VERSION 5.8 ;
BUSBITCHARS "[]" ;
DIVIDERCHAR "/" ;
UNITS
    DATABASE MICRONS 1000 ;
END UNITS

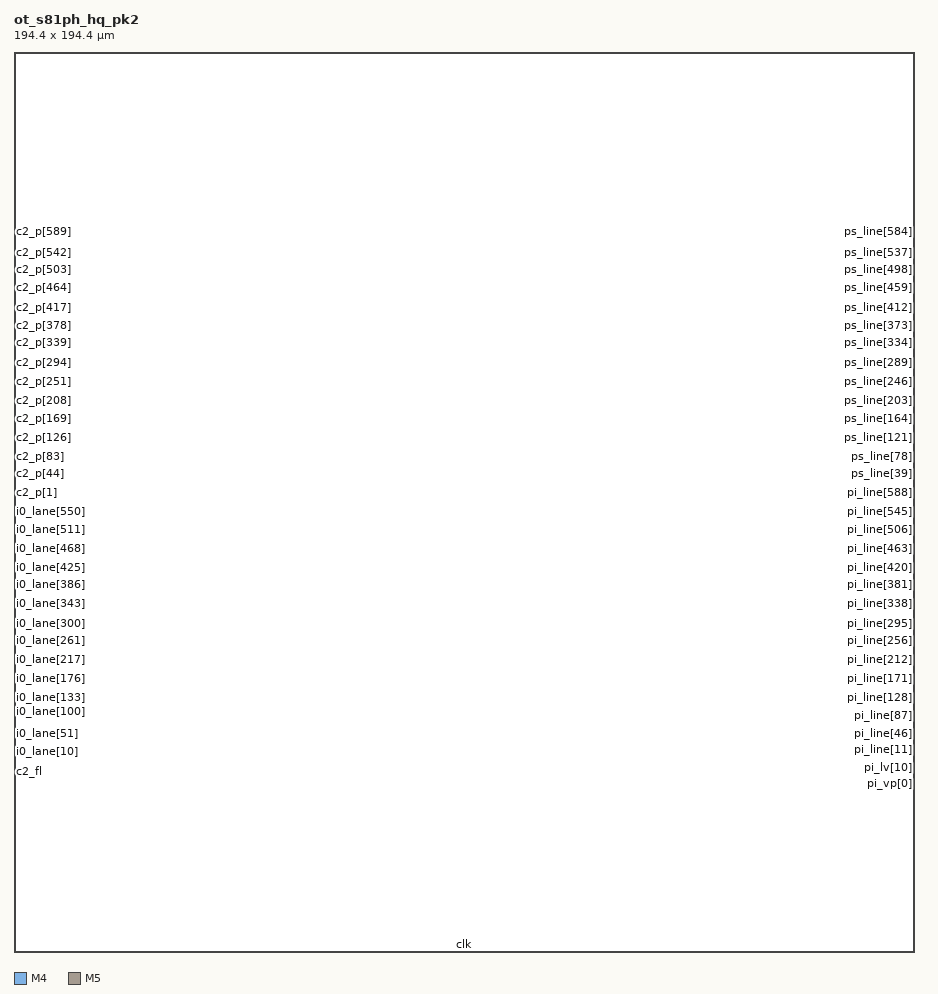
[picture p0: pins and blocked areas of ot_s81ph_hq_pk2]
MACRO ot_s81ph_hq_pk2
  FOREIGN ot_s81ph_hq_pk2 0 0 ;
  CLASS BLOCK ;
  SIZE 194.4 BY 194.4 ;
  PIN c2_fl
    DIRECTION INPUT ;
    USE SIGNAL ;
    PORT
      LAYER M4 ;
        RECT  0 39.072 0.084 39.096 ;
    END
  END c2_fl
  PIN c2_p[0]
    DIRECTION INPUT ;
    USE SIGNAL ;
    PORT
      LAYER M4 ;
        RECT  0 99.072 0.084 99.096 ;
    END
  END c2_p[0]
  PIN c2_p[100]
    DIRECTION INPUT ;
    USE SIGNAL ;
    PORT
      LAYER M4 ;
        RECT  0 108.672 0.084 108.696 ;
    END
  END c2_p[100]
  PIN c2_p[101]
    DIRECTION INPUT ;
    USE SIGNAL ;
    PORT
      LAYER M4 ;
        RECT  0 108.768 0.084 108.792 ;
    END
  END c2_p[101]
  PIN c2_p[102]
    DIRECTION INPUT ;
    USE SIGNAL ;
    PORT
      LAYER M4 ;
        RECT  0 108.864 0.084 108.888 ;
    END
  END c2_p[102]
  PIN c2_p[103]
    DIRECTION INPUT ;
    USE SIGNAL ;
    PORT
      LAYER M4 ;
        RECT  0 108.96 0.084 108.984 ;
    END
  END c2_p[103]
  PIN c2_p[104]
    DIRECTION INPUT ;
    USE SIGNAL ;
    PORT
      LAYER M4 ;
        RECT  0 109.056 0.084 109.08 ;
    END
  END c2_p[104]
  PIN c2_p[105]
    DIRECTION INPUT ;
    USE SIGNAL ;
    PORT
      LAYER M4 ;
        RECT  0 109.152 0.084 109.176 ;
    END
  END c2_p[105]
  PIN c2_p[106]
    DIRECTION INPUT ;
    USE SIGNAL ;
    PORT
      LAYER M4 ;
        RECT  0 109.248 0.084 109.272 ;
    END
  END c2_p[106]
  PIN c2_p[107]
    DIRECTION INPUT ;
    USE SIGNAL ;
    PORT
      LAYER M4 ;
        RECT  0 109.344 0.084 109.368 ;
    END
  END c2_p[107]
  PIN c2_p[108]
    DIRECTION INPUT ;
    USE SIGNAL ;
    PORT
      LAYER M4 ;
        RECT  0 109.44 0.084 109.464 ;
    END
  END c2_p[108]
  PIN c2_p[109]
    DIRECTION INPUT ;
    USE SIGNAL ;
    PORT
      LAYER M4 ;
        RECT  0 109.536 0.084 109.56 ;
    END
  END c2_p[109]
  PIN c2_p[10]
    DIRECTION INPUT ;
    USE SIGNAL ;
    PORT
      LAYER M4 ;
        RECT  0 100.032 0.084 100.056 ;
    END
  END c2_p[10]
  PIN c2_p[110]
    DIRECTION INPUT ;
    USE SIGNAL ;
    PORT
      LAYER M4 ;
        RECT  0 109.632 0.084 109.656 ;
    END
  END c2_p[110]
  PIN c2_p[111]
    DIRECTION INPUT ;
    USE SIGNAL ;
    PORT
      LAYER M4 ;
        RECT  0 109.728 0.084 109.752 ;
    END
  END c2_p[111]
  PIN c2_p[112]
    DIRECTION INPUT ;
    USE SIGNAL ;
    PORT
      LAYER M4 ;
        RECT  0 109.824 0.084 109.848 ;
    END
  END c2_p[112]
  PIN c2_p[113]
    DIRECTION INPUT ;
    USE SIGNAL ;
    PORT
      LAYER M4 ;
        RECT  0 109.92 0.084 109.944 ;
    END
  END c2_p[113]
  PIN c2_p[114]
    DIRECTION INPUT ;
    USE SIGNAL ;
    PORT
      LAYER M4 ;
        RECT  0 110.016 0.084 110.04 ;
    END
  END c2_p[114]
  PIN c2_p[115]
    DIRECTION INPUT ;
    USE SIGNAL ;
    PORT
      LAYER M4 ;
        RECT  0 110.112 0.084 110.136 ;
    END
  END c2_p[115]
  PIN c2_p[116]
    DIRECTION INPUT ;
    USE SIGNAL ;
    PORT
      LAYER M4 ;
        RECT  0 110.208 0.084 110.232 ;
    END
  END c2_p[116]
  PIN c2_p[117]
    DIRECTION INPUT ;
    USE SIGNAL ;
    PORT
      LAYER M4 ;
        RECT  0 110.304 0.084 110.328 ;
    END
  END c2_p[117]
  PIN c2_p[118]
    DIRECTION INPUT ;
    USE SIGNAL ;
    PORT
      LAYER M4 ;
        RECT  0 110.4 0.084 110.424 ;
    END
  END c2_p[118]
  PIN c2_p[119]
    DIRECTION INPUT ;
    USE SIGNAL ;
    PORT
      LAYER M4 ;
        RECT  0 110.496 0.084 110.52 ;
    END
  END c2_p[119]
  PIN c2_p[11]
    DIRECTION INPUT ;
    USE SIGNAL ;
    PORT
      LAYER M4 ;
        RECT  0 100.128 0.084 100.152 ;
    END
  END c2_p[11]
  PIN c2_p[120]
    DIRECTION INPUT ;
    USE SIGNAL ;
    PORT
      LAYER M4 ;
        RECT  0 110.592 0.084 110.616 ;
    END
  END c2_p[120]
  PIN c2_p[121]
    DIRECTION INPUT ;
    USE SIGNAL ;
    PORT
      LAYER M4 ;
        RECT  0 110.688 0.084 110.712 ;
    END
  END c2_p[121]
  PIN c2_p[122]
    DIRECTION INPUT ;
    USE SIGNAL ;
    PORT
      LAYER M4 ;
        RECT  0 110.784 0.084 110.808 ;
    END
  END c2_p[122]
  PIN c2_p[123]
    DIRECTION INPUT ;
    USE SIGNAL ;
    PORT
      LAYER M4 ;
        RECT  0 110.88 0.084 110.904 ;
    END
  END c2_p[123]
  PIN c2_p[124]
    DIRECTION INPUT ;
    USE SIGNAL ;
    PORT
      LAYER M4 ;
        RECT  0 110.976 0.084 111 ;
    END
  END c2_p[124]
  PIN c2_p[125]
    DIRECTION INPUT ;
    USE SIGNAL ;
    PORT
      LAYER M4 ;
        RECT  0 111.072 0.084 111.096 ;
    END
  END c2_p[125]
  PIN c2_p[126]
    DIRECTION INPUT ;
    USE SIGNAL ;
    PORT
      LAYER M4 ;
        RECT  0 111.168 0.084 111.192 ;
    END
  END c2_p[126]
  PIN c2_p[127]
    DIRECTION INPUT ;
    USE SIGNAL ;
    PORT
      LAYER M4 ;
        RECT  0 111.264 0.084 111.288 ;
    END
  END c2_p[127]
  PIN c2_p[128]
    DIRECTION INPUT ;
    USE SIGNAL ;
    PORT
      LAYER M4 ;
        RECT  0 111.36 0.084 111.384 ;
    END
  END c2_p[128]
  PIN c2_p[129]
    DIRECTION INPUT ;
    USE SIGNAL ;
    PORT
      LAYER M4 ;
        RECT  0 111.456 0.084 111.48 ;
    END
  END c2_p[129]
  PIN c2_p[12]
    DIRECTION INPUT ;
    USE SIGNAL ;
    PORT
      LAYER M4 ;
        RECT  0 100.224 0.084 100.248 ;
    END
  END c2_p[12]
  PIN c2_p[130]
    DIRECTION INPUT ;
    USE SIGNAL ;
    PORT
      LAYER M4 ;
        RECT  0 111.552 0.084 111.576 ;
    END
  END c2_p[130]
  PIN c2_p[131]
    DIRECTION INPUT ;
    USE SIGNAL ;
    PORT
      LAYER M4 ;
        RECT  0 111.648 0.084 111.672 ;
    END
  END c2_p[131]
  PIN c2_p[132]
    DIRECTION INPUT ;
    USE SIGNAL ;
    PORT
      LAYER M4 ;
        RECT  0 111.744 0.084 111.768 ;
    END
  END c2_p[132]
  PIN c2_p[133]
    DIRECTION INPUT ;
    USE SIGNAL ;
    PORT
      LAYER M4 ;
        RECT  0 111.84 0.084 111.864 ;
    END
  END c2_p[133]
  PIN c2_p[134]
    DIRECTION INPUT ;
    USE SIGNAL ;
    PORT
      LAYER M4 ;
        RECT  0 111.936 0.084 111.96 ;
    END
  END c2_p[134]
  PIN c2_p[135]
    DIRECTION INPUT ;
    USE SIGNAL ;
    PORT
      LAYER M4 ;
        RECT  0 112.032 0.084 112.056 ;
    END
  END c2_p[135]
  PIN c2_p[136]
    DIRECTION INPUT ;
    USE SIGNAL ;
    PORT
      LAYER M4 ;
        RECT  0 112.128 0.084 112.152 ;
    END
  END c2_p[136]
  PIN c2_p[137]
    DIRECTION INPUT ;
    USE SIGNAL ;
    PORT
      LAYER M4 ;
        RECT  0 112.224 0.084 112.248 ;
    END
  END c2_p[137]
  PIN c2_p[138]
    DIRECTION INPUT ;
    USE SIGNAL ;
    PORT
      LAYER M4 ;
        RECT  0 112.32 0.084 112.344 ;
    END
  END c2_p[138]
  PIN c2_p[139]
    DIRECTION INPUT ;
    USE SIGNAL ;
    PORT
      LAYER M4 ;
        RECT  0 112.416 0.084 112.44 ;
    END
  END c2_p[139]
  PIN c2_p[13]
    DIRECTION INPUT ;
    USE SIGNAL ;
    PORT
      LAYER M4 ;
        RECT  0 100.32 0.084 100.344 ;
    END
  END c2_p[13]
  PIN c2_p[140]
    DIRECTION INPUT ;
    USE SIGNAL ;
    PORT
      LAYER M4 ;
        RECT  0 112.512 0.084 112.536 ;
    END
  END c2_p[140]
  PIN c2_p[141]
    DIRECTION INPUT ;
    USE SIGNAL ;
    PORT
      LAYER M4 ;
        RECT  0 112.608 0.084 112.632 ;
    END
  END c2_p[141]
  PIN c2_p[142]
    DIRECTION INPUT ;
    USE SIGNAL ;
    PORT
      LAYER M4 ;
        RECT  0 112.704 0.084 112.728 ;
    END
  END c2_p[142]
  PIN c2_p[143]
    DIRECTION INPUT ;
    USE SIGNAL ;
    PORT
      LAYER M4 ;
        RECT  0 112.8 0.084 112.824 ;
    END
  END c2_p[143]
  PIN c2_p[144]
    DIRECTION INPUT ;
    USE SIGNAL ;
    PORT
      LAYER M4 ;
        RECT  0 112.896 0.084 112.92 ;
    END
  END c2_p[144]
  PIN c2_p[145]
    DIRECTION INPUT ;
    USE SIGNAL ;
    PORT
      LAYER M4 ;
        RECT  0 112.992 0.084 113.016 ;
    END
  END c2_p[145]
  PIN c2_p[146]
    DIRECTION INPUT ;
    USE SIGNAL ;
    PORT
      LAYER M4 ;
        RECT  0 113.088 0.084 113.112 ;
    END
  END c2_p[146]
  PIN c2_p[147]
    DIRECTION INPUT ;
    USE SIGNAL ;
    PORT
      LAYER M4 ;
        RECT  0 113.184 0.084 113.208 ;
    END
  END c2_p[147]
  PIN c2_p[148]
    DIRECTION INPUT ;
    USE SIGNAL ;
    PORT
      LAYER M4 ;
        RECT  0 113.28 0.084 113.304 ;
    END
  END c2_p[148]
  PIN c2_p[149]
    DIRECTION INPUT ;
    USE SIGNAL ;
    PORT
      LAYER M4 ;
        RECT  0 113.376 0.084 113.4 ;
    END
  END c2_p[149]
  PIN c2_p[14]
    DIRECTION INPUT ;
    USE SIGNAL ;
    PORT
      LAYER M4 ;
        RECT  0 100.416 0.084 100.44 ;
    END
  END c2_p[14]
  PIN c2_p[150]
    DIRECTION INPUT ;
    USE SIGNAL ;
    PORT
      LAYER M4 ;
        RECT  0 113.472 0.084 113.496 ;
    END
  END c2_p[150]
  PIN c2_p[151]
    DIRECTION INPUT ;
    USE SIGNAL ;
    PORT
      LAYER M4 ;
        RECT  0 113.568 0.084 113.592 ;
    END
  END c2_p[151]
  PIN c2_p[152]
    DIRECTION INPUT ;
    USE SIGNAL ;
    PORT
      LAYER M4 ;
        RECT  0 113.664 0.084 113.688 ;
    END
  END c2_p[152]
  PIN c2_p[153]
    DIRECTION INPUT ;
    USE SIGNAL ;
    PORT
      LAYER M4 ;
        RECT  0 113.76 0.084 113.784 ;
    END
  END c2_p[153]
  PIN c2_p[154]
    DIRECTION INPUT ;
    USE SIGNAL ;
    PORT
      LAYER M4 ;
        RECT  0 113.856 0.084 113.88 ;
    END
  END c2_p[154]
  PIN c2_p[155]
    DIRECTION INPUT ;
    USE SIGNAL ;
    PORT
      LAYER M4 ;
        RECT  0 113.952 0.084 113.976 ;
    END
  END c2_p[155]
  PIN c2_p[156]
    DIRECTION INPUT ;
    USE SIGNAL ;
    PORT
      LAYER M4 ;
        RECT  0 114.048 0.084 114.072 ;
    END
  END c2_p[156]
  PIN c2_p[157]
    DIRECTION INPUT ;
    USE SIGNAL ;
    PORT
      LAYER M4 ;
        RECT  0 114.144 0.084 114.168 ;
    END
  END c2_p[157]
  PIN c2_p[158]
    DIRECTION INPUT ;
    USE SIGNAL ;
    PORT
      LAYER M4 ;
        RECT  0 114.24 0.084 114.264 ;
    END
  END c2_p[158]
  PIN c2_p[159]
    DIRECTION INPUT ;
    USE SIGNAL ;
    PORT
      LAYER M4 ;
        RECT  0 114.336 0.084 114.36 ;
    END
  END c2_p[159]
  PIN c2_p[15]
    DIRECTION INPUT ;
    USE SIGNAL ;
    PORT
      LAYER M4 ;
        RECT  0 100.512 0.084 100.536 ;
    END
  END c2_p[15]
  PIN c2_p[160]
    DIRECTION INPUT ;
    USE SIGNAL ;
    PORT
      LAYER M4 ;
        RECT  0 114.432 0.084 114.456 ;
    END
  END c2_p[160]
  PIN c2_p[161]
    DIRECTION INPUT ;
    USE SIGNAL ;
    PORT
      LAYER M4 ;
        RECT  0 114.528 0.084 114.552 ;
    END
  END c2_p[161]
  PIN c2_p[162]
    DIRECTION INPUT ;
    USE SIGNAL ;
    PORT
      LAYER M4 ;
        RECT  0 114.624 0.084 114.648 ;
    END
  END c2_p[162]
  PIN c2_p[163]
    DIRECTION INPUT ;
    USE SIGNAL ;
    PORT
      LAYER M4 ;
        RECT  0 114.72 0.084 114.744 ;
    END
  END c2_p[163]
  PIN c2_p[164]
    DIRECTION INPUT ;
    USE SIGNAL ;
    PORT
      LAYER M4 ;
        RECT  0 114.816 0.084 114.84 ;
    END
  END c2_p[164]
  PIN c2_p[165]
    DIRECTION INPUT ;
    USE SIGNAL ;
    PORT
      LAYER M4 ;
        RECT  0 114.912 0.084 114.936 ;
    END
  END c2_p[165]
  PIN c2_p[166]
    DIRECTION INPUT ;
    USE SIGNAL ;
    PORT
      LAYER M4 ;
        RECT  0 115.008 0.084 115.032 ;
    END
  END c2_p[166]
  PIN c2_p[167]
    DIRECTION INPUT ;
    USE SIGNAL ;
    PORT
      LAYER M4 ;
        RECT  0 115.104 0.084 115.128 ;
    END
  END c2_p[167]
  PIN c2_p[168]
    DIRECTION INPUT ;
    USE SIGNAL ;
    PORT
      LAYER M4 ;
        RECT  0 115.2 0.084 115.224 ;
    END
  END c2_p[168]
  PIN c2_p[169]
    DIRECTION INPUT ;
    USE SIGNAL ;
    PORT
      LAYER M4 ;
        RECT  0 115.296 0.084 115.32 ;
    END
  END c2_p[169]
  PIN c2_p[16]
    DIRECTION INPUT ;
    USE SIGNAL ;
    PORT
      LAYER M4 ;
        RECT  0 100.608 0.084 100.632 ;
    END
  END c2_p[16]
  PIN c2_p[170]
    DIRECTION INPUT ;
    USE SIGNAL ;
    PORT
      LAYER M4 ;
        RECT  0 115.392 0.084 115.416 ;
    END
  END c2_p[170]
  PIN c2_p[171]
    DIRECTION INPUT ;
    USE SIGNAL ;
    PORT
      LAYER M4 ;
        RECT  0 115.488 0.084 115.512 ;
    END
  END c2_p[171]
  PIN c2_p[172]
    DIRECTION INPUT ;
    USE SIGNAL ;
    PORT
      LAYER M4 ;
        RECT  0 115.584 0.084 115.608 ;
    END
  END c2_p[172]
  PIN c2_p[173]
    DIRECTION INPUT ;
    USE SIGNAL ;
    PORT
      LAYER M4 ;
        RECT  0 115.68 0.084 115.704 ;
    END
  END c2_p[173]
  PIN c2_p[174]
    DIRECTION INPUT ;
    USE SIGNAL ;
    PORT
      LAYER M4 ;
        RECT  0 115.776 0.084 115.8 ;
    END
  END c2_p[174]
  PIN c2_p[175]
    DIRECTION INPUT ;
    USE SIGNAL ;
    PORT
      LAYER M4 ;
        RECT  0 115.872 0.084 115.896 ;
    END
  END c2_p[175]
  PIN c2_p[176]
    DIRECTION INPUT ;
    USE SIGNAL ;
    PORT
      LAYER M4 ;
        RECT  0 115.968 0.084 115.992 ;
    END
  END c2_p[176]
  PIN c2_p[177]
    DIRECTION INPUT ;
    USE SIGNAL ;
    PORT
      LAYER M4 ;
        RECT  0 116.064 0.084 116.088 ;
    END
  END c2_p[177]
  PIN c2_p[178]
    DIRECTION INPUT ;
    USE SIGNAL ;
    PORT
      LAYER M4 ;
        RECT  0 116.16 0.084 116.184 ;
    END
  END c2_p[178]
  PIN c2_p[179]
    DIRECTION INPUT ;
    USE SIGNAL ;
    PORT
      LAYER M4 ;
        RECT  0 116.256 0.084 116.28 ;
    END
  END c2_p[179]
  PIN c2_p[17]
    DIRECTION INPUT ;
    USE SIGNAL ;
    PORT
      LAYER M4 ;
        RECT  0 100.704 0.084 100.728 ;
    END
  END c2_p[17]
  PIN c2_p[180]
    DIRECTION INPUT ;
    USE SIGNAL ;
    PORT
      LAYER M4 ;
        RECT  0 116.352 0.084 116.376 ;
    END
  END c2_p[180]
  PIN c2_p[181]
    DIRECTION INPUT ;
    USE SIGNAL ;
    PORT
      LAYER M4 ;
        RECT  0 116.448 0.084 116.472 ;
    END
  END c2_p[181]
  PIN c2_p[182]
    DIRECTION INPUT ;
    USE SIGNAL ;
    PORT
      LAYER M4 ;
        RECT  0 116.544 0.084 116.568 ;
    END
  END c2_p[182]
  PIN c2_p[183]
    DIRECTION INPUT ;
    USE SIGNAL ;
    PORT
      LAYER M4 ;
        RECT  0 116.64 0.084 116.664 ;
    END
  END c2_p[183]
  PIN c2_p[184]
    DIRECTION INPUT ;
    USE SIGNAL ;
    PORT
      LAYER M4 ;
        RECT  0 116.736 0.084 116.76 ;
    END
  END c2_p[184]
  PIN c2_p[185]
    DIRECTION INPUT ;
    USE SIGNAL ;
    PORT
      LAYER M4 ;
        RECT  0 116.832 0.084 116.856 ;
    END
  END c2_p[185]
  PIN c2_p[186]
    DIRECTION INPUT ;
    USE SIGNAL ;
    PORT
      LAYER M4 ;
        RECT  0 116.928 0.084 116.952 ;
    END
  END c2_p[186]
  PIN c2_p[187]
    DIRECTION INPUT ;
    USE SIGNAL ;
    PORT
      LAYER M4 ;
        RECT  0 117.024 0.084 117.048 ;
    END
  END c2_p[187]
  PIN c2_p[188]
    DIRECTION INPUT ;
    USE SIGNAL ;
    PORT
      LAYER M4 ;
        RECT  0 117.12 0.084 117.144 ;
    END
  END c2_p[188]
  PIN c2_p[189]
    DIRECTION INPUT ;
    USE SIGNAL ;
    PORT
      LAYER M4 ;
        RECT  0 117.216 0.084 117.24 ;
    END
  END c2_p[189]
  PIN c2_p[18]
    DIRECTION INPUT ;
    USE SIGNAL ;
    PORT
      LAYER M4 ;
        RECT  0 100.8 0.084 100.824 ;
    END
  END c2_p[18]
  PIN c2_p[190]
    DIRECTION INPUT ;
    USE SIGNAL ;
    PORT
      LAYER M4 ;
        RECT  0 117.312 0.084 117.336 ;
    END
  END c2_p[190]
  PIN c2_p[191]
    DIRECTION INPUT ;
    USE SIGNAL ;
    PORT
      LAYER M4 ;
        RECT  0 117.408 0.084 117.432 ;
    END
  END c2_p[191]
  PIN c2_p[192]
    DIRECTION INPUT ;
    USE SIGNAL ;
    PORT
      LAYER M4 ;
        RECT  0 117.504 0.084 117.528 ;
    END
  END c2_p[192]
  PIN c2_p[193]
    DIRECTION INPUT ;
    USE SIGNAL ;
    PORT
      LAYER M4 ;
        RECT  0 117.6 0.084 117.624 ;
    END
  END c2_p[193]
  PIN c2_p[194]
    DIRECTION INPUT ;
    USE SIGNAL ;
    PORT
      LAYER M4 ;
        RECT  0 117.696 0.084 117.72 ;
    END
  END c2_p[194]
  PIN c2_p[195]
    DIRECTION INPUT ;
    USE SIGNAL ;
    PORT
      LAYER M4 ;
        RECT  0 117.792 0.084 117.816 ;
    END
  END c2_p[195]
  PIN c2_p[196]
    DIRECTION INPUT ;
    USE SIGNAL ;
    PORT
      LAYER M4 ;
        RECT  0 117.888 0.084 117.912 ;
    END
  END c2_p[196]
  PIN c2_p[197]
    DIRECTION INPUT ;
    USE SIGNAL ;
    PORT
      LAYER M4 ;
        RECT  0 117.984 0.084 118.008 ;
    END
  END c2_p[197]
  PIN c2_p[198]
    DIRECTION INPUT ;
    USE SIGNAL ;
    PORT
      LAYER M4 ;
        RECT  0 118.08 0.084 118.104 ;
    END
  END c2_p[198]
  PIN c2_p[199]
    DIRECTION INPUT ;
    USE SIGNAL ;
    PORT
      LAYER M4 ;
        RECT  0 118.176 0.084 118.2 ;
    END
  END c2_p[199]
  PIN c2_p[19]
    DIRECTION INPUT ;
    USE SIGNAL ;
    PORT
      LAYER M4 ;
        RECT  0 100.896 0.084 100.92 ;
    END
  END c2_p[19]
  PIN c2_p[1]
    DIRECTION INPUT ;
    USE SIGNAL ;
    PORT
      LAYER M4 ;
        RECT  0 99.168 0.084 99.192 ;
    END
  END c2_p[1]
  PIN c2_p[200]
    DIRECTION INPUT ;
    USE SIGNAL ;
    PORT
      LAYER M4 ;
        RECT  0 118.272 0.084 118.296 ;
    END
  END c2_p[200]
  PIN c2_p[201]
    DIRECTION INPUT ;
    USE SIGNAL ;
    PORT
      LAYER M4 ;
        RECT  0 118.368 0.084 118.392 ;
    END
  END c2_p[201]
  PIN c2_p[202]
    DIRECTION INPUT ;
    USE SIGNAL ;
    PORT
      LAYER M4 ;
        RECT  0 118.464 0.084 118.488 ;
    END
  END c2_p[202]
  PIN c2_p[203]
    DIRECTION INPUT ;
    USE SIGNAL ;
    PORT
      LAYER M4 ;
        RECT  0 118.56 0.084 118.584 ;
    END
  END c2_p[203]
  PIN c2_p[204]
    DIRECTION INPUT ;
    USE SIGNAL ;
    PORT
      LAYER M4 ;
        RECT  0 118.656 0.084 118.68 ;
    END
  END c2_p[204]
  PIN c2_p[205]
    DIRECTION INPUT ;
    USE SIGNAL ;
    PORT
      LAYER M4 ;
        RECT  0 118.752 0.084 118.776 ;
    END
  END c2_p[205]
  PIN c2_p[206]
    DIRECTION INPUT ;
    USE SIGNAL ;
    PORT
      LAYER M4 ;
        RECT  0 118.848 0.084 118.872 ;
    END
  END c2_p[206]
  PIN c2_p[207]
    DIRECTION INPUT ;
    USE SIGNAL ;
    PORT
      LAYER M4 ;
        RECT  0 118.944 0.084 118.968 ;
    END
  END c2_p[207]
  PIN c2_p[208]
    DIRECTION INPUT ;
    USE SIGNAL ;
    PORT
      LAYER M4 ;
        RECT  0 119.04 0.084 119.064 ;
    END
  END c2_p[208]
  PIN c2_p[209]
    DIRECTION INPUT ;
    USE SIGNAL ;
    PORT
      LAYER M4 ;
        RECT  0 119.136 0.084 119.16 ;
    END
  END c2_p[209]
  PIN c2_p[20]
    DIRECTION INPUT ;
    USE SIGNAL ;
    PORT
      LAYER M4 ;
        RECT  0 100.992 0.084 101.016 ;
    END
  END c2_p[20]
  PIN c2_p[210]
    DIRECTION INPUT ;
    USE SIGNAL ;
    PORT
      LAYER M4 ;
        RECT  0 119.232 0.084 119.256 ;
    END
  END c2_p[210]
  PIN c2_p[211]
    DIRECTION INPUT ;
    USE SIGNAL ;
    PORT
      LAYER M4 ;
        RECT  0 119.328 0.084 119.352 ;
    END
  END c2_p[211]
  PIN c2_p[212]
    DIRECTION INPUT ;
    USE SIGNAL ;
    PORT
      LAYER M4 ;
        RECT  0 119.424 0.084 119.448 ;
    END
  END c2_p[212]
  PIN c2_p[213]
    DIRECTION INPUT ;
    USE SIGNAL ;
    PORT
      LAYER M4 ;
        RECT  0 119.52 0.084 119.544 ;
    END
  END c2_p[213]
  PIN c2_p[214]
    DIRECTION INPUT ;
    USE SIGNAL ;
    PORT
      LAYER M4 ;
        RECT  0 119.616 0.084 119.64 ;
    END
  END c2_p[214]
  PIN c2_p[215]
    DIRECTION INPUT ;
    USE SIGNAL ;
    PORT
      LAYER M4 ;
        RECT  0 119.712 0.084 119.736 ;
    END
  END c2_p[215]
  PIN c2_p[216]
    DIRECTION INPUT ;
    USE SIGNAL ;
    PORT
      LAYER M4 ;
        RECT  0 119.808 0.084 119.832 ;
    END
  END c2_p[216]
  PIN c2_p[217]
    DIRECTION INPUT ;
    USE SIGNAL ;
    PORT
      LAYER M4 ;
        RECT  0 119.904 0.084 119.928 ;
    END
  END c2_p[217]
  PIN c2_p[218]
    DIRECTION INPUT ;
    USE SIGNAL ;
    PORT
      LAYER M4 ;
        RECT  0 120 0.084 120.024 ;
    END
  END c2_p[218]
  PIN c2_p[219]
    DIRECTION INPUT ;
    USE SIGNAL ;
    PORT
      LAYER M4 ;
        RECT  0 120.096 0.084 120.12 ;
    END
  END c2_p[219]
  PIN c2_p[21]
    DIRECTION INPUT ;
    USE SIGNAL ;
    PORT
      LAYER M4 ;
        RECT  0 101.088 0.084 101.112 ;
    END
  END c2_p[21]
  PIN c2_p[220]
    DIRECTION INPUT ;
    USE SIGNAL ;
    PORT
      LAYER M4 ;
        RECT  0 120.192 0.084 120.216 ;
    END
  END c2_p[220]
  PIN c2_p[221]
    DIRECTION INPUT ;
    USE SIGNAL ;
    PORT
      LAYER M4 ;
        RECT  0 120.288 0.084 120.312 ;
    END
  END c2_p[221]
  PIN c2_p[222]
    DIRECTION INPUT ;
    USE SIGNAL ;
    PORT
      LAYER M4 ;
        RECT  0 120.384 0.084 120.408 ;
    END
  END c2_p[222]
  PIN c2_p[223]
    DIRECTION INPUT ;
    USE SIGNAL ;
    PORT
      LAYER M4 ;
        RECT  0 120.48 0.084 120.504 ;
    END
  END c2_p[223]
  PIN c2_p[224]
    DIRECTION INPUT ;
    USE SIGNAL ;
    PORT
      LAYER M4 ;
        RECT  0 120.576 0.084 120.6 ;
    END
  END c2_p[224]
  PIN c2_p[225]
    DIRECTION INPUT ;
    USE SIGNAL ;
    PORT
      LAYER M4 ;
        RECT  0 120.672 0.084 120.696 ;
    END
  END c2_p[225]
  PIN c2_p[226]
    DIRECTION INPUT ;
    USE SIGNAL ;
    PORT
      LAYER M4 ;
        RECT  0 120.768 0.084 120.792 ;
    END
  END c2_p[226]
  PIN c2_p[227]
    DIRECTION INPUT ;
    USE SIGNAL ;
    PORT
      LAYER M4 ;
        RECT  0 120.864 0.084 120.888 ;
    END
  END c2_p[227]
  PIN c2_p[228]
    DIRECTION INPUT ;
    USE SIGNAL ;
    PORT
      LAYER M4 ;
        RECT  0 120.96 0.084 120.984 ;
    END
  END c2_p[228]
  PIN c2_p[229]
    DIRECTION INPUT ;
    USE SIGNAL ;
    PORT
      LAYER M4 ;
        RECT  0 121.056 0.084 121.08 ;
    END
  END c2_p[229]
  PIN c2_p[22]
    DIRECTION INPUT ;
    USE SIGNAL ;
    PORT
      LAYER M4 ;
        RECT  0 101.184 0.084 101.208 ;
    END
  END c2_p[22]
  PIN c2_p[230]
    DIRECTION INPUT ;
    USE SIGNAL ;
    PORT
      LAYER M4 ;
        RECT  0 121.152 0.084 121.176 ;
    END
  END c2_p[230]
  PIN c2_p[231]
    DIRECTION INPUT ;
    USE SIGNAL ;
    PORT
      LAYER M4 ;
        RECT  0 121.248 0.084 121.272 ;
    END
  END c2_p[231]
  PIN c2_p[232]
    DIRECTION INPUT ;
    USE SIGNAL ;
    PORT
      LAYER M4 ;
        RECT  0 121.344 0.084 121.368 ;
    END
  END c2_p[232]
  PIN c2_p[233]
    DIRECTION INPUT ;
    USE SIGNAL ;
    PORT
      LAYER M4 ;
        RECT  0 121.44 0.084 121.464 ;
    END
  END c2_p[233]
  PIN c2_p[234]
    DIRECTION INPUT ;
    USE SIGNAL ;
    PORT
      LAYER M4 ;
        RECT  0 121.536 0.084 121.56 ;
    END
  END c2_p[234]
  PIN c2_p[235]
    DIRECTION INPUT ;
    USE SIGNAL ;
    PORT
      LAYER M4 ;
        RECT  0 121.632 0.084 121.656 ;
    END
  END c2_p[235]
  PIN c2_p[236]
    DIRECTION INPUT ;
    USE SIGNAL ;
    PORT
      LAYER M4 ;
        RECT  0 121.728 0.084 121.752 ;
    END
  END c2_p[236]
  PIN c2_p[237]
    DIRECTION INPUT ;
    USE SIGNAL ;
    PORT
      LAYER M4 ;
        RECT  0 121.824 0.084 121.848 ;
    END
  END c2_p[237]
  PIN c2_p[238]
    DIRECTION INPUT ;
    USE SIGNAL ;
    PORT
      LAYER M4 ;
        RECT  0 121.92 0.084 121.944 ;
    END
  END c2_p[238]
  PIN c2_p[239]
    DIRECTION INPUT ;
    USE SIGNAL ;
    PORT
      LAYER M4 ;
        RECT  0 122.016 0.084 122.04 ;
    END
  END c2_p[239]
  PIN c2_p[23]
    DIRECTION INPUT ;
    USE SIGNAL ;
    PORT
      LAYER M4 ;
        RECT  0 101.28 0.084 101.304 ;
    END
  END c2_p[23]
  PIN c2_p[240]
    DIRECTION INPUT ;
    USE SIGNAL ;
    PORT
      LAYER M4 ;
        RECT  0 122.112 0.084 122.136 ;
    END
  END c2_p[240]
  PIN c2_p[241]
    DIRECTION INPUT ;
    USE SIGNAL ;
    PORT
      LAYER M4 ;
        RECT  0 122.208 0.084 122.232 ;
    END
  END c2_p[241]
  PIN c2_p[242]
    DIRECTION INPUT ;
    USE SIGNAL ;
    PORT
      LAYER M4 ;
        RECT  0 122.304 0.084 122.328 ;
    END
  END c2_p[242]
  PIN c2_p[243]
    DIRECTION INPUT ;
    USE SIGNAL ;
    PORT
      LAYER M4 ;
        RECT  0 122.4 0.084 122.424 ;
    END
  END c2_p[243]
  PIN c2_p[244]
    DIRECTION INPUT ;
    USE SIGNAL ;
    PORT
      LAYER M4 ;
        RECT  0 122.496 0.084 122.52 ;
    END
  END c2_p[244]
  PIN c2_p[245]
    DIRECTION INPUT ;
    USE SIGNAL ;
    PORT
      LAYER M4 ;
        RECT  0 122.592 0.084 122.616 ;
    END
  END c2_p[245]
  PIN c2_p[246]
    DIRECTION INPUT ;
    USE SIGNAL ;
    PORT
      LAYER M4 ;
        RECT  0 122.688 0.084 122.712 ;
    END
  END c2_p[246]
  PIN c2_p[247]
    DIRECTION INPUT ;
    USE SIGNAL ;
    PORT
      LAYER M4 ;
        RECT  0 122.784 0.084 122.808 ;
    END
  END c2_p[247]
  PIN c2_p[248]
    DIRECTION INPUT ;
    USE SIGNAL ;
    PORT
      LAYER M4 ;
        RECT  0 122.88 0.084 122.904 ;
    END
  END c2_p[248]
  PIN c2_p[249]
    DIRECTION INPUT ;
    USE SIGNAL ;
    PORT
      LAYER M4 ;
        RECT  0 122.976 0.084 123 ;
    END
  END c2_p[249]
  PIN c2_p[24]
    DIRECTION INPUT ;
    USE SIGNAL ;
    PORT
      LAYER M4 ;
        RECT  0 101.376 0.084 101.4 ;
    END
  END c2_p[24]
  PIN c2_p[250]
    DIRECTION INPUT ;
    USE SIGNAL ;
    PORT
      LAYER M4 ;
        RECT  0 123.072 0.084 123.096 ;
    END
  END c2_p[250]
  PIN c2_p[251]
    DIRECTION INPUT ;
    USE SIGNAL ;
    PORT
      LAYER M4 ;
        RECT  0 123.168 0.084 123.192 ;
    END
  END c2_p[251]
  PIN c2_p[252]
    DIRECTION INPUT ;
    USE SIGNAL ;
    PORT
      LAYER M4 ;
        RECT  0 123.264 0.084 123.288 ;
    END
  END c2_p[252]
  PIN c2_p[253]
    DIRECTION INPUT ;
    USE SIGNAL ;
    PORT
      LAYER M4 ;
        RECT  0 123.36 0.084 123.384 ;
    END
  END c2_p[253]
  PIN c2_p[254]
    DIRECTION INPUT ;
    USE SIGNAL ;
    PORT
      LAYER M4 ;
        RECT  0 123.456 0.084 123.48 ;
    END
  END c2_p[254]
  PIN c2_p[255]
    DIRECTION INPUT ;
    USE SIGNAL ;
    PORT
      LAYER M4 ;
        RECT  0 123.552 0.084 123.576 ;
    END
  END c2_p[255]
  PIN c2_p[256]
    DIRECTION INPUT ;
    USE SIGNAL ;
    PORT
      LAYER M4 ;
        RECT  0 123.648 0.084 123.672 ;
    END
  END c2_p[256]
  PIN c2_p[257]
    DIRECTION INPUT ;
    USE SIGNAL ;
    PORT
      LAYER M4 ;
        RECT  0 123.744 0.084 123.768 ;
    END
  END c2_p[257]
  PIN c2_p[258]
    DIRECTION INPUT ;
    USE SIGNAL ;
    PORT
      LAYER M4 ;
        RECT  0 123.84 0.084 123.864 ;
    END
  END c2_p[258]
  PIN c2_p[259]
    DIRECTION INPUT ;
    USE SIGNAL ;
    PORT
      LAYER M4 ;
        RECT  0 123.936 0.084 123.96 ;
    END
  END c2_p[259]
  PIN c2_p[25]
    DIRECTION INPUT ;
    USE SIGNAL ;
    PORT
      LAYER M4 ;
        RECT  0 101.472 0.084 101.496 ;
    END
  END c2_p[25]
  PIN c2_p[260]
    DIRECTION INPUT ;
    USE SIGNAL ;
    PORT
      LAYER M4 ;
        RECT  0 124.032 0.084 124.056 ;
    END
  END c2_p[260]
  PIN c2_p[261]
    DIRECTION INPUT ;
    USE SIGNAL ;
    PORT
      LAYER M4 ;
        RECT  0 124.128 0.084 124.152 ;
    END
  END c2_p[261]
  PIN c2_p[262]
    DIRECTION INPUT ;
    USE SIGNAL ;
    PORT
      LAYER M4 ;
        RECT  0 124.224 0.084 124.248 ;
    END
  END c2_p[262]
  PIN c2_p[263]
    DIRECTION INPUT ;
    USE SIGNAL ;
    PORT
      LAYER M4 ;
        RECT  0 124.32 0.084 124.344 ;
    END
  END c2_p[263]
  PIN c2_p[264]
    DIRECTION INPUT ;
    USE SIGNAL ;
    PORT
      LAYER M4 ;
        RECT  0 124.416 0.084 124.44 ;
    END
  END c2_p[264]
  PIN c2_p[265]
    DIRECTION INPUT ;
    USE SIGNAL ;
    PORT
      LAYER M4 ;
        RECT  0 124.512 0.084 124.536 ;
    END
  END c2_p[265]
  PIN c2_p[266]
    DIRECTION INPUT ;
    USE SIGNAL ;
    PORT
      LAYER M4 ;
        RECT  0 124.608 0.084 124.632 ;
    END
  END c2_p[266]
  PIN c2_p[267]
    DIRECTION INPUT ;
    USE SIGNAL ;
    PORT
      LAYER M4 ;
        RECT  0 124.704 0.084 124.728 ;
    END
  END c2_p[267]
  PIN c2_p[268]
    DIRECTION INPUT ;
    USE SIGNAL ;
    PORT
      LAYER M4 ;
        RECT  0 124.8 0.084 124.824 ;
    END
  END c2_p[268]
  PIN c2_p[269]
    DIRECTION INPUT ;
    USE SIGNAL ;
    PORT
      LAYER M4 ;
        RECT  0 124.896 0.084 124.92 ;
    END
  END c2_p[269]
  PIN c2_p[26]
    DIRECTION INPUT ;
    USE SIGNAL ;
    PORT
      LAYER M4 ;
        RECT  0 101.568 0.084 101.592 ;
    END
  END c2_p[26]
  PIN c2_p[270]
    DIRECTION INPUT ;
    USE SIGNAL ;
    PORT
      LAYER M4 ;
        RECT  0 124.992 0.084 125.016 ;
    END
  END c2_p[270]
  PIN c2_p[271]
    DIRECTION INPUT ;
    USE SIGNAL ;
    PORT
      LAYER M4 ;
        RECT  0 125.088 0.084 125.112 ;
    END
  END c2_p[271]
  PIN c2_p[272]
    DIRECTION INPUT ;
    USE SIGNAL ;
    PORT
      LAYER M4 ;
        RECT  0 125.184 0.084 125.208 ;
    END
  END c2_p[272]
  PIN c2_p[273]
    DIRECTION INPUT ;
    USE SIGNAL ;
    PORT
      LAYER M4 ;
        RECT  0 125.28 0.084 125.304 ;
    END
  END c2_p[273]
  PIN c2_p[274]
    DIRECTION INPUT ;
    USE SIGNAL ;
    PORT
      LAYER M4 ;
        RECT  0 125.376 0.084 125.4 ;
    END
  END c2_p[274]
  PIN c2_p[275]
    DIRECTION INPUT ;
    USE SIGNAL ;
    PORT
      LAYER M4 ;
        RECT  0 125.472 0.084 125.496 ;
    END
  END c2_p[275]
  PIN c2_p[276]
    DIRECTION INPUT ;
    USE SIGNAL ;
    PORT
      LAYER M4 ;
        RECT  0 125.568 0.084 125.592 ;
    END
  END c2_p[276]
  PIN c2_p[277]
    DIRECTION INPUT ;
    USE SIGNAL ;
    PORT
      LAYER M4 ;
        RECT  0 125.664 0.084 125.688 ;
    END
  END c2_p[277]
  PIN c2_p[278]
    DIRECTION INPUT ;
    USE SIGNAL ;
    PORT
      LAYER M4 ;
        RECT  0 125.76 0.084 125.784 ;
    END
  END c2_p[278]
  PIN c2_p[279]
    DIRECTION INPUT ;
    USE SIGNAL ;
    PORT
      LAYER M4 ;
        RECT  0 125.856 0.084 125.88 ;
    END
  END c2_p[279]
  PIN c2_p[27]
    DIRECTION INPUT ;
    USE SIGNAL ;
    PORT
      LAYER M4 ;
        RECT  0 101.664 0.084 101.688 ;
    END
  END c2_p[27]
  PIN c2_p[280]
    DIRECTION INPUT ;
    USE SIGNAL ;
    PORT
      LAYER M4 ;
        RECT  0 125.952 0.084 125.976 ;
    END
  END c2_p[280]
  PIN c2_p[281]
    DIRECTION INPUT ;
    USE SIGNAL ;
    PORT
      LAYER M4 ;
        RECT  0 126.048 0.084 126.072 ;
    END
  END c2_p[281]
  PIN c2_p[282]
    DIRECTION INPUT ;
    USE SIGNAL ;
    PORT
      LAYER M4 ;
        RECT  0 126.144 0.084 126.168 ;
    END
  END c2_p[282]
  PIN c2_p[283]
    DIRECTION INPUT ;
    USE SIGNAL ;
    PORT
      LAYER M4 ;
        RECT  0 126.24 0.084 126.264 ;
    END
  END c2_p[283]
  PIN c2_p[284]
    DIRECTION INPUT ;
    USE SIGNAL ;
    PORT
      LAYER M4 ;
        RECT  0 126.336 0.084 126.36 ;
    END
  END c2_p[284]
  PIN c2_p[285]
    DIRECTION INPUT ;
    USE SIGNAL ;
    PORT
      LAYER M4 ;
        RECT  0 126.432 0.084 126.456 ;
    END
  END c2_p[285]
  PIN c2_p[286]
    DIRECTION INPUT ;
    USE SIGNAL ;
    PORT
      LAYER M4 ;
        RECT  0 126.528 0.084 126.552 ;
    END
  END c2_p[286]
  PIN c2_p[287]
    DIRECTION INPUT ;
    USE SIGNAL ;
    PORT
      LAYER M4 ;
        RECT  0 126.624 0.084 126.648 ;
    END
  END c2_p[287]
  PIN c2_p[288]
    DIRECTION INPUT ;
    USE SIGNAL ;
    PORT
      LAYER M4 ;
        RECT  0 126.72 0.084 126.744 ;
    END
  END c2_p[288]
  PIN c2_p[289]
    DIRECTION INPUT ;
    USE SIGNAL ;
    PORT
      LAYER M4 ;
        RECT  0 126.816 0.084 126.84 ;
    END
  END c2_p[289]
  PIN c2_p[28]
    DIRECTION INPUT ;
    USE SIGNAL ;
    PORT
      LAYER M4 ;
        RECT  0 101.76 0.084 101.784 ;
    END
  END c2_p[28]
  PIN c2_p[290]
    DIRECTION INPUT ;
    USE SIGNAL ;
    PORT
      LAYER M4 ;
        RECT  0 126.912 0.084 126.936 ;
    END
  END c2_p[290]
  PIN c2_p[291]
    DIRECTION INPUT ;
    USE SIGNAL ;
    PORT
      LAYER M4 ;
        RECT  0 127.008 0.084 127.032 ;
    END
  END c2_p[291]
  PIN c2_p[292]
    DIRECTION INPUT ;
    USE SIGNAL ;
    PORT
      LAYER M4 ;
        RECT  0 127.104 0.084 127.128 ;
    END
  END c2_p[292]
  PIN c2_p[293]
    DIRECTION INPUT ;
    USE SIGNAL ;
    PORT
      LAYER M4 ;
        RECT  0 127.2 0.084 127.224 ;
    END
  END c2_p[293]
  PIN c2_p[294]
    DIRECTION INPUT ;
    USE SIGNAL ;
    PORT
      LAYER M4 ;
        RECT  0 127.296 0.084 127.32 ;
    END
  END c2_p[294]
  PIN c2_p[295]
    DIRECTION INPUT ;
    USE SIGNAL ;
    PORT
      LAYER M4 ;
        RECT  0 127.392 0.084 127.416 ;
    END
  END c2_p[295]
  PIN c2_p[296]
    DIRECTION INPUT ;
    USE SIGNAL ;
    PORT
      LAYER M4 ;
        RECT  0 127.488 0.084 127.512 ;
    END
  END c2_p[296]
  PIN c2_p[297]
    DIRECTION INPUT ;
    USE SIGNAL ;
    PORT
      LAYER M4 ;
        RECT  0 127.584 0.084 127.608 ;
    END
  END c2_p[297]
  PIN c2_p[298]
    DIRECTION INPUT ;
    USE SIGNAL ;
    PORT
      LAYER M4 ;
        RECT  0 127.68 0.084 127.704 ;
    END
  END c2_p[298]
  PIN c2_p[299]
    DIRECTION INPUT ;
    USE SIGNAL ;
    PORT
      LAYER M4 ;
        RECT  0 127.776 0.084 127.8 ;
    END
  END c2_p[299]
  PIN c2_p[29]
    DIRECTION INPUT ;
    USE SIGNAL ;
    PORT
      LAYER M4 ;
        RECT  0 101.856 0.084 101.88 ;
    END
  END c2_p[29]
  PIN c2_p[2]
    DIRECTION INPUT ;
    USE SIGNAL ;
    PORT
      LAYER M4 ;
        RECT  0 99.264 0.084 99.288 ;
    END
  END c2_p[2]
  PIN c2_p[300]
    DIRECTION INPUT ;
    USE SIGNAL ;
    PORT
      LAYER M4 ;
        RECT  0 127.872 0.084 127.896 ;
    END
  END c2_p[300]
  PIN c2_p[301]
    DIRECTION INPUT ;
    USE SIGNAL ;
    PORT
      LAYER M4 ;
        RECT  0 127.968 0.084 127.992 ;
    END
  END c2_p[301]
  PIN c2_p[302]
    DIRECTION INPUT ;
    USE SIGNAL ;
    PORT
      LAYER M4 ;
        RECT  0 128.064 0.084 128.088 ;
    END
  END c2_p[302]
  PIN c2_p[303]
    DIRECTION INPUT ;
    USE SIGNAL ;
    PORT
      LAYER M4 ;
        RECT  0 128.16 0.084 128.184 ;
    END
  END c2_p[303]
  PIN c2_p[304]
    DIRECTION INPUT ;
    USE SIGNAL ;
    PORT
      LAYER M4 ;
        RECT  0 128.256 0.084 128.28 ;
    END
  END c2_p[304]
  PIN c2_p[305]
    DIRECTION INPUT ;
    USE SIGNAL ;
    PORT
      LAYER M4 ;
        RECT  0 128.352 0.084 128.376 ;
    END
  END c2_p[305]
  PIN c2_p[306]
    DIRECTION INPUT ;
    USE SIGNAL ;
    PORT
      LAYER M4 ;
        RECT  0 128.448 0.084 128.472 ;
    END
  END c2_p[306]
  PIN c2_p[307]
    DIRECTION INPUT ;
    USE SIGNAL ;
    PORT
      LAYER M4 ;
        RECT  0 128.544 0.084 128.568 ;
    END
  END c2_p[307]
  PIN c2_p[308]
    DIRECTION INPUT ;
    USE SIGNAL ;
    PORT
      LAYER M4 ;
        RECT  0 128.64 0.084 128.664 ;
    END
  END c2_p[308]
  PIN c2_p[309]
    DIRECTION INPUT ;
    USE SIGNAL ;
    PORT
      LAYER M4 ;
        RECT  0 128.736 0.084 128.76 ;
    END
  END c2_p[309]
  PIN c2_p[30]
    DIRECTION INPUT ;
    USE SIGNAL ;
    PORT
      LAYER M4 ;
        RECT  0 101.952 0.084 101.976 ;
    END
  END c2_p[30]
  PIN c2_p[310]
    DIRECTION INPUT ;
    USE SIGNAL ;
    PORT
      LAYER M4 ;
        RECT  0 128.832 0.084 128.856 ;
    END
  END c2_p[310]
  PIN c2_p[311]
    DIRECTION INPUT ;
    USE SIGNAL ;
    PORT
      LAYER M4 ;
        RECT  0 128.928 0.084 128.952 ;
    END
  END c2_p[311]
  PIN c2_p[312]
    DIRECTION INPUT ;
    USE SIGNAL ;
    PORT
      LAYER M4 ;
        RECT  0 129.024 0.084 129.048 ;
    END
  END c2_p[312]
  PIN c2_p[313]
    DIRECTION INPUT ;
    USE SIGNAL ;
    PORT
      LAYER M4 ;
        RECT  0 129.12 0.084 129.144 ;
    END
  END c2_p[313]
  PIN c2_p[314]
    DIRECTION INPUT ;
    USE SIGNAL ;
    PORT
      LAYER M4 ;
        RECT  0 129.216 0.084 129.24 ;
    END
  END c2_p[314]
  PIN c2_p[315]
    DIRECTION INPUT ;
    USE SIGNAL ;
    PORT
      LAYER M4 ;
        RECT  0 129.312 0.084 129.336 ;
    END
  END c2_p[315]
  PIN c2_p[316]
    DIRECTION INPUT ;
    USE SIGNAL ;
    PORT
      LAYER M4 ;
        RECT  0 129.408 0.084 129.432 ;
    END
  END c2_p[316]
  PIN c2_p[317]
    DIRECTION INPUT ;
    USE SIGNAL ;
    PORT
      LAYER M4 ;
        RECT  0 129.504 0.084 129.528 ;
    END
  END c2_p[317]
  PIN c2_p[318]
    DIRECTION INPUT ;
    USE SIGNAL ;
    PORT
      LAYER M4 ;
        RECT  0 129.6 0.084 129.624 ;
    END
  END c2_p[318]
  PIN c2_p[319]
    DIRECTION INPUT ;
    USE SIGNAL ;
    PORT
      LAYER M4 ;
        RECT  0 129.696 0.084 129.72 ;
    END
  END c2_p[319]
  PIN c2_p[31]
    DIRECTION INPUT ;
    USE SIGNAL ;
    PORT
      LAYER M4 ;
        RECT  0 102.048 0.084 102.072 ;
    END
  END c2_p[31]
  PIN c2_p[320]
    DIRECTION INPUT ;
    USE SIGNAL ;
    PORT
      LAYER M4 ;
        RECT  0 129.792 0.084 129.816 ;
    END
  END c2_p[320]
  PIN c2_p[321]
    DIRECTION INPUT ;
    USE SIGNAL ;
    PORT
      LAYER M4 ;
        RECT  0 129.888 0.084 129.912 ;
    END
  END c2_p[321]
  PIN c2_p[322]
    DIRECTION INPUT ;
    USE SIGNAL ;
    PORT
      LAYER M4 ;
        RECT  0 129.984 0.084 130.008 ;
    END
  END c2_p[322]
  PIN c2_p[323]
    DIRECTION INPUT ;
    USE SIGNAL ;
    PORT
      LAYER M4 ;
        RECT  0 130.08 0.084 130.104 ;
    END
  END c2_p[323]
  PIN c2_p[324]
    DIRECTION INPUT ;
    USE SIGNAL ;
    PORT
      LAYER M4 ;
        RECT  0 130.176 0.084 130.2 ;
    END
  END c2_p[324]
  PIN c2_p[325]
    DIRECTION INPUT ;
    USE SIGNAL ;
    PORT
      LAYER M4 ;
        RECT  0 130.272 0.084 130.296 ;
    END
  END c2_p[325]
  PIN c2_p[326]
    DIRECTION INPUT ;
    USE SIGNAL ;
    PORT
      LAYER M4 ;
        RECT  0 130.368 0.084 130.392 ;
    END
  END c2_p[326]
  PIN c2_p[327]
    DIRECTION INPUT ;
    USE SIGNAL ;
    PORT
      LAYER M4 ;
        RECT  0 130.464 0.084 130.488 ;
    END
  END c2_p[327]
  PIN c2_p[328]
    DIRECTION INPUT ;
    USE SIGNAL ;
    PORT
      LAYER M4 ;
        RECT  0 130.56 0.084 130.584 ;
    END
  END c2_p[328]
  PIN c2_p[329]
    DIRECTION INPUT ;
    USE SIGNAL ;
    PORT
      LAYER M4 ;
        RECT  0 130.656 0.084 130.68 ;
    END
  END c2_p[329]
  PIN c2_p[32]
    DIRECTION INPUT ;
    USE SIGNAL ;
    PORT
      LAYER M4 ;
        RECT  0 102.144 0.084 102.168 ;
    END
  END c2_p[32]
  PIN c2_p[330]
    DIRECTION INPUT ;
    USE SIGNAL ;
    PORT
      LAYER M4 ;
        RECT  0 130.752 0.084 130.776 ;
    END
  END c2_p[330]
  PIN c2_p[331]
    DIRECTION INPUT ;
    USE SIGNAL ;
    PORT
      LAYER M4 ;
        RECT  0 130.848 0.084 130.872 ;
    END
  END c2_p[331]
  PIN c2_p[332]
    DIRECTION INPUT ;
    USE SIGNAL ;
    PORT
      LAYER M4 ;
        RECT  0 130.944 0.084 130.968 ;
    END
  END c2_p[332]
  PIN c2_p[333]
    DIRECTION INPUT ;
    USE SIGNAL ;
    PORT
      LAYER M4 ;
        RECT  0 131.04 0.084 131.064 ;
    END
  END c2_p[333]
  PIN c2_p[334]
    DIRECTION INPUT ;
    USE SIGNAL ;
    PORT
      LAYER M4 ;
        RECT  0 131.136 0.084 131.16 ;
    END
  END c2_p[334]
  PIN c2_p[335]
    DIRECTION INPUT ;
    USE SIGNAL ;
    PORT
      LAYER M4 ;
        RECT  0 131.232 0.084 131.256 ;
    END
  END c2_p[335]
  PIN c2_p[336]
    DIRECTION INPUT ;
    USE SIGNAL ;
    PORT
      LAYER M4 ;
        RECT  0 131.328 0.084 131.352 ;
    END
  END c2_p[336]
  PIN c2_p[337]
    DIRECTION INPUT ;
    USE SIGNAL ;
    PORT
      LAYER M4 ;
        RECT  0 131.424 0.084 131.448 ;
    END
  END c2_p[337]
  PIN c2_p[338]
    DIRECTION INPUT ;
    USE SIGNAL ;
    PORT
      LAYER M4 ;
        RECT  0 131.52 0.084 131.544 ;
    END
  END c2_p[338]
  PIN c2_p[339]
    DIRECTION INPUT ;
    USE SIGNAL ;
    PORT
      LAYER M4 ;
        RECT  0 131.616 0.084 131.64 ;
    END
  END c2_p[339]
  PIN c2_p[33]
    DIRECTION INPUT ;
    USE SIGNAL ;
    PORT
      LAYER M4 ;
        RECT  0 102.24 0.084 102.264 ;
    END
  END c2_p[33]
  PIN c2_p[340]
    DIRECTION INPUT ;
    USE SIGNAL ;
    PORT
      LAYER M4 ;
        RECT  0 131.712 0.084 131.736 ;
    END
  END c2_p[340]
  PIN c2_p[341]
    DIRECTION INPUT ;
    USE SIGNAL ;
    PORT
      LAYER M4 ;
        RECT  0 131.808 0.084 131.832 ;
    END
  END c2_p[341]
  PIN c2_p[342]
    DIRECTION INPUT ;
    USE SIGNAL ;
    PORT
      LAYER M4 ;
        RECT  0 131.904 0.084 131.928 ;
    END
  END c2_p[342]
  PIN c2_p[343]
    DIRECTION INPUT ;
    USE SIGNAL ;
    PORT
      LAYER M4 ;
        RECT  0 132 0.084 132.024 ;
    END
  END c2_p[343]
  PIN c2_p[344]
    DIRECTION INPUT ;
    USE SIGNAL ;
    PORT
      LAYER M4 ;
        RECT  0 132.096 0.084 132.12 ;
    END
  END c2_p[344]
  PIN c2_p[345]
    DIRECTION INPUT ;
    USE SIGNAL ;
    PORT
      LAYER M4 ;
        RECT  0 132.192 0.084 132.216 ;
    END
  END c2_p[345]
  PIN c2_p[346]
    DIRECTION INPUT ;
    USE SIGNAL ;
    PORT
      LAYER M4 ;
        RECT  0 132.288 0.084 132.312 ;
    END
  END c2_p[346]
  PIN c2_p[347]
    DIRECTION INPUT ;
    USE SIGNAL ;
    PORT
      LAYER M4 ;
        RECT  0 132.384 0.084 132.408 ;
    END
  END c2_p[347]
  PIN c2_p[348]
    DIRECTION INPUT ;
    USE SIGNAL ;
    PORT
      LAYER M4 ;
        RECT  0 132.48 0.084 132.504 ;
    END
  END c2_p[348]
  PIN c2_p[349]
    DIRECTION INPUT ;
    USE SIGNAL ;
    PORT
      LAYER M4 ;
        RECT  0 132.576 0.084 132.6 ;
    END
  END c2_p[349]
  PIN c2_p[34]
    DIRECTION INPUT ;
    USE SIGNAL ;
    PORT
      LAYER M4 ;
        RECT  0 102.336 0.084 102.36 ;
    END
  END c2_p[34]
  PIN c2_p[350]
    DIRECTION INPUT ;
    USE SIGNAL ;
    PORT
      LAYER M4 ;
        RECT  0 132.672 0.084 132.696 ;
    END
  END c2_p[350]
  PIN c2_p[351]
    DIRECTION INPUT ;
    USE SIGNAL ;
    PORT
      LAYER M4 ;
        RECT  0 132.768 0.084 132.792 ;
    END
  END c2_p[351]
  PIN c2_p[352]
    DIRECTION INPUT ;
    USE SIGNAL ;
    PORT
      LAYER M4 ;
        RECT  0 132.864 0.084 132.888 ;
    END
  END c2_p[352]
  PIN c2_p[353]
    DIRECTION INPUT ;
    USE SIGNAL ;
    PORT
      LAYER M4 ;
        RECT  0 132.96 0.084 132.984 ;
    END
  END c2_p[353]
  PIN c2_p[354]
    DIRECTION INPUT ;
    USE SIGNAL ;
    PORT
      LAYER M4 ;
        RECT  0 133.056 0.084 133.08 ;
    END
  END c2_p[354]
  PIN c2_p[355]
    DIRECTION INPUT ;
    USE SIGNAL ;
    PORT
      LAYER M4 ;
        RECT  0 133.152 0.084 133.176 ;
    END
  END c2_p[355]
  PIN c2_p[356]
    DIRECTION INPUT ;
    USE SIGNAL ;
    PORT
      LAYER M4 ;
        RECT  0 133.248 0.084 133.272 ;
    END
  END c2_p[356]
  PIN c2_p[357]
    DIRECTION INPUT ;
    USE SIGNAL ;
    PORT
      LAYER M4 ;
        RECT  0 133.344 0.084 133.368 ;
    END
  END c2_p[357]
  PIN c2_p[358]
    DIRECTION INPUT ;
    USE SIGNAL ;
    PORT
      LAYER M4 ;
        RECT  0 133.44 0.084 133.464 ;
    END
  END c2_p[358]
  PIN c2_p[359]
    DIRECTION INPUT ;
    USE SIGNAL ;
    PORT
      LAYER M4 ;
        RECT  0 133.536 0.084 133.56 ;
    END
  END c2_p[359]
  PIN c2_p[35]
    DIRECTION INPUT ;
    USE SIGNAL ;
    PORT
      LAYER M4 ;
        RECT  0 102.432 0.084 102.456 ;
    END
  END c2_p[35]
  PIN c2_p[360]
    DIRECTION INPUT ;
    USE SIGNAL ;
    PORT
      LAYER M4 ;
        RECT  0 133.632 0.084 133.656 ;
    END
  END c2_p[360]
  PIN c2_p[361]
    DIRECTION INPUT ;
    USE SIGNAL ;
    PORT
      LAYER M4 ;
        RECT  0 133.728 0.084 133.752 ;
    END
  END c2_p[361]
  PIN c2_p[362]
    DIRECTION INPUT ;
    USE SIGNAL ;
    PORT
      LAYER M4 ;
        RECT  0 133.824 0.084 133.848 ;
    END
  END c2_p[362]
  PIN c2_p[363]
    DIRECTION INPUT ;
    USE SIGNAL ;
    PORT
      LAYER M4 ;
        RECT  0 133.92 0.084 133.944 ;
    END
  END c2_p[363]
  PIN c2_p[364]
    DIRECTION INPUT ;
    USE SIGNAL ;
    PORT
      LAYER M4 ;
        RECT  0 134.016 0.084 134.04 ;
    END
  END c2_p[364]
  PIN c2_p[365]
    DIRECTION INPUT ;
    USE SIGNAL ;
    PORT
      LAYER M4 ;
        RECT  0 134.112 0.084 134.136 ;
    END
  END c2_p[365]
  PIN c2_p[366]
    DIRECTION INPUT ;
    USE SIGNAL ;
    PORT
      LAYER M4 ;
        RECT  0 134.208 0.084 134.232 ;
    END
  END c2_p[366]
  PIN c2_p[367]
    DIRECTION INPUT ;
    USE SIGNAL ;
    PORT
      LAYER M4 ;
        RECT  0 134.304 0.084 134.328 ;
    END
  END c2_p[367]
  PIN c2_p[368]
    DIRECTION INPUT ;
    USE SIGNAL ;
    PORT
      LAYER M4 ;
        RECT  0 134.4 0.084 134.424 ;
    END
  END c2_p[368]
  PIN c2_p[369]
    DIRECTION INPUT ;
    USE SIGNAL ;
    PORT
      LAYER M4 ;
        RECT  0 134.496 0.084 134.52 ;
    END
  END c2_p[369]
  PIN c2_p[36]
    DIRECTION INPUT ;
    USE SIGNAL ;
    PORT
      LAYER M4 ;
        RECT  0 102.528 0.084 102.552 ;
    END
  END c2_p[36]
  PIN c2_p[370]
    DIRECTION INPUT ;
    USE SIGNAL ;
    PORT
      LAYER M4 ;
        RECT  0 134.592 0.084 134.616 ;
    END
  END c2_p[370]
  PIN c2_p[371]
    DIRECTION INPUT ;
    USE SIGNAL ;
    PORT
      LAYER M4 ;
        RECT  0 134.688 0.084 134.712 ;
    END
  END c2_p[371]
  PIN c2_p[372]
    DIRECTION INPUT ;
    USE SIGNAL ;
    PORT
      LAYER M4 ;
        RECT  0 134.784 0.084 134.808 ;
    END
  END c2_p[372]
  PIN c2_p[373]
    DIRECTION INPUT ;
    USE SIGNAL ;
    PORT
      LAYER M4 ;
        RECT  0 134.88 0.084 134.904 ;
    END
  END c2_p[373]
  PIN c2_p[374]
    DIRECTION INPUT ;
    USE SIGNAL ;
    PORT
      LAYER M4 ;
        RECT  0 134.976 0.084 135 ;
    END
  END c2_p[374]
  PIN c2_p[375]
    DIRECTION INPUT ;
    USE SIGNAL ;
    PORT
      LAYER M4 ;
        RECT  0 135.072 0.084 135.096 ;
    END
  END c2_p[375]
  PIN c2_p[376]
    DIRECTION INPUT ;
    USE SIGNAL ;
    PORT
      LAYER M4 ;
        RECT  0 135.168 0.084 135.192 ;
    END
  END c2_p[376]
  PIN c2_p[377]
    DIRECTION INPUT ;
    USE SIGNAL ;
    PORT
      LAYER M4 ;
        RECT  0 135.264 0.084 135.288 ;
    END
  END c2_p[377]
  PIN c2_p[378]
    DIRECTION INPUT ;
    USE SIGNAL ;
    PORT
      LAYER M4 ;
        RECT  0 135.36 0.084 135.384 ;
    END
  END c2_p[378]
  PIN c2_p[379]
    DIRECTION INPUT ;
    USE SIGNAL ;
    PORT
      LAYER M4 ;
        RECT  0 135.456 0.084 135.48 ;
    END
  END c2_p[379]
  PIN c2_p[37]
    DIRECTION INPUT ;
    USE SIGNAL ;
    PORT
      LAYER M4 ;
        RECT  0 102.624 0.084 102.648 ;
    END
  END c2_p[37]
  PIN c2_p[380]
    DIRECTION INPUT ;
    USE SIGNAL ;
    PORT
      LAYER M4 ;
        RECT  0 135.552 0.084 135.576 ;
    END
  END c2_p[380]
  PIN c2_p[381]
    DIRECTION INPUT ;
    USE SIGNAL ;
    PORT
      LAYER M4 ;
        RECT  0 135.648 0.084 135.672 ;
    END
  END c2_p[381]
  PIN c2_p[382]
    DIRECTION INPUT ;
    USE SIGNAL ;
    PORT
      LAYER M4 ;
        RECT  0 135.744 0.084 135.768 ;
    END
  END c2_p[382]
  PIN c2_p[383]
    DIRECTION INPUT ;
    USE SIGNAL ;
    PORT
      LAYER M4 ;
        RECT  0 135.84 0.084 135.864 ;
    END
  END c2_p[383]
  PIN c2_p[384]
    DIRECTION INPUT ;
    USE SIGNAL ;
    PORT
      LAYER M4 ;
        RECT  0 135.936 0.084 135.96 ;
    END
  END c2_p[384]
  PIN c2_p[385]
    DIRECTION INPUT ;
    USE SIGNAL ;
    PORT
      LAYER M4 ;
        RECT  0 136.032 0.084 136.056 ;
    END
  END c2_p[385]
  PIN c2_p[386]
    DIRECTION INPUT ;
    USE SIGNAL ;
    PORT
      LAYER M4 ;
        RECT  0 136.128 0.084 136.152 ;
    END
  END c2_p[386]
  PIN c2_p[387]
    DIRECTION INPUT ;
    USE SIGNAL ;
    PORT
      LAYER M4 ;
        RECT  0 136.224 0.084 136.248 ;
    END
  END c2_p[387]
  PIN c2_p[388]
    DIRECTION INPUT ;
    USE SIGNAL ;
    PORT
      LAYER M4 ;
        RECT  0 136.32 0.084 136.344 ;
    END
  END c2_p[388]
  PIN c2_p[389]
    DIRECTION INPUT ;
    USE SIGNAL ;
    PORT
      LAYER M4 ;
        RECT  0 136.416 0.084 136.44 ;
    END
  END c2_p[389]
  PIN c2_p[38]
    DIRECTION INPUT ;
    USE SIGNAL ;
    PORT
      LAYER M4 ;
        RECT  0 102.72 0.084 102.744 ;
    END
  END c2_p[38]
  PIN c2_p[390]
    DIRECTION INPUT ;
    USE SIGNAL ;
    PORT
      LAYER M4 ;
        RECT  0 136.512 0.084 136.536 ;
    END
  END c2_p[390]
  PIN c2_p[391]
    DIRECTION INPUT ;
    USE SIGNAL ;
    PORT
      LAYER M4 ;
        RECT  0 136.608 0.084 136.632 ;
    END
  END c2_p[391]
  PIN c2_p[392]
    DIRECTION INPUT ;
    USE SIGNAL ;
    PORT
      LAYER M4 ;
        RECT  0 136.704 0.084 136.728 ;
    END
  END c2_p[392]
  PIN c2_p[393]
    DIRECTION INPUT ;
    USE SIGNAL ;
    PORT
      LAYER M4 ;
        RECT  0 136.8 0.084 136.824 ;
    END
  END c2_p[393]
  PIN c2_p[394]
    DIRECTION INPUT ;
    USE SIGNAL ;
    PORT
      LAYER M4 ;
        RECT  0 136.896 0.084 136.92 ;
    END
  END c2_p[394]
  PIN c2_p[395]
    DIRECTION INPUT ;
    USE SIGNAL ;
    PORT
      LAYER M4 ;
        RECT  0 136.992 0.084 137.016 ;
    END
  END c2_p[395]
  PIN c2_p[396]
    DIRECTION INPUT ;
    USE SIGNAL ;
    PORT
      LAYER M4 ;
        RECT  0 137.088 0.084 137.112 ;
    END
  END c2_p[396]
  PIN c2_p[397]
    DIRECTION INPUT ;
    USE SIGNAL ;
    PORT
      LAYER M4 ;
        RECT  0 137.184 0.084 137.208 ;
    END
  END c2_p[397]
  PIN c2_p[398]
    DIRECTION INPUT ;
    USE SIGNAL ;
    PORT
      LAYER M4 ;
        RECT  0 137.28 0.084 137.304 ;
    END
  END c2_p[398]
  PIN c2_p[399]
    DIRECTION INPUT ;
    USE SIGNAL ;
    PORT
      LAYER M4 ;
        RECT  0 137.376 0.084 137.4 ;
    END
  END c2_p[399]
  PIN c2_p[39]
    DIRECTION INPUT ;
    USE SIGNAL ;
    PORT
      LAYER M4 ;
        RECT  0 102.816 0.084 102.84 ;
    END
  END c2_p[39]
  PIN c2_p[3]
    DIRECTION INPUT ;
    USE SIGNAL ;
    PORT
      LAYER M4 ;
        RECT  0 99.36 0.084 99.384 ;
    END
  END c2_p[3]
  PIN c2_p[400]
    DIRECTION INPUT ;
    USE SIGNAL ;
    PORT
      LAYER M4 ;
        RECT  0 137.472 0.084 137.496 ;
    END
  END c2_p[400]
  PIN c2_p[401]
    DIRECTION INPUT ;
    USE SIGNAL ;
    PORT
      LAYER M4 ;
        RECT  0 137.568 0.084 137.592 ;
    END
  END c2_p[401]
  PIN c2_p[402]
    DIRECTION INPUT ;
    USE SIGNAL ;
    PORT
      LAYER M4 ;
        RECT  0 137.664 0.084 137.688 ;
    END
  END c2_p[402]
  PIN c2_p[403]
    DIRECTION INPUT ;
    USE SIGNAL ;
    PORT
      LAYER M4 ;
        RECT  0 137.76 0.084 137.784 ;
    END
  END c2_p[403]
  PIN c2_p[404]
    DIRECTION INPUT ;
    USE SIGNAL ;
    PORT
      LAYER M4 ;
        RECT  0 137.856 0.084 137.88 ;
    END
  END c2_p[404]
  PIN c2_p[405]
    DIRECTION INPUT ;
    USE SIGNAL ;
    PORT
      LAYER M4 ;
        RECT  0 137.952 0.084 137.976 ;
    END
  END c2_p[405]
  PIN c2_p[406]
    DIRECTION INPUT ;
    USE SIGNAL ;
    PORT
      LAYER M4 ;
        RECT  0 138.048 0.084 138.072 ;
    END
  END c2_p[406]
  PIN c2_p[407]
    DIRECTION INPUT ;
    USE SIGNAL ;
    PORT
      LAYER M4 ;
        RECT  0 138.144 0.084 138.168 ;
    END
  END c2_p[407]
  PIN c2_p[408]
    DIRECTION INPUT ;
    USE SIGNAL ;
    PORT
      LAYER M4 ;
        RECT  0 138.24 0.084 138.264 ;
    END
  END c2_p[408]
  PIN c2_p[409]
    DIRECTION INPUT ;
    USE SIGNAL ;
    PORT
      LAYER M4 ;
        RECT  0 138.336 0.084 138.36 ;
    END
  END c2_p[409]
  PIN c2_p[40]
    DIRECTION INPUT ;
    USE SIGNAL ;
    PORT
      LAYER M4 ;
        RECT  0 102.912 0.084 102.936 ;
    END
  END c2_p[40]
  PIN c2_p[410]
    DIRECTION INPUT ;
    USE SIGNAL ;
    PORT
      LAYER M4 ;
        RECT  0 138.432 0.084 138.456 ;
    END
  END c2_p[410]
  PIN c2_p[411]
    DIRECTION INPUT ;
    USE SIGNAL ;
    PORT
      LAYER M4 ;
        RECT  0 138.528 0.084 138.552 ;
    END
  END c2_p[411]
  PIN c2_p[412]
    DIRECTION INPUT ;
    USE SIGNAL ;
    PORT
      LAYER M4 ;
        RECT  0 138.624 0.084 138.648 ;
    END
  END c2_p[412]
  PIN c2_p[413]
    DIRECTION INPUT ;
    USE SIGNAL ;
    PORT
      LAYER M4 ;
        RECT  0 138.72 0.084 138.744 ;
    END
  END c2_p[413]
  PIN c2_p[414]
    DIRECTION INPUT ;
    USE SIGNAL ;
    PORT
      LAYER M4 ;
        RECT  0 138.816 0.084 138.84 ;
    END
  END c2_p[414]
  PIN c2_p[415]
    DIRECTION INPUT ;
    USE SIGNAL ;
    PORT
      LAYER M4 ;
        RECT  0 138.912 0.084 138.936 ;
    END
  END c2_p[415]
  PIN c2_p[416]
    DIRECTION INPUT ;
    USE SIGNAL ;
    PORT
      LAYER M4 ;
        RECT  0 139.008 0.084 139.032 ;
    END
  END c2_p[416]
  PIN c2_p[417]
    DIRECTION INPUT ;
    USE SIGNAL ;
    PORT
      LAYER M4 ;
        RECT  0 139.104 0.084 139.128 ;
    END
  END c2_p[417]
  PIN c2_p[418]
    DIRECTION INPUT ;
    USE SIGNAL ;
    PORT
      LAYER M4 ;
        RECT  0 139.2 0.084 139.224 ;
    END
  END c2_p[418]
  PIN c2_p[419]
    DIRECTION INPUT ;
    USE SIGNAL ;
    PORT
      LAYER M4 ;
        RECT  0 139.296 0.084 139.32 ;
    END
  END c2_p[419]
  PIN c2_p[41]
    DIRECTION INPUT ;
    USE SIGNAL ;
    PORT
      LAYER M4 ;
        RECT  0 103.008 0.084 103.032 ;
    END
  END c2_p[41]
  PIN c2_p[420]
    DIRECTION INPUT ;
    USE SIGNAL ;
    PORT
      LAYER M4 ;
        RECT  0 139.392 0.084 139.416 ;
    END
  END c2_p[420]
  PIN c2_p[421]
    DIRECTION INPUT ;
    USE SIGNAL ;
    PORT
      LAYER M4 ;
        RECT  0 139.488 0.084 139.512 ;
    END
  END c2_p[421]
  PIN c2_p[422]
    DIRECTION INPUT ;
    USE SIGNAL ;
    PORT
      LAYER M4 ;
        RECT  0 139.584 0.084 139.608 ;
    END
  END c2_p[422]
  PIN c2_p[423]
    DIRECTION INPUT ;
    USE SIGNAL ;
    PORT
      LAYER M4 ;
        RECT  0 139.68 0.084 139.704 ;
    END
  END c2_p[423]
  PIN c2_p[424]
    DIRECTION INPUT ;
    USE SIGNAL ;
    PORT
      LAYER M4 ;
        RECT  0 139.776 0.084 139.8 ;
    END
  END c2_p[424]
  PIN c2_p[425]
    DIRECTION INPUT ;
    USE SIGNAL ;
    PORT
      LAYER M4 ;
        RECT  0 139.872 0.084 139.896 ;
    END
  END c2_p[425]
  PIN c2_p[426]
    DIRECTION INPUT ;
    USE SIGNAL ;
    PORT
      LAYER M4 ;
        RECT  0 139.968 0.084 139.992 ;
    END
  END c2_p[426]
  PIN c2_p[427]
    DIRECTION INPUT ;
    USE SIGNAL ;
    PORT
      LAYER M4 ;
        RECT  0 140.064 0.084 140.088 ;
    END
  END c2_p[427]
  PIN c2_p[428]
    DIRECTION INPUT ;
    USE SIGNAL ;
    PORT
      LAYER M4 ;
        RECT  0 140.16 0.084 140.184 ;
    END
  END c2_p[428]
  PIN c2_p[429]
    DIRECTION INPUT ;
    USE SIGNAL ;
    PORT
      LAYER M4 ;
        RECT  0 140.256 0.084 140.28 ;
    END
  END c2_p[429]
  PIN c2_p[42]
    DIRECTION INPUT ;
    USE SIGNAL ;
    PORT
      LAYER M4 ;
        RECT  0 103.104 0.084 103.128 ;
    END
  END c2_p[42]
  PIN c2_p[430]
    DIRECTION INPUT ;
    USE SIGNAL ;
    PORT
      LAYER M4 ;
        RECT  0 140.352 0.084 140.376 ;
    END
  END c2_p[430]
  PIN c2_p[431]
    DIRECTION INPUT ;
    USE SIGNAL ;
    PORT
      LAYER M4 ;
        RECT  0 140.448 0.084 140.472 ;
    END
  END c2_p[431]
  PIN c2_p[432]
    DIRECTION INPUT ;
    USE SIGNAL ;
    PORT
      LAYER M4 ;
        RECT  0 140.544 0.084 140.568 ;
    END
  END c2_p[432]
  PIN c2_p[433]
    DIRECTION INPUT ;
    USE SIGNAL ;
    PORT
      LAYER M4 ;
        RECT  0 140.64 0.084 140.664 ;
    END
  END c2_p[433]
  PIN c2_p[434]
    DIRECTION INPUT ;
    USE SIGNAL ;
    PORT
      LAYER M4 ;
        RECT  0 140.736 0.084 140.76 ;
    END
  END c2_p[434]
  PIN c2_p[435]
    DIRECTION INPUT ;
    USE SIGNAL ;
    PORT
      LAYER M4 ;
        RECT  0 140.832 0.084 140.856 ;
    END
  END c2_p[435]
  PIN c2_p[436]
    DIRECTION INPUT ;
    USE SIGNAL ;
    PORT
      LAYER M4 ;
        RECT  0 140.928 0.084 140.952 ;
    END
  END c2_p[436]
  PIN c2_p[437]
    DIRECTION INPUT ;
    USE SIGNAL ;
    PORT
      LAYER M4 ;
        RECT  0 141.024 0.084 141.048 ;
    END
  END c2_p[437]
  PIN c2_p[438]
    DIRECTION INPUT ;
    USE SIGNAL ;
    PORT
      LAYER M4 ;
        RECT  0 141.12 0.084 141.144 ;
    END
  END c2_p[438]
  PIN c2_p[439]
    DIRECTION INPUT ;
    USE SIGNAL ;
    PORT
      LAYER M4 ;
        RECT  0 141.216 0.084 141.24 ;
    END
  END c2_p[439]
  PIN c2_p[43]
    DIRECTION INPUT ;
    USE SIGNAL ;
    PORT
      LAYER M4 ;
        RECT  0 103.2 0.084 103.224 ;
    END
  END c2_p[43]
  PIN c2_p[440]
    DIRECTION INPUT ;
    USE SIGNAL ;
    PORT
      LAYER M4 ;
        RECT  0 141.312 0.084 141.336 ;
    END
  END c2_p[440]
  PIN c2_p[441]
    DIRECTION INPUT ;
    USE SIGNAL ;
    PORT
      LAYER M4 ;
        RECT  0 141.408 0.084 141.432 ;
    END
  END c2_p[441]
  PIN c2_p[442]
    DIRECTION INPUT ;
    USE SIGNAL ;
    PORT
      LAYER M4 ;
        RECT  0 141.504 0.084 141.528 ;
    END
  END c2_p[442]
  PIN c2_p[443]
    DIRECTION INPUT ;
    USE SIGNAL ;
    PORT
      LAYER M4 ;
        RECT  0 141.6 0.084 141.624 ;
    END
  END c2_p[443]
  PIN c2_p[444]
    DIRECTION INPUT ;
    USE SIGNAL ;
    PORT
      LAYER M4 ;
        RECT  0 141.696 0.084 141.72 ;
    END
  END c2_p[444]
  PIN c2_p[445]
    DIRECTION INPUT ;
    USE SIGNAL ;
    PORT
      LAYER M4 ;
        RECT  0 141.792 0.084 141.816 ;
    END
  END c2_p[445]
  PIN c2_p[446]
    DIRECTION INPUT ;
    USE SIGNAL ;
    PORT
      LAYER M4 ;
        RECT  0 141.888 0.084 141.912 ;
    END
  END c2_p[446]
  PIN c2_p[447]
    DIRECTION INPUT ;
    USE SIGNAL ;
    PORT
      LAYER M4 ;
        RECT  0 141.984 0.084 142.008 ;
    END
  END c2_p[447]
  PIN c2_p[448]
    DIRECTION INPUT ;
    USE SIGNAL ;
    PORT
      LAYER M4 ;
        RECT  0 142.08 0.084 142.104 ;
    END
  END c2_p[448]
  PIN c2_p[449]
    DIRECTION INPUT ;
    USE SIGNAL ;
    PORT
      LAYER M4 ;
        RECT  0 142.176 0.084 142.2 ;
    END
  END c2_p[449]
  PIN c2_p[44]
    DIRECTION INPUT ;
    USE SIGNAL ;
    PORT
      LAYER M4 ;
        RECT  0 103.296 0.084 103.32 ;
    END
  END c2_p[44]
  PIN c2_p[450]
    DIRECTION INPUT ;
    USE SIGNAL ;
    PORT
      LAYER M4 ;
        RECT  0 142.272 0.084 142.296 ;
    END
  END c2_p[450]
  PIN c2_p[451]
    DIRECTION INPUT ;
    USE SIGNAL ;
    PORT
      LAYER M4 ;
        RECT  0 142.368 0.084 142.392 ;
    END
  END c2_p[451]
  PIN c2_p[452]
    DIRECTION INPUT ;
    USE SIGNAL ;
    PORT
      LAYER M4 ;
        RECT  0 142.464 0.084 142.488 ;
    END
  END c2_p[452]
  PIN c2_p[453]
    DIRECTION INPUT ;
    USE SIGNAL ;
    PORT
      LAYER M4 ;
        RECT  0 142.56 0.084 142.584 ;
    END
  END c2_p[453]
  PIN c2_p[454]
    DIRECTION INPUT ;
    USE SIGNAL ;
    PORT
      LAYER M4 ;
        RECT  0 142.656 0.084 142.68 ;
    END
  END c2_p[454]
  PIN c2_p[455]
    DIRECTION INPUT ;
    USE SIGNAL ;
    PORT
      LAYER M4 ;
        RECT  0 142.752 0.084 142.776 ;
    END
  END c2_p[455]
  PIN c2_p[456]
    DIRECTION INPUT ;
    USE SIGNAL ;
    PORT
      LAYER M4 ;
        RECT  0 142.848 0.084 142.872 ;
    END
  END c2_p[456]
  PIN c2_p[457]
    DIRECTION INPUT ;
    USE SIGNAL ;
    PORT
      LAYER M4 ;
        RECT  0 142.944 0.084 142.968 ;
    END
  END c2_p[457]
  PIN c2_p[458]
    DIRECTION INPUT ;
    USE SIGNAL ;
    PORT
      LAYER M4 ;
        RECT  0 143.04 0.084 143.064 ;
    END
  END c2_p[458]
  PIN c2_p[459]
    DIRECTION INPUT ;
    USE SIGNAL ;
    PORT
      LAYER M4 ;
        RECT  0 143.136 0.084 143.16 ;
    END
  END c2_p[459]
  PIN c2_p[45]
    DIRECTION INPUT ;
    USE SIGNAL ;
    PORT
      LAYER M4 ;
        RECT  0 103.392 0.084 103.416 ;
    END
  END c2_p[45]
  PIN c2_p[460]
    DIRECTION INPUT ;
    USE SIGNAL ;
    PORT
      LAYER M4 ;
        RECT  0 143.232 0.084 143.256 ;
    END
  END c2_p[460]
  PIN c2_p[461]
    DIRECTION INPUT ;
    USE SIGNAL ;
    PORT
      LAYER M4 ;
        RECT  0 143.328 0.084 143.352 ;
    END
  END c2_p[461]
  PIN c2_p[462]
    DIRECTION INPUT ;
    USE SIGNAL ;
    PORT
      LAYER M4 ;
        RECT  0 143.424 0.084 143.448 ;
    END
  END c2_p[462]
  PIN c2_p[463]
    DIRECTION INPUT ;
    USE SIGNAL ;
    PORT
      LAYER M4 ;
        RECT  0 143.52 0.084 143.544 ;
    END
  END c2_p[463]
  PIN c2_p[464]
    DIRECTION INPUT ;
    USE SIGNAL ;
    PORT
      LAYER M4 ;
        RECT  0 143.616 0.084 143.64 ;
    END
  END c2_p[464]
  PIN c2_p[465]
    DIRECTION INPUT ;
    USE SIGNAL ;
    PORT
      LAYER M4 ;
        RECT  0 143.712 0.084 143.736 ;
    END
  END c2_p[465]
  PIN c2_p[466]
    DIRECTION INPUT ;
    USE SIGNAL ;
    PORT
      LAYER M4 ;
        RECT  0 143.808 0.084 143.832 ;
    END
  END c2_p[466]
  PIN c2_p[467]
    DIRECTION INPUT ;
    USE SIGNAL ;
    PORT
      LAYER M4 ;
        RECT  0 143.904 0.084 143.928 ;
    END
  END c2_p[467]
  PIN c2_p[468]
    DIRECTION INPUT ;
    USE SIGNAL ;
    PORT
      LAYER M4 ;
        RECT  0 144 0.084 144.024 ;
    END
  END c2_p[468]
  PIN c2_p[469]
    DIRECTION INPUT ;
    USE SIGNAL ;
    PORT
      LAYER M4 ;
        RECT  0 144.096 0.084 144.12 ;
    END
  END c2_p[469]
  PIN c2_p[46]
    DIRECTION INPUT ;
    USE SIGNAL ;
    PORT
      LAYER M4 ;
        RECT  0 103.488 0.084 103.512 ;
    END
  END c2_p[46]
  PIN c2_p[470]
    DIRECTION INPUT ;
    USE SIGNAL ;
    PORT
      LAYER M4 ;
        RECT  0 144.192 0.084 144.216 ;
    END
  END c2_p[470]
  PIN c2_p[471]
    DIRECTION INPUT ;
    USE SIGNAL ;
    PORT
      LAYER M4 ;
        RECT  0 144.288 0.084 144.312 ;
    END
  END c2_p[471]
  PIN c2_p[472]
    DIRECTION INPUT ;
    USE SIGNAL ;
    PORT
      LAYER M4 ;
        RECT  0 144.384 0.084 144.408 ;
    END
  END c2_p[472]
  PIN c2_p[473]
    DIRECTION INPUT ;
    USE SIGNAL ;
    PORT
      LAYER M4 ;
        RECT  0 144.48 0.084 144.504 ;
    END
  END c2_p[473]
  PIN c2_p[474]
    DIRECTION INPUT ;
    USE SIGNAL ;
    PORT
      LAYER M4 ;
        RECT  0 144.576 0.084 144.6 ;
    END
  END c2_p[474]
  PIN c2_p[475]
    DIRECTION INPUT ;
    USE SIGNAL ;
    PORT
      LAYER M4 ;
        RECT  0 144.672 0.084 144.696 ;
    END
  END c2_p[475]
  PIN c2_p[476]
    DIRECTION INPUT ;
    USE SIGNAL ;
    PORT
      LAYER M4 ;
        RECT  0 144.768 0.084 144.792 ;
    END
  END c2_p[476]
  PIN c2_p[477]
    DIRECTION INPUT ;
    USE SIGNAL ;
    PORT
      LAYER M4 ;
        RECT  0 144.864 0.084 144.888 ;
    END
  END c2_p[477]
  PIN c2_p[478]
    DIRECTION INPUT ;
    USE SIGNAL ;
    PORT
      LAYER M4 ;
        RECT  0 144.96 0.084 144.984 ;
    END
  END c2_p[478]
  PIN c2_p[479]
    DIRECTION INPUT ;
    USE SIGNAL ;
    PORT
      LAYER M4 ;
        RECT  0 145.056 0.084 145.08 ;
    END
  END c2_p[479]
  PIN c2_p[47]
    DIRECTION INPUT ;
    USE SIGNAL ;
    PORT
      LAYER M4 ;
        RECT  0 103.584 0.084 103.608 ;
    END
  END c2_p[47]
  PIN c2_p[480]
    DIRECTION INPUT ;
    USE SIGNAL ;
    PORT
      LAYER M4 ;
        RECT  0 145.152 0.084 145.176 ;
    END
  END c2_p[480]
  PIN c2_p[481]
    DIRECTION INPUT ;
    USE SIGNAL ;
    PORT
      LAYER M4 ;
        RECT  0 145.248 0.084 145.272 ;
    END
  END c2_p[481]
  PIN c2_p[482]
    DIRECTION INPUT ;
    USE SIGNAL ;
    PORT
      LAYER M4 ;
        RECT  0 145.344 0.084 145.368 ;
    END
  END c2_p[482]
  PIN c2_p[483]
    DIRECTION INPUT ;
    USE SIGNAL ;
    PORT
      LAYER M4 ;
        RECT  0 145.44 0.084 145.464 ;
    END
  END c2_p[483]
  PIN c2_p[484]
    DIRECTION INPUT ;
    USE SIGNAL ;
    PORT
      LAYER M4 ;
        RECT  0 145.536 0.084 145.56 ;
    END
  END c2_p[484]
  PIN c2_p[485]
    DIRECTION INPUT ;
    USE SIGNAL ;
    PORT
      LAYER M4 ;
        RECT  0 145.632 0.084 145.656 ;
    END
  END c2_p[485]
  PIN c2_p[486]
    DIRECTION INPUT ;
    USE SIGNAL ;
    PORT
      LAYER M4 ;
        RECT  0 145.728 0.084 145.752 ;
    END
  END c2_p[486]
  PIN c2_p[487]
    DIRECTION INPUT ;
    USE SIGNAL ;
    PORT
      LAYER M4 ;
        RECT  0 145.824 0.084 145.848 ;
    END
  END c2_p[487]
  PIN c2_p[488]
    DIRECTION INPUT ;
    USE SIGNAL ;
    PORT
      LAYER M4 ;
        RECT  0 145.92 0.084 145.944 ;
    END
  END c2_p[488]
  PIN c2_p[489]
    DIRECTION INPUT ;
    USE SIGNAL ;
    PORT
      LAYER M4 ;
        RECT  0 146.016 0.084 146.04 ;
    END
  END c2_p[489]
  PIN c2_p[48]
    DIRECTION INPUT ;
    USE SIGNAL ;
    PORT
      LAYER M4 ;
        RECT  0 103.68 0.084 103.704 ;
    END
  END c2_p[48]
  PIN c2_p[490]
    DIRECTION INPUT ;
    USE SIGNAL ;
    PORT
      LAYER M4 ;
        RECT  0 146.112 0.084 146.136 ;
    END
  END c2_p[490]
  PIN c2_p[491]
    DIRECTION INPUT ;
    USE SIGNAL ;
    PORT
      LAYER M4 ;
        RECT  0 146.208 0.084 146.232 ;
    END
  END c2_p[491]
  PIN c2_p[492]
    DIRECTION INPUT ;
    USE SIGNAL ;
    PORT
      LAYER M4 ;
        RECT  0 146.304 0.084 146.328 ;
    END
  END c2_p[492]
  PIN c2_p[493]
    DIRECTION INPUT ;
    USE SIGNAL ;
    PORT
      LAYER M4 ;
        RECT  0 146.4 0.084 146.424 ;
    END
  END c2_p[493]
  PIN c2_p[494]
    DIRECTION INPUT ;
    USE SIGNAL ;
    PORT
      LAYER M4 ;
        RECT  0 146.496 0.084 146.52 ;
    END
  END c2_p[494]
  PIN c2_p[495]
    DIRECTION INPUT ;
    USE SIGNAL ;
    PORT
      LAYER M4 ;
        RECT  0 146.592 0.084 146.616 ;
    END
  END c2_p[495]
  PIN c2_p[496]
    DIRECTION INPUT ;
    USE SIGNAL ;
    PORT
      LAYER M4 ;
        RECT  0 146.688 0.084 146.712 ;
    END
  END c2_p[496]
  PIN c2_p[497]
    DIRECTION INPUT ;
    USE SIGNAL ;
    PORT
      LAYER M4 ;
        RECT  0 146.784 0.084 146.808 ;
    END
  END c2_p[497]
  PIN c2_p[498]
    DIRECTION INPUT ;
    USE SIGNAL ;
    PORT
      LAYER M4 ;
        RECT  0 146.88 0.084 146.904 ;
    END
  END c2_p[498]
  PIN c2_p[499]
    DIRECTION INPUT ;
    USE SIGNAL ;
    PORT
      LAYER M4 ;
        RECT  0 146.976 0.084 147 ;
    END
  END c2_p[499]
  PIN c2_p[49]
    DIRECTION INPUT ;
    USE SIGNAL ;
    PORT
      LAYER M4 ;
        RECT  0 103.776 0.084 103.8 ;
    END
  END c2_p[49]
  PIN c2_p[4]
    DIRECTION INPUT ;
    USE SIGNAL ;
    PORT
      LAYER M4 ;
        RECT  0 99.456 0.084 99.48 ;
    END
  END c2_p[4]
  PIN c2_p[500]
    DIRECTION INPUT ;
    USE SIGNAL ;
    PORT
      LAYER M4 ;
        RECT  0 147.072 0.084 147.096 ;
    END
  END c2_p[500]
  PIN c2_p[501]
    DIRECTION INPUT ;
    USE SIGNAL ;
    PORT
      LAYER M4 ;
        RECT  0 147.168 0.084 147.192 ;
    END
  END c2_p[501]
  PIN c2_p[502]
    DIRECTION INPUT ;
    USE SIGNAL ;
    PORT
      LAYER M4 ;
        RECT  0 147.264 0.084 147.288 ;
    END
  END c2_p[502]
  PIN c2_p[503]
    DIRECTION INPUT ;
    USE SIGNAL ;
    PORT
      LAYER M4 ;
        RECT  0 147.36 0.084 147.384 ;
    END
  END c2_p[503]
  PIN c2_p[504]
    DIRECTION INPUT ;
    USE SIGNAL ;
    PORT
      LAYER M4 ;
        RECT  0 147.456 0.084 147.48 ;
    END
  END c2_p[504]
  PIN c2_p[505]
    DIRECTION INPUT ;
    USE SIGNAL ;
    PORT
      LAYER M4 ;
        RECT  0 147.552 0.084 147.576 ;
    END
  END c2_p[505]
  PIN c2_p[506]
    DIRECTION INPUT ;
    USE SIGNAL ;
    PORT
      LAYER M4 ;
        RECT  0 147.648 0.084 147.672 ;
    END
  END c2_p[506]
  PIN c2_p[507]
    DIRECTION INPUT ;
    USE SIGNAL ;
    PORT
      LAYER M4 ;
        RECT  0 147.744 0.084 147.768 ;
    END
  END c2_p[507]
  PIN c2_p[508]
    DIRECTION INPUT ;
    USE SIGNAL ;
    PORT
      LAYER M4 ;
        RECT  0 147.84 0.084 147.864 ;
    END
  END c2_p[508]
  PIN c2_p[509]
    DIRECTION INPUT ;
    USE SIGNAL ;
    PORT
      LAYER M4 ;
        RECT  0 147.936 0.084 147.96 ;
    END
  END c2_p[509]
  PIN c2_p[50]
    DIRECTION INPUT ;
    USE SIGNAL ;
    PORT
      LAYER M4 ;
        RECT  0 103.872 0.084 103.896 ;
    END
  END c2_p[50]
  PIN c2_p[510]
    DIRECTION INPUT ;
    USE SIGNAL ;
    PORT
      LAYER M4 ;
        RECT  0 148.032 0.084 148.056 ;
    END
  END c2_p[510]
  PIN c2_p[511]
    DIRECTION INPUT ;
    USE SIGNAL ;
    PORT
      LAYER M4 ;
        RECT  0 148.128 0.084 148.152 ;
    END
  END c2_p[511]
  PIN c2_p[512]
    DIRECTION INPUT ;
    USE SIGNAL ;
    PORT
      LAYER M4 ;
        RECT  0 148.224 0.084 148.248 ;
    END
  END c2_p[512]
  PIN c2_p[513]
    DIRECTION INPUT ;
    USE SIGNAL ;
    PORT
      LAYER M4 ;
        RECT  0 148.32 0.084 148.344 ;
    END
  END c2_p[513]
  PIN c2_p[514]
    DIRECTION INPUT ;
    USE SIGNAL ;
    PORT
      LAYER M4 ;
        RECT  0 148.416 0.084 148.44 ;
    END
  END c2_p[514]
  PIN c2_p[515]
    DIRECTION INPUT ;
    USE SIGNAL ;
    PORT
      LAYER M4 ;
        RECT  0 148.512 0.084 148.536 ;
    END
  END c2_p[515]
  PIN c2_p[516]
    DIRECTION INPUT ;
    USE SIGNAL ;
    PORT
      LAYER M4 ;
        RECT  0 148.608 0.084 148.632 ;
    END
  END c2_p[516]
  PIN c2_p[517]
    DIRECTION INPUT ;
    USE SIGNAL ;
    PORT
      LAYER M4 ;
        RECT  0 148.704 0.084 148.728 ;
    END
  END c2_p[517]
  PIN c2_p[518]
    DIRECTION INPUT ;
    USE SIGNAL ;
    PORT
      LAYER M4 ;
        RECT  0 148.8 0.084 148.824 ;
    END
  END c2_p[518]
  PIN c2_p[519]
    DIRECTION INPUT ;
    USE SIGNAL ;
    PORT
      LAYER M4 ;
        RECT  0 148.896 0.084 148.92 ;
    END
  END c2_p[519]
  PIN c2_p[51]
    DIRECTION INPUT ;
    USE SIGNAL ;
    PORT
      LAYER M4 ;
        RECT  0 103.968 0.084 103.992 ;
    END
  END c2_p[51]
  PIN c2_p[520]
    DIRECTION INPUT ;
    USE SIGNAL ;
    PORT
      LAYER M4 ;
        RECT  0 148.992 0.084 149.016 ;
    END
  END c2_p[520]
  PIN c2_p[521]
    DIRECTION INPUT ;
    USE SIGNAL ;
    PORT
      LAYER M4 ;
        RECT  0 149.088 0.084 149.112 ;
    END
  END c2_p[521]
  PIN c2_p[522]
    DIRECTION INPUT ;
    USE SIGNAL ;
    PORT
      LAYER M4 ;
        RECT  0 149.184 0.084 149.208 ;
    END
  END c2_p[522]
  PIN c2_p[523]
    DIRECTION INPUT ;
    USE SIGNAL ;
    PORT
      LAYER M4 ;
        RECT  0 149.28 0.084 149.304 ;
    END
  END c2_p[523]
  PIN c2_p[524]
    DIRECTION INPUT ;
    USE SIGNAL ;
    PORT
      LAYER M4 ;
        RECT  0 149.376 0.084 149.4 ;
    END
  END c2_p[524]
  PIN c2_p[525]
    DIRECTION INPUT ;
    USE SIGNAL ;
    PORT
      LAYER M4 ;
        RECT  0 149.472 0.084 149.496 ;
    END
  END c2_p[525]
  PIN c2_p[526]
    DIRECTION INPUT ;
    USE SIGNAL ;
    PORT
      LAYER M4 ;
        RECT  0 149.568 0.084 149.592 ;
    END
  END c2_p[526]
  PIN c2_p[527]
    DIRECTION INPUT ;
    USE SIGNAL ;
    PORT
      LAYER M4 ;
        RECT  0 149.664 0.084 149.688 ;
    END
  END c2_p[527]
  PIN c2_p[528]
    DIRECTION INPUT ;
    USE SIGNAL ;
    PORT
      LAYER M4 ;
        RECT  0 149.76 0.084 149.784 ;
    END
  END c2_p[528]
  PIN c2_p[529]
    DIRECTION INPUT ;
    USE SIGNAL ;
    PORT
      LAYER M4 ;
        RECT  0 149.856 0.084 149.88 ;
    END
  END c2_p[529]
  PIN c2_p[52]
    DIRECTION INPUT ;
    USE SIGNAL ;
    PORT
      LAYER M4 ;
        RECT  0 104.064 0.084 104.088 ;
    END
  END c2_p[52]
  PIN c2_p[530]
    DIRECTION INPUT ;
    USE SIGNAL ;
    PORT
      LAYER M4 ;
        RECT  0 149.952 0.084 149.976 ;
    END
  END c2_p[530]
  PIN c2_p[531]
    DIRECTION INPUT ;
    USE SIGNAL ;
    PORT
      LAYER M4 ;
        RECT  0 150.048 0.084 150.072 ;
    END
  END c2_p[531]
  PIN c2_p[532]
    DIRECTION INPUT ;
    USE SIGNAL ;
    PORT
      LAYER M4 ;
        RECT  0 150.144 0.084 150.168 ;
    END
  END c2_p[532]
  PIN c2_p[533]
    DIRECTION INPUT ;
    USE SIGNAL ;
    PORT
      LAYER M4 ;
        RECT  0 150.24 0.084 150.264 ;
    END
  END c2_p[533]
  PIN c2_p[534]
    DIRECTION INPUT ;
    USE SIGNAL ;
    PORT
      LAYER M4 ;
        RECT  0 150.336 0.084 150.36 ;
    END
  END c2_p[534]
  PIN c2_p[535]
    DIRECTION INPUT ;
    USE SIGNAL ;
    PORT
      LAYER M4 ;
        RECT  0 150.432 0.084 150.456 ;
    END
  END c2_p[535]
  PIN c2_p[536]
    DIRECTION INPUT ;
    USE SIGNAL ;
    PORT
      LAYER M4 ;
        RECT  0 150.528 0.084 150.552 ;
    END
  END c2_p[536]
  PIN c2_p[537]
    DIRECTION INPUT ;
    USE SIGNAL ;
    PORT
      LAYER M4 ;
        RECT  0 150.624 0.084 150.648 ;
    END
  END c2_p[537]
  PIN c2_p[538]
    DIRECTION INPUT ;
    USE SIGNAL ;
    PORT
      LAYER M4 ;
        RECT  0 150.72 0.084 150.744 ;
    END
  END c2_p[538]
  PIN c2_p[539]
    DIRECTION INPUT ;
    USE SIGNAL ;
    PORT
      LAYER M4 ;
        RECT  0 150.816 0.084 150.84 ;
    END
  END c2_p[539]
  PIN c2_p[53]
    DIRECTION INPUT ;
    USE SIGNAL ;
    PORT
      LAYER M4 ;
        RECT  0 104.16 0.084 104.184 ;
    END
  END c2_p[53]
  PIN c2_p[540]
    DIRECTION INPUT ;
    USE SIGNAL ;
    PORT
      LAYER M4 ;
        RECT  0 150.912 0.084 150.936 ;
    END
  END c2_p[540]
  PIN c2_p[541]
    DIRECTION INPUT ;
    USE SIGNAL ;
    PORT
      LAYER M4 ;
        RECT  0 151.008 0.084 151.032 ;
    END
  END c2_p[541]
  PIN c2_p[542]
    DIRECTION INPUT ;
    USE SIGNAL ;
    PORT
      LAYER M4 ;
        RECT  0 151.104 0.084 151.128 ;
    END
  END c2_p[542]
  PIN c2_p[543]
    DIRECTION INPUT ;
    USE SIGNAL ;
    PORT
      LAYER M4 ;
        RECT  0 151.2 0.084 151.224 ;
    END
  END c2_p[543]
  PIN c2_p[544]
    DIRECTION INPUT ;
    USE SIGNAL ;
    PORT
      LAYER M4 ;
        RECT  0 151.296 0.084 151.32 ;
    END
  END c2_p[544]
  PIN c2_p[545]
    DIRECTION INPUT ;
    USE SIGNAL ;
    PORT
      LAYER M4 ;
        RECT  0 151.392 0.084 151.416 ;
    END
  END c2_p[545]
  PIN c2_p[546]
    DIRECTION INPUT ;
    USE SIGNAL ;
    PORT
      LAYER M4 ;
        RECT  0 151.488 0.084 151.512 ;
    END
  END c2_p[546]
  PIN c2_p[547]
    DIRECTION INPUT ;
    USE SIGNAL ;
    PORT
      LAYER M4 ;
        RECT  0 151.584 0.084 151.608 ;
    END
  END c2_p[547]
  PIN c2_p[548]
    DIRECTION INPUT ;
    USE SIGNAL ;
    PORT
      LAYER M4 ;
        RECT  0 151.68 0.084 151.704 ;
    END
  END c2_p[548]
  PIN c2_p[549]
    DIRECTION INPUT ;
    USE SIGNAL ;
    PORT
      LAYER M4 ;
        RECT  0 151.776 0.084 151.8 ;
    END
  END c2_p[549]
  PIN c2_p[54]
    DIRECTION INPUT ;
    USE SIGNAL ;
    PORT
      LAYER M4 ;
        RECT  0 104.256 0.084 104.28 ;
    END
  END c2_p[54]
  PIN c2_p[550]
    DIRECTION INPUT ;
    USE SIGNAL ;
    PORT
      LAYER M4 ;
        RECT  0 151.872 0.084 151.896 ;
    END
  END c2_p[550]
  PIN c2_p[551]
    DIRECTION INPUT ;
    USE SIGNAL ;
    PORT
      LAYER M4 ;
        RECT  0 151.968 0.084 151.992 ;
    END
  END c2_p[551]
  PIN c2_p[552]
    DIRECTION INPUT ;
    USE SIGNAL ;
    PORT
      LAYER M4 ;
        RECT  0 152.064 0.084 152.088 ;
    END
  END c2_p[552]
  PIN c2_p[553]
    DIRECTION INPUT ;
    USE SIGNAL ;
    PORT
      LAYER M4 ;
        RECT  0 152.16 0.084 152.184 ;
    END
  END c2_p[553]
  PIN c2_p[554]
    DIRECTION INPUT ;
    USE SIGNAL ;
    PORT
      LAYER M4 ;
        RECT  0 152.256 0.084 152.28 ;
    END
  END c2_p[554]
  PIN c2_p[555]
    DIRECTION INPUT ;
    USE SIGNAL ;
    PORT
      LAYER M4 ;
        RECT  0 152.352 0.084 152.376 ;
    END
  END c2_p[555]
  PIN c2_p[556]
    DIRECTION INPUT ;
    USE SIGNAL ;
    PORT
      LAYER M4 ;
        RECT  0 152.448 0.084 152.472 ;
    END
  END c2_p[556]
  PIN c2_p[557]
    DIRECTION INPUT ;
    USE SIGNAL ;
    PORT
      LAYER M4 ;
        RECT  0 152.544 0.084 152.568 ;
    END
  END c2_p[557]
  PIN c2_p[558]
    DIRECTION INPUT ;
    USE SIGNAL ;
    PORT
      LAYER M4 ;
        RECT  0 152.64 0.084 152.664 ;
    END
  END c2_p[558]
  PIN c2_p[559]
    DIRECTION INPUT ;
    USE SIGNAL ;
    PORT
      LAYER M4 ;
        RECT  0 152.736 0.084 152.76 ;
    END
  END c2_p[559]
  PIN c2_p[55]
    DIRECTION INPUT ;
    USE SIGNAL ;
    PORT
      LAYER M4 ;
        RECT  0 104.352 0.084 104.376 ;
    END
  END c2_p[55]
  PIN c2_p[560]
    DIRECTION INPUT ;
    USE SIGNAL ;
    PORT
      LAYER M4 ;
        RECT  0 152.832 0.084 152.856 ;
    END
  END c2_p[560]
  PIN c2_p[561]
    DIRECTION INPUT ;
    USE SIGNAL ;
    PORT
      LAYER M4 ;
        RECT  0 152.928 0.084 152.952 ;
    END
  END c2_p[561]
  PIN c2_p[562]
    DIRECTION INPUT ;
    USE SIGNAL ;
    PORT
      LAYER M4 ;
        RECT  0 153.024 0.084 153.048 ;
    END
  END c2_p[562]
  PIN c2_p[563]
    DIRECTION INPUT ;
    USE SIGNAL ;
    PORT
      LAYER M4 ;
        RECT  0 153.12 0.084 153.144 ;
    END
  END c2_p[563]
  PIN c2_p[564]
    DIRECTION INPUT ;
    USE SIGNAL ;
    PORT
      LAYER M4 ;
        RECT  0 153.216 0.084 153.24 ;
    END
  END c2_p[564]
  PIN c2_p[565]
    DIRECTION INPUT ;
    USE SIGNAL ;
    PORT
      LAYER M4 ;
        RECT  0 153.312 0.084 153.336 ;
    END
  END c2_p[565]
  PIN c2_p[566]
    DIRECTION INPUT ;
    USE SIGNAL ;
    PORT
      LAYER M4 ;
        RECT  0 153.408 0.084 153.432 ;
    END
  END c2_p[566]
  PIN c2_p[567]
    DIRECTION INPUT ;
    USE SIGNAL ;
    PORT
      LAYER M4 ;
        RECT  0 153.504 0.084 153.528 ;
    END
  END c2_p[567]
  PIN c2_p[568]
    DIRECTION INPUT ;
    USE SIGNAL ;
    PORT
      LAYER M4 ;
        RECT  0 153.6 0.084 153.624 ;
    END
  END c2_p[568]
  PIN c2_p[569]
    DIRECTION INPUT ;
    USE SIGNAL ;
    PORT
      LAYER M4 ;
        RECT  0 153.696 0.084 153.72 ;
    END
  END c2_p[569]
  PIN c2_p[56]
    DIRECTION INPUT ;
    USE SIGNAL ;
    PORT
      LAYER M4 ;
        RECT  0 104.448 0.084 104.472 ;
    END
  END c2_p[56]
  PIN c2_p[570]
    DIRECTION INPUT ;
    USE SIGNAL ;
    PORT
      LAYER M4 ;
        RECT  0 153.792 0.084 153.816 ;
    END
  END c2_p[570]
  PIN c2_p[571]
    DIRECTION INPUT ;
    USE SIGNAL ;
    PORT
      LAYER M4 ;
        RECT  0 153.888 0.084 153.912 ;
    END
  END c2_p[571]
  PIN c2_p[572]
    DIRECTION INPUT ;
    USE SIGNAL ;
    PORT
      LAYER M4 ;
        RECT  0 153.984 0.084 154.008 ;
    END
  END c2_p[572]
  PIN c2_p[573]
    DIRECTION INPUT ;
    USE SIGNAL ;
    PORT
      LAYER M4 ;
        RECT  0 154.08 0.084 154.104 ;
    END
  END c2_p[573]
  PIN c2_p[574]
    DIRECTION INPUT ;
    USE SIGNAL ;
    PORT
      LAYER M4 ;
        RECT  0 154.176 0.084 154.2 ;
    END
  END c2_p[574]
  PIN c2_p[575]
    DIRECTION INPUT ;
    USE SIGNAL ;
    PORT
      LAYER M4 ;
        RECT  0 154.272 0.084 154.296 ;
    END
  END c2_p[575]
  PIN c2_p[576]
    DIRECTION INPUT ;
    USE SIGNAL ;
    PORT
      LAYER M4 ;
        RECT  0 154.368 0.084 154.392 ;
    END
  END c2_p[576]
  PIN c2_p[577]
    DIRECTION INPUT ;
    USE SIGNAL ;
    PORT
      LAYER M4 ;
        RECT  0 154.464 0.084 154.488 ;
    END
  END c2_p[577]
  PIN c2_p[578]
    DIRECTION INPUT ;
    USE SIGNAL ;
    PORT
      LAYER M4 ;
        RECT  0 154.56 0.084 154.584 ;
    END
  END c2_p[578]
  PIN c2_p[579]
    DIRECTION INPUT ;
    USE SIGNAL ;
    PORT
      LAYER M4 ;
        RECT  0 154.656 0.084 154.68 ;
    END
  END c2_p[579]
  PIN c2_p[57]
    DIRECTION INPUT ;
    USE SIGNAL ;
    PORT
      LAYER M4 ;
        RECT  0 104.544 0.084 104.568 ;
    END
  END c2_p[57]
  PIN c2_p[580]
    DIRECTION INPUT ;
    USE SIGNAL ;
    PORT
      LAYER M4 ;
        RECT  0 154.752 0.084 154.776 ;
    END
  END c2_p[580]
  PIN c2_p[581]
    DIRECTION INPUT ;
    USE SIGNAL ;
    PORT
      LAYER M4 ;
        RECT  0 154.848 0.084 154.872 ;
    END
  END c2_p[581]
  PIN c2_p[582]
    DIRECTION INPUT ;
    USE SIGNAL ;
    PORT
      LAYER M4 ;
        RECT  0 154.944 0.084 154.968 ;
    END
  END c2_p[582]
  PIN c2_p[583]
    DIRECTION INPUT ;
    USE SIGNAL ;
    PORT
      LAYER M4 ;
        RECT  0 155.04 0.084 155.064 ;
    END
  END c2_p[583]
  PIN c2_p[584]
    DIRECTION INPUT ;
    USE SIGNAL ;
    PORT
      LAYER M4 ;
        RECT  0 155.136 0.084 155.16 ;
    END
  END c2_p[584]
  PIN c2_p[585]
    DIRECTION INPUT ;
    USE SIGNAL ;
    PORT
      LAYER M4 ;
        RECT  0 155.232 0.084 155.256 ;
    END
  END c2_p[585]
  PIN c2_p[586]
    DIRECTION INPUT ;
    USE SIGNAL ;
    PORT
      LAYER M4 ;
        RECT  0 155.328 0.084 155.352 ;
    END
  END c2_p[586]
  PIN c2_p[587]
    DIRECTION INPUT ;
    USE SIGNAL ;
    PORT
      LAYER M4 ;
        RECT  0 155.424 0.084 155.448 ;
    END
  END c2_p[587]
  PIN c2_p[588]
    DIRECTION INPUT ;
    USE SIGNAL ;
    PORT
      LAYER M4 ;
        RECT  0 155.52 0.084 155.544 ;
    END
  END c2_p[588]
  PIN c2_p[589]
    DIRECTION INPUT ;
    USE SIGNAL ;
    PORT
      LAYER M4 ;
        RECT  0 155.616 0.084 155.64 ;
    END
  END c2_p[589]
  PIN c2_p[58]
    DIRECTION INPUT ;
    USE SIGNAL ;
    PORT
      LAYER M4 ;
        RECT  0 104.64 0.084 104.664 ;
    END
  END c2_p[58]
  PIN c2_p[590]
    DIRECTION INPUT ;
    USE SIGNAL ;
    PORT
      LAYER M4 ;
        RECT  0 155.712 0.084 155.736 ;
    END
  END c2_p[590]
  PIN c2_p[591]
    DIRECTION INPUT ;
    USE SIGNAL ;
    PORT
      LAYER M4 ;
        RECT  0 155.808 0.084 155.832 ;
    END
  END c2_p[591]
  PIN c2_p[59]
    DIRECTION INPUT ;
    USE SIGNAL ;
    PORT
      LAYER M4 ;
        RECT  0 104.736 0.084 104.76 ;
    END
  END c2_p[59]
  PIN c2_p[5]
    DIRECTION INPUT ;
    USE SIGNAL ;
    PORT
      LAYER M4 ;
        RECT  0 99.552 0.084 99.576 ;
    END
  END c2_p[5]
  PIN c2_p[60]
    DIRECTION INPUT ;
    USE SIGNAL ;
    PORT
      LAYER M4 ;
        RECT  0 104.832 0.084 104.856 ;
    END
  END c2_p[60]
  PIN c2_p[61]
    DIRECTION INPUT ;
    USE SIGNAL ;
    PORT
      LAYER M4 ;
        RECT  0 104.928 0.084 104.952 ;
    END
  END c2_p[61]
  PIN c2_p[62]
    DIRECTION INPUT ;
    USE SIGNAL ;
    PORT
      LAYER M4 ;
        RECT  0 105.024 0.084 105.048 ;
    END
  END c2_p[62]
  PIN c2_p[63]
    DIRECTION INPUT ;
    USE SIGNAL ;
    PORT
      LAYER M4 ;
        RECT  0 105.12 0.084 105.144 ;
    END
  END c2_p[63]
  PIN c2_p[64]
    DIRECTION INPUT ;
    USE SIGNAL ;
    PORT
      LAYER M4 ;
        RECT  0 105.216 0.084 105.24 ;
    END
  END c2_p[64]
  PIN c2_p[65]
    DIRECTION INPUT ;
    USE SIGNAL ;
    PORT
      LAYER M4 ;
        RECT  0 105.312 0.084 105.336 ;
    END
  END c2_p[65]
  PIN c2_p[66]
    DIRECTION INPUT ;
    USE SIGNAL ;
    PORT
      LAYER M4 ;
        RECT  0 105.408 0.084 105.432 ;
    END
  END c2_p[66]
  PIN c2_p[67]
    DIRECTION INPUT ;
    USE SIGNAL ;
    PORT
      LAYER M4 ;
        RECT  0 105.504 0.084 105.528 ;
    END
  END c2_p[67]
  PIN c2_p[68]
    DIRECTION INPUT ;
    USE SIGNAL ;
    PORT
      LAYER M4 ;
        RECT  0 105.6 0.084 105.624 ;
    END
  END c2_p[68]
  PIN c2_p[69]
    DIRECTION INPUT ;
    USE SIGNAL ;
    PORT
      LAYER M4 ;
        RECT  0 105.696 0.084 105.72 ;
    END
  END c2_p[69]
  PIN c2_p[6]
    DIRECTION INPUT ;
    USE SIGNAL ;
    PORT
      LAYER M4 ;
        RECT  0 99.648 0.084 99.672 ;
    END
  END c2_p[6]
  PIN c2_p[70]
    DIRECTION INPUT ;
    USE SIGNAL ;
    PORT
      LAYER M4 ;
        RECT  0 105.792 0.084 105.816 ;
    END
  END c2_p[70]
  PIN c2_p[71]
    DIRECTION INPUT ;
    USE SIGNAL ;
    PORT
      LAYER M4 ;
        RECT  0 105.888 0.084 105.912 ;
    END
  END c2_p[71]
  PIN c2_p[72]
    DIRECTION INPUT ;
    USE SIGNAL ;
    PORT
      LAYER M4 ;
        RECT  0 105.984 0.084 106.008 ;
    END
  END c2_p[72]
  PIN c2_p[73]
    DIRECTION INPUT ;
    USE SIGNAL ;
    PORT
      LAYER M4 ;
        RECT  0 106.08 0.084 106.104 ;
    END
  END c2_p[73]
  PIN c2_p[74]
    DIRECTION INPUT ;
    USE SIGNAL ;
    PORT
      LAYER M4 ;
        RECT  0 106.176 0.084 106.2 ;
    END
  END c2_p[74]
  PIN c2_p[75]
    DIRECTION INPUT ;
    USE SIGNAL ;
    PORT
      LAYER M4 ;
        RECT  0 106.272 0.084 106.296 ;
    END
  END c2_p[75]
  PIN c2_p[76]
    DIRECTION INPUT ;
    USE SIGNAL ;
    PORT
      LAYER M4 ;
        RECT  0 106.368 0.084 106.392 ;
    END
  END c2_p[76]
  PIN c2_p[77]
    DIRECTION INPUT ;
    USE SIGNAL ;
    PORT
      LAYER M4 ;
        RECT  0 106.464 0.084 106.488 ;
    END
  END c2_p[77]
  PIN c2_p[78]
    DIRECTION INPUT ;
    USE SIGNAL ;
    PORT
      LAYER M4 ;
        RECT  0 106.56 0.084 106.584 ;
    END
  END c2_p[78]
  PIN c2_p[79]
    DIRECTION INPUT ;
    USE SIGNAL ;
    PORT
      LAYER M4 ;
        RECT  0 106.656 0.084 106.68 ;
    END
  END c2_p[79]
  PIN c2_p[7]
    DIRECTION INPUT ;
    USE SIGNAL ;
    PORT
      LAYER M4 ;
        RECT  0 99.744 0.084 99.768 ;
    END
  END c2_p[7]
  PIN c2_p[80]
    DIRECTION INPUT ;
    USE SIGNAL ;
    PORT
      LAYER M4 ;
        RECT  0 106.752 0.084 106.776 ;
    END
  END c2_p[80]
  PIN c2_p[81]
    DIRECTION INPUT ;
    USE SIGNAL ;
    PORT
      LAYER M4 ;
        RECT  0 106.848 0.084 106.872 ;
    END
  END c2_p[81]
  PIN c2_p[82]
    DIRECTION INPUT ;
    USE SIGNAL ;
    PORT
      LAYER M4 ;
        RECT  0 106.944 0.084 106.968 ;
    END
  END c2_p[82]
  PIN c2_p[83]
    DIRECTION INPUT ;
    USE SIGNAL ;
    PORT
      LAYER M4 ;
        RECT  0 107.04 0.084 107.064 ;
    END
  END c2_p[83]
  PIN c2_p[84]
    DIRECTION INPUT ;
    USE SIGNAL ;
    PORT
      LAYER M4 ;
        RECT  0 107.136 0.084 107.16 ;
    END
  END c2_p[84]
  PIN c2_p[85]
    DIRECTION INPUT ;
    USE SIGNAL ;
    PORT
      LAYER M4 ;
        RECT  0 107.232 0.084 107.256 ;
    END
  END c2_p[85]
  PIN c2_p[86]
    DIRECTION INPUT ;
    USE SIGNAL ;
    PORT
      LAYER M4 ;
        RECT  0 107.328 0.084 107.352 ;
    END
  END c2_p[86]
  PIN c2_p[87]
    DIRECTION INPUT ;
    USE SIGNAL ;
    PORT
      LAYER M4 ;
        RECT  0 107.424 0.084 107.448 ;
    END
  END c2_p[87]
  PIN c2_p[88]
    DIRECTION INPUT ;
    USE SIGNAL ;
    PORT
      LAYER M4 ;
        RECT  0 107.52 0.084 107.544 ;
    END
  END c2_p[88]
  PIN c2_p[89]
    DIRECTION INPUT ;
    USE SIGNAL ;
    PORT
      LAYER M4 ;
        RECT  0 107.616 0.084 107.64 ;
    END
  END c2_p[89]
  PIN c2_p[8]
    DIRECTION INPUT ;
    USE SIGNAL ;
    PORT
      LAYER M4 ;
        RECT  0 99.84 0.084 99.864 ;
    END
  END c2_p[8]
  PIN c2_p[90]
    DIRECTION INPUT ;
    USE SIGNAL ;
    PORT
      LAYER M4 ;
        RECT  0 107.712 0.084 107.736 ;
    END
  END c2_p[90]
  PIN c2_p[91]
    DIRECTION INPUT ;
    USE SIGNAL ;
    PORT
      LAYER M4 ;
        RECT  0 107.808 0.084 107.832 ;
    END
  END c2_p[91]
  PIN c2_p[92]
    DIRECTION INPUT ;
    USE SIGNAL ;
    PORT
      LAYER M4 ;
        RECT  0 107.904 0.084 107.928 ;
    END
  END c2_p[92]
  PIN c2_p[93]
    DIRECTION INPUT ;
    USE SIGNAL ;
    PORT
      LAYER M4 ;
        RECT  0 108 0.084 108.024 ;
    END
  END c2_p[93]
  PIN c2_p[94]
    DIRECTION INPUT ;
    USE SIGNAL ;
    PORT
      LAYER M4 ;
        RECT  0 108.096 0.084 108.12 ;
    END
  END c2_p[94]
  PIN c2_p[95]
    DIRECTION INPUT ;
    USE SIGNAL ;
    PORT
      LAYER M4 ;
        RECT  0 108.192 0.084 108.216 ;
    END
  END c2_p[95]
  PIN c2_p[96]
    DIRECTION INPUT ;
    USE SIGNAL ;
    PORT
      LAYER M4 ;
        RECT  0 108.288 0.084 108.312 ;
    END
  END c2_p[96]
  PIN c2_p[97]
    DIRECTION INPUT ;
    USE SIGNAL ;
    PORT
      LAYER M4 ;
        RECT  0 108.384 0.084 108.408 ;
    END
  END c2_p[97]
  PIN c2_p[98]
    DIRECTION INPUT ;
    USE SIGNAL ;
    PORT
      LAYER M4 ;
        RECT  0 108.48 0.084 108.504 ;
    END
  END c2_p[98]
  PIN c2_p[99]
    DIRECTION INPUT ;
    USE SIGNAL ;
    PORT
      LAYER M4 ;
        RECT  0 108.576 0.084 108.6 ;
    END
  END c2_p[99]
  PIN c2_p[9]
    DIRECTION INPUT ;
    USE SIGNAL ;
    PORT
      LAYER M4 ;
        RECT  0 99.936 0.084 99.96 ;
    END
  END c2_p[9]
  PIN c2_v
    DIRECTION INPUT ;
    USE SIGNAL ;
    PORT
      LAYER M4 ;
        RECT  0 38.976 0.084 39 ;
    END
  END c2_v
  PIN c3_sel_d[0]
    DIRECTION INPUT ;
    USE SIGNAL ;
    PORT
      LAYER M4 ;
        RECT  0 40.704 0.084 40.728 ;
    END
  END c3_sel_d[0]
  PIN c3_sel_d[10]
    DIRECTION INPUT ;
    USE SIGNAL ;
    PORT
      LAYER M4 ;
        RECT  0 41.664 0.084 41.688 ;
    END
  END c3_sel_d[10]
  PIN c3_sel_d[11]
    DIRECTION INPUT ;
    USE SIGNAL ;
    PORT
      LAYER M4 ;
        RECT  0 41.76 0.084 41.784 ;
    END
  END c3_sel_d[11]
  PIN c3_sel_d[12]
    DIRECTION INPUT ;
    USE SIGNAL ;
    PORT
      LAYER M4 ;
        RECT  0 41.856 0.084 41.88 ;
    END
  END c3_sel_d[12]
  PIN c3_sel_d[13]
    DIRECTION INPUT ;
    USE SIGNAL ;
    PORT
      LAYER M4 ;
        RECT  0 41.952 0.084 41.976 ;
    END
  END c3_sel_d[13]
  PIN c3_sel_d[14]
    DIRECTION INPUT ;
    USE SIGNAL ;
    PORT
      LAYER M4 ;
        RECT  0 42.048 0.084 42.072 ;
    END
  END c3_sel_d[14]
  PIN c3_sel_d[15]
    DIRECTION INPUT ;
    USE SIGNAL ;
    PORT
      LAYER M4 ;
        RECT  0 42.144 0.084 42.168 ;
    END
  END c3_sel_d[15]
  PIN c3_sel_d[1]
    DIRECTION INPUT ;
    USE SIGNAL ;
    PORT
      LAYER M4 ;
        RECT  0 40.8 0.084 40.824 ;
    END
  END c3_sel_d[1]
  PIN c3_sel_d[2]
    DIRECTION INPUT ;
    USE SIGNAL ;
    PORT
      LAYER M4 ;
        RECT  0 40.896 0.084 40.92 ;
    END
  END c3_sel_d[2]
  PIN c3_sel_d[3]
    DIRECTION INPUT ;
    USE SIGNAL ;
    PORT
      LAYER M4 ;
        RECT  0 40.992 0.084 41.016 ;
    END
  END c3_sel_d[3]
  PIN c3_sel_d[4]
    DIRECTION INPUT ;
    USE SIGNAL ;
    PORT
      LAYER M4 ;
        RECT  0 41.088 0.084 41.112 ;
    END
  END c3_sel_d[4]
  PIN c3_sel_d[5]
    DIRECTION INPUT ;
    USE SIGNAL ;
    PORT
      LAYER M4 ;
        RECT  0 41.184 0.084 41.208 ;
    END
  END c3_sel_d[5]
  PIN c3_sel_d[6]
    DIRECTION INPUT ;
    USE SIGNAL ;
    PORT
      LAYER M4 ;
        RECT  0 41.28 0.084 41.304 ;
    END
  END c3_sel_d[6]
  PIN c3_sel_d[7]
    DIRECTION INPUT ;
    USE SIGNAL ;
    PORT
      LAYER M4 ;
        RECT  0 41.376 0.084 41.4 ;
    END
  END c3_sel_d[7]
  PIN c3_sel_d[8]
    DIRECTION INPUT ;
    USE SIGNAL ;
    PORT
      LAYER M4 ;
        RECT  0 41.472 0.084 41.496 ;
    END
  END c3_sel_d[8]
  PIN c3_sel_d[9]
    DIRECTION INPUT ;
    USE SIGNAL ;
    PORT
      LAYER M4 ;
        RECT  0 41.568 0.084 41.592 ;
    END
  END c3_sel_d[9]
  PIN clk
    DIRECTION INPUT ;
    USE SIGNAL ;
    PORT
      LAYER M5 ;
        RECT  97.2 0 97.224 0.084 ;
    END
  END clk
  PIN i0_lane[0]
    DIRECTION INPUT ;
    USE SIGNAL ;
    PORT
      LAYER M4 ;
        RECT  0 42.24 0.084 42.264 ;
    END
  END i0_lane[0]
  PIN i0_lane[100]
    DIRECTION INPUT ;
    USE SIGNAL ;
    PORT
      LAYER M4 ;
        RECT  0 51.84 0.084 51.864 ;
    END
  END i0_lane[100]
  PIN i0_lane[101]
    DIRECTION INPUT ;
    USE SIGNAL ;
    PORT
      LAYER M4 ;
        RECT  0 51.936 0.084 51.96 ;
    END
  END i0_lane[101]
  PIN i0_lane[102]
    DIRECTION INPUT ;
    USE SIGNAL ;
    PORT
      LAYER M4 ;
        RECT  0 52.032 0.084 52.056 ;
    END
  END i0_lane[102]
  PIN i0_lane[103]
    DIRECTION INPUT ;
    USE SIGNAL ;
    PORT
      LAYER M4 ;
        RECT  0 52.128 0.084 52.152 ;
    END
  END i0_lane[103]
  PIN i0_lane[104]
    DIRECTION INPUT ;
    USE SIGNAL ;
    PORT
      LAYER M4 ;
        RECT  0 52.224 0.084 52.248 ;
    END
  END i0_lane[104]
  PIN i0_lane[105]
    DIRECTION INPUT ;
    USE SIGNAL ;
    PORT
      LAYER M4 ;
        RECT  0 52.32 0.084 52.344 ;
    END
  END i0_lane[105]
  PIN i0_lane[106]
    DIRECTION INPUT ;
    USE SIGNAL ;
    PORT
      LAYER M4 ;
        RECT  0 52.416 0.084 52.44 ;
    END
  END i0_lane[106]
  PIN i0_lane[107]
    DIRECTION INPUT ;
    USE SIGNAL ;
    PORT
      LAYER M4 ;
        RECT  0 52.512 0.084 52.536 ;
    END
  END i0_lane[107]
  PIN i0_lane[108]
    DIRECTION INPUT ;
    USE SIGNAL ;
    PORT
      LAYER M4 ;
        RECT  0 52.608 0.084 52.632 ;
    END
  END i0_lane[108]
  PIN i0_lane[109]
    DIRECTION INPUT ;
    USE SIGNAL ;
    PORT
      LAYER M4 ;
        RECT  0 52.704 0.084 52.728 ;
    END
  END i0_lane[109]
  PIN i0_lane[10]
    DIRECTION INPUT ;
    USE SIGNAL ;
    PORT
      LAYER M4 ;
        RECT  0 43.2 0.084 43.224 ;
    END
  END i0_lane[10]
  PIN i0_lane[110]
    DIRECTION INPUT ;
    USE SIGNAL ;
    PORT
      LAYER M4 ;
        RECT  0 52.8 0.084 52.824 ;
    END
  END i0_lane[110]
  PIN i0_lane[111]
    DIRECTION INPUT ;
    USE SIGNAL ;
    PORT
      LAYER M4 ;
        RECT  0 52.896 0.084 52.92 ;
    END
  END i0_lane[111]
  PIN i0_lane[112]
    DIRECTION INPUT ;
    USE SIGNAL ;
    PORT
      LAYER M4 ;
        RECT  0 52.992 0.084 53.016 ;
    END
  END i0_lane[112]
  PIN i0_lane[113]
    DIRECTION INPUT ;
    USE SIGNAL ;
    PORT
      LAYER M4 ;
        RECT  0 53.088 0.084 53.112 ;
    END
  END i0_lane[113]
  PIN i0_lane[114]
    DIRECTION INPUT ;
    USE SIGNAL ;
    PORT
      LAYER M4 ;
        RECT  0 53.184 0.084 53.208 ;
    END
  END i0_lane[114]
  PIN i0_lane[115]
    DIRECTION INPUT ;
    USE SIGNAL ;
    PORT
      LAYER M4 ;
        RECT  0 53.28 0.084 53.304 ;
    END
  END i0_lane[115]
  PIN i0_lane[116]
    DIRECTION INPUT ;
    USE SIGNAL ;
    PORT
      LAYER M4 ;
        RECT  0 53.376 0.084 53.4 ;
    END
  END i0_lane[116]
  PIN i0_lane[117]
    DIRECTION INPUT ;
    USE SIGNAL ;
    PORT
      LAYER M4 ;
        RECT  0 53.472 0.084 53.496 ;
    END
  END i0_lane[117]
  PIN i0_lane[118]
    DIRECTION INPUT ;
    USE SIGNAL ;
    PORT
      LAYER M4 ;
        RECT  0 53.568 0.084 53.592 ;
    END
  END i0_lane[118]
  PIN i0_lane[119]
    DIRECTION INPUT ;
    USE SIGNAL ;
    PORT
      LAYER M4 ;
        RECT  0 53.664 0.084 53.688 ;
    END
  END i0_lane[119]
  PIN i0_lane[11]
    DIRECTION INPUT ;
    USE SIGNAL ;
    PORT
      LAYER M4 ;
        RECT  0 43.296 0.084 43.32 ;
    END
  END i0_lane[11]
  PIN i0_lane[120]
    DIRECTION INPUT ;
    USE SIGNAL ;
    PORT
      LAYER M4 ;
        RECT  0 53.76 0.084 53.784 ;
    END
  END i0_lane[120]
  PIN i0_lane[121]
    DIRECTION INPUT ;
    USE SIGNAL ;
    PORT
      LAYER M4 ;
        RECT  0 53.856 0.084 53.88 ;
    END
  END i0_lane[121]
  PIN i0_lane[122]
    DIRECTION INPUT ;
    USE SIGNAL ;
    PORT
      LAYER M4 ;
        RECT  0 53.952 0.084 53.976 ;
    END
  END i0_lane[122]
  PIN i0_lane[123]
    DIRECTION INPUT ;
    USE SIGNAL ;
    PORT
      LAYER M4 ;
        RECT  0 54.048 0.084 54.072 ;
    END
  END i0_lane[123]
  PIN i0_lane[124]
    DIRECTION INPUT ;
    USE SIGNAL ;
    PORT
      LAYER M4 ;
        RECT  0 54.144 0.084 54.168 ;
    END
  END i0_lane[124]
  PIN i0_lane[125]
    DIRECTION INPUT ;
    USE SIGNAL ;
    PORT
      LAYER M4 ;
        RECT  0 54.24 0.084 54.264 ;
    END
  END i0_lane[125]
  PIN i0_lane[126]
    DIRECTION INPUT ;
    USE SIGNAL ;
    PORT
      LAYER M4 ;
        RECT  0 54.336 0.084 54.36 ;
    END
  END i0_lane[126]
  PIN i0_lane[127]
    DIRECTION INPUT ;
    USE SIGNAL ;
    PORT
      LAYER M4 ;
        RECT  0 54.432 0.084 54.456 ;
    END
  END i0_lane[127]
  PIN i0_lane[128]
    DIRECTION INPUT ;
    USE SIGNAL ;
    PORT
      LAYER M4 ;
        RECT  0 54.528 0.084 54.552 ;
    END
  END i0_lane[128]
  PIN i0_lane[129]
    DIRECTION INPUT ;
    USE SIGNAL ;
    PORT
      LAYER M4 ;
        RECT  0 54.624 0.084 54.648 ;
    END
  END i0_lane[129]
  PIN i0_lane[12]
    DIRECTION INPUT ;
    USE SIGNAL ;
    PORT
      LAYER M4 ;
        RECT  0 43.392 0.084 43.416 ;
    END
  END i0_lane[12]
  PIN i0_lane[130]
    DIRECTION INPUT ;
    USE SIGNAL ;
    PORT
      LAYER M4 ;
        RECT  0 54.72 0.084 54.744 ;
    END
  END i0_lane[130]
  PIN i0_lane[131]
    DIRECTION INPUT ;
    USE SIGNAL ;
    PORT
      LAYER M4 ;
        RECT  0 54.816 0.084 54.84 ;
    END
  END i0_lane[131]
  PIN i0_lane[132]
    DIRECTION INPUT ;
    USE SIGNAL ;
    PORT
      LAYER M4 ;
        RECT  0 54.912 0.084 54.936 ;
    END
  END i0_lane[132]
  PIN i0_lane[133]
    DIRECTION INPUT ;
    USE SIGNAL ;
    PORT
      LAYER M4 ;
        RECT  0 55.008 0.084 55.032 ;
    END
  END i0_lane[133]
  PIN i0_lane[134]
    DIRECTION INPUT ;
    USE SIGNAL ;
    PORT
      LAYER M4 ;
        RECT  0 55.104 0.084 55.128 ;
    END
  END i0_lane[134]
  PIN i0_lane[135]
    DIRECTION INPUT ;
    USE SIGNAL ;
    PORT
      LAYER M4 ;
        RECT  0 55.2 0.084 55.224 ;
    END
  END i0_lane[135]
  PIN i0_lane[136]
    DIRECTION INPUT ;
    USE SIGNAL ;
    PORT
      LAYER M4 ;
        RECT  0 55.296 0.084 55.32 ;
    END
  END i0_lane[136]
  PIN i0_lane[137]
    DIRECTION INPUT ;
    USE SIGNAL ;
    PORT
      LAYER M4 ;
        RECT  0 55.392 0.084 55.416 ;
    END
  END i0_lane[137]
  PIN i0_lane[138]
    DIRECTION INPUT ;
    USE SIGNAL ;
    PORT
      LAYER M4 ;
        RECT  0 55.488 0.084 55.512 ;
    END
  END i0_lane[138]
  PIN i0_lane[139]
    DIRECTION INPUT ;
    USE SIGNAL ;
    PORT
      LAYER M4 ;
        RECT  0 55.584 0.084 55.608 ;
    END
  END i0_lane[139]
  PIN i0_lane[13]
    DIRECTION INPUT ;
    USE SIGNAL ;
    PORT
      LAYER M4 ;
        RECT  0 43.488 0.084 43.512 ;
    END
  END i0_lane[13]
  PIN i0_lane[140]
    DIRECTION INPUT ;
    USE SIGNAL ;
    PORT
      LAYER M4 ;
        RECT  0 55.68 0.084 55.704 ;
    END
  END i0_lane[140]
  PIN i0_lane[141]
    DIRECTION INPUT ;
    USE SIGNAL ;
    PORT
      LAYER M4 ;
        RECT  0 55.776 0.084 55.8 ;
    END
  END i0_lane[141]
  PIN i0_lane[142]
    DIRECTION INPUT ;
    USE SIGNAL ;
    PORT
      LAYER M4 ;
        RECT  0 55.872 0.084 55.896 ;
    END
  END i0_lane[142]
  PIN i0_lane[143]
    DIRECTION INPUT ;
    USE SIGNAL ;
    PORT
      LAYER M4 ;
        RECT  0 55.968 0.084 55.992 ;
    END
  END i0_lane[143]
  PIN i0_lane[144]
    DIRECTION INPUT ;
    USE SIGNAL ;
    PORT
      LAYER M4 ;
        RECT  0 56.064 0.084 56.088 ;
    END
  END i0_lane[144]
  PIN i0_lane[145]
    DIRECTION INPUT ;
    USE SIGNAL ;
    PORT
      LAYER M4 ;
        RECT  0 56.16 0.084 56.184 ;
    END
  END i0_lane[145]
  PIN i0_lane[146]
    DIRECTION INPUT ;
    USE SIGNAL ;
    PORT
      LAYER M4 ;
        RECT  0 56.256 0.084 56.28 ;
    END
  END i0_lane[146]
  PIN i0_lane[147]
    DIRECTION INPUT ;
    USE SIGNAL ;
    PORT
      LAYER M4 ;
        RECT  0 56.352 0.084 56.376 ;
    END
  END i0_lane[147]
  PIN i0_lane[148]
    DIRECTION INPUT ;
    USE SIGNAL ;
    PORT
      LAYER M4 ;
        RECT  0 56.448 0.084 56.472 ;
    END
  END i0_lane[148]
  PIN i0_lane[149]
    DIRECTION INPUT ;
    USE SIGNAL ;
    PORT
      LAYER M4 ;
        RECT  0 56.544 0.084 56.568 ;
    END
  END i0_lane[149]
  PIN i0_lane[14]
    DIRECTION INPUT ;
    USE SIGNAL ;
    PORT
      LAYER M4 ;
        RECT  0 43.584 0.084 43.608 ;
    END
  END i0_lane[14]
  PIN i0_lane[150]
    DIRECTION INPUT ;
    USE SIGNAL ;
    PORT
      LAYER M4 ;
        RECT  0 56.64 0.084 56.664 ;
    END
  END i0_lane[150]
  PIN i0_lane[151]
    DIRECTION INPUT ;
    USE SIGNAL ;
    PORT
      LAYER M4 ;
        RECT  0 56.736 0.084 56.76 ;
    END
  END i0_lane[151]
  PIN i0_lane[152]
    DIRECTION INPUT ;
    USE SIGNAL ;
    PORT
      LAYER M4 ;
        RECT  0 56.832 0.084 56.856 ;
    END
  END i0_lane[152]
  PIN i0_lane[153]
    DIRECTION INPUT ;
    USE SIGNAL ;
    PORT
      LAYER M4 ;
        RECT  0 56.928 0.084 56.952 ;
    END
  END i0_lane[153]
  PIN i0_lane[154]
    DIRECTION INPUT ;
    USE SIGNAL ;
    PORT
      LAYER M4 ;
        RECT  0 57.024 0.084 57.048 ;
    END
  END i0_lane[154]
  PIN i0_lane[155]
    DIRECTION INPUT ;
    USE SIGNAL ;
    PORT
      LAYER M4 ;
        RECT  0 57.12 0.084 57.144 ;
    END
  END i0_lane[155]
  PIN i0_lane[156]
    DIRECTION INPUT ;
    USE SIGNAL ;
    PORT
      LAYER M4 ;
        RECT  0 57.216 0.084 57.24 ;
    END
  END i0_lane[156]
  PIN i0_lane[157]
    DIRECTION INPUT ;
    USE SIGNAL ;
    PORT
      LAYER M4 ;
        RECT  0 57.312 0.084 57.336 ;
    END
  END i0_lane[157]
  PIN i0_lane[158]
    DIRECTION INPUT ;
    USE SIGNAL ;
    PORT
      LAYER M4 ;
        RECT  0 57.408 0.084 57.432 ;
    END
  END i0_lane[158]
  PIN i0_lane[159]
    DIRECTION INPUT ;
    USE SIGNAL ;
    PORT
      LAYER M4 ;
        RECT  0 57.504 0.084 57.528 ;
    END
  END i0_lane[159]
  PIN i0_lane[15]
    DIRECTION INPUT ;
    USE SIGNAL ;
    PORT
      LAYER M4 ;
        RECT  0 43.68 0.084 43.704 ;
    END
  END i0_lane[15]
  PIN i0_lane[160]
    DIRECTION INPUT ;
    USE SIGNAL ;
    PORT
      LAYER M4 ;
        RECT  0 57.6 0.084 57.624 ;
    END
  END i0_lane[160]
  PIN i0_lane[161]
    DIRECTION INPUT ;
    USE SIGNAL ;
    PORT
      LAYER M4 ;
        RECT  0 57.696 0.084 57.72 ;
    END
  END i0_lane[161]
  PIN i0_lane[162]
    DIRECTION INPUT ;
    USE SIGNAL ;
    PORT
      LAYER M4 ;
        RECT  0 57.792 0.084 57.816 ;
    END
  END i0_lane[162]
  PIN i0_lane[163]
    DIRECTION INPUT ;
    USE SIGNAL ;
    PORT
      LAYER M4 ;
        RECT  0 57.888 0.084 57.912 ;
    END
  END i0_lane[163]
  PIN i0_lane[164]
    DIRECTION INPUT ;
    USE SIGNAL ;
    PORT
      LAYER M4 ;
        RECT  0 57.984 0.084 58.008 ;
    END
  END i0_lane[164]
  PIN i0_lane[165]
    DIRECTION INPUT ;
    USE SIGNAL ;
    PORT
      LAYER M4 ;
        RECT  0 58.08 0.084 58.104 ;
    END
  END i0_lane[165]
  PIN i0_lane[166]
    DIRECTION INPUT ;
    USE SIGNAL ;
    PORT
      LAYER M4 ;
        RECT  0 58.176 0.084 58.2 ;
    END
  END i0_lane[166]
  PIN i0_lane[167]
    DIRECTION INPUT ;
    USE SIGNAL ;
    PORT
      LAYER M4 ;
        RECT  0 58.272 0.084 58.296 ;
    END
  END i0_lane[167]
  PIN i0_lane[168]
    DIRECTION INPUT ;
    USE SIGNAL ;
    PORT
      LAYER M4 ;
        RECT  0 58.368 0.084 58.392 ;
    END
  END i0_lane[168]
  PIN i0_lane[169]
    DIRECTION INPUT ;
    USE SIGNAL ;
    PORT
      LAYER M4 ;
        RECT  0 58.464 0.084 58.488 ;
    END
  END i0_lane[169]
  PIN i0_lane[16]
    DIRECTION INPUT ;
    USE SIGNAL ;
    PORT
      LAYER M4 ;
        RECT  0 43.776 0.084 43.8 ;
    END
  END i0_lane[16]
  PIN i0_lane[170]
    DIRECTION INPUT ;
    USE SIGNAL ;
    PORT
      LAYER M4 ;
        RECT  0 58.56 0.084 58.584 ;
    END
  END i0_lane[170]
  PIN i0_lane[171]
    DIRECTION INPUT ;
    USE SIGNAL ;
    PORT
      LAYER M4 ;
        RECT  0 58.656 0.084 58.68 ;
    END
  END i0_lane[171]
  PIN i0_lane[172]
    DIRECTION INPUT ;
    USE SIGNAL ;
    PORT
      LAYER M4 ;
        RECT  0 58.752 0.084 58.776 ;
    END
  END i0_lane[172]
  PIN i0_lane[173]
    DIRECTION INPUT ;
    USE SIGNAL ;
    PORT
      LAYER M4 ;
        RECT  0 58.848 0.084 58.872 ;
    END
  END i0_lane[173]
  PIN i0_lane[174]
    DIRECTION INPUT ;
    USE SIGNAL ;
    PORT
      LAYER M4 ;
        RECT  0 58.944 0.084 58.968 ;
    END
  END i0_lane[174]
  PIN i0_lane[175]
    DIRECTION INPUT ;
    USE SIGNAL ;
    PORT
      LAYER M4 ;
        RECT  0 59.04 0.084 59.064 ;
    END
  END i0_lane[175]
  PIN i0_lane[176]
    DIRECTION INPUT ;
    USE SIGNAL ;
    PORT
      LAYER M4 ;
        RECT  0 59.136 0.084 59.16 ;
    END
  END i0_lane[176]
  PIN i0_lane[177]
    DIRECTION INPUT ;
    USE SIGNAL ;
    PORT
      LAYER M4 ;
        RECT  0 59.232 0.084 59.256 ;
    END
  END i0_lane[177]
  PIN i0_lane[178]
    DIRECTION INPUT ;
    USE SIGNAL ;
    PORT
      LAYER M4 ;
        RECT  0 59.328 0.084 59.352 ;
    END
  END i0_lane[178]
  PIN i0_lane[179]
    DIRECTION INPUT ;
    USE SIGNAL ;
    PORT
      LAYER M4 ;
        RECT  0 59.424 0.084 59.448 ;
    END
  END i0_lane[179]
  PIN i0_lane[17]
    DIRECTION INPUT ;
    USE SIGNAL ;
    PORT
      LAYER M4 ;
        RECT  0 43.872 0.084 43.896 ;
    END
  END i0_lane[17]
  PIN i0_lane[180]
    DIRECTION INPUT ;
    USE SIGNAL ;
    PORT
      LAYER M4 ;
        RECT  0 59.52 0.084 59.544 ;
    END
  END i0_lane[180]
  PIN i0_lane[181]
    DIRECTION INPUT ;
    USE SIGNAL ;
    PORT
      LAYER M4 ;
        RECT  0 59.616 0.084 59.64 ;
    END
  END i0_lane[181]
  PIN i0_lane[182]
    DIRECTION INPUT ;
    USE SIGNAL ;
    PORT
      LAYER M4 ;
        RECT  0 59.712 0.084 59.736 ;
    END
  END i0_lane[182]
  PIN i0_lane[183]
    DIRECTION INPUT ;
    USE SIGNAL ;
    PORT
      LAYER M4 ;
        RECT  0 59.808 0.084 59.832 ;
    END
  END i0_lane[183]
  PIN i0_lane[184]
    DIRECTION INPUT ;
    USE SIGNAL ;
    PORT
      LAYER M4 ;
        RECT  0 59.904 0.084 59.928 ;
    END
  END i0_lane[184]
  PIN i0_lane[185]
    DIRECTION INPUT ;
    USE SIGNAL ;
    PORT
      LAYER M4 ;
        RECT  0 60 0.084 60.024 ;
    END
  END i0_lane[185]
  PIN i0_lane[186]
    DIRECTION INPUT ;
    USE SIGNAL ;
    PORT
      LAYER M4 ;
        RECT  0 60.096 0.084 60.12 ;
    END
  END i0_lane[186]
  PIN i0_lane[187]
    DIRECTION INPUT ;
    USE SIGNAL ;
    PORT
      LAYER M4 ;
        RECT  0 60.192 0.084 60.216 ;
    END
  END i0_lane[187]
  PIN i0_lane[188]
    DIRECTION INPUT ;
    USE SIGNAL ;
    PORT
      LAYER M4 ;
        RECT  0 60.288 0.084 60.312 ;
    END
  END i0_lane[188]
  PIN i0_lane[189]
    DIRECTION INPUT ;
    USE SIGNAL ;
    PORT
      LAYER M4 ;
        RECT  0 60.384 0.084 60.408 ;
    END
  END i0_lane[189]
  PIN i0_lane[18]
    DIRECTION INPUT ;
    USE SIGNAL ;
    PORT
      LAYER M4 ;
        RECT  0 43.968 0.084 43.992 ;
    END
  END i0_lane[18]
  PIN i0_lane[190]
    DIRECTION INPUT ;
    USE SIGNAL ;
    PORT
      LAYER M4 ;
        RECT  0 60.48 0.084 60.504 ;
    END
  END i0_lane[190]
  PIN i0_lane[191]
    DIRECTION INPUT ;
    USE SIGNAL ;
    PORT
      LAYER M4 ;
        RECT  0 60.576 0.084 60.6 ;
    END
  END i0_lane[191]
  PIN i0_lane[192]
    DIRECTION INPUT ;
    USE SIGNAL ;
    PORT
      LAYER M4 ;
        RECT  0 60.672 0.084 60.696 ;
    END
  END i0_lane[192]
  PIN i0_lane[193]
    DIRECTION INPUT ;
    USE SIGNAL ;
    PORT
      LAYER M4 ;
        RECT  0 60.768 0.084 60.792 ;
    END
  END i0_lane[193]
  PIN i0_lane[194]
    DIRECTION INPUT ;
    USE SIGNAL ;
    PORT
      LAYER M4 ;
        RECT  0 60.864 0.084 60.888 ;
    END
  END i0_lane[194]
  PIN i0_lane[195]
    DIRECTION INPUT ;
    USE SIGNAL ;
    PORT
      LAYER M4 ;
        RECT  0 60.96 0.084 60.984 ;
    END
  END i0_lane[195]
  PIN i0_lane[196]
    DIRECTION INPUT ;
    USE SIGNAL ;
    PORT
      LAYER M4 ;
        RECT  0 61.056 0.084 61.08 ;
    END
  END i0_lane[196]
  PIN i0_lane[197]
    DIRECTION INPUT ;
    USE SIGNAL ;
    PORT
      LAYER M4 ;
        RECT  0 61.152 0.084 61.176 ;
    END
  END i0_lane[197]
  PIN i0_lane[198]
    DIRECTION INPUT ;
    USE SIGNAL ;
    PORT
      LAYER M4 ;
        RECT  0 61.248 0.084 61.272 ;
    END
  END i0_lane[198]
  PIN i0_lane[199]
    DIRECTION INPUT ;
    USE SIGNAL ;
    PORT
      LAYER M4 ;
        RECT  0 61.344 0.084 61.368 ;
    END
  END i0_lane[199]
  PIN i0_lane[19]
    DIRECTION INPUT ;
    USE SIGNAL ;
    PORT
      LAYER M4 ;
        RECT  0 44.064 0.084 44.088 ;
    END
  END i0_lane[19]
  PIN i0_lane[1]
    DIRECTION INPUT ;
    USE SIGNAL ;
    PORT
      LAYER M4 ;
        RECT  0 42.336 0.084 42.36 ;
    END
  END i0_lane[1]
  PIN i0_lane[200]
    DIRECTION INPUT ;
    USE SIGNAL ;
    PORT
      LAYER M4 ;
        RECT  0 61.44 0.084 61.464 ;
    END
  END i0_lane[200]
  PIN i0_lane[201]
    DIRECTION INPUT ;
    USE SIGNAL ;
    PORT
      LAYER M4 ;
        RECT  0 61.536 0.084 61.56 ;
    END
  END i0_lane[201]
  PIN i0_lane[202]
    DIRECTION INPUT ;
    USE SIGNAL ;
    PORT
      LAYER M4 ;
        RECT  0 61.632 0.084 61.656 ;
    END
  END i0_lane[202]
  PIN i0_lane[203]
    DIRECTION INPUT ;
    USE SIGNAL ;
    PORT
      LAYER M4 ;
        RECT  0 61.728 0.084 61.752 ;
    END
  END i0_lane[203]
  PIN i0_lane[204]
    DIRECTION INPUT ;
    USE SIGNAL ;
    PORT
      LAYER M4 ;
        RECT  0 61.824 0.084 61.848 ;
    END
  END i0_lane[204]
  PIN i0_lane[205]
    DIRECTION INPUT ;
    USE SIGNAL ;
    PORT
      LAYER M4 ;
        RECT  0 61.92 0.084 61.944 ;
    END
  END i0_lane[205]
  PIN i0_lane[206]
    DIRECTION INPUT ;
    USE SIGNAL ;
    PORT
      LAYER M4 ;
        RECT  0 62.016 0.084 62.04 ;
    END
  END i0_lane[206]
  PIN i0_lane[207]
    DIRECTION INPUT ;
    USE SIGNAL ;
    PORT
      LAYER M4 ;
        RECT  0 62.112 0.084 62.136 ;
    END
  END i0_lane[207]
  PIN i0_lane[208]
    DIRECTION INPUT ;
    USE SIGNAL ;
    PORT
      LAYER M4 ;
        RECT  0 62.208 0.084 62.232 ;
    END
  END i0_lane[208]
  PIN i0_lane[209]
    DIRECTION INPUT ;
    USE SIGNAL ;
    PORT
      LAYER M4 ;
        RECT  0 62.304 0.084 62.328 ;
    END
  END i0_lane[209]
  PIN i0_lane[20]
    DIRECTION INPUT ;
    USE SIGNAL ;
    PORT
      LAYER M4 ;
        RECT  0 44.16 0.084 44.184 ;
    END
  END i0_lane[20]
  PIN i0_lane[210]
    DIRECTION INPUT ;
    USE SIGNAL ;
    PORT
      LAYER M4 ;
        RECT  0 62.4 0.084 62.424 ;
    END
  END i0_lane[210]
  PIN i0_lane[211]
    DIRECTION INPUT ;
    USE SIGNAL ;
    PORT
      LAYER M4 ;
        RECT  0 62.496 0.084 62.52 ;
    END
  END i0_lane[211]
  PIN i0_lane[212]
    DIRECTION INPUT ;
    USE SIGNAL ;
    PORT
      LAYER M4 ;
        RECT  0 62.592 0.084 62.616 ;
    END
  END i0_lane[212]
  PIN i0_lane[213]
    DIRECTION INPUT ;
    USE SIGNAL ;
    PORT
      LAYER M4 ;
        RECT  0 62.688 0.084 62.712 ;
    END
  END i0_lane[213]
  PIN i0_lane[214]
    DIRECTION INPUT ;
    USE SIGNAL ;
    PORT
      LAYER M4 ;
        RECT  0 62.784 0.084 62.808 ;
    END
  END i0_lane[214]
  PIN i0_lane[215]
    DIRECTION INPUT ;
    USE SIGNAL ;
    PORT
      LAYER M4 ;
        RECT  0 62.88 0.084 62.904 ;
    END
  END i0_lane[215]
  PIN i0_lane[216]
    DIRECTION INPUT ;
    USE SIGNAL ;
    PORT
      LAYER M4 ;
        RECT  0 62.976 0.084 63 ;
    END
  END i0_lane[216]
  PIN i0_lane[217]
    DIRECTION INPUT ;
    USE SIGNAL ;
    PORT
      LAYER M4 ;
        RECT  0 63.072 0.084 63.096 ;
    END
  END i0_lane[217]
  PIN i0_lane[218]
    DIRECTION INPUT ;
    USE SIGNAL ;
    PORT
      LAYER M4 ;
        RECT  0 63.168 0.084 63.192 ;
    END
  END i0_lane[218]
  PIN i0_lane[219]
    DIRECTION INPUT ;
    USE SIGNAL ;
    PORT
      LAYER M4 ;
        RECT  0 63.264 0.084 63.288 ;
    END
  END i0_lane[219]
  PIN i0_lane[21]
    DIRECTION INPUT ;
    USE SIGNAL ;
    PORT
      LAYER M4 ;
        RECT  0 44.256 0.084 44.28 ;
    END
  END i0_lane[21]
  PIN i0_lane[220]
    DIRECTION INPUT ;
    USE SIGNAL ;
    PORT
      LAYER M4 ;
        RECT  0 63.36 0.084 63.384 ;
    END
  END i0_lane[220]
  PIN i0_lane[221]
    DIRECTION INPUT ;
    USE SIGNAL ;
    PORT
      LAYER M4 ;
        RECT  0 63.456 0.084 63.48 ;
    END
  END i0_lane[221]
  PIN i0_lane[222]
    DIRECTION INPUT ;
    USE SIGNAL ;
    PORT
      LAYER M4 ;
        RECT  0 63.552 0.084 63.576 ;
    END
  END i0_lane[222]
  PIN i0_lane[223]
    DIRECTION INPUT ;
    USE SIGNAL ;
    PORT
      LAYER M4 ;
        RECT  0 63.648 0.084 63.672 ;
    END
  END i0_lane[223]
  PIN i0_lane[224]
    DIRECTION INPUT ;
    USE SIGNAL ;
    PORT
      LAYER M4 ;
        RECT  0 63.744 0.084 63.768 ;
    END
  END i0_lane[224]
  PIN i0_lane[225]
    DIRECTION INPUT ;
    USE SIGNAL ;
    PORT
      LAYER M4 ;
        RECT  0 63.84 0.084 63.864 ;
    END
  END i0_lane[225]
  PIN i0_lane[226]
    DIRECTION INPUT ;
    USE SIGNAL ;
    PORT
      LAYER M4 ;
        RECT  0 63.936 0.084 63.96 ;
    END
  END i0_lane[226]
  PIN i0_lane[227]
    DIRECTION INPUT ;
    USE SIGNAL ;
    PORT
      LAYER M4 ;
        RECT  0 64.032 0.084 64.056 ;
    END
  END i0_lane[227]
  PIN i0_lane[228]
    DIRECTION INPUT ;
    USE SIGNAL ;
    PORT
      LAYER M4 ;
        RECT  0 64.128 0.084 64.152 ;
    END
  END i0_lane[228]
  PIN i0_lane[229]
    DIRECTION INPUT ;
    USE SIGNAL ;
    PORT
      LAYER M4 ;
        RECT  0 64.224 0.084 64.248 ;
    END
  END i0_lane[229]
  PIN i0_lane[22]
    DIRECTION INPUT ;
    USE SIGNAL ;
    PORT
      LAYER M4 ;
        RECT  0 44.352 0.084 44.376 ;
    END
  END i0_lane[22]
  PIN i0_lane[230]
    DIRECTION INPUT ;
    USE SIGNAL ;
    PORT
      LAYER M4 ;
        RECT  0 64.32 0.084 64.344 ;
    END
  END i0_lane[230]
  PIN i0_lane[231]
    DIRECTION INPUT ;
    USE SIGNAL ;
    PORT
      LAYER M4 ;
        RECT  0 64.416 0.084 64.44 ;
    END
  END i0_lane[231]
  PIN i0_lane[232]
    DIRECTION INPUT ;
    USE SIGNAL ;
    PORT
      LAYER M4 ;
        RECT  0 64.512 0.084 64.536 ;
    END
  END i0_lane[232]
  PIN i0_lane[233]
    DIRECTION INPUT ;
    USE SIGNAL ;
    PORT
      LAYER M4 ;
        RECT  0 64.608 0.084 64.632 ;
    END
  END i0_lane[233]
  PIN i0_lane[234]
    DIRECTION INPUT ;
    USE SIGNAL ;
    PORT
      LAYER M4 ;
        RECT  0 64.704 0.084 64.728 ;
    END
  END i0_lane[234]
  PIN i0_lane[235]
    DIRECTION INPUT ;
    USE SIGNAL ;
    PORT
      LAYER M4 ;
        RECT  0 64.8 0.084 64.824 ;
    END
  END i0_lane[235]
  PIN i0_lane[236]
    DIRECTION INPUT ;
    USE SIGNAL ;
    PORT
      LAYER M4 ;
        RECT  0 64.896 0.084 64.92 ;
    END
  END i0_lane[236]
  PIN i0_lane[237]
    DIRECTION INPUT ;
    USE SIGNAL ;
    PORT
      LAYER M4 ;
        RECT  0 64.992 0.084 65.016 ;
    END
  END i0_lane[237]
  PIN i0_lane[238]
    DIRECTION INPUT ;
    USE SIGNAL ;
    PORT
      LAYER M4 ;
        RECT  0 65.088 0.084 65.112 ;
    END
  END i0_lane[238]
  PIN i0_lane[239]
    DIRECTION INPUT ;
    USE SIGNAL ;
    PORT
      LAYER M4 ;
        RECT  0 65.184 0.084 65.208 ;
    END
  END i0_lane[239]
  PIN i0_lane[23]
    DIRECTION INPUT ;
    USE SIGNAL ;
    PORT
      LAYER M4 ;
        RECT  0 44.448 0.084 44.472 ;
    END
  END i0_lane[23]
  PIN i0_lane[240]
    DIRECTION INPUT ;
    USE SIGNAL ;
    PORT
      LAYER M4 ;
        RECT  0 65.28 0.084 65.304 ;
    END
  END i0_lane[240]
  PIN i0_lane[241]
    DIRECTION INPUT ;
    USE SIGNAL ;
    PORT
      LAYER M4 ;
        RECT  0 65.376 0.084 65.4 ;
    END
  END i0_lane[241]
  PIN i0_lane[242]
    DIRECTION INPUT ;
    USE SIGNAL ;
    PORT
      LAYER M4 ;
        RECT  0 65.472 0.084 65.496 ;
    END
  END i0_lane[242]
  PIN i0_lane[243]
    DIRECTION INPUT ;
    USE SIGNAL ;
    PORT
      LAYER M4 ;
        RECT  0 65.568 0.084 65.592 ;
    END
  END i0_lane[243]
  PIN i0_lane[244]
    DIRECTION INPUT ;
    USE SIGNAL ;
    PORT
      LAYER M4 ;
        RECT  0 65.664 0.084 65.688 ;
    END
  END i0_lane[244]
  PIN i0_lane[245]
    DIRECTION INPUT ;
    USE SIGNAL ;
    PORT
      LAYER M4 ;
        RECT  0 65.76 0.084 65.784 ;
    END
  END i0_lane[245]
  PIN i0_lane[246]
    DIRECTION INPUT ;
    USE SIGNAL ;
    PORT
      LAYER M4 ;
        RECT  0 65.856 0.084 65.88 ;
    END
  END i0_lane[246]
  PIN i0_lane[247]
    DIRECTION INPUT ;
    USE SIGNAL ;
    PORT
      LAYER M4 ;
        RECT  0 65.952 0.084 65.976 ;
    END
  END i0_lane[247]
  PIN i0_lane[248]
    DIRECTION INPUT ;
    USE SIGNAL ;
    PORT
      LAYER M4 ;
        RECT  0 66.048 0.084 66.072 ;
    END
  END i0_lane[248]
  PIN i0_lane[249]
    DIRECTION INPUT ;
    USE SIGNAL ;
    PORT
      LAYER M4 ;
        RECT  0 66.144 0.084 66.168 ;
    END
  END i0_lane[249]
  PIN i0_lane[24]
    DIRECTION INPUT ;
    USE SIGNAL ;
    PORT
      LAYER M4 ;
        RECT  0 44.544 0.084 44.568 ;
    END
  END i0_lane[24]
  PIN i0_lane[250]
    DIRECTION INPUT ;
    USE SIGNAL ;
    PORT
      LAYER M4 ;
        RECT  0 66.24 0.084 66.264 ;
    END
  END i0_lane[250]
  PIN i0_lane[251]
    DIRECTION INPUT ;
    USE SIGNAL ;
    PORT
      LAYER M4 ;
        RECT  0 66.336 0.084 66.36 ;
    END
  END i0_lane[251]
  PIN i0_lane[252]
    DIRECTION INPUT ;
    USE SIGNAL ;
    PORT
      LAYER M4 ;
        RECT  0 66.432 0.084 66.456 ;
    END
  END i0_lane[252]
  PIN i0_lane[253]
    DIRECTION INPUT ;
    USE SIGNAL ;
    PORT
      LAYER M4 ;
        RECT  0 66.528 0.084 66.552 ;
    END
  END i0_lane[253]
  PIN i0_lane[254]
    DIRECTION INPUT ;
    USE SIGNAL ;
    PORT
      LAYER M4 ;
        RECT  0 66.624 0.084 66.648 ;
    END
  END i0_lane[254]
  PIN i0_lane[255]
    DIRECTION INPUT ;
    USE SIGNAL ;
    PORT
      LAYER M4 ;
        RECT  0 66.72 0.084 66.744 ;
    END
  END i0_lane[255]
  PIN i0_lane[256]
    DIRECTION INPUT ;
    USE SIGNAL ;
    PORT
      LAYER M4 ;
        RECT  0 66.816 0.084 66.84 ;
    END
  END i0_lane[256]
  PIN i0_lane[257]
    DIRECTION INPUT ;
    USE SIGNAL ;
    PORT
      LAYER M4 ;
        RECT  0 66.912 0.084 66.936 ;
    END
  END i0_lane[257]
  PIN i0_lane[258]
    DIRECTION INPUT ;
    USE SIGNAL ;
    PORT
      LAYER M4 ;
        RECT  0 67.008 0.084 67.032 ;
    END
  END i0_lane[258]
  PIN i0_lane[259]
    DIRECTION INPUT ;
    USE SIGNAL ;
    PORT
      LAYER M4 ;
        RECT  0 67.104 0.084 67.128 ;
    END
  END i0_lane[259]
  PIN i0_lane[25]
    DIRECTION INPUT ;
    USE SIGNAL ;
    PORT
      LAYER M4 ;
        RECT  0 44.64 0.084 44.664 ;
    END
  END i0_lane[25]
  PIN i0_lane[260]
    DIRECTION INPUT ;
    USE SIGNAL ;
    PORT
      LAYER M4 ;
        RECT  0 67.2 0.084 67.224 ;
    END
  END i0_lane[260]
  PIN i0_lane[261]
    DIRECTION INPUT ;
    USE SIGNAL ;
    PORT
      LAYER M4 ;
        RECT  0 67.296 0.084 67.32 ;
    END
  END i0_lane[261]
  PIN i0_lane[262]
    DIRECTION INPUT ;
    USE SIGNAL ;
    PORT
      LAYER M4 ;
        RECT  0 67.392 0.084 67.416 ;
    END
  END i0_lane[262]
  PIN i0_lane[263]
    DIRECTION INPUT ;
    USE SIGNAL ;
    PORT
      LAYER M4 ;
        RECT  0 67.488 0.084 67.512 ;
    END
  END i0_lane[263]
  PIN i0_lane[264]
    DIRECTION INPUT ;
    USE SIGNAL ;
    PORT
      LAYER M4 ;
        RECT  0 67.584 0.084 67.608 ;
    END
  END i0_lane[264]
  PIN i0_lane[265]
    DIRECTION INPUT ;
    USE SIGNAL ;
    PORT
      LAYER M4 ;
        RECT  0 67.68 0.084 67.704 ;
    END
  END i0_lane[265]
  PIN i0_lane[266]
    DIRECTION INPUT ;
    USE SIGNAL ;
    PORT
      LAYER M4 ;
        RECT  0 67.776 0.084 67.8 ;
    END
  END i0_lane[266]
  PIN i0_lane[267]
    DIRECTION INPUT ;
    USE SIGNAL ;
    PORT
      LAYER M4 ;
        RECT  0 67.872 0.084 67.896 ;
    END
  END i0_lane[267]
  PIN i0_lane[268]
    DIRECTION INPUT ;
    USE SIGNAL ;
    PORT
      LAYER M4 ;
        RECT  0 67.968 0.084 67.992 ;
    END
  END i0_lane[268]
  PIN i0_lane[269]
    DIRECTION INPUT ;
    USE SIGNAL ;
    PORT
      LAYER M4 ;
        RECT  0 68.064 0.084 68.088 ;
    END
  END i0_lane[269]
  PIN i0_lane[26]
    DIRECTION INPUT ;
    USE SIGNAL ;
    PORT
      LAYER M4 ;
        RECT  0 44.736 0.084 44.76 ;
    END
  END i0_lane[26]
  PIN i0_lane[270]
    DIRECTION INPUT ;
    USE SIGNAL ;
    PORT
      LAYER M4 ;
        RECT  0 68.16 0.084 68.184 ;
    END
  END i0_lane[270]
  PIN i0_lane[271]
    DIRECTION INPUT ;
    USE SIGNAL ;
    PORT
      LAYER M4 ;
        RECT  0 68.256 0.084 68.28 ;
    END
  END i0_lane[271]
  PIN i0_lane[272]
    DIRECTION INPUT ;
    USE SIGNAL ;
    PORT
      LAYER M4 ;
        RECT  0 68.352 0.084 68.376 ;
    END
  END i0_lane[272]
  PIN i0_lane[273]
    DIRECTION INPUT ;
    USE SIGNAL ;
    PORT
      LAYER M4 ;
        RECT  0 68.448 0.084 68.472 ;
    END
  END i0_lane[273]
  PIN i0_lane[274]
    DIRECTION INPUT ;
    USE SIGNAL ;
    PORT
      LAYER M4 ;
        RECT  0 68.544 0.084 68.568 ;
    END
  END i0_lane[274]
  PIN i0_lane[275]
    DIRECTION INPUT ;
    USE SIGNAL ;
    PORT
      LAYER M4 ;
        RECT  0 68.64 0.084 68.664 ;
    END
  END i0_lane[275]
  PIN i0_lane[276]
    DIRECTION INPUT ;
    USE SIGNAL ;
    PORT
      LAYER M4 ;
        RECT  0 68.736 0.084 68.76 ;
    END
  END i0_lane[276]
  PIN i0_lane[277]
    DIRECTION INPUT ;
    USE SIGNAL ;
    PORT
      LAYER M4 ;
        RECT  0 68.832 0.084 68.856 ;
    END
  END i0_lane[277]
  PIN i0_lane[278]
    DIRECTION INPUT ;
    USE SIGNAL ;
    PORT
      LAYER M4 ;
        RECT  0 68.928 0.084 68.952 ;
    END
  END i0_lane[278]
  PIN i0_lane[279]
    DIRECTION INPUT ;
    USE SIGNAL ;
    PORT
      LAYER M4 ;
        RECT  0 69.024 0.084 69.048 ;
    END
  END i0_lane[279]
  PIN i0_lane[27]
    DIRECTION INPUT ;
    USE SIGNAL ;
    PORT
      LAYER M4 ;
        RECT  0 44.832 0.084 44.856 ;
    END
  END i0_lane[27]
  PIN i0_lane[280]
    DIRECTION INPUT ;
    USE SIGNAL ;
    PORT
      LAYER M4 ;
        RECT  0 69.12 0.084 69.144 ;
    END
  END i0_lane[280]
  PIN i0_lane[281]
    DIRECTION INPUT ;
    USE SIGNAL ;
    PORT
      LAYER M4 ;
        RECT  0 69.216 0.084 69.24 ;
    END
  END i0_lane[281]
  PIN i0_lane[282]
    DIRECTION INPUT ;
    USE SIGNAL ;
    PORT
      LAYER M4 ;
        RECT  0 69.312 0.084 69.336 ;
    END
  END i0_lane[282]
  PIN i0_lane[283]
    DIRECTION INPUT ;
    USE SIGNAL ;
    PORT
      LAYER M4 ;
        RECT  0 69.408 0.084 69.432 ;
    END
  END i0_lane[283]
  PIN i0_lane[284]
    DIRECTION INPUT ;
    USE SIGNAL ;
    PORT
      LAYER M4 ;
        RECT  0 69.504 0.084 69.528 ;
    END
  END i0_lane[284]
  PIN i0_lane[285]
    DIRECTION INPUT ;
    USE SIGNAL ;
    PORT
      LAYER M4 ;
        RECT  0 69.6 0.084 69.624 ;
    END
  END i0_lane[285]
  PIN i0_lane[286]
    DIRECTION INPUT ;
    USE SIGNAL ;
    PORT
      LAYER M4 ;
        RECT  0 69.696 0.084 69.72 ;
    END
  END i0_lane[286]
  PIN i0_lane[287]
    DIRECTION INPUT ;
    USE SIGNAL ;
    PORT
      LAYER M4 ;
        RECT  0 69.792 0.084 69.816 ;
    END
  END i0_lane[287]
  PIN i0_lane[288]
    DIRECTION INPUT ;
    USE SIGNAL ;
    PORT
      LAYER M4 ;
        RECT  0 69.888 0.084 69.912 ;
    END
  END i0_lane[288]
  PIN i0_lane[289]
    DIRECTION INPUT ;
    USE SIGNAL ;
    PORT
      LAYER M4 ;
        RECT  0 69.984 0.084 70.008 ;
    END
  END i0_lane[289]
  PIN i0_lane[28]
    DIRECTION INPUT ;
    USE SIGNAL ;
    PORT
      LAYER M4 ;
        RECT  0 44.928 0.084 44.952 ;
    END
  END i0_lane[28]
  PIN i0_lane[290]
    DIRECTION INPUT ;
    USE SIGNAL ;
    PORT
      LAYER M4 ;
        RECT  0 70.08 0.084 70.104 ;
    END
  END i0_lane[290]
  PIN i0_lane[291]
    DIRECTION INPUT ;
    USE SIGNAL ;
    PORT
      LAYER M4 ;
        RECT  0 70.176 0.084 70.2 ;
    END
  END i0_lane[291]
  PIN i0_lane[292]
    DIRECTION INPUT ;
    USE SIGNAL ;
    PORT
      LAYER M4 ;
        RECT  0 70.272 0.084 70.296 ;
    END
  END i0_lane[292]
  PIN i0_lane[293]
    DIRECTION INPUT ;
    USE SIGNAL ;
    PORT
      LAYER M4 ;
        RECT  0 70.368 0.084 70.392 ;
    END
  END i0_lane[293]
  PIN i0_lane[294]
    DIRECTION INPUT ;
    USE SIGNAL ;
    PORT
      LAYER M4 ;
        RECT  0 70.464 0.084 70.488 ;
    END
  END i0_lane[294]
  PIN i0_lane[295]
    DIRECTION INPUT ;
    USE SIGNAL ;
    PORT
      LAYER M4 ;
        RECT  0 70.56 0.084 70.584 ;
    END
  END i0_lane[295]
  PIN i0_lane[296]
    DIRECTION INPUT ;
    USE SIGNAL ;
    PORT
      LAYER M4 ;
        RECT  0 70.656 0.084 70.68 ;
    END
  END i0_lane[296]
  PIN i0_lane[297]
    DIRECTION INPUT ;
    USE SIGNAL ;
    PORT
      LAYER M4 ;
        RECT  0 70.752 0.084 70.776 ;
    END
  END i0_lane[297]
  PIN i0_lane[298]
    DIRECTION INPUT ;
    USE SIGNAL ;
    PORT
      LAYER M4 ;
        RECT  0 70.848 0.084 70.872 ;
    END
  END i0_lane[298]
  PIN i0_lane[299]
    DIRECTION INPUT ;
    USE SIGNAL ;
    PORT
      LAYER M4 ;
        RECT  0 70.944 0.084 70.968 ;
    END
  END i0_lane[299]
  PIN i0_lane[29]
    DIRECTION INPUT ;
    USE SIGNAL ;
    PORT
      LAYER M4 ;
        RECT  0 45.024 0.084 45.048 ;
    END
  END i0_lane[29]
  PIN i0_lane[2]
    DIRECTION INPUT ;
    USE SIGNAL ;
    PORT
      LAYER M4 ;
        RECT  0 42.432 0.084 42.456 ;
    END
  END i0_lane[2]
  PIN i0_lane[300]
    DIRECTION INPUT ;
    USE SIGNAL ;
    PORT
      LAYER M4 ;
        RECT  0 71.04 0.084 71.064 ;
    END
  END i0_lane[300]
  PIN i0_lane[301]
    DIRECTION INPUT ;
    USE SIGNAL ;
    PORT
      LAYER M4 ;
        RECT  0 71.136 0.084 71.16 ;
    END
  END i0_lane[301]
  PIN i0_lane[302]
    DIRECTION INPUT ;
    USE SIGNAL ;
    PORT
      LAYER M4 ;
        RECT  0 71.232 0.084 71.256 ;
    END
  END i0_lane[302]
  PIN i0_lane[303]
    DIRECTION INPUT ;
    USE SIGNAL ;
    PORT
      LAYER M4 ;
        RECT  0 71.328 0.084 71.352 ;
    END
  END i0_lane[303]
  PIN i0_lane[304]
    DIRECTION INPUT ;
    USE SIGNAL ;
    PORT
      LAYER M4 ;
        RECT  0 71.424 0.084 71.448 ;
    END
  END i0_lane[304]
  PIN i0_lane[305]
    DIRECTION INPUT ;
    USE SIGNAL ;
    PORT
      LAYER M4 ;
        RECT  0 71.52 0.084 71.544 ;
    END
  END i0_lane[305]
  PIN i0_lane[306]
    DIRECTION INPUT ;
    USE SIGNAL ;
    PORT
      LAYER M4 ;
        RECT  0 71.616 0.084 71.64 ;
    END
  END i0_lane[306]
  PIN i0_lane[307]
    DIRECTION INPUT ;
    USE SIGNAL ;
    PORT
      LAYER M4 ;
        RECT  0 71.712 0.084 71.736 ;
    END
  END i0_lane[307]
  PIN i0_lane[308]
    DIRECTION INPUT ;
    USE SIGNAL ;
    PORT
      LAYER M4 ;
        RECT  0 71.808 0.084 71.832 ;
    END
  END i0_lane[308]
  PIN i0_lane[309]
    DIRECTION INPUT ;
    USE SIGNAL ;
    PORT
      LAYER M4 ;
        RECT  0 71.904 0.084 71.928 ;
    END
  END i0_lane[309]
  PIN i0_lane[30]
    DIRECTION INPUT ;
    USE SIGNAL ;
    PORT
      LAYER M4 ;
        RECT  0 45.12 0.084 45.144 ;
    END
  END i0_lane[30]
  PIN i0_lane[310]
    DIRECTION INPUT ;
    USE SIGNAL ;
    PORT
      LAYER M4 ;
        RECT  0 72 0.084 72.024 ;
    END
  END i0_lane[310]
  PIN i0_lane[311]
    DIRECTION INPUT ;
    USE SIGNAL ;
    PORT
      LAYER M4 ;
        RECT  0 72.096 0.084 72.12 ;
    END
  END i0_lane[311]
  PIN i0_lane[312]
    DIRECTION INPUT ;
    USE SIGNAL ;
    PORT
      LAYER M4 ;
        RECT  0 72.192 0.084 72.216 ;
    END
  END i0_lane[312]
  PIN i0_lane[313]
    DIRECTION INPUT ;
    USE SIGNAL ;
    PORT
      LAYER M4 ;
        RECT  0 72.288 0.084 72.312 ;
    END
  END i0_lane[313]
  PIN i0_lane[314]
    DIRECTION INPUT ;
    USE SIGNAL ;
    PORT
      LAYER M4 ;
        RECT  0 72.384 0.084 72.408 ;
    END
  END i0_lane[314]
  PIN i0_lane[315]
    DIRECTION INPUT ;
    USE SIGNAL ;
    PORT
      LAYER M4 ;
        RECT  0 72.48 0.084 72.504 ;
    END
  END i0_lane[315]
  PIN i0_lane[316]
    DIRECTION INPUT ;
    USE SIGNAL ;
    PORT
      LAYER M4 ;
        RECT  0 72.576 0.084 72.6 ;
    END
  END i0_lane[316]
  PIN i0_lane[317]
    DIRECTION INPUT ;
    USE SIGNAL ;
    PORT
      LAYER M4 ;
        RECT  0 72.672 0.084 72.696 ;
    END
  END i0_lane[317]
  PIN i0_lane[318]
    DIRECTION INPUT ;
    USE SIGNAL ;
    PORT
      LAYER M4 ;
        RECT  0 72.768 0.084 72.792 ;
    END
  END i0_lane[318]
  PIN i0_lane[319]
    DIRECTION INPUT ;
    USE SIGNAL ;
    PORT
      LAYER M4 ;
        RECT  0 72.864 0.084 72.888 ;
    END
  END i0_lane[319]
  PIN i0_lane[31]
    DIRECTION INPUT ;
    USE SIGNAL ;
    PORT
      LAYER M4 ;
        RECT  0 45.216 0.084 45.24 ;
    END
  END i0_lane[31]
  PIN i0_lane[320]
    DIRECTION INPUT ;
    USE SIGNAL ;
    PORT
      LAYER M4 ;
        RECT  0 72.96 0.084 72.984 ;
    END
  END i0_lane[320]
  PIN i0_lane[321]
    DIRECTION INPUT ;
    USE SIGNAL ;
    PORT
      LAYER M4 ;
        RECT  0 73.056 0.084 73.08 ;
    END
  END i0_lane[321]
  PIN i0_lane[322]
    DIRECTION INPUT ;
    USE SIGNAL ;
    PORT
      LAYER M4 ;
        RECT  0 73.152 0.084 73.176 ;
    END
  END i0_lane[322]
  PIN i0_lane[323]
    DIRECTION INPUT ;
    USE SIGNAL ;
    PORT
      LAYER M4 ;
        RECT  0 73.248 0.084 73.272 ;
    END
  END i0_lane[323]
  PIN i0_lane[324]
    DIRECTION INPUT ;
    USE SIGNAL ;
    PORT
      LAYER M4 ;
        RECT  0 73.344 0.084 73.368 ;
    END
  END i0_lane[324]
  PIN i0_lane[325]
    DIRECTION INPUT ;
    USE SIGNAL ;
    PORT
      LAYER M4 ;
        RECT  0 73.44 0.084 73.464 ;
    END
  END i0_lane[325]
  PIN i0_lane[326]
    DIRECTION INPUT ;
    USE SIGNAL ;
    PORT
      LAYER M4 ;
        RECT  0 73.536 0.084 73.56 ;
    END
  END i0_lane[326]
  PIN i0_lane[327]
    DIRECTION INPUT ;
    USE SIGNAL ;
    PORT
      LAYER M4 ;
        RECT  0 73.632 0.084 73.656 ;
    END
  END i0_lane[327]
  PIN i0_lane[328]
    DIRECTION INPUT ;
    USE SIGNAL ;
    PORT
      LAYER M4 ;
        RECT  0 73.728 0.084 73.752 ;
    END
  END i0_lane[328]
  PIN i0_lane[329]
    DIRECTION INPUT ;
    USE SIGNAL ;
    PORT
      LAYER M4 ;
        RECT  0 73.824 0.084 73.848 ;
    END
  END i0_lane[329]
  PIN i0_lane[32]
    DIRECTION INPUT ;
    USE SIGNAL ;
    PORT
      LAYER M4 ;
        RECT  0 45.312 0.084 45.336 ;
    END
  END i0_lane[32]
  PIN i0_lane[330]
    DIRECTION INPUT ;
    USE SIGNAL ;
    PORT
      LAYER M4 ;
        RECT  0 73.92 0.084 73.944 ;
    END
  END i0_lane[330]
  PIN i0_lane[331]
    DIRECTION INPUT ;
    USE SIGNAL ;
    PORT
      LAYER M4 ;
        RECT  0 74.016 0.084 74.04 ;
    END
  END i0_lane[331]
  PIN i0_lane[332]
    DIRECTION INPUT ;
    USE SIGNAL ;
    PORT
      LAYER M4 ;
        RECT  0 74.112 0.084 74.136 ;
    END
  END i0_lane[332]
  PIN i0_lane[333]
    DIRECTION INPUT ;
    USE SIGNAL ;
    PORT
      LAYER M4 ;
        RECT  0 74.208 0.084 74.232 ;
    END
  END i0_lane[333]
  PIN i0_lane[334]
    DIRECTION INPUT ;
    USE SIGNAL ;
    PORT
      LAYER M4 ;
        RECT  0 74.304 0.084 74.328 ;
    END
  END i0_lane[334]
  PIN i0_lane[335]
    DIRECTION INPUT ;
    USE SIGNAL ;
    PORT
      LAYER M4 ;
        RECT  0 74.4 0.084 74.424 ;
    END
  END i0_lane[335]
  PIN i0_lane[336]
    DIRECTION INPUT ;
    USE SIGNAL ;
    PORT
      LAYER M4 ;
        RECT  0 74.496 0.084 74.52 ;
    END
  END i0_lane[336]
  PIN i0_lane[337]
    DIRECTION INPUT ;
    USE SIGNAL ;
    PORT
      LAYER M4 ;
        RECT  0 74.592 0.084 74.616 ;
    END
  END i0_lane[337]
  PIN i0_lane[338]
    DIRECTION INPUT ;
    USE SIGNAL ;
    PORT
      LAYER M4 ;
        RECT  0 74.688 0.084 74.712 ;
    END
  END i0_lane[338]
  PIN i0_lane[339]
    DIRECTION INPUT ;
    USE SIGNAL ;
    PORT
      LAYER M4 ;
        RECT  0 74.784 0.084 74.808 ;
    END
  END i0_lane[339]
  PIN i0_lane[33]
    DIRECTION INPUT ;
    USE SIGNAL ;
    PORT
      LAYER M4 ;
        RECT  0 45.408 0.084 45.432 ;
    END
  END i0_lane[33]
  PIN i0_lane[340]
    DIRECTION INPUT ;
    USE SIGNAL ;
    PORT
      LAYER M4 ;
        RECT  0 74.88 0.084 74.904 ;
    END
  END i0_lane[340]
  PIN i0_lane[341]
    DIRECTION INPUT ;
    USE SIGNAL ;
    PORT
      LAYER M4 ;
        RECT  0 74.976 0.084 75 ;
    END
  END i0_lane[341]
  PIN i0_lane[342]
    DIRECTION INPUT ;
    USE SIGNAL ;
    PORT
      LAYER M4 ;
        RECT  0 75.072 0.084 75.096 ;
    END
  END i0_lane[342]
  PIN i0_lane[343]
    DIRECTION INPUT ;
    USE SIGNAL ;
    PORT
      LAYER M4 ;
        RECT  0 75.168 0.084 75.192 ;
    END
  END i0_lane[343]
  PIN i0_lane[344]
    DIRECTION INPUT ;
    USE SIGNAL ;
    PORT
      LAYER M4 ;
        RECT  0 75.264 0.084 75.288 ;
    END
  END i0_lane[344]
  PIN i0_lane[345]
    DIRECTION INPUT ;
    USE SIGNAL ;
    PORT
      LAYER M4 ;
        RECT  0 75.36 0.084 75.384 ;
    END
  END i0_lane[345]
  PIN i0_lane[346]
    DIRECTION INPUT ;
    USE SIGNAL ;
    PORT
      LAYER M4 ;
        RECT  0 75.456 0.084 75.48 ;
    END
  END i0_lane[346]
  PIN i0_lane[347]
    DIRECTION INPUT ;
    USE SIGNAL ;
    PORT
      LAYER M4 ;
        RECT  0 75.552 0.084 75.576 ;
    END
  END i0_lane[347]
  PIN i0_lane[348]
    DIRECTION INPUT ;
    USE SIGNAL ;
    PORT
      LAYER M4 ;
        RECT  0 75.648 0.084 75.672 ;
    END
  END i0_lane[348]
  PIN i0_lane[349]
    DIRECTION INPUT ;
    USE SIGNAL ;
    PORT
      LAYER M4 ;
        RECT  0 75.744 0.084 75.768 ;
    END
  END i0_lane[349]
  PIN i0_lane[34]
    DIRECTION INPUT ;
    USE SIGNAL ;
    PORT
      LAYER M4 ;
        RECT  0 45.504 0.084 45.528 ;
    END
  END i0_lane[34]
  PIN i0_lane[350]
    DIRECTION INPUT ;
    USE SIGNAL ;
    PORT
      LAYER M4 ;
        RECT  0 75.84 0.084 75.864 ;
    END
  END i0_lane[350]
  PIN i0_lane[351]
    DIRECTION INPUT ;
    USE SIGNAL ;
    PORT
      LAYER M4 ;
        RECT  0 75.936 0.084 75.96 ;
    END
  END i0_lane[351]
  PIN i0_lane[352]
    DIRECTION INPUT ;
    USE SIGNAL ;
    PORT
      LAYER M4 ;
        RECT  0 76.032 0.084 76.056 ;
    END
  END i0_lane[352]
  PIN i0_lane[353]
    DIRECTION INPUT ;
    USE SIGNAL ;
    PORT
      LAYER M4 ;
        RECT  0 76.128 0.084 76.152 ;
    END
  END i0_lane[353]
  PIN i0_lane[354]
    DIRECTION INPUT ;
    USE SIGNAL ;
    PORT
      LAYER M4 ;
        RECT  0 76.224 0.084 76.248 ;
    END
  END i0_lane[354]
  PIN i0_lane[355]
    DIRECTION INPUT ;
    USE SIGNAL ;
    PORT
      LAYER M4 ;
        RECT  0 76.32 0.084 76.344 ;
    END
  END i0_lane[355]
  PIN i0_lane[356]
    DIRECTION INPUT ;
    USE SIGNAL ;
    PORT
      LAYER M4 ;
        RECT  0 76.416 0.084 76.44 ;
    END
  END i0_lane[356]
  PIN i0_lane[357]
    DIRECTION INPUT ;
    USE SIGNAL ;
    PORT
      LAYER M4 ;
        RECT  0 76.512 0.084 76.536 ;
    END
  END i0_lane[357]
  PIN i0_lane[358]
    DIRECTION INPUT ;
    USE SIGNAL ;
    PORT
      LAYER M4 ;
        RECT  0 76.608 0.084 76.632 ;
    END
  END i0_lane[358]
  PIN i0_lane[359]
    DIRECTION INPUT ;
    USE SIGNAL ;
    PORT
      LAYER M4 ;
        RECT  0 76.704 0.084 76.728 ;
    END
  END i0_lane[359]
  PIN i0_lane[35]
    DIRECTION INPUT ;
    USE SIGNAL ;
    PORT
      LAYER M4 ;
        RECT  0 45.6 0.084 45.624 ;
    END
  END i0_lane[35]
  PIN i0_lane[360]
    DIRECTION INPUT ;
    USE SIGNAL ;
    PORT
      LAYER M4 ;
        RECT  0 76.8 0.084 76.824 ;
    END
  END i0_lane[360]
  PIN i0_lane[361]
    DIRECTION INPUT ;
    USE SIGNAL ;
    PORT
      LAYER M4 ;
        RECT  0 76.896 0.084 76.92 ;
    END
  END i0_lane[361]
  PIN i0_lane[362]
    DIRECTION INPUT ;
    USE SIGNAL ;
    PORT
      LAYER M4 ;
        RECT  0 76.992 0.084 77.016 ;
    END
  END i0_lane[362]
  PIN i0_lane[363]
    DIRECTION INPUT ;
    USE SIGNAL ;
    PORT
      LAYER M4 ;
        RECT  0 77.088 0.084 77.112 ;
    END
  END i0_lane[363]
  PIN i0_lane[364]
    DIRECTION INPUT ;
    USE SIGNAL ;
    PORT
      LAYER M4 ;
        RECT  0 77.184 0.084 77.208 ;
    END
  END i0_lane[364]
  PIN i0_lane[365]
    DIRECTION INPUT ;
    USE SIGNAL ;
    PORT
      LAYER M4 ;
        RECT  0 77.28 0.084 77.304 ;
    END
  END i0_lane[365]
  PIN i0_lane[366]
    DIRECTION INPUT ;
    USE SIGNAL ;
    PORT
      LAYER M4 ;
        RECT  0 77.376 0.084 77.4 ;
    END
  END i0_lane[366]
  PIN i0_lane[367]
    DIRECTION INPUT ;
    USE SIGNAL ;
    PORT
      LAYER M4 ;
        RECT  0 77.472 0.084 77.496 ;
    END
  END i0_lane[367]
  PIN i0_lane[368]
    DIRECTION INPUT ;
    USE SIGNAL ;
    PORT
      LAYER M4 ;
        RECT  0 77.568 0.084 77.592 ;
    END
  END i0_lane[368]
  PIN i0_lane[369]
    DIRECTION INPUT ;
    USE SIGNAL ;
    PORT
      LAYER M4 ;
        RECT  0 77.664 0.084 77.688 ;
    END
  END i0_lane[369]
  PIN i0_lane[36]
    DIRECTION INPUT ;
    USE SIGNAL ;
    PORT
      LAYER M4 ;
        RECT  0 45.696 0.084 45.72 ;
    END
  END i0_lane[36]
  PIN i0_lane[370]
    DIRECTION INPUT ;
    USE SIGNAL ;
    PORT
      LAYER M4 ;
        RECT  0 77.76 0.084 77.784 ;
    END
  END i0_lane[370]
  PIN i0_lane[371]
    DIRECTION INPUT ;
    USE SIGNAL ;
    PORT
      LAYER M4 ;
        RECT  0 77.856 0.084 77.88 ;
    END
  END i0_lane[371]
  PIN i0_lane[372]
    DIRECTION INPUT ;
    USE SIGNAL ;
    PORT
      LAYER M4 ;
        RECT  0 77.952 0.084 77.976 ;
    END
  END i0_lane[372]
  PIN i0_lane[373]
    DIRECTION INPUT ;
    USE SIGNAL ;
    PORT
      LAYER M4 ;
        RECT  0 78.048 0.084 78.072 ;
    END
  END i0_lane[373]
  PIN i0_lane[374]
    DIRECTION INPUT ;
    USE SIGNAL ;
    PORT
      LAYER M4 ;
        RECT  0 78.144 0.084 78.168 ;
    END
  END i0_lane[374]
  PIN i0_lane[375]
    DIRECTION INPUT ;
    USE SIGNAL ;
    PORT
      LAYER M4 ;
        RECT  0 78.24 0.084 78.264 ;
    END
  END i0_lane[375]
  PIN i0_lane[376]
    DIRECTION INPUT ;
    USE SIGNAL ;
    PORT
      LAYER M4 ;
        RECT  0 78.336 0.084 78.36 ;
    END
  END i0_lane[376]
  PIN i0_lane[377]
    DIRECTION INPUT ;
    USE SIGNAL ;
    PORT
      LAYER M4 ;
        RECT  0 78.432 0.084 78.456 ;
    END
  END i0_lane[377]
  PIN i0_lane[378]
    DIRECTION INPUT ;
    USE SIGNAL ;
    PORT
      LAYER M4 ;
        RECT  0 78.528 0.084 78.552 ;
    END
  END i0_lane[378]
  PIN i0_lane[379]
    DIRECTION INPUT ;
    USE SIGNAL ;
    PORT
      LAYER M4 ;
        RECT  0 78.624 0.084 78.648 ;
    END
  END i0_lane[379]
  PIN i0_lane[37]
    DIRECTION INPUT ;
    USE SIGNAL ;
    PORT
      LAYER M4 ;
        RECT  0 45.792 0.084 45.816 ;
    END
  END i0_lane[37]
  PIN i0_lane[380]
    DIRECTION INPUT ;
    USE SIGNAL ;
    PORT
      LAYER M4 ;
        RECT  0 78.72 0.084 78.744 ;
    END
  END i0_lane[380]
  PIN i0_lane[381]
    DIRECTION INPUT ;
    USE SIGNAL ;
    PORT
      LAYER M4 ;
        RECT  0 78.816 0.084 78.84 ;
    END
  END i0_lane[381]
  PIN i0_lane[382]
    DIRECTION INPUT ;
    USE SIGNAL ;
    PORT
      LAYER M4 ;
        RECT  0 78.912 0.084 78.936 ;
    END
  END i0_lane[382]
  PIN i0_lane[383]
    DIRECTION INPUT ;
    USE SIGNAL ;
    PORT
      LAYER M4 ;
        RECT  0 79.008 0.084 79.032 ;
    END
  END i0_lane[383]
  PIN i0_lane[384]
    DIRECTION INPUT ;
    USE SIGNAL ;
    PORT
      LAYER M4 ;
        RECT  0 79.104 0.084 79.128 ;
    END
  END i0_lane[384]
  PIN i0_lane[385]
    DIRECTION INPUT ;
    USE SIGNAL ;
    PORT
      LAYER M4 ;
        RECT  0 79.2 0.084 79.224 ;
    END
  END i0_lane[385]
  PIN i0_lane[386]
    DIRECTION INPUT ;
    USE SIGNAL ;
    PORT
      LAYER M4 ;
        RECT  0 79.296 0.084 79.32 ;
    END
  END i0_lane[386]
  PIN i0_lane[387]
    DIRECTION INPUT ;
    USE SIGNAL ;
    PORT
      LAYER M4 ;
        RECT  0 79.392 0.084 79.416 ;
    END
  END i0_lane[387]
  PIN i0_lane[388]
    DIRECTION INPUT ;
    USE SIGNAL ;
    PORT
      LAYER M4 ;
        RECT  0 79.488 0.084 79.512 ;
    END
  END i0_lane[388]
  PIN i0_lane[389]
    DIRECTION INPUT ;
    USE SIGNAL ;
    PORT
      LAYER M4 ;
        RECT  0 79.584 0.084 79.608 ;
    END
  END i0_lane[389]
  PIN i0_lane[38]
    DIRECTION INPUT ;
    USE SIGNAL ;
    PORT
      LAYER M4 ;
        RECT  0 45.888 0.084 45.912 ;
    END
  END i0_lane[38]
  PIN i0_lane[390]
    DIRECTION INPUT ;
    USE SIGNAL ;
    PORT
      LAYER M4 ;
        RECT  0 79.68 0.084 79.704 ;
    END
  END i0_lane[390]
  PIN i0_lane[391]
    DIRECTION INPUT ;
    USE SIGNAL ;
    PORT
      LAYER M4 ;
        RECT  0 79.776 0.084 79.8 ;
    END
  END i0_lane[391]
  PIN i0_lane[392]
    DIRECTION INPUT ;
    USE SIGNAL ;
    PORT
      LAYER M4 ;
        RECT  0 79.872 0.084 79.896 ;
    END
  END i0_lane[392]
  PIN i0_lane[393]
    DIRECTION INPUT ;
    USE SIGNAL ;
    PORT
      LAYER M4 ;
        RECT  0 79.968 0.084 79.992 ;
    END
  END i0_lane[393]
  PIN i0_lane[394]
    DIRECTION INPUT ;
    USE SIGNAL ;
    PORT
      LAYER M4 ;
        RECT  0 80.064 0.084 80.088 ;
    END
  END i0_lane[394]
  PIN i0_lane[395]
    DIRECTION INPUT ;
    USE SIGNAL ;
    PORT
      LAYER M4 ;
        RECT  0 80.16 0.084 80.184 ;
    END
  END i0_lane[395]
  PIN i0_lane[396]
    DIRECTION INPUT ;
    USE SIGNAL ;
    PORT
      LAYER M4 ;
        RECT  0 80.256 0.084 80.28 ;
    END
  END i0_lane[396]
  PIN i0_lane[397]
    DIRECTION INPUT ;
    USE SIGNAL ;
    PORT
      LAYER M4 ;
        RECT  0 80.352 0.084 80.376 ;
    END
  END i0_lane[397]
  PIN i0_lane[398]
    DIRECTION INPUT ;
    USE SIGNAL ;
    PORT
      LAYER M4 ;
        RECT  0 80.448 0.084 80.472 ;
    END
  END i0_lane[398]
  PIN i0_lane[399]
    DIRECTION INPUT ;
    USE SIGNAL ;
    PORT
      LAYER M4 ;
        RECT  0 80.544 0.084 80.568 ;
    END
  END i0_lane[399]
  PIN i0_lane[39]
    DIRECTION INPUT ;
    USE SIGNAL ;
    PORT
      LAYER M4 ;
        RECT  0 45.984 0.084 46.008 ;
    END
  END i0_lane[39]
  PIN i0_lane[3]
    DIRECTION INPUT ;
    USE SIGNAL ;
    PORT
      LAYER M4 ;
        RECT  0 42.528 0.084 42.552 ;
    END
  END i0_lane[3]
  PIN i0_lane[400]
    DIRECTION INPUT ;
    USE SIGNAL ;
    PORT
      LAYER M4 ;
        RECT  0 80.64 0.084 80.664 ;
    END
  END i0_lane[400]
  PIN i0_lane[401]
    DIRECTION INPUT ;
    USE SIGNAL ;
    PORT
      LAYER M4 ;
        RECT  0 80.736 0.084 80.76 ;
    END
  END i0_lane[401]
  PIN i0_lane[402]
    DIRECTION INPUT ;
    USE SIGNAL ;
    PORT
      LAYER M4 ;
        RECT  0 80.832 0.084 80.856 ;
    END
  END i0_lane[402]
  PIN i0_lane[403]
    DIRECTION INPUT ;
    USE SIGNAL ;
    PORT
      LAYER M4 ;
        RECT  0 80.928 0.084 80.952 ;
    END
  END i0_lane[403]
  PIN i0_lane[404]
    DIRECTION INPUT ;
    USE SIGNAL ;
    PORT
      LAYER M4 ;
        RECT  0 81.024 0.084 81.048 ;
    END
  END i0_lane[404]
  PIN i0_lane[405]
    DIRECTION INPUT ;
    USE SIGNAL ;
    PORT
      LAYER M4 ;
        RECT  0 81.12 0.084 81.144 ;
    END
  END i0_lane[405]
  PIN i0_lane[406]
    DIRECTION INPUT ;
    USE SIGNAL ;
    PORT
      LAYER M4 ;
        RECT  0 81.216 0.084 81.24 ;
    END
  END i0_lane[406]
  PIN i0_lane[407]
    DIRECTION INPUT ;
    USE SIGNAL ;
    PORT
      LAYER M4 ;
        RECT  0 81.312 0.084 81.336 ;
    END
  END i0_lane[407]
  PIN i0_lane[408]
    DIRECTION INPUT ;
    USE SIGNAL ;
    PORT
      LAYER M4 ;
        RECT  0 81.408 0.084 81.432 ;
    END
  END i0_lane[408]
  PIN i0_lane[409]
    DIRECTION INPUT ;
    USE SIGNAL ;
    PORT
      LAYER M4 ;
        RECT  0 81.504 0.084 81.528 ;
    END
  END i0_lane[409]
  PIN i0_lane[40]
    DIRECTION INPUT ;
    USE SIGNAL ;
    PORT
      LAYER M4 ;
        RECT  0 46.08 0.084 46.104 ;
    END
  END i0_lane[40]
  PIN i0_lane[410]
    DIRECTION INPUT ;
    USE SIGNAL ;
    PORT
      LAYER M4 ;
        RECT  0 81.6 0.084 81.624 ;
    END
  END i0_lane[410]
  PIN i0_lane[411]
    DIRECTION INPUT ;
    USE SIGNAL ;
    PORT
      LAYER M4 ;
        RECT  0 81.696 0.084 81.72 ;
    END
  END i0_lane[411]
  PIN i0_lane[412]
    DIRECTION INPUT ;
    USE SIGNAL ;
    PORT
      LAYER M4 ;
        RECT  0 81.792 0.084 81.816 ;
    END
  END i0_lane[412]
  PIN i0_lane[413]
    DIRECTION INPUT ;
    USE SIGNAL ;
    PORT
      LAYER M4 ;
        RECT  0 81.888 0.084 81.912 ;
    END
  END i0_lane[413]
  PIN i0_lane[414]
    DIRECTION INPUT ;
    USE SIGNAL ;
    PORT
      LAYER M4 ;
        RECT  0 81.984 0.084 82.008 ;
    END
  END i0_lane[414]
  PIN i0_lane[415]
    DIRECTION INPUT ;
    USE SIGNAL ;
    PORT
      LAYER M4 ;
        RECT  0 82.08 0.084 82.104 ;
    END
  END i0_lane[415]
  PIN i0_lane[416]
    DIRECTION INPUT ;
    USE SIGNAL ;
    PORT
      LAYER M4 ;
        RECT  0 82.176 0.084 82.2 ;
    END
  END i0_lane[416]
  PIN i0_lane[417]
    DIRECTION INPUT ;
    USE SIGNAL ;
    PORT
      LAYER M4 ;
        RECT  0 82.272 0.084 82.296 ;
    END
  END i0_lane[417]
  PIN i0_lane[418]
    DIRECTION INPUT ;
    USE SIGNAL ;
    PORT
      LAYER M4 ;
        RECT  0 82.368 0.084 82.392 ;
    END
  END i0_lane[418]
  PIN i0_lane[419]
    DIRECTION INPUT ;
    USE SIGNAL ;
    PORT
      LAYER M4 ;
        RECT  0 82.464 0.084 82.488 ;
    END
  END i0_lane[419]
  PIN i0_lane[41]
    DIRECTION INPUT ;
    USE SIGNAL ;
    PORT
      LAYER M4 ;
        RECT  0 46.176 0.084 46.2 ;
    END
  END i0_lane[41]
  PIN i0_lane[420]
    DIRECTION INPUT ;
    USE SIGNAL ;
    PORT
      LAYER M4 ;
        RECT  0 82.56 0.084 82.584 ;
    END
  END i0_lane[420]
  PIN i0_lane[421]
    DIRECTION INPUT ;
    USE SIGNAL ;
    PORT
      LAYER M4 ;
        RECT  0 82.656 0.084 82.68 ;
    END
  END i0_lane[421]
  PIN i0_lane[422]
    DIRECTION INPUT ;
    USE SIGNAL ;
    PORT
      LAYER M4 ;
        RECT  0 82.752 0.084 82.776 ;
    END
  END i0_lane[422]
  PIN i0_lane[423]
    DIRECTION INPUT ;
    USE SIGNAL ;
    PORT
      LAYER M4 ;
        RECT  0 82.848 0.084 82.872 ;
    END
  END i0_lane[423]
  PIN i0_lane[424]
    DIRECTION INPUT ;
    USE SIGNAL ;
    PORT
      LAYER M4 ;
        RECT  0 82.944 0.084 82.968 ;
    END
  END i0_lane[424]
  PIN i0_lane[425]
    DIRECTION INPUT ;
    USE SIGNAL ;
    PORT
      LAYER M4 ;
        RECT  0 83.04 0.084 83.064 ;
    END
  END i0_lane[425]
  PIN i0_lane[426]
    DIRECTION INPUT ;
    USE SIGNAL ;
    PORT
      LAYER M4 ;
        RECT  0 83.136 0.084 83.16 ;
    END
  END i0_lane[426]
  PIN i0_lane[427]
    DIRECTION INPUT ;
    USE SIGNAL ;
    PORT
      LAYER M4 ;
        RECT  0 83.232 0.084 83.256 ;
    END
  END i0_lane[427]
  PIN i0_lane[428]
    DIRECTION INPUT ;
    USE SIGNAL ;
    PORT
      LAYER M4 ;
        RECT  0 83.328 0.084 83.352 ;
    END
  END i0_lane[428]
  PIN i0_lane[429]
    DIRECTION INPUT ;
    USE SIGNAL ;
    PORT
      LAYER M4 ;
        RECT  0 83.424 0.084 83.448 ;
    END
  END i0_lane[429]
  PIN i0_lane[42]
    DIRECTION INPUT ;
    USE SIGNAL ;
    PORT
      LAYER M4 ;
        RECT  0 46.272 0.084 46.296 ;
    END
  END i0_lane[42]
  PIN i0_lane[430]
    DIRECTION INPUT ;
    USE SIGNAL ;
    PORT
      LAYER M4 ;
        RECT  0 83.52 0.084 83.544 ;
    END
  END i0_lane[430]
  PIN i0_lane[431]
    DIRECTION INPUT ;
    USE SIGNAL ;
    PORT
      LAYER M4 ;
        RECT  0 83.616 0.084 83.64 ;
    END
  END i0_lane[431]
  PIN i0_lane[432]
    DIRECTION INPUT ;
    USE SIGNAL ;
    PORT
      LAYER M4 ;
        RECT  0 83.712 0.084 83.736 ;
    END
  END i0_lane[432]
  PIN i0_lane[433]
    DIRECTION INPUT ;
    USE SIGNAL ;
    PORT
      LAYER M4 ;
        RECT  0 83.808 0.084 83.832 ;
    END
  END i0_lane[433]
  PIN i0_lane[434]
    DIRECTION INPUT ;
    USE SIGNAL ;
    PORT
      LAYER M4 ;
        RECT  0 83.904 0.084 83.928 ;
    END
  END i0_lane[434]
  PIN i0_lane[435]
    DIRECTION INPUT ;
    USE SIGNAL ;
    PORT
      LAYER M4 ;
        RECT  0 84 0.084 84.024 ;
    END
  END i0_lane[435]
  PIN i0_lane[436]
    DIRECTION INPUT ;
    USE SIGNAL ;
    PORT
      LAYER M4 ;
        RECT  0 84.096 0.084 84.12 ;
    END
  END i0_lane[436]
  PIN i0_lane[437]
    DIRECTION INPUT ;
    USE SIGNAL ;
    PORT
      LAYER M4 ;
        RECT  0 84.192 0.084 84.216 ;
    END
  END i0_lane[437]
  PIN i0_lane[438]
    DIRECTION INPUT ;
    USE SIGNAL ;
    PORT
      LAYER M4 ;
        RECT  0 84.288 0.084 84.312 ;
    END
  END i0_lane[438]
  PIN i0_lane[439]
    DIRECTION INPUT ;
    USE SIGNAL ;
    PORT
      LAYER M4 ;
        RECT  0 84.384 0.084 84.408 ;
    END
  END i0_lane[439]
  PIN i0_lane[43]
    DIRECTION INPUT ;
    USE SIGNAL ;
    PORT
      LAYER M4 ;
        RECT  0 46.368 0.084 46.392 ;
    END
  END i0_lane[43]
  PIN i0_lane[440]
    DIRECTION INPUT ;
    USE SIGNAL ;
    PORT
      LAYER M4 ;
        RECT  0 84.48 0.084 84.504 ;
    END
  END i0_lane[440]
  PIN i0_lane[441]
    DIRECTION INPUT ;
    USE SIGNAL ;
    PORT
      LAYER M4 ;
        RECT  0 84.576 0.084 84.6 ;
    END
  END i0_lane[441]
  PIN i0_lane[442]
    DIRECTION INPUT ;
    USE SIGNAL ;
    PORT
      LAYER M4 ;
        RECT  0 84.672 0.084 84.696 ;
    END
  END i0_lane[442]
  PIN i0_lane[443]
    DIRECTION INPUT ;
    USE SIGNAL ;
    PORT
      LAYER M4 ;
        RECT  0 84.768 0.084 84.792 ;
    END
  END i0_lane[443]
  PIN i0_lane[444]
    DIRECTION INPUT ;
    USE SIGNAL ;
    PORT
      LAYER M4 ;
        RECT  0 84.864 0.084 84.888 ;
    END
  END i0_lane[444]
  PIN i0_lane[445]
    DIRECTION INPUT ;
    USE SIGNAL ;
    PORT
      LAYER M4 ;
        RECT  0 84.96 0.084 84.984 ;
    END
  END i0_lane[445]
  PIN i0_lane[446]
    DIRECTION INPUT ;
    USE SIGNAL ;
    PORT
      LAYER M4 ;
        RECT  0 85.056 0.084 85.08 ;
    END
  END i0_lane[446]
  PIN i0_lane[447]
    DIRECTION INPUT ;
    USE SIGNAL ;
    PORT
      LAYER M4 ;
        RECT  0 85.152 0.084 85.176 ;
    END
  END i0_lane[447]
  PIN i0_lane[448]
    DIRECTION INPUT ;
    USE SIGNAL ;
    PORT
      LAYER M4 ;
        RECT  0 85.248 0.084 85.272 ;
    END
  END i0_lane[448]
  PIN i0_lane[449]
    DIRECTION INPUT ;
    USE SIGNAL ;
    PORT
      LAYER M4 ;
        RECT  0 85.344 0.084 85.368 ;
    END
  END i0_lane[449]
  PIN i0_lane[44]
    DIRECTION INPUT ;
    USE SIGNAL ;
    PORT
      LAYER M4 ;
        RECT  0 46.464 0.084 46.488 ;
    END
  END i0_lane[44]
  PIN i0_lane[450]
    DIRECTION INPUT ;
    USE SIGNAL ;
    PORT
      LAYER M4 ;
        RECT  0 85.44 0.084 85.464 ;
    END
  END i0_lane[450]
  PIN i0_lane[451]
    DIRECTION INPUT ;
    USE SIGNAL ;
    PORT
      LAYER M4 ;
        RECT  0 85.536 0.084 85.56 ;
    END
  END i0_lane[451]
  PIN i0_lane[452]
    DIRECTION INPUT ;
    USE SIGNAL ;
    PORT
      LAYER M4 ;
        RECT  0 85.632 0.084 85.656 ;
    END
  END i0_lane[452]
  PIN i0_lane[453]
    DIRECTION INPUT ;
    USE SIGNAL ;
    PORT
      LAYER M4 ;
        RECT  0 85.728 0.084 85.752 ;
    END
  END i0_lane[453]
  PIN i0_lane[454]
    DIRECTION INPUT ;
    USE SIGNAL ;
    PORT
      LAYER M4 ;
        RECT  0 85.824 0.084 85.848 ;
    END
  END i0_lane[454]
  PIN i0_lane[455]
    DIRECTION INPUT ;
    USE SIGNAL ;
    PORT
      LAYER M4 ;
        RECT  0 85.92 0.084 85.944 ;
    END
  END i0_lane[455]
  PIN i0_lane[456]
    DIRECTION INPUT ;
    USE SIGNAL ;
    PORT
      LAYER M4 ;
        RECT  0 86.016 0.084 86.04 ;
    END
  END i0_lane[456]
  PIN i0_lane[457]
    DIRECTION INPUT ;
    USE SIGNAL ;
    PORT
      LAYER M4 ;
        RECT  0 86.112 0.084 86.136 ;
    END
  END i0_lane[457]
  PIN i0_lane[458]
    DIRECTION INPUT ;
    USE SIGNAL ;
    PORT
      LAYER M4 ;
        RECT  0 86.208 0.084 86.232 ;
    END
  END i0_lane[458]
  PIN i0_lane[459]
    DIRECTION INPUT ;
    USE SIGNAL ;
    PORT
      LAYER M4 ;
        RECT  0 86.304 0.084 86.328 ;
    END
  END i0_lane[459]
  PIN i0_lane[45]
    DIRECTION INPUT ;
    USE SIGNAL ;
    PORT
      LAYER M4 ;
        RECT  0 46.56 0.084 46.584 ;
    END
  END i0_lane[45]
  PIN i0_lane[460]
    DIRECTION INPUT ;
    USE SIGNAL ;
    PORT
      LAYER M4 ;
        RECT  0 86.4 0.084 86.424 ;
    END
  END i0_lane[460]
  PIN i0_lane[461]
    DIRECTION INPUT ;
    USE SIGNAL ;
    PORT
      LAYER M4 ;
        RECT  0 86.496 0.084 86.52 ;
    END
  END i0_lane[461]
  PIN i0_lane[462]
    DIRECTION INPUT ;
    USE SIGNAL ;
    PORT
      LAYER M4 ;
        RECT  0 86.592 0.084 86.616 ;
    END
  END i0_lane[462]
  PIN i0_lane[463]
    DIRECTION INPUT ;
    USE SIGNAL ;
    PORT
      LAYER M4 ;
        RECT  0 86.688 0.084 86.712 ;
    END
  END i0_lane[463]
  PIN i0_lane[464]
    DIRECTION INPUT ;
    USE SIGNAL ;
    PORT
      LAYER M4 ;
        RECT  0 86.784 0.084 86.808 ;
    END
  END i0_lane[464]
  PIN i0_lane[465]
    DIRECTION INPUT ;
    USE SIGNAL ;
    PORT
      LAYER M4 ;
        RECT  0 86.88 0.084 86.904 ;
    END
  END i0_lane[465]
  PIN i0_lane[466]
    DIRECTION INPUT ;
    USE SIGNAL ;
    PORT
      LAYER M4 ;
        RECT  0 86.976 0.084 87 ;
    END
  END i0_lane[466]
  PIN i0_lane[467]
    DIRECTION INPUT ;
    USE SIGNAL ;
    PORT
      LAYER M4 ;
        RECT  0 87.072 0.084 87.096 ;
    END
  END i0_lane[467]
  PIN i0_lane[468]
    DIRECTION INPUT ;
    USE SIGNAL ;
    PORT
      LAYER M4 ;
        RECT  0 87.168 0.084 87.192 ;
    END
  END i0_lane[468]
  PIN i0_lane[469]
    DIRECTION INPUT ;
    USE SIGNAL ;
    PORT
      LAYER M4 ;
        RECT  0 87.264 0.084 87.288 ;
    END
  END i0_lane[469]
  PIN i0_lane[46]
    DIRECTION INPUT ;
    USE SIGNAL ;
    PORT
      LAYER M4 ;
        RECT  0 46.656 0.084 46.68 ;
    END
  END i0_lane[46]
  PIN i0_lane[470]
    DIRECTION INPUT ;
    USE SIGNAL ;
    PORT
      LAYER M4 ;
        RECT  0 87.36 0.084 87.384 ;
    END
  END i0_lane[470]
  PIN i0_lane[471]
    DIRECTION INPUT ;
    USE SIGNAL ;
    PORT
      LAYER M4 ;
        RECT  0 87.456 0.084 87.48 ;
    END
  END i0_lane[471]
  PIN i0_lane[472]
    DIRECTION INPUT ;
    USE SIGNAL ;
    PORT
      LAYER M4 ;
        RECT  0 87.552 0.084 87.576 ;
    END
  END i0_lane[472]
  PIN i0_lane[473]
    DIRECTION INPUT ;
    USE SIGNAL ;
    PORT
      LAYER M4 ;
        RECT  0 87.648 0.084 87.672 ;
    END
  END i0_lane[473]
  PIN i0_lane[474]
    DIRECTION INPUT ;
    USE SIGNAL ;
    PORT
      LAYER M4 ;
        RECT  0 87.744 0.084 87.768 ;
    END
  END i0_lane[474]
  PIN i0_lane[475]
    DIRECTION INPUT ;
    USE SIGNAL ;
    PORT
      LAYER M4 ;
        RECT  0 87.84 0.084 87.864 ;
    END
  END i0_lane[475]
  PIN i0_lane[476]
    DIRECTION INPUT ;
    USE SIGNAL ;
    PORT
      LAYER M4 ;
        RECT  0 87.936 0.084 87.96 ;
    END
  END i0_lane[476]
  PIN i0_lane[477]
    DIRECTION INPUT ;
    USE SIGNAL ;
    PORT
      LAYER M4 ;
        RECT  0 88.032 0.084 88.056 ;
    END
  END i0_lane[477]
  PIN i0_lane[478]
    DIRECTION INPUT ;
    USE SIGNAL ;
    PORT
      LAYER M4 ;
        RECT  0 88.128 0.084 88.152 ;
    END
  END i0_lane[478]
  PIN i0_lane[479]
    DIRECTION INPUT ;
    USE SIGNAL ;
    PORT
      LAYER M4 ;
        RECT  0 88.224 0.084 88.248 ;
    END
  END i0_lane[479]
  PIN i0_lane[47]
    DIRECTION INPUT ;
    USE SIGNAL ;
    PORT
      LAYER M4 ;
        RECT  0 46.752 0.084 46.776 ;
    END
  END i0_lane[47]
  PIN i0_lane[480]
    DIRECTION INPUT ;
    USE SIGNAL ;
    PORT
      LAYER M4 ;
        RECT  0 88.32 0.084 88.344 ;
    END
  END i0_lane[480]
  PIN i0_lane[481]
    DIRECTION INPUT ;
    USE SIGNAL ;
    PORT
      LAYER M4 ;
        RECT  0 88.416 0.084 88.44 ;
    END
  END i0_lane[481]
  PIN i0_lane[482]
    DIRECTION INPUT ;
    USE SIGNAL ;
    PORT
      LAYER M4 ;
        RECT  0 88.512 0.084 88.536 ;
    END
  END i0_lane[482]
  PIN i0_lane[483]
    DIRECTION INPUT ;
    USE SIGNAL ;
    PORT
      LAYER M4 ;
        RECT  0 88.608 0.084 88.632 ;
    END
  END i0_lane[483]
  PIN i0_lane[484]
    DIRECTION INPUT ;
    USE SIGNAL ;
    PORT
      LAYER M4 ;
        RECT  0 88.704 0.084 88.728 ;
    END
  END i0_lane[484]
  PIN i0_lane[485]
    DIRECTION INPUT ;
    USE SIGNAL ;
    PORT
      LAYER M4 ;
        RECT  0 88.8 0.084 88.824 ;
    END
  END i0_lane[485]
  PIN i0_lane[486]
    DIRECTION INPUT ;
    USE SIGNAL ;
    PORT
      LAYER M4 ;
        RECT  0 88.896 0.084 88.92 ;
    END
  END i0_lane[486]
  PIN i0_lane[487]
    DIRECTION INPUT ;
    USE SIGNAL ;
    PORT
      LAYER M4 ;
        RECT  0 88.992 0.084 89.016 ;
    END
  END i0_lane[487]
  PIN i0_lane[488]
    DIRECTION INPUT ;
    USE SIGNAL ;
    PORT
      LAYER M4 ;
        RECT  0 89.088 0.084 89.112 ;
    END
  END i0_lane[488]
  PIN i0_lane[489]
    DIRECTION INPUT ;
    USE SIGNAL ;
    PORT
      LAYER M4 ;
        RECT  0 89.184 0.084 89.208 ;
    END
  END i0_lane[489]
  PIN i0_lane[48]
    DIRECTION INPUT ;
    USE SIGNAL ;
    PORT
      LAYER M4 ;
        RECT  0 46.848 0.084 46.872 ;
    END
  END i0_lane[48]
  PIN i0_lane[490]
    DIRECTION INPUT ;
    USE SIGNAL ;
    PORT
      LAYER M4 ;
        RECT  0 89.28 0.084 89.304 ;
    END
  END i0_lane[490]
  PIN i0_lane[491]
    DIRECTION INPUT ;
    USE SIGNAL ;
    PORT
      LAYER M4 ;
        RECT  0 89.376 0.084 89.4 ;
    END
  END i0_lane[491]
  PIN i0_lane[492]
    DIRECTION INPUT ;
    USE SIGNAL ;
    PORT
      LAYER M4 ;
        RECT  0 89.472 0.084 89.496 ;
    END
  END i0_lane[492]
  PIN i0_lane[493]
    DIRECTION INPUT ;
    USE SIGNAL ;
    PORT
      LAYER M4 ;
        RECT  0 89.568 0.084 89.592 ;
    END
  END i0_lane[493]
  PIN i0_lane[494]
    DIRECTION INPUT ;
    USE SIGNAL ;
    PORT
      LAYER M4 ;
        RECT  0 89.664 0.084 89.688 ;
    END
  END i0_lane[494]
  PIN i0_lane[495]
    DIRECTION INPUT ;
    USE SIGNAL ;
    PORT
      LAYER M4 ;
        RECT  0 89.76 0.084 89.784 ;
    END
  END i0_lane[495]
  PIN i0_lane[496]
    DIRECTION INPUT ;
    USE SIGNAL ;
    PORT
      LAYER M4 ;
        RECT  0 89.856 0.084 89.88 ;
    END
  END i0_lane[496]
  PIN i0_lane[497]
    DIRECTION INPUT ;
    USE SIGNAL ;
    PORT
      LAYER M4 ;
        RECT  0 89.952 0.084 89.976 ;
    END
  END i0_lane[497]
  PIN i0_lane[498]
    DIRECTION INPUT ;
    USE SIGNAL ;
    PORT
      LAYER M4 ;
        RECT  0 90.048 0.084 90.072 ;
    END
  END i0_lane[498]
  PIN i0_lane[499]
    DIRECTION INPUT ;
    USE SIGNAL ;
    PORT
      LAYER M4 ;
        RECT  0 90.144 0.084 90.168 ;
    END
  END i0_lane[499]
  PIN i0_lane[49]
    DIRECTION INPUT ;
    USE SIGNAL ;
    PORT
      LAYER M4 ;
        RECT  0 46.944 0.084 46.968 ;
    END
  END i0_lane[49]
  PIN i0_lane[4]
    DIRECTION INPUT ;
    USE SIGNAL ;
    PORT
      LAYER M4 ;
        RECT  0 42.624 0.084 42.648 ;
    END
  END i0_lane[4]
  PIN i0_lane[500]
    DIRECTION INPUT ;
    USE SIGNAL ;
    PORT
      LAYER M4 ;
        RECT  0 90.24 0.084 90.264 ;
    END
  END i0_lane[500]
  PIN i0_lane[501]
    DIRECTION INPUT ;
    USE SIGNAL ;
    PORT
      LAYER M4 ;
        RECT  0 90.336 0.084 90.36 ;
    END
  END i0_lane[501]
  PIN i0_lane[502]
    DIRECTION INPUT ;
    USE SIGNAL ;
    PORT
      LAYER M4 ;
        RECT  0 90.432 0.084 90.456 ;
    END
  END i0_lane[502]
  PIN i0_lane[503]
    DIRECTION INPUT ;
    USE SIGNAL ;
    PORT
      LAYER M4 ;
        RECT  0 90.528 0.084 90.552 ;
    END
  END i0_lane[503]
  PIN i0_lane[504]
    DIRECTION INPUT ;
    USE SIGNAL ;
    PORT
      LAYER M4 ;
        RECT  0 90.624 0.084 90.648 ;
    END
  END i0_lane[504]
  PIN i0_lane[505]
    DIRECTION INPUT ;
    USE SIGNAL ;
    PORT
      LAYER M4 ;
        RECT  0 90.72 0.084 90.744 ;
    END
  END i0_lane[505]
  PIN i0_lane[506]
    DIRECTION INPUT ;
    USE SIGNAL ;
    PORT
      LAYER M4 ;
        RECT  0 90.816 0.084 90.84 ;
    END
  END i0_lane[506]
  PIN i0_lane[507]
    DIRECTION INPUT ;
    USE SIGNAL ;
    PORT
      LAYER M4 ;
        RECT  0 90.912 0.084 90.936 ;
    END
  END i0_lane[507]
  PIN i0_lane[508]
    DIRECTION INPUT ;
    USE SIGNAL ;
    PORT
      LAYER M4 ;
        RECT  0 91.008 0.084 91.032 ;
    END
  END i0_lane[508]
  PIN i0_lane[509]
    DIRECTION INPUT ;
    USE SIGNAL ;
    PORT
      LAYER M4 ;
        RECT  0 91.104 0.084 91.128 ;
    END
  END i0_lane[509]
  PIN i0_lane[50]
    DIRECTION INPUT ;
    USE SIGNAL ;
    PORT
      LAYER M4 ;
        RECT  0 47.04 0.084 47.064 ;
    END
  END i0_lane[50]
  PIN i0_lane[510]
    DIRECTION INPUT ;
    USE SIGNAL ;
    PORT
      LAYER M4 ;
        RECT  0 91.2 0.084 91.224 ;
    END
  END i0_lane[510]
  PIN i0_lane[511]
    DIRECTION INPUT ;
    USE SIGNAL ;
    PORT
      LAYER M4 ;
        RECT  0 91.296 0.084 91.32 ;
    END
  END i0_lane[511]
  PIN i0_lane[512]
    DIRECTION INPUT ;
    USE SIGNAL ;
    PORT
      LAYER M4 ;
        RECT  0 91.392 0.084 91.416 ;
    END
  END i0_lane[512]
  PIN i0_lane[513]
    DIRECTION INPUT ;
    USE SIGNAL ;
    PORT
      LAYER M4 ;
        RECT  0 91.488 0.084 91.512 ;
    END
  END i0_lane[513]
  PIN i0_lane[514]
    DIRECTION INPUT ;
    USE SIGNAL ;
    PORT
      LAYER M4 ;
        RECT  0 91.584 0.084 91.608 ;
    END
  END i0_lane[514]
  PIN i0_lane[515]
    DIRECTION INPUT ;
    USE SIGNAL ;
    PORT
      LAYER M4 ;
        RECT  0 91.68 0.084 91.704 ;
    END
  END i0_lane[515]
  PIN i0_lane[516]
    DIRECTION INPUT ;
    USE SIGNAL ;
    PORT
      LAYER M4 ;
        RECT  0 91.776 0.084 91.8 ;
    END
  END i0_lane[516]
  PIN i0_lane[517]
    DIRECTION INPUT ;
    USE SIGNAL ;
    PORT
      LAYER M4 ;
        RECT  0 91.872 0.084 91.896 ;
    END
  END i0_lane[517]
  PIN i0_lane[518]
    DIRECTION INPUT ;
    USE SIGNAL ;
    PORT
      LAYER M4 ;
        RECT  0 91.968 0.084 91.992 ;
    END
  END i0_lane[518]
  PIN i0_lane[519]
    DIRECTION INPUT ;
    USE SIGNAL ;
    PORT
      LAYER M4 ;
        RECT  0 92.064 0.084 92.088 ;
    END
  END i0_lane[519]
  PIN i0_lane[51]
    DIRECTION INPUT ;
    USE SIGNAL ;
    PORT
      LAYER M4 ;
        RECT  0 47.136 0.084 47.16 ;
    END
  END i0_lane[51]
  PIN i0_lane[520]
    DIRECTION INPUT ;
    USE SIGNAL ;
    PORT
      LAYER M4 ;
        RECT  0 92.16 0.084 92.184 ;
    END
  END i0_lane[520]
  PIN i0_lane[521]
    DIRECTION INPUT ;
    USE SIGNAL ;
    PORT
      LAYER M4 ;
        RECT  0 92.256 0.084 92.28 ;
    END
  END i0_lane[521]
  PIN i0_lane[522]
    DIRECTION INPUT ;
    USE SIGNAL ;
    PORT
      LAYER M4 ;
        RECT  0 92.352 0.084 92.376 ;
    END
  END i0_lane[522]
  PIN i0_lane[523]
    DIRECTION INPUT ;
    USE SIGNAL ;
    PORT
      LAYER M4 ;
        RECT  0 92.448 0.084 92.472 ;
    END
  END i0_lane[523]
  PIN i0_lane[524]
    DIRECTION INPUT ;
    USE SIGNAL ;
    PORT
      LAYER M4 ;
        RECT  0 92.544 0.084 92.568 ;
    END
  END i0_lane[524]
  PIN i0_lane[525]
    DIRECTION INPUT ;
    USE SIGNAL ;
    PORT
      LAYER M4 ;
        RECT  0 92.64 0.084 92.664 ;
    END
  END i0_lane[525]
  PIN i0_lane[526]
    DIRECTION INPUT ;
    USE SIGNAL ;
    PORT
      LAYER M4 ;
        RECT  0 92.736 0.084 92.76 ;
    END
  END i0_lane[526]
  PIN i0_lane[527]
    DIRECTION INPUT ;
    USE SIGNAL ;
    PORT
      LAYER M4 ;
        RECT  0 92.832 0.084 92.856 ;
    END
  END i0_lane[527]
  PIN i0_lane[528]
    DIRECTION INPUT ;
    USE SIGNAL ;
    PORT
      LAYER M4 ;
        RECT  0 92.928 0.084 92.952 ;
    END
  END i0_lane[528]
  PIN i0_lane[529]
    DIRECTION INPUT ;
    USE SIGNAL ;
    PORT
      LAYER M4 ;
        RECT  0 93.024 0.084 93.048 ;
    END
  END i0_lane[529]
  PIN i0_lane[52]
    DIRECTION INPUT ;
    USE SIGNAL ;
    PORT
      LAYER M4 ;
        RECT  0 47.232 0.084 47.256 ;
    END
  END i0_lane[52]
  PIN i0_lane[530]
    DIRECTION INPUT ;
    USE SIGNAL ;
    PORT
      LAYER M4 ;
        RECT  0 93.12 0.084 93.144 ;
    END
  END i0_lane[530]
  PIN i0_lane[531]
    DIRECTION INPUT ;
    USE SIGNAL ;
    PORT
      LAYER M4 ;
        RECT  0 93.216 0.084 93.24 ;
    END
  END i0_lane[531]
  PIN i0_lane[532]
    DIRECTION INPUT ;
    USE SIGNAL ;
    PORT
      LAYER M4 ;
        RECT  0 93.312 0.084 93.336 ;
    END
  END i0_lane[532]
  PIN i0_lane[533]
    DIRECTION INPUT ;
    USE SIGNAL ;
    PORT
      LAYER M4 ;
        RECT  0 93.408 0.084 93.432 ;
    END
  END i0_lane[533]
  PIN i0_lane[534]
    DIRECTION INPUT ;
    USE SIGNAL ;
    PORT
      LAYER M4 ;
        RECT  0 93.504 0.084 93.528 ;
    END
  END i0_lane[534]
  PIN i0_lane[535]
    DIRECTION INPUT ;
    USE SIGNAL ;
    PORT
      LAYER M4 ;
        RECT  0 93.6 0.084 93.624 ;
    END
  END i0_lane[535]
  PIN i0_lane[536]
    DIRECTION INPUT ;
    USE SIGNAL ;
    PORT
      LAYER M4 ;
        RECT  0 93.696 0.084 93.72 ;
    END
  END i0_lane[536]
  PIN i0_lane[537]
    DIRECTION INPUT ;
    USE SIGNAL ;
    PORT
      LAYER M4 ;
        RECT  0 93.792 0.084 93.816 ;
    END
  END i0_lane[537]
  PIN i0_lane[538]
    DIRECTION INPUT ;
    USE SIGNAL ;
    PORT
      LAYER M4 ;
        RECT  0 93.888 0.084 93.912 ;
    END
  END i0_lane[538]
  PIN i0_lane[539]
    DIRECTION INPUT ;
    USE SIGNAL ;
    PORT
      LAYER M4 ;
        RECT  0 93.984 0.084 94.008 ;
    END
  END i0_lane[539]
  PIN i0_lane[53]
    DIRECTION INPUT ;
    USE SIGNAL ;
    PORT
      LAYER M4 ;
        RECT  0 47.328 0.084 47.352 ;
    END
  END i0_lane[53]
  PIN i0_lane[540]
    DIRECTION INPUT ;
    USE SIGNAL ;
    PORT
      LAYER M4 ;
        RECT  0 94.08 0.084 94.104 ;
    END
  END i0_lane[540]
  PIN i0_lane[541]
    DIRECTION INPUT ;
    USE SIGNAL ;
    PORT
      LAYER M4 ;
        RECT  0 94.176 0.084 94.2 ;
    END
  END i0_lane[541]
  PIN i0_lane[542]
    DIRECTION INPUT ;
    USE SIGNAL ;
    PORT
      LAYER M4 ;
        RECT  0 94.272 0.084 94.296 ;
    END
  END i0_lane[542]
  PIN i0_lane[543]
    DIRECTION INPUT ;
    USE SIGNAL ;
    PORT
      LAYER M4 ;
        RECT  0 94.368 0.084 94.392 ;
    END
  END i0_lane[543]
  PIN i0_lane[544]
    DIRECTION INPUT ;
    USE SIGNAL ;
    PORT
      LAYER M4 ;
        RECT  0 94.464 0.084 94.488 ;
    END
  END i0_lane[544]
  PIN i0_lane[545]
    DIRECTION INPUT ;
    USE SIGNAL ;
    PORT
      LAYER M4 ;
        RECT  0 94.56 0.084 94.584 ;
    END
  END i0_lane[545]
  PIN i0_lane[546]
    DIRECTION INPUT ;
    USE SIGNAL ;
    PORT
      LAYER M4 ;
        RECT  0 94.656 0.084 94.68 ;
    END
  END i0_lane[546]
  PIN i0_lane[547]
    DIRECTION INPUT ;
    USE SIGNAL ;
    PORT
      LAYER M4 ;
        RECT  0 94.752 0.084 94.776 ;
    END
  END i0_lane[547]
  PIN i0_lane[548]
    DIRECTION INPUT ;
    USE SIGNAL ;
    PORT
      LAYER M4 ;
        RECT  0 94.848 0.084 94.872 ;
    END
  END i0_lane[548]
  PIN i0_lane[549]
    DIRECTION INPUT ;
    USE SIGNAL ;
    PORT
      LAYER M4 ;
        RECT  0 94.944 0.084 94.968 ;
    END
  END i0_lane[549]
  PIN i0_lane[54]
    DIRECTION INPUT ;
    USE SIGNAL ;
    PORT
      LAYER M4 ;
        RECT  0 47.424 0.084 47.448 ;
    END
  END i0_lane[54]
  PIN i0_lane[550]
    DIRECTION INPUT ;
    USE SIGNAL ;
    PORT
      LAYER M4 ;
        RECT  0 95.04 0.084 95.064 ;
    END
  END i0_lane[550]
  PIN i0_lane[551]
    DIRECTION INPUT ;
    USE SIGNAL ;
    PORT
      LAYER M4 ;
        RECT  0 95.136 0.084 95.16 ;
    END
  END i0_lane[551]
  PIN i0_lane[552]
    DIRECTION INPUT ;
    USE SIGNAL ;
    PORT
      LAYER M4 ;
        RECT  0 95.232 0.084 95.256 ;
    END
  END i0_lane[552]
  PIN i0_lane[553]
    DIRECTION INPUT ;
    USE SIGNAL ;
    PORT
      LAYER M4 ;
        RECT  0 95.328 0.084 95.352 ;
    END
  END i0_lane[553]
  PIN i0_lane[554]
    DIRECTION INPUT ;
    USE SIGNAL ;
    PORT
      LAYER M4 ;
        RECT  0 95.424 0.084 95.448 ;
    END
  END i0_lane[554]
  PIN i0_lane[555]
    DIRECTION INPUT ;
    USE SIGNAL ;
    PORT
      LAYER M4 ;
        RECT  0 95.52 0.084 95.544 ;
    END
  END i0_lane[555]
  PIN i0_lane[556]
    DIRECTION INPUT ;
    USE SIGNAL ;
    PORT
      LAYER M4 ;
        RECT  0 95.616 0.084 95.64 ;
    END
  END i0_lane[556]
  PIN i0_lane[557]
    DIRECTION INPUT ;
    USE SIGNAL ;
    PORT
      LAYER M4 ;
        RECT  0 95.712 0.084 95.736 ;
    END
  END i0_lane[557]
  PIN i0_lane[558]
    DIRECTION INPUT ;
    USE SIGNAL ;
    PORT
      LAYER M4 ;
        RECT  0 95.808 0.084 95.832 ;
    END
  END i0_lane[558]
  PIN i0_lane[559]
    DIRECTION INPUT ;
    USE SIGNAL ;
    PORT
      LAYER M4 ;
        RECT  0 95.904 0.084 95.928 ;
    END
  END i0_lane[559]
  PIN i0_lane[55]
    DIRECTION INPUT ;
    USE SIGNAL ;
    PORT
      LAYER M4 ;
        RECT  0 47.52 0.084 47.544 ;
    END
  END i0_lane[55]
  PIN i0_lane[560]
    DIRECTION INPUT ;
    USE SIGNAL ;
    PORT
      LAYER M4 ;
        RECT  0 96 0.084 96.024 ;
    END
  END i0_lane[560]
  PIN i0_lane[561]
    DIRECTION INPUT ;
    USE SIGNAL ;
    PORT
      LAYER M4 ;
        RECT  0 96.096 0.084 96.12 ;
    END
  END i0_lane[561]
  PIN i0_lane[562]
    DIRECTION INPUT ;
    USE SIGNAL ;
    PORT
      LAYER M4 ;
        RECT  0 96.192 0.084 96.216 ;
    END
  END i0_lane[562]
  PIN i0_lane[563]
    DIRECTION INPUT ;
    USE SIGNAL ;
    PORT
      LAYER M4 ;
        RECT  0 96.288 0.084 96.312 ;
    END
  END i0_lane[563]
  PIN i0_lane[564]
    DIRECTION INPUT ;
    USE SIGNAL ;
    PORT
      LAYER M4 ;
        RECT  0 96.384 0.084 96.408 ;
    END
  END i0_lane[564]
  PIN i0_lane[565]
    DIRECTION INPUT ;
    USE SIGNAL ;
    PORT
      LAYER M4 ;
        RECT  0 96.48 0.084 96.504 ;
    END
  END i0_lane[565]
  PIN i0_lane[566]
    DIRECTION INPUT ;
    USE SIGNAL ;
    PORT
      LAYER M4 ;
        RECT  0 96.576 0.084 96.6 ;
    END
  END i0_lane[566]
  PIN i0_lane[567]
    DIRECTION INPUT ;
    USE SIGNAL ;
    PORT
      LAYER M4 ;
        RECT  0 96.672 0.084 96.696 ;
    END
  END i0_lane[567]
  PIN i0_lane[568]
    DIRECTION INPUT ;
    USE SIGNAL ;
    PORT
      LAYER M4 ;
        RECT  0 96.768 0.084 96.792 ;
    END
  END i0_lane[568]
  PIN i0_lane[569]
    DIRECTION INPUT ;
    USE SIGNAL ;
    PORT
      LAYER M4 ;
        RECT  0 96.864 0.084 96.888 ;
    END
  END i0_lane[569]
  PIN i0_lane[56]
    DIRECTION INPUT ;
    USE SIGNAL ;
    PORT
      LAYER M4 ;
        RECT  0 47.616 0.084 47.64 ;
    END
  END i0_lane[56]
  PIN i0_lane[570]
    DIRECTION INPUT ;
    USE SIGNAL ;
    PORT
      LAYER M4 ;
        RECT  0 96.96 0.084 96.984 ;
    END
  END i0_lane[570]
  PIN i0_lane[571]
    DIRECTION INPUT ;
    USE SIGNAL ;
    PORT
      LAYER M4 ;
        RECT  0 97.056 0.084 97.08 ;
    END
  END i0_lane[571]
  PIN i0_lane[572]
    DIRECTION INPUT ;
    USE SIGNAL ;
    PORT
      LAYER M4 ;
        RECT  0 97.152 0.084 97.176 ;
    END
  END i0_lane[572]
  PIN i0_lane[573]
    DIRECTION INPUT ;
    USE SIGNAL ;
    PORT
      LAYER M4 ;
        RECT  0 97.248 0.084 97.272 ;
    END
  END i0_lane[573]
  PIN i0_lane[574]
    DIRECTION INPUT ;
    USE SIGNAL ;
    PORT
      LAYER M4 ;
        RECT  0 97.344 0.084 97.368 ;
    END
  END i0_lane[574]
  PIN i0_lane[575]
    DIRECTION INPUT ;
    USE SIGNAL ;
    PORT
      LAYER M4 ;
        RECT  0 97.44 0.084 97.464 ;
    END
  END i0_lane[575]
  PIN i0_lane[576]
    DIRECTION INPUT ;
    USE SIGNAL ;
    PORT
      LAYER M4 ;
        RECT  0 97.536 0.084 97.56 ;
    END
  END i0_lane[576]
  PIN i0_lane[577]
    DIRECTION INPUT ;
    USE SIGNAL ;
    PORT
      LAYER M4 ;
        RECT  0 97.632 0.084 97.656 ;
    END
  END i0_lane[577]
  PIN i0_lane[578]
    DIRECTION INPUT ;
    USE SIGNAL ;
    PORT
      LAYER M4 ;
        RECT  0 97.728 0.084 97.752 ;
    END
  END i0_lane[578]
  PIN i0_lane[579]
    DIRECTION INPUT ;
    USE SIGNAL ;
    PORT
      LAYER M4 ;
        RECT  0 97.824 0.084 97.848 ;
    END
  END i0_lane[579]
  PIN i0_lane[57]
    DIRECTION INPUT ;
    USE SIGNAL ;
    PORT
      LAYER M4 ;
        RECT  0 47.712 0.084 47.736 ;
    END
  END i0_lane[57]
  PIN i0_lane[580]
    DIRECTION INPUT ;
    USE SIGNAL ;
    PORT
      LAYER M4 ;
        RECT  0 97.92 0.084 97.944 ;
    END
  END i0_lane[580]
  PIN i0_lane[581]
    DIRECTION INPUT ;
    USE SIGNAL ;
    PORT
      LAYER M4 ;
        RECT  0 98.016 0.084 98.04 ;
    END
  END i0_lane[581]
  PIN i0_lane[582]
    DIRECTION INPUT ;
    USE SIGNAL ;
    PORT
      LAYER M4 ;
        RECT  0 98.112 0.084 98.136 ;
    END
  END i0_lane[582]
  PIN i0_lane[583]
    DIRECTION INPUT ;
    USE SIGNAL ;
    PORT
      LAYER M4 ;
        RECT  0 98.208 0.084 98.232 ;
    END
  END i0_lane[583]
  PIN i0_lane[584]
    DIRECTION INPUT ;
    USE SIGNAL ;
    PORT
      LAYER M4 ;
        RECT  0 98.304 0.084 98.328 ;
    END
  END i0_lane[584]
  PIN i0_lane[585]
    DIRECTION INPUT ;
    USE SIGNAL ;
    PORT
      LAYER M4 ;
        RECT  0 98.4 0.084 98.424 ;
    END
  END i0_lane[585]
  PIN i0_lane[586]
    DIRECTION INPUT ;
    USE SIGNAL ;
    PORT
      LAYER M4 ;
        RECT  0 98.496 0.084 98.52 ;
    END
  END i0_lane[586]
  PIN i0_lane[587]
    DIRECTION INPUT ;
    USE SIGNAL ;
    PORT
      LAYER M4 ;
        RECT  0 98.592 0.084 98.616 ;
    END
  END i0_lane[587]
  PIN i0_lane[588]
    DIRECTION INPUT ;
    USE SIGNAL ;
    PORT
      LAYER M4 ;
        RECT  0 98.688 0.084 98.712 ;
    END
  END i0_lane[588]
  PIN i0_lane[589]
    DIRECTION INPUT ;
    USE SIGNAL ;
    PORT
      LAYER M4 ;
        RECT  0 98.784 0.084 98.808 ;
    END
  END i0_lane[589]
  PIN i0_lane[58]
    DIRECTION INPUT ;
    USE SIGNAL ;
    PORT
      LAYER M4 ;
        RECT  0 47.808 0.084 47.832 ;
    END
  END i0_lane[58]
  PIN i0_lane[590]
    DIRECTION INPUT ;
    USE SIGNAL ;
    PORT
      LAYER M4 ;
        RECT  0 98.88 0.084 98.904 ;
    END
  END i0_lane[590]
  PIN i0_lane[591]
    DIRECTION INPUT ;
    USE SIGNAL ;
    PORT
      LAYER M4 ;
        RECT  0 98.976 0.084 99 ;
    END
  END i0_lane[591]
  PIN i0_lane[59]
    DIRECTION INPUT ;
    USE SIGNAL ;
    PORT
      LAYER M4 ;
        RECT  0 47.904 0.084 47.928 ;
    END
  END i0_lane[59]
  PIN i0_lane[5]
    DIRECTION INPUT ;
    USE SIGNAL ;
    PORT
      LAYER M4 ;
        RECT  0 42.72 0.084 42.744 ;
    END
  END i0_lane[5]
  PIN i0_lane[60]
    DIRECTION INPUT ;
    USE SIGNAL ;
    PORT
      LAYER M4 ;
        RECT  0 48 0.084 48.024 ;
    END
  END i0_lane[60]
  PIN i0_lane[61]
    DIRECTION INPUT ;
    USE SIGNAL ;
    PORT
      LAYER M4 ;
        RECT  0 48.096 0.084 48.12 ;
    END
  END i0_lane[61]
  PIN i0_lane[62]
    DIRECTION INPUT ;
    USE SIGNAL ;
    PORT
      LAYER M4 ;
        RECT  0 48.192 0.084 48.216 ;
    END
  END i0_lane[62]
  PIN i0_lane[63]
    DIRECTION INPUT ;
    USE SIGNAL ;
    PORT
      LAYER M4 ;
        RECT  0 48.288 0.084 48.312 ;
    END
  END i0_lane[63]
  PIN i0_lane[64]
    DIRECTION INPUT ;
    USE SIGNAL ;
    PORT
      LAYER M4 ;
        RECT  0 48.384 0.084 48.408 ;
    END
  END i0_lane[64]
  PIN i0_lane[65]
    DIRECTION INPUT ;
    USE SIGNAL ;
    PORT
      LAYER M4 ;
        RECT  0 48.48 0.084 48.504 ;
    END
  END i0_lane[65]
  PIN i0_lane[66]
    DIRECTION INPUT ;
    USE SIGNAL ;
    PORT
      LAYER M4 ;
        RECT  0 48.576 0.084 48.6 ;
    END
  END i0_lane[66]
  PIN i0_lane[67]
    DIRECTION INPUT ;
    USE SIGNAL ;
    PORT
      LAYER M4 ;
        RECT  0 48.672 0.084 48.696 ;
    END
  END i0_lane[67]
  PIN i0_lane[68]
    DIRECTION INPUT ;
    USE SIGNAL ;
    PORT
      LAYER M4 ;
        RECT  0 48.768 0.084 48.792 ;
    END
  END i0_lane[68]
  PIN i0_lane[69]
    DIRECTION INPUT ;
    USE SIGNAL ;
    PORT
      LAYER M4 ;
        RECT  0 48.864 0.084 48.888 ;
    END
  END i0_lane[69]
  PIN i0_lane[6]
    DIRECTION INPUT ;
    USE SIGNAL ;
    PORT
      LAYER M4 ;
        RECT  0 42.816 0.084 42.84 ;
    END
  END i0_lane[6]
  PIN i0_lane[70]
    DIRECTION INPUT ;
    USE SIGNAL ;
    PORT
      LAYER M4 ;
        RECT  0 48.96 0.084 48.984 ;
    END
  END i0_lane[70]
  PIN i0_lane[71]
    DIRECTION INPUT ;
    USE SIGNAL ;
    PORT
      LAYER M4 ;
        RECT  0 49.056 0.084 49.08 ;
    END
  END i0_lane[71]
  PIN i0_lane[72]
    DIRECTION INPUT ;
    USE SIGNAL ;
    PORT
      LAYER M4 ;
        RECT  0 49.152 0.084 49.176 ;
    END
  END i0_lane[72]
  PIN i0_lane[73]
    DIRECTION INPUT ;
    USE SIGNAL ;
    PORT
      LAYER M4 ;
        RECT  0 49.248 0.084 49.272 ;
    END
  END i0_lane[73]
  PIN i0_lane[74]
    DIRECTION INPUT ;
    USE SIGNAL ;
    PORT
      LAYER M4 ;
        RECT  0 49.344 0.084 49.368 ;
    END
  END i0_lane[74]
  PIN i0_lane[75]
    DIRECTION INPUT ;
    USE SIGNAL ;
    PORT
      LAYER M4 ;
        RECT  0 49.44 0.084 49.464 ;
    END
  END i0_lane[75]
  PIN i0_lane[76]
    DIRECTION INPUT ;
    USE SIGNAL ;
    PORT
      LAYER M4 ;
        RECT  0 49.536 0.084 49.56 ;
    END
  END i0_lane[76]
  PIN i0_lane[77]
    DIRECTION INPUT ;
    USE SIGNAL ;
    PORT
      LAYER M4 ;
        RECT  0 49.632 0.084 49.656 ;
    END
  END i0_lane[77]
  PIN i0_lane[78]
    DIRECTION INPUT ;
    USE SIGNAL ;
    PORT
      LAYER M4 ;
        RECT  0 49.728 0.084 49.752 ;
    END
  END i0_lane[78]
  PIN i0_lane[79]
    DIRECTION INPUT ;
    USE SIGNAL ;
    PORT
      LAYER M4 ;
        RECT  0 49.824 0.084 49.848 ;
    END
  END i0_lane[79]
  PIN i0_lane[7]
    DIRECTION INPUT ;
    USE SIGNAL ;
    PORT
      LAYER M4 ;
        RECT  0 42.912 0.084 42.936 ;
    END
  END i0_lane[7]
  PIN i0_lane[80]
    DIRECTION INPUT ;
    USE SIGNAL ;
    PORT
      LAYER M4 ;
        RECT  0 49.92 0.084 49.944 ;
    END
  END i0_lane[80]
  PIN i0_lane[81]
    DIRECTION INPUT ;
    USE SIGNAL ;
    PORT
      LAYER M4 ;
        RECT  0 50.016 0.084 50.04 ;
    END
  END i0_lane[81]
  PIN i0_lane[82]
    DIRECTION INPUT ;
    USE SIGNAL ;
    PORT
      LAYER M4 ;
        RECT  0 50.112 0.084 50.136 ;
    END
  END i0_lane[82]
  PIN i0_lane[83]
    DIRECTION INPUT ;
    USE SIGNAL ;
    PORT
      LAYER M4 ;
        RECT  0 50.208 0.084 50.232 ;
    END
  END i0_lane[83]
  PIN i0_lane[84]
    DIRECTION INPUT ;
    USE SIGNAL ;
    PORT
      LAYER M4 ;
        RECT  0 50.304 0.084 50.328 ;
    END
  END i0_lane[84]
  PIN i0_lane[85]
    DIRECTION INPUT ;
    USE SIGNAL ;
    PORT
      LAYER M4 ;
        RECT  0 50.4 0.084 50.424 ;
    END
  END i0_lane[85]
  PIN i0_lane[86]
    DIRECTION INPUT ;
    USE SIGNAL ;
    PORT
      LAYER M4 ;
        RECT  0 50.496 0.084 50.52 ;
    END
  END i0_lane[86]
  PIN i0_lane[87]
    DIRECTION INPUT ;
    USE SIGNAL ;
    PORT
      LAYER M4 ;
        RECT  0 50.592 0.084 50.616 ;
    END
  END i0_lane[87]
  PIN i0_lane[88]
    DIRECTION INPUT ;
    USE SIGNAL ;
    PORT
      LAYER M4 ;
        RECT  0 50.688 0.084 50.712 ;
    END
  END i0_lane[88]
  PIN i0_lane[89]
    DIRECTION INPUT ;
    USE SIGNAL ;
    PORT
      LAYER M4 ;
        RECT  0 50.784 0.084 50.808 ;
    END
  END i0_lane[89]
  PIN i0_lane[8]
    DIRECTION INPUT ;
    USE SIGNAL ;
    PORT
      LAYER M4 ;
        RECT  0 43.008 0.084 43.032 ;
    END
  END i0_lane[8]
  PIN i0_lane[90]
    DIRECTION INPUT ;
    USE SIGNAL ;
    PORT
      LAYER M4 ;
        RECT  0 50.88 0.084 50.904 ;
    END
  END i0_lane[90]
  PIN i0_lane[91]
    DIRECTION INPUT ;
    USE SIGNAL ;
    PORT
      LAYER M4 ;
        RECT  0 50.976 0.084 51 ;
    END
  END i0_lane[91]
  PIN i0_lane[92]
    DIRECTION INPUT ;
    USE SIGNAL ;
    PORT
      LAYER M4 ;
        RECT  0 51.072 0.084 51.096 ;
    END
  END i0_lane[92]
  PIN i0_lane[93]
    DIRECTION INPUT ;
    USE SIGNAL ;
    PORT
      LAYER M4 ;
        RECT  0 51.168 0.084 51.192 ;
    END
  END i0_lane[93]
  PIN i0_lane[94]
    DIRECTION INPUT ;
    USE SIGNAL ;
    PORT
      LAYER M4 ;
        RECT  0 51.264 0.084 51.288 ;
    END
  END i0_lane[94]
  PIN i0_lane[95]
    DIRECTION INPUT ;
    USE SIGNAL ;
    PORT
      LAYER M4 ;
        RECT  0 51.36 0.084 51.384 ;
    END
  END i0_lane[95]
  PIN i0_lane[96]
    DIRECTION INPUT ;
    USE SIGNAL ;
    PORT
      LAYER M4 ;
        RECT  0 51.456 0.084 51.48 ;
    END
  END i0_lane[96]
  PIN i0_lane[97]
    DIRECTION INPUT ;
    USE SIGNAL ;
    PORT
      LAYER M4 ;
        RECT  0 51.552 0.084 51.576 ;
    END
  END i0_lane[97]
  PIN i0_lane[98]
    DIRECTION INPUT ;
    USE SIGNAL ;
    PORT
      LAYER M4 ;
        RECT  0 51.648 0.084 51.672 ;
    END
  END i0_lane[98]
  PIN i0_lane[99]
    DIRECTION INPUT ;
    USE SIGNAL ;
    PORT
      LAYER M4 ;
        RECT  0 51.744 0.084 51.768 ;
    END
  END i0_lane[99]
  PIN i0_lane[9]
    DIRECTION INPUT ;
    USE SIGNAL ;
    PORT
      LAYER M4 ;
        RECT  0 43.104 0.084 43.128 ;
    END
  END i0_lane[9]
  PIN i0_last
    DIRECTION INPUT ;
    USE SIGNAL ;
    PORT
      LAYER M4 ;
        RECT  0 38.88 0.084 38.904 ;
    END
  END i0_last
  PIN i1_s_d[0]
    DIRECTION INPUT ;
    USE SIGNAL ;
    PORT
      LAYER M4 ;
        RECT  0 39.168 0.084 39.192 ;
    END
  END i1_s_d[0]
  PIN i1_s_d[10]
    DIRECTION INPUT ;
    USE SIGNAL ;
    PORT
      LAYER M4 ;
        RECT  0 40.128 0.084 40.152 ;
    END
  END i1_s_d[10]
  PIN i1_s_d[11]
    DIRECTION INPUT ;
    USE SIGNAL ;
    PORT
      LAYER M4 ;
        RECT  0 40.224 0.084 40.248 ;
    END
  END i1_s_d[11]
  PIN i1_s_d[12]
    DIRECTION INPUT ;
    USE SIGNAL ;
    PORT
      LAYER M4 ;
        RECT  0 40.32 0.084 40.344 ;
    END
  END i1_s_d[12]
  PIN i1_s_d[13]
    DIRECTION INPUT ;
    USE SIGNAL ;
    PORT
      LAYER M4 ;
        RECT  0 40.416 0.084 40.44 ;
    END
  END i1_s_d[13]
  PIN i1_s_d[14]
    DIRECTION INPUT ;
    USE SIGNAL ;
    PORT
      LAYER M4 ;
        RECT  0 40.512 0.084 40.536 ;
    END
  END i1_s_d[14]
  PIN i1_s_d[15]
    DIRECTION INPUT ;
    USE SIGNAL ;
    PORT
      LAYER M4 ;
        RECT  0 40.608 0.084 40.632 ;
    END
  END i1_s_d[15]
  PIN i1_s_d[1]
    DIRECTION INPUT ;
    USE SIGNAL ;
    PORT
      LAYER M4 ;
        RECT  0 39.264 0.084 39.288 ;
    END
  END i1_s_d[1]
  PIN i1_s_d[2]
    DIRECTION INPUT ;
    USE SIGNAL ;
    PORT
      LAYER M4 ;
        RECT  0 39.36 0.084 39.384 ;
    END
  END i1_s_d[2]
  PIN i1_s_d[3]
    DIRECTION INPUT ;
    USE SIGNAL ;
    PORT
      LAYER M4 ;
        RECT  0 39.456 0.084 39.48 ;
    END
  END i1_s_d[3]
  PIN i1_s_d[4]
    DIRECTION INPUT ;
    USE SIGNAL ;
    PORT
      LAYER M4 ;
        RECT  0 39.552 0.084 39.576 ;
    END
  END i1_s_d[4]
  PIN i1_s_d[5]
    DIRECTION INPUT ;
    USE SIGNAL ;
    PORT
      LAYER M4 ;
        RECT  0 39.648 0.084 39.672 ;
    END
  END i1_s_d[5]
  PIN i1_s_d[6]
    DIRECTION INPUT ;
    USE SIGNAL ;
    PORT
      LAYER M4 ;
        RECT  0 39.744 0.084 39.768 ;
    END
  END i1_s_d[6]
  PIN i1_s_d[7]
    DIRECTION INPUT ;
    USE SIGNAL ;
    PORT
      LAYER M4 ;
        RECT  0 39.84 0.084 39.864 ;
    END
  END i1_s_d[7]
  PIN i1_s_d[8]
    DIRECTION INPUT ;
    USE SIGNAL ;
    PORT
      LAYER M4 ;
        RECT  0 39.936 0.084 39.96 ;
    END
  END i1_s_d[8]
  PIN i1_s_d[9]
    DIRECTION INPUT ;
    USE SIGNAL ;
    PORT
      LAYER M4 ;
        RECT  0 40.032 0.084 40.056 ;
    END
  END i1_s_d[9]
  PIN i_ing
    DIRECTION INPUT ;
    USE SIGNAL ;
    PORT
      LAYER M4 ;
        RECT  0 38.784 0.084 38.808 ;
    END
  END i_ing
  PIN pi_bv
    DIRECTION OUTPUT ;
    USE SIGNAL ;
    PORT
      LAYER M4 ;
        RECT  194.316 38.784 194.4 38.808 ;
    END
  END pi_bv
  PIN pi_fl
    DIRECTION OUTPUT ;
    USE SIGNAL ;
    PORT
      LAYER M4 ;
        RECT  194.316 38.688 194.4 38.712 ;
    END
  END pi_fl
  PIN pi_line[0]
    DIRECTION OUTPUT ;
    USE SIGNAL ;
    PORT
      LAYER M4 ;
        RECT  194.316 42.72 194.4 42.744 ;
    END
  END pi_line[0]
  PIN pi_line[100]
    DIRECTION OUTPUT ;
    USE SIGNAL ;
    PORT
      LAYER M4 ;
        RECT  194.316 52.32 194.4 52.344 ;
    END
  END pi_line[100]
  PIN pi_line[101]
    DIRECTION OUTPUT ;
    USE SIGNAL ;
    PORT
      LAYER M4 ;
        RECT  194.316 52.416 194.4 52.44 ;
    END
  END pi_line[101]
  PIN pi_line[102]
    DIRECTION OUTPUT ;
    USE SIGNAL ;
    PORT
      LAYER M4 ;
        RECT  194.316 52.512 194.4 52.536 ;
    END
  END pi_line[102]
  PIN pi_line[103]
    DIRECTION OUTPUT ;
    USE SIGNAL ;
    PORT
      LAYER M4 ;
        RECT  194.316 52.608 194.4 52.632 ;
    END
  END pi_line[103]
  PIN pi_line[104]
    DIRECTION OUTPUT ;
    USE SIGNAL ;
    PORT
      LAYER M4 ;
        RECT  194.316 52.704 194.4 52.728 ;
    END
  END pi_line[104]
  PIN pi_line[105]
    DIRECTION OUTPUT ;
    USE SIGNAL ;
    PORT
      LAYER M4 ;
        RECT  194.316 52.8 194.4 52.824 ;
    END
  END pi_line[105]
  PIN pi_line[106]
    DIRECTION OUTPUT ;
    USE SIGNAL ;
    PORT
      LAYER M4 ;
        RECT  194.316 52.896 194.4 52.92 ;
    END
  END pi_line[106]
  PIN pi_line[107]
    DIRECTION OUTPUT ;
    USE SIGNAL ;
    PORT
      LAYER M4 ;
        RECT  194.316 52.992 194.4 53.016 ;
    END
  END pi_line[107]
  PIN pi_line[108]
    DIRECTION OUTPUT ;
    USE SIGNAL ;
    PORT
      LAYER M4 ;
        RECT  194.316 53.088 194.4 53.112 ;
    END
  END pi_line[108]
  PIN pi_line[109]
    DIRECTION OUTPUT ;
    USE SIGNAL ;
    PORT
      LAYER M4 ;
        RECT  194.316 53.184 194.4 53.208 ;
    END
  END pi_line[109]
  PIN pi_line[10]
    DIRECTION OUTPUT ;
    USE SIGNAL ;
    PORT
      LAYER M4 ;
        RECT  194.316 43.68 194.4 43.704 ;
    END
  END pi_line[10]
  PIN pi_line[110]
    DIRECTION OUTPUT ;
    USE SIGNAL ;
    PORT
      LAYER M4 ;
        RECT  194.316 53.28 194.4 53.304 ;
    END
  END pi_line[110]
  PIN pi_line[111]
    DIRECTION OUTPUT ;
    USE SIGNAL ;
    PORT
      LAYER M4 ;
        RECT  194.316 53.376 194.4 53.4 ;
    END
  END pi_line[111]
  PIN pi_line[112]
    DIRECTION OUTPUT ;
    USE SIGNAL ;
    PORT
      LAYER M4 ;
        RECT  194.316 53.472 194.4 53.496 ;
    END
  END pi_line[112]
  PIN pi_line[113]
    DIRECTION OUTPUT ;
    USE SIGNAL ;
    PORT
      LAYER M4 ;
        RECT  194.316 53.568 194.4 53.592 ;
    END
  END pi_line[113]
  PIN pi_line[114]
    DIRECTION OUTPUT ;
    USE SIGNAL ;
    PORT
      LAYER M4 ;
        RECT  194.316 53.664 194.4 53.688 ;
    END
  END pi_line[114]
  PIN pi_line[115]
    DIRECTION OUTPUT ;
    USE SIGNAL ;
    PORT
      LAYER M4 ;
        RECT  194.316 53.76 194.4 53.784 ;
    END
  END pi_line[115]
  PIN pi_line[116]
    DIRECTION OUTPUT ;
    USE SIGNAL ;
    PORT
      LAYER M4 ;
        RECT  194.316 53.856 194.4 53.88 ;
    END
  END pi_line[116]
  PIN pi_line[117]
    DIRECTION OUTPUT ;
    USE SIGNAL ;
    PORT
      LAYER M4 ;
        RECT  194.316 53.952 194.4 53.976 ;
    END
  END pi_line[117]
  PIN pi_line[118]
    DIRECTION OUTPUT ;
    USE SIGNAL ;
    PORT
      LAYER M4 ;
        RECT  194.316 54.048 194.4 54.072 ;
    END
  END pi_line[118]
  PIN pi_line[119]
    DIRECTION OUTPUT ;
    USE SIGNAL ;
    PORT
      LAYER M4 ;
        RECT  194.316 54.144 194.4 54.168 ;
    END
  END pi_line[119]
  PIN pi_line[11]
    DIRECTION OUTPUT ;
    USE SIGNAL ;
    PORT
      LAYER M4 ;
        RECT  194.316 43.776 194.4 43.8 ;
    END
  END pi_line[11]
  PIN pi_line[120]
    DIRECTION OUTPUT ;
    USE SIGNAL ;
    PORT
      LAYER M4 ;
        RECT  194.316 54.24 194.4 54.264 ;
    END
  END pi_line[120]
  PIN pi_line[121]
    DIRECTION OUTPUT ;
    USE SIGNAL ;
    PORT
      LAYER M4 ;
        RECT  194.316 54.336 194.4 54.36 ;
    END
  END pi_line[121]
  PIN pi_line[122]
    DIRECTION OUTPUT ;
    USE SIGNAL ;
    PORT
      LAYER M4 ;
        RECT  194.316 54.432 194.4 54.456 ;
    END
  END pi_line[122]
  PIN pi_line[123]
    DIRECTION OUTPUT ;
    USE SIGNAL ;
    PORT
      LAYER M4 ;
        RECT  194.316 54.528 194.4 54.552 ;
    END
  END pi_line[123]
  PIN pi_line[124]
    DIRECTION OUTPUT ;
    USE SIGNAL ;
    PORT
      LAYER M4 ;
        RECT  194.316 54.624 194.4 54.648 ;
    END
  END pi_line[124]
  PIN pi_line[125]
    DIRECTION OUTPUT ;
    USE SIGNAL ;
    PORT
      LAYER M4 ;
        RECT  194.316 54.72 194.4 54.744 ;
    END
  END pi_line[125]
  PIN pi_line[126]
    DIRECTION OUTPUT ;
    USE SIGNAL ;
    PORT
      LAYER M4 ;
        RECT  194.316 54.816 194.4 54.84 ;
    END
  END pi_line[126]
  PIN pi_line[127]
    DIRECTION OUTPUT ;
    USE SIGNAL ;
    PORT
      LAYER M4 ;
        RECT  194.316 54.912 194.4 54.936 ;
    END
  END pi_line[127]
  PIN pi_line[128]
    DIRECTION OUTPUT ;
    USE SIGNAL ;
    PORT
      LAYER M4 ;
        RECT  194.316 55.008 194.4 55.032 ;
    END
  END pi_line[128]
  PIN pi_line[129]
    DIRECTION OUTPUT ;
    USE SIGNAL ;
    PORT
      LAYER M4 ;
        RECT  194.316 55.104 194.4 55.128 ;
    END
  END pi_line[129]
  PIN pi_line[12]
    DIRECTION OUTPUT ;
    USE SIGNAL ;
    PORT
      LAYER M4 ;
        RECT  194.316 43.872 194.4 43.896 ;
    END
  END pi_line[12]
  PIN pi_line[130]
    DIRECTION OUTPUT ;
    USE SIGNAL ;
    PORT
      LAYER M4 ;
        RECT  194.316 55.2 194.4 55.224 ;
    END
  END pi_line[130]
  PIN pi_line[131]
    DIRECTION OUTPUT ;
    USE SIGNAL ;
    PORT
      LAYER M4 ;
        RECT  194.316 55.296 194.4 55.32 ;
    END
  END pi_line[131]
  PIN pi_line[132]
    DIRECTION OUTPUT ;
    USE SIGNAL ;
    PORT
      LAYER M4 ;
        RECT  194.316 55.392 194.4 55.416 ;
    END
  END pi_line[132]
  PIN pi_line[133]
    DIRECTION OUTPUT ;
    USE SIGNAL ;
    PORT
      LAYER M4 ;
        RECT  194.316 55.488 194.4 55.512 ;
    END
  END pi_line[133]
  PIN pi_line[134]
    DIRECTION OUTPUT ;
    USE SIGNAL ;
    PORT
      LAYER M4 ;
        RECT  194.316 55.584 194.4 55.608 ;
    END
  END pi_line[134]
  PIN pi_line[135]
    DIRECTION OUTPUT ;
    USE SIGNAL ;
    PORT
      LAYER M4 ;
        RECT  194.316 55.68 194.4 55.704 ;
    END
  END pi_line[135]
  PIN pi_line[136]
    DIRECTION OUTPUT ;
    USE SIGNAL ;
    PORT
      LAYER M4 ;
        RECT  194.316 55.776 194.4 55.8 ;
    END
  END pi_line[136]
  PIN pi_line[137]
    DIRECTION OUTPUT ;
    USE SIGNAL ;
    PORT
      LAYER M4 ;
        RECT  194.316 55.872 194.4 55.896 ;
    END
  END pi_line[137]
  PIN pi_line[138]
    DIRECTION OUTPUT ;
    USE SIGNAL ;
    PORT
      LAYER M4 ;
        RECT  194.316 55.968 194.4 55.992 ;
    END
  END pi_line[138]
  PIN pi_line[139]
    DIRECTION OUTPUT ;
    USE SIGNAL ;
    PORT
      LAYER M4 ;
        RECT  194.316 56.064 194.4 56.088 ;
    END
  END pi_line[139]
  PIN pi_line[13]
    DIRECTION OUTPUT ;
    USE SIGNAL ;
    PORT
      LAYER M4 ;
        RECT  194.316 43.968 194.4 43.992 ;
    END
  END pi_line[13]
  PIN pi_line[140]
    DIRECTION OUTPUT ;
    USE SIGNAL ;
    PORT
      LAYER M4 ;
        RECT  194.316 56.16 194.4 56.184 ;
    END
  END pi_line[140]
  PIN pi_line[141]
    DIRECTION OUTPUT ;
    USE SIGNAL ;
    PORT
      LAYER M4 ;
        RECT  194.316 56.256 194.4 56.28 ;
    END
  END pi_line[141]
  PIN pi_line[142]
    DIRECTION OUTPUT ;
    USE SIGNAL ;
    PORT
      LAYER M4 ;
        RECT  194.316 56.352 194.4 56.376 ;
    END
  END pi_line[142]
  PIN pi_line[143]
    DIRECTION OUTPUT ;
    USE SIGNAL ;
    PORT
      LAYER M4 ;
        RECT  194.316 56.448 194.4 56.472 ;
    END
  END pi_line[143]
  PIN pi_line[144]
    DIRECTION OUTPUT ;
    USE SIGNAL ;
    PORT
      LAYER M4 ;
        RECT  194.316 56.544 194.4 56.568 ;
    END
  END pi_line[144]
  PIN pi_line[145]
    DIRECTION OUTPUT ;
    USE SIGNAL ;
    PORT
      LAYER M4 ;
        RECT  194.316 56.64 194.4 56.664 ;
    END
  END pi_line[145]
  PIN pi_line[146]
    DIRECTION OUTPUT ;
    USE SIGNAL ;
    PORT
      LAYER M4 ;
        RECT  194.316 56.736 194.4 56.76 ;
    END
  END pi_line[146]
  PIN pi_line[147]
    DIRECTION OUTPUT ;
    USE SIGNAL ;
    PORT
      LAYER M4 ;
        RECT  194.316 56.832 194.4 56.856 ;
    END
  END pi_line[147]
  PIN pi_line[148]
    DIRECTION OUTPUT ;
    USE SIGNAL ;
    PORT
      LAYER M4 ;
        RECT  194.316 56.928 194.4 56.952 ;
    END
  END pi_line[148]
  PIN pi_line[149]
    DIRECTION OUTPUT ;
    USE SIGNAL ;
    PORT
      LAYER M4 ;
        RECT  194.316 57.024 194.4 57.048 ;
    END
  END pi_line[149]
  PIN pi_line[14]
    DIRECTION OUTPUT ;
    USE SIGNAL ;
    PORT
      LAYER M4 ;
        RECT  194.316 44.064 194.4 44.088 ;
    END
  END pi_line[14]
  PIN pi_line[150]
    DIRECTION OUTPUT ;
    USE SIGNAL ;
    PORT
      LAYER M4 ;
        RECT  194.316 57.12 194.4 57.144 ;
    END
  END pi_line[150]
  PIN pi_line[151]
    DIRECTION OUTPUT ;
    USE SIGNAL ;
    PORT
      LAYER M4 ;
        RECT  194.316 57.216 194.4 57.24 ;
    END
  END pi_line[151]
  PIN pi_line[152]
    DIRECTION OUTPUT ;
    USE SIGNAL ;
    PORT
      LAYER M4 ;
        RECT  194.316 57.312 194.4 57.336 ;
    END
  END pi_line[152]
  PIN pi_line[153]
    DIRECTION OUTPUT ;
    USE SIGNAL ;
    PORT
      LAYER M4 ;
        RECT  194.316 57.408 194.4 57.432 ;
    END
  END pi_line[153]
  PIN pi_line[154]
    DIRECTION OUTPUT ;
    USE SIGNAL ;
    PORT
      LAYER M4 ;
        RECT  194.316 57.504 194.4 57.528 ;
    END
  END pi_line[154]
  PIN pi_line[155]
    DIRECTION OUTPUT ;
    USE SIGNAL ;
    PORT
      LAYER M4 ;
        RECT  194.316 57.6 194.4 57.624 ;
    END
  END pi_line[155]
  PIN pi_line[156]
    DIRECTION OUTPUT ;
    USE SIGNAL ;
    PORT
      LAYER M4 ;
        RECT  194.316 57.696 194.4 57.72 ;
    END
  END pi_line[156]
  PIN pi_line[157]
    DIRECTION OUTPUT ;
    USE SIGNAL ;
    PORT
      LAYER M4 ;
        RECT  194.316 57.792 194.4 57.816 ;
    END
  END pi_line[157]
  PIN pi_line[158]
    DIRECTION OUTPUT ;
    USE SIGNAL ;
    PORT
      LAYER M4 ;
        RECT  194.316 57.888 194.4 57.912 ;
    END
  END pi_line[158]
  PIN pi_line[159]
    DIRECTION OUTPUT ;
    USE SIGNAL ;
    PORT
      LAYER M4 ;
        RECT  194.316 57.984 194.4 58.008 ;
    END
  END pi_line[159]
  PIN pi_line[15]
    DIRECTION OUTPUT ;
    USE SIGNAL ;
    PORT
      LAYER M4 ;
        RECT  194.316 44.16 194.4 44.184 ;
    END
  END pi_line[15]
  PIN pi_line[160]
    DIRECTION OUTPUT ;
    USE SIGNAL ;
    PORT
      LAYER M4 ;
        RECT  194.316 58.08 194.4 58.104 ;
    END
  END pi_line[160]
  PIN pi_line[161]
    DIRECTION OUTPUT ;
    USE SIGNAL ;
    PORT
      LAYER M4 ;
        RECT  194.316 58.176 194.4 58.2 ;
    END
  END pi_line[161]
  PIN pi_line[162]
    DIRECTION OUTPUT ;
    USE SIGNAL ;
    PORT
      LAYER M4 ;
        RECT  194.316 58.272 194.4 58.296 ;
    END
  END pi_line[162]
  PIN pi_line[163]
    DIRECTION OUTPUT ;
    USE SIGNAL ;
    PORT
      LAYER M4 ;
        RECT  194.316 58.368 194.4 58.392 ;
    END
  END pi_line[163]
  PIN pi_line[164]
    DIRECTION OUTPUT ;
    USE SIGNAL ;
    PORT
      LAYER M4 ;
        RECT  194.316 58.464 194.4 58.488 ;
    END
  END pi_line[164]
  PIN pi_line[165]
    DIRECTION OUTPUT ;
    USE SIGNAL ;
    PORT
      LAYER M4 ;
        RECT  194.316 58.56 194.4 58.584 ;
    END
  END pi_line[165]
  PIN pi_line[166]
    DIRECTION OUTPUT ;
    USE SIGNAL ;
    PORT
      LAYER M4 ;
        RECT  194.316 58.656 194.4 58.68 ;
    END
  END pi_line[166]
  PIN pi_line[167]
    DIRECTION OUTPUT ;
    USE SIGNAL ;
    PORT
      LAYER M4 ;
        RECT  194.316 58.752 194.4 58.776 ;
    END
  END pi_line[167]
  PIN pi_line[168]
    DIRECTION OUTPUT ;
    USE SIGNAL ;
    PORT
      LAYER M4 ;
        RECT  194.316 58.848 194.4 58.872 ;
    END
  END pi_line[168]
  PIN pi_line[169]
    DIRECTION OUTPUT ;
    USE SIGNAL ;
    PORT
      LAYER M4 ;
        RECT  194.316 58.944 194.4 58.968 ;
    END
  END pi_line[169]
  PIN pi_line[16]
    DIRECTION OUTPUT ;
    USE SIGNAL ;
    PORT
      LAYER M4 ;
        RECT  194.316 44.256 194.4 44.28 ;
    END
  END pi_line[16]
  PIN pi_line[170]
    DIRECTION OUTPUT ;
    USE SIGNAL ;
    PORT
      LAYER M4 ;
        RECT  194.316 59.04 194.4 59.064 ;
    END
  END pi_line[170]
  PIN pi_line[171]
    DIRECTION OUTPUT ;
    USE SIGNAL ;
    PORT
      LAYER M4 ;
        RECT  194.316 59.136 194.4 59.16 ;
    END
  END pi_line[171]
  PIN pi_line[172]
    DIRECTION OUTPUT ;
    USE SIGNAL ;
    PORT
      LAYER M4 ;
        RECT  194.316 59.232 194.4 59.256 ;
    END
  END pi_line[172]
  PIN pi_line[173]
    DIRECTION OUTPUT ;
    USE SIGNAL ;
    PORT
      LAYER M4 ;
        RECT  194.316 59.328 194.4 59.352 ;
    END
  END pi_line[173]
  PIN pi_line[174]
    DIRECTION OUTPUT ;
    USE SIGNAL ;
    PORT
      LAYER M4 ;
        RECT  194.316 59.424 194.4 59.448 ;
    END
  END pi_line[174]
  PIN pi_line[175]
    DIRECTION OUTPUT ;
    USE SIGNAL ;
    PORT
      LAYER M4 ;
        RECT  194.316 59.52 194.4 59.544 ;
    END
  END pi_line[175]
  PIN pi_line[176]
    DIRECTION OUTPUT ;
    USE SIGNAL ;
    PORT
      LAYER M4 ;
        RECT  194.316 59.616 194.4 59.64 ;
    END
  END pi_line[176]
  PIN pi_line[177]
    DIRECTION OUTPUT ;
    USE SIGNAL ;
    PORT
      LAYER M4 ;
        RECT  194.316 59.712 194.4 59.736 ;
    END
  END pi_line[177]
  PIN pi_line[178]
    DIRECTION OUTPUT ;
    USE SIGNAL ;
    PORT
      LAYER M4 ;
        RECT  194.316 59.808 194.4 59.832 ;
    END
  END pi_line[178]
  PIN pi_line[179]
    DIRECTION OUTPUT ;
    USE SIGNAL ;
    PORT
      LAYER M4 ;
        RECT  194.316 59.904 194.4 59.928 ;
    END
  END pi_line[179]
  PIN pi_line[17]
    DIRECTION OUTPUT ;
    USE SIGNAL ;
    PORT
      LAYER M4 ;
        RECT  194.316 44.352 194.4 44.376 ;
    END
  END pi_line[17]
  PIN pi_line[180]
    DIRECTION OUTPUT ;
    USE SIGNAL ;
    PORT
      LAYER M4 ;
        RECT  194.316 60 194.4 60.024 ;
    END
  END pi_line[180]
  PIN pi_line[181]
    DIRECTION OUTPUT ;
    USE SIGNAL ;
    PORT
      LAYER M4 ;
        RECT  194.316 60.096 194.4 60.12 ;
    END
  END pi_line[181]
  PIN pi_line[182]
    DIRECTION OUTPUT ;
    USE SIGNAL ;
    PORT
      LAYER M4 ;
        RECT  194.316 60.192 194.4 60.216 ;
    END
  END pi_line[182]
  PIN pi_line[183]
    DIRECTION OUTPUT ;
    USE SIGNAL ;
    PORT
      LAYER M4 ;
        RECT  194.316 60.288 194.4 60.312 ;
    END
  END pi_line[183]
  PIN pi_line[184]
    DIRECTION OUTPUT ;
    USE SIGNAL ;
    PORT
      LAYER M4 ;
        RECT  194.316 60.384 194.4 60.408 ;
    END
  END pi_line[184]
  PIN pi_line[185]
    DIRECTION OUTPUT ;
    USE SIGNAL ;
    PORT
      LAYER M4 ;
        RECT  194.316 60.48 194.4 60.504 ;
    END
  END pi_line[185]
  PIN pi_line[186]
    DIRECTION OUTPUT ;
    USE SIGNAL ;
    PORT
      LAYER M4 ;
        RECT  194.316 60.576 194.4 60.6 ;
    END
  END pi_line[186]
  PIN pi_line[187]
    DIRECTION OUTPUT ;
    USE SIGNAL ;
    PORT
      LAYER M4 ;
        RECT  194.316 60.672 194.4 60.696 ;
    END
  END pi_line[187]
  PIN pi_line[188]
    DIRECTION OUTPUT ;
    USE SIGNAL ;
    PORT
      LAYER M4 ;
        RECT  194.316 60.768 194.4 60.792 ;
    END
  END pi_line[188]
  PIN pi_line[189]
    DIRECTION OUTPUT ;
    USE SIGNAL ;
    PORT
      LAYER M4 ;
        RECT  194.316 60.864 194.4 60.888 ;
    END
  END pi_line[189]
  PIN pi_line[18]
    DIRECTION OUTPUT ;
    USE SIGNAL ;
    PORT
      LAYER M4 ;
        RECT  194.316 44.448 194.4 44.472 ;
    END
  END pi_line[18]
  PIN pi_line[190]
    DIRECTION OUTPUT ;
    USE SIGNAL ;
    PORT
      LAYER M4 ;
        RECT  194.316 60.96 194.4 60.984 ;
    END
  END pi_line[190]
  PIN pi_line[191]
    DIRECTION OUTPUT ;
    USE SIGNAL ;
    PORT
      LAYER M4 ;
        RECT  194.316 61.056 194.4 61.08 ;
    END
  END pi_line[191]
  PIN pi_line[192]
    DIRECTION OUTPUT ;
    USE SIGNAL ;
    PORT
      LAYER M4 ;
        RECT  194.316 61.152 194.4 61.176 ;
    END
  END pi_line[192]
  PIN pi_line[193]
    DIRECTION OUTPUT ;
    USE SIGNAL ;
    PORT
      LAYER M4 ;
        RECT  194.316 61.248 194.4 61.272 ;
    END
  END pi_line[193]
  PIN pi_line[194]
    DIRECTION OUTPUT ;
    USE SIGNAL ;
    PORT
      LAYER M4 ;
        RECT  194.316 61.344 194.4 61.368 ;
    END
  END pi_line[194]
  PIN pi_line[195]
    DIRECTION OUTPUT ;
    USE SIGNAL ;
    PORT
      LAYER M4 ;
        RECT  194.316 61.44 194.4 61.464 ;
    END
  END pi_line[195]
  PIN pi_line[196]
    DIRECTION OUTPUT ;
    USE SIGNAL ;
    PORT
      LAYER M4 ;
        RECT  194.316 61.536 194.4 61.56 ;
    END
  END pi_line[196]
  PIN pi_line[197]
    DIRECTION OUTPUT ;
    USE SIGNAL ;
    PORT
      LAYER M4 ;
        RECT  194.316 61.632 194.4 61.656 ;
    END
  END pi_line[197]
  PIN pi_line[198]
    DIRECTION OUTPUT ;
    USE SIGNAL ;
    PORT
      LAYER M4 ;
        RECT  194.316 61.728 194.4 61.752 ;
    END
  END pi_line[198]
  PIN pi_line[199]
    DIRECTION OUTPUT ;
    USE SIGNAL ;
    PORT
      LAYER M4 ;
        RECT  194.316 61.824 194.4 61.848 ;
    END
  END pi_line[199]
  PIN pi_line[19]
    DIRECTION OUTPUT ;
    USE SIGNAL ;
    PORT
      LAYER M4 ;
        RECT  194.316 44.544 194.4 44.568 ;
    END
  END pi_line[19]
  PIN pi_line[1]
    DIRECTION OUTPUT ;
    USE SIGNAL ;
    PORT
      LAYER M4 ;
        RECT  194.316 42.816 194.4 42.84 ;
    END
  END pi_line[1]
  PIN pi_line[200]
    DIRECTION OUTPUT ;
    USE SIGNAL ;
    PORT
      LAYER M4 ;
        RECT  194.316 61.92 194.4 61.944 ;
    END
  END pi_line[200]
  PIN pi_line[201]
    DIRECTION OUTPUT ;
    USE SIGNAL ;
    PORT
      LAYER M4 ;
        RECT  194.316 62.016 194.4 62.04 ;
    END
  END pi_line[201]
  PIN pi_line[202]
    DIRECTION OUTPUT ;
    USE SIGNAL ;
    PORT
      LAYER M4 ;
        RECT  194.316 62.112 194.4 62.136 ;
    END
  END pi_line[202]
  PIN pi_line[203]
    DIRECTION OUTPUT ;
    USE SIGNAL ;
    PORT
      LAYER M4 ;
        RECT  194.316 62.208 194.4 62.232 ;
    END
  END pi_line[203]
  PIN pi_line[204]
    DIRECTION OUTPUT ;
    USE SIGNAL ;
    PORT
      LAYER M4 ;
        RECT  194.316 62.304 194.4 62.328 ;
    END
  END pi_line[204]
  PIN pi_line[205]
    DIRECTION OUTPUT ;
    USE SIGNAL ;
    PORT
      LAYER M4 ;
        RECT  194.316 62.4 194.4 62.424 ;
    END
  END pi_line[205]
  PIN pi_line[206]
    DIRECTION OUTPUT ;
    USE SIGNAL ;
    PORT
      LAYER M4 ;
        RECT  194.316 62.496 194.4 62.52 ;
    END
  END pi_line[206]
  PIN pi_line[207]
    DIRECTION OUTPUT ;
    USE SIGNAL ;
    PORT
      LAYER M4 ;
        RECT  194.316 62.592 194.4 62.616 ;
    END
  END pi_line[207]
  PIN pi_line[208]
    DIRECTION OUTPUT ;
    USE SIGNAL ;
    PORT
      LAYER M4 ;
        RECT  194.316 62.688 194.4 62.712 ;
    END
  END pi_line[208]
  PIN pi_line[209]
    DIRECTION OUTPUT ;
    USE SIGNAL ;
    PORT
      LAYER M4 ;
        RECT  194.316 62.784 194.4 62.808 ;
    END
  END pi_line[209]
  PIN pi_line[20]
    DIRECTION OUTPUT ;
    USE SIGNAL ;
    PORT
      LAYER M4 ;
        RECT  194.316 44.64 194.4 44.664 ;
    END
  END pi_line[20]
  PIN pi_line[210]
    DIRECTION OUTPUT ;
    USE SIGNAL ;
    PORT
      LAYER M4 ;
        RECT  194.316 62.88 194.4 62.904 ;
    END
  END pi_line[210]
  PIN pi_line[211]
    DIRECTION OUTPUT ;
    USE SIGNAL ;
    PORT
      LAYER M4 ;
        RECT  194.316 62.976 194.4 63 ;
    END
  END pi_line[211]
  PIN pi_line[212]
    DIRECTION OUTPUT ;
    USE SIGNAL ;
    PORT
      LAYER M4 ;
        RECT  194.316 63.072 194.4 63.096 ;
    END
  END pi_line[212]
  PIN pi_line[213]
    DIRECTION OUTPUT ;
    USE SIGNAL ;
    PORT
      LAYER M4 ;
        RECT  194.316 63.168 194.4 63.192 ;
    END
  END pi_line[213]
  PIN pi_line[214]
    DIRECTION OUTPUT ;
    USE SIGNAL ;
    PORT
      LAYER M4 ;
        RECT  194.316 63.264 194.4 63.288 ;
    END
  END pi_line[214]
  PIN pi_line[215]
    DIRECTION OUTPUT ;
    USE SIGNAL ;
    PORT
      LAYER M4 ;
        RECT  194.316 63.36 194.4 63.384 ;
    END
  END pi_line[215]
  PIN pi_line[216]
    DIRECTION OUTPUT ;
    USE SIGNAL ;
    PORT
      LAYER M4 ;
        RECT  194.316 63.456 194.4 63.48 ;
    END
  END pi_line[216]
  PIN pi_line[217]
    DIRECTION OUTPUT ;
    USE SIGNAL ;
    PORT
      LAYER M4 ;
        RECT  194.316 63.552 194.4 63.576 ;
    END
  END pi_line[217]
  PIN pi_line[218]
    DIRECTION OUTPUT ;
    USE SIGNAL ;
    PORT
      LAYER M4 ;
        RECT  194.316 63.648 194.4 63.672 ;
    END
  END pi_line[218]
  PIN pi_line[219]
    DIRECTION OUTPUT ;
    USE SIGNAL ;
    PORT
      LAYER M4 ;
        RECT  194.316 63.744 194.4 63.768 ;
    END
  END pi_line[219]
  PIN pi_line[21]
    DIRECTION OUTPUT ;
    USE SIGNAL ;
    PORT
      LAYER M4 ;
        RECT  194.316 44.736 194.4 44.76 ;
    END
  END pi_line[21]
  PIN pi_line[220]
    DIRECTION OUTPUT ;
    USE SIGNAL ;
    PORT
      LAYER M4 ;
        RECT  194.316 63.84 194.4 63.864 ;
    END
  END pi_line[220]
  PIN pi_line[221]
    DIRECTION OUTPUT ;
    USE SIGNAL ;
    PORT
      LAYER M4 ;
        RECT  194.316 63.936 194.4 63.96 ;
    END
  END pi_line[221]
  PIN pi_line[222]
    DIRECTION OUTPUT ;
    USE SIGNAL ;
    PORT
      LAYER M4 ;
        RECT  194.316 64.032 194.4 64.056 ;
    END
  END pi_line[222]
  PIN pi_line[223]
    DIRECTION OUTPUT ;
    USE SIGNAL ;
    PORT
      LAYER M4 ;
        RECT  194.316 64.128 194.4 64.152 ;
    END
  END pi_line[223]
  PIN pi_line[224]
    DIRECTION OUTPUT ;
    USE SIGNAL ;
    PORT
      LAYER M4 ;
        RECT  194.316 64.224 194.4 64.248 ;
    END
  END pi_line[224]
  PIN pi_line[225]
    DIRECTION OUTPUT ;
    USE SIGNAL ;
    PORT
      LAYER M4 ;
        RECT  194.316 64.32 194.4 64.344 ;
    END
  END pi_line[225]
  PIN pi_line[226]
    DIRECTION OUTPUT ;
    USE SIGNAL ;
    PORT
      LAYER M4 ;
        RECT  194.316 64.416 194.4 64.44 ;
    END
  END pi_line[226]
  PIN pi_line[227]
    DIRECTION OUTPUT ;
    USE SIGNAL ;
    PORT
      LAYER M4 ;
        RECT  194.316 64.512 194.4 64.536 ;
    END
  END pi_line[227]
  PIN pi_line[228]
    DIRECTION OUTPUT ;
    USE SIGNAL ;
    PORT
      LAYER M4 ;
        RECT  194.316 64.608 194.4 64.632 ;
    END
  END pi_line[228]
  PIN pi_line[229]
    DIRECTION OUTPUT ;
    USE SIGNAL ;
    PORT
      LAYER M4 ;
        RECT  194.316 64.704 194.4 64.728 ;
    END
  END pi_line[229]
  PIN pi_line[22]
    DIRECTION OUTPUT ;
    USE SIGNAL ;
    PORT
      LAYER M4 ;
        RECT  194.316 44.832 194.4 44.856 ;
    END
  END pi_line[22]
  PIN pi_line[230]
    DIRECTION OUTPUT ;
    USE SIGNAL ;
    PORT
      LAYER M4 ;
        RECT  194.316 64.8 194.4 64.824 ;
    END
  END pi_line[230]
  PIN pi_line[231]
    DIRECTION OUTPUT ;
    USE SIGNAL ;
    PORT
      LAYER M4 ;
        RECT  194.316 64.896 194.4 64.92 ;
    END
  END pi_line[231]
  PIN pi_line[232]
    DIRECTION OUTPUT ;
    USE SIGNAL ;
    PORT
      LAYER M4 ;
        RECT  194.316 64.992 194.4 65.016 ;
    END
  END pi_line[232]
  PIN pi_line[233]
    DIRECTION OUTPUT ;
    USE SIGNAL ;
    PORT
      LAYER M4 ;
        RECT  194.316 65.088 194.4 65.112 ;
    END
  END pi_line[233]
  PIN pi_line[234]
    DIRECTION OUTPUT ;
    USE SIGNAL ;
    PORT
      LAYER M4 ;
        RECT  194.316 65.184 194.4 65.208 ;
    END
  END pi_line[234]
  PIN pi_line[235]
    DIRECTION OUTPUT ;
    USE SIGNAL ;
    PORT
      LAYER M4 ;
        RECT  194.316 65.28 194.4 65.304 ;
    END
  END pi_line[235]
  PIN pi_line[236]
    DIRECTION OUTPUT ;
    USE SIGNAL ;
    PORT
      LAYER M4 ;
        RECT  194.316 65.376 194.4 65.4 ;
    END
  END pi_line[236]
  PIN pi_line[237]
    DIRECTION OUTPUT ;
    USE SIGNAL ;
    PORT
      LAYER M4 ;
        RECT  194.316 65.472 194.4 65.496 ;
    END
  END pi_line[237]
  PIN pi_line[238]
    DIRECTION OUTPUT ;
    USE SIGNAL ;
    PORT
      LAYER M4 ;
        RECT  194.316 65.568 194.4 65.592 ;
    END
  END pi_line[238]
  PIN pi_line[239]
    DIRECTION OUTPUT ;
    USE SIGNAL ;
    PORT
      LAYER M4 ;
        RECT  194.316 65.664 194.4 65.688 ;
    END
  END pi_line[239]
  PIN pi_line[23]
    DIRECTION OUTPUT ;
    USE SIGNAL ;
    PORT
      LAYER M4 ;
        RECT  194.316 44.928 194.4 44.952 ;
    END
  END pi_line[23]
  PIN pi_line[240]
    DIRECTION OUTPUT ;
    USE SIGNAL ;
    PORT
      LAYER M4 ;
        RECT  194.316 65.76 194.4 65.784 ;
    END
  END pi_line[240]
  PIN pi_line[241]
    DIRECTION OUTPUT ;
    USE SIGNAL ;
    PORT
      LAYER M4 ;
        RECT  194.316 65.856 194.4 65.88 ;
    END
  END pi_line[241]
  PIN pi_line[242]
    DIRECTION OUTPUT ;
    USE SIGNAL ;
    PORT
      LAYER M4 ;
        RECT  194.316 65.952 194.4 65.976 ;
    END
  END pi_line[242]
  PIN pi_line[243]
    DIRECTION OUTPUT ;
    USE SIGNAL ;
    PORT
      LAYER M4 ;
        RECT  194.316 66.048 194.4 66.072 ;
    END
  END pi_line[243]
  PIN pi_line[244]
    DIRECTION OUTPUT ;
    USE SIGNAL ;
    PORT
      LAYER M4 ;
        RECT  194.316 66.144 194.4 66.168 ;
    END
  END pi_line[244]
  PIN pi_line[245]
    DIRECTION OUTPUT ;
    USE SIGNAL ;
    PORT
      LAYER M4 ;
        RECT  194.316 66.24 194.4 66.264 ;
    END
  END pi_line[245]
  PIN pi_line[246]
    DIRECTION OUTPUT ;
    USE SIGNAL ;
    PORT
      LAYER M4 ;
        RECT  194.316 66.336 194.4 66.36 ;
    END
  END pi_line[246]
  PIN pi_line[247]
    DIRECTION OUTPUT ;
    USE SIGNAL ;
    PORT
      LAYER M4 ;
        RECT  194.316 66.432 194.4 66.456 ;
    END
  END pi_line[247]
  PIN pi_line[248]
    DIRECTION OUTPUT ;
    USE SIGNAL ;
    PORT
      LAYER M4 ;
        RECT  194.316 66.528 194.4 66.552 ;
    END
  END pi_line[248]
  PIN pi_line[249]
    DIRECTION OUTPUT ;
    USE SIGNAL ;
    PORT
      LAYER M4 ;
        RECT  194.316 66.624 194.4 66.648 ;
    END
  END pi_line[249]
  PIN pi_line[24]
    DIRECTION OUTPUT ;
    USE SIGNAL ;
    PORT
      LAYER M4 ;
        RECT  194.316 45.024 194.4 45.048 ;
    END
  END pi_line[24]
  PIN pi_line[250]
    DIRECTION OUTPUT ;
    USE SIGNAL ;
    PORT
      LAYER M4 ;
        RECT  194.316 66.72 194.4 66.744 ;
    END
  END pi_line[250]
  PIN pi_line[251]
    DIRECTION OUTPUT ;
    USE SIGNAL ;
    PORT
      LAYER M4 ;
        RECT  194.316 66.816 194.4 66.84 ;
    END
  END pi_line[251]
  PIN pi_line[252]
    DIRECTION OUTPUT ;
    USE SIGNAL ;
    PORT
      LAYER M4 ;
        RECT  194.316 66.912 194.4 66.936 ;
    END
  END pi_line[252]
  PIN pi_line[253]
    DIRECTION OUTPUT ;
    USE SIGNAL ;
    PORT
      LAYER M4 ;
        RECT  194.316 67.008 194.4 67.032 ;
    END
  END pi_line[253]
  PIN pi_line[254]
    DIRECTION OUTPUT ;
    USE SIGNAL ;
    PORT
      LAYER M4 ;
        RECT  194.316 67.104 194.4 67.128 ;
    END
  END pi_line[254]
  PIN pi_line[255]
    DIRECTION OUTPUT ;
    USE SIGNAL ;
    PORT
      LAYER M4 ;
        RECT  194.316 67.2 194.4 67.224 ;
    END
  END pi_line[255]
  PIN pi_line[256]
    DIRECTION OUTPUT ;
    USE SIGNAL ;
    PORT
      LAYER M4 ;
        RECT  194.316 67.296 194.4 67.32 ;
    END
  END pi_line[256]
  PIN pi_line[257]
    DIRECTION OUTPUT ;
    USE SIGNAL ;
    PORT
      LAYER M4 ;
        RECT  194.316 67.392 194.4 67.416 ;
    END
  END pi_line[257]
  PIN pi_line[258]
    DIRECTION OUTPUT ;
    USE SIGNAL ;
    PORT
      LAYER M4 ;
        RECT  194.316 67.488 194.4 67.512 ;
    END
  END pi_line[258]
  PIN pi_line[259]
    DIRECTION OUTPUT ;
    USE SIGNAL ;
    PORT
      LAYER M4 ;
        RECT  194.316 67.584 194.4 67.608 ;
    END
  END pi_line[259]
  PIN pi_line[25]
    DIRECTION OUTPUT ;
    USE SIGNAL ;
    PORT
      LAYER M4 ;
        RECT  194.316 45.12 194.4 45.144 ;
    END
  END pi_line[25]
  PIN pi_line[260]
    DIRECTION OUTPUT ;
    USE SIGNAL ;
    PORT
      LAYER M4 ;
        RECT  194.316 67.68 194.4 67.704 ;
    END
  END pi_line[260]
  PIN pi_line[261]
    DIRECTION OUTPUT ;
    USE SIGNAL ;
    PORT
      LAYER M4 ;
        RECT  194.316 67.776 194.4 67.8 ;
    END
  END pi_line[261]
  PIN pi_line[262]
    DIRECTION OUTPUT ;
    USE SIGNAL ;
    PORT
      LAYER M4 ;
        RECT  194.316 67.872 194.4 67.896 ;
    END
  END pi_line[262]
  PIN pi_line[263]
    DIRECTION OUTPUT ;
    USE SIGNAL ;
    PORT
      LAYER M4 ;
        RECT  194.316 67.968 194.4 67.992 ;
    END
  END pi_line[263]
  PIN pi_line[264]
    DIRECTION OUTPUT ;
    USE SIGNAL ;
    PORT
      LAYER M4 ;
        RECT  194.316 68.064 194.4 68.088 ;
    END
  END pi_line[264]
  PIN pi_line[265]
    DIRECTION OUTPUT ;
    USE SIGNAL ;
    PORT
      LAYER M4 ;
        RECT  194.316 68.16 194.4 68.184 ;
    END
  END pi_line[265]
  PIN pi_line[266]
    DIRECTION OUTPUT ;
    USE SIGNAL ;
    PORT
      LAYER M4 ;
        RECT  194.316 68.256 194.4 68.28 ;
    END
  END pi_line[266]
  PIN pi_line[267]
    DIRECTION OUTPUT ;
    USE SIGNAL ;
    PORT
      LAYER M4 ;
        RECT  194.316 68.352 194.4 68.376 ;
    END
  END pi_line[267]
  PIN pi_line[268]
    DIRECTION OUTPUT ;
    USE SIGNAL ;
    PORT
      LAYER M4 ;
        RECT  194.316 68.448 194.4 68.472 ;
    END
  END pi_line[268]
  PIN pi_line[269]
    DIRECTION OUTPUT ;
    USE SIGNAL ;
    PORT
      LAYER M4 ;
        RECT  194.316 68.544 194.4 68.568 ;
    END
  END pi_line[269]
  PIN pi_line[26]
    DIRECTION OUTPUT ;
    USE SIGNAL ;
    PORT
      LAYER M4 ;
        RECT  194.316 45.216 194.4 45.24 ;
    END
  END pi_line[26]
  PIN pi_line[270]
    DIRECTION OUTPUT ;
    USE SIGNAL ;
    PORT
      LAYER M4 ;
        RECT  194.316 68.64 194.4 68.664 ;
    END
  END pi_line[270]
  PIN pi_line[271]
    DIRECTION OUTPUT ;
    USE SIGNAL ;
    PORT
      LAYER M4 ;
        RECT  194.316 68.736 194.4 68.76 ;
    END
  END pi_line[271]
  PIN pi_line[272]
    DIRECTION OUTPUT ;
    USE SIGNAL ;
    PORT
      LAYER M4 ;
        RECT  194.316 68.832 194.4 68.856 ;
    END
  END pi_line[272]
  PIN pi_line[273]
    DIRECTION OUTPUT ;
    USE SIGNAL ;
    PORT
      LAYER M4 ;
        RECT  194.316 68.928 194.4 68.952 ;
    END
  END pi_line[273]
  PIN pi_line[274]
    DIRECTION OUTPUT ;
    USE SIGNAL ;
    PORT
      LAYER M4 ;
        RECT  194.316 69.024 194.4 69.048 ;
    END
  END pi_line[274]
  PIN pi_line[275]
    DIRECTION OUTPUT ;
    USE SIGNAL ;
    PORT
      LAYER M4 ;
        RECT  194.316 69.12 194.4 69.144 ;
    END
  END pi_line[275]
  PIN pi_line[276]
    DIRECTION OUTPUT ;
    USE SIGNAL ;
    PORT
      LAYER M4 ;
        RECT  194.316 69.216 194.4 69.24 ;
    END
  END pi_line[276]
  PIN pi_line[277]
    DIRECTION OUTPUT ;
    USE SIGNAL ;
    PORT
      LAYER M4 ;
        RECT  194.316 69.312 194.4 69.336 ;
    END
  END pi_line[277]
  PIN pi_line[278]
    DIRECTION OUTPUT ;
    USE SIGNAL ;
    PORT
      LAYER M4 ;
        RECT  194.316 69.408 194.4 69.432 ;
    END
  END pi_line[278]
  PIN pi_line[279]
    DIRECTION OUTPUT ;
    USE SIGNAL ;
    PORT
      LAYER M4 ;
        RECT  194.316 69.504 194.4 69.528 ;
    END
  END pi_line[279]
  PIN pi_line[27]
    DIRECTION OUTPUT ;
    USE SIGNAL ;
    PORT
      LAYER M4 ;
        RECT  194.316 45.312 194.4 45.336 ;
    END
  END pi_line[27]
  PIN pi_line[280]
    DIRECTION OUTPUT ;
    USE SIGNAL ;
    PORT
      LAYER M4 ;
        RECT  194.316 69.6 194.4 69.624 ;
    END
  END pi_line[280]
  PIN pi_line[281]
    DIRECTION OUTPUT ;
    USE SIGNAL ;
    PORT
      LAYER M4 ;
        RECT  194.316 69.696 194.4 69.72 ;
    END
  END pi_line[281]
  PIN pi_line[282]
    DIRECTION OUTPUT ;
    USE SIGNAL ;
    PORT
      LAYER M4 ;
        RECT  194.316 69.792 194.4 69.816 ;
    END
  END pi_line[282]
  PIN pi_line[283]
    DIRECTION OUTPUT ;
    USE SIGNAL ;
    PORT
      LAYER M4 ;
        RECT  194.316 69.888 194.4 69.912 ;
    END
  END pi_line[283]
  PIN pi_line[284]
    DIRECTION OUTPUT ;
    USE SIGNAL ;
    PORT
      LAYER M4 ;
        RECT  194.316 69.984 194.4 70.008 ;
    END
  END pi_line[284]
  PIN pi_line[285]
    DIRECTION OUTPUT ;
    USE SIGNAL ;
    PORT
      LAYER M4 ;
        RECT  194.316 70.08 194.4 70.104 ;
    END
  END pi_line[285]
  PIN pi_line[286]
    DIRECTION OUTPUT ;
    USE SIGNAL ;
    PORT
      LAYER M4 ;
        RECT  194.316 70.176 194.4 70.2 ;
    END
  END pi_line[286]
  PIN pi_line[287]
    DIRECTION OUTPUT ;
    USE SIGNAL ;
    PORT
      LAYER M4 ;
        RECT  194.316 70.272 194.4 70.296 ;
    END
  END pi_line[287]
  PIN pi_line[288]
    DIRECTION OUTPUT ;
    USE SIGNAL ;
    PORT
      LAYER M4 ;
        RECT  194.316 70.368 194.4 70.392 ;
    END
  END pi_line[288]
  PIN pi_line[289]
    DIRECTION OUTPUT ;
    USE SIGNAL ;
    PORT
      LAYER M4 ;
        RECT  194.316 70.464 194.4 70.488 ;
    END
  END pi_line[289]
  PIN pi_line[28]
    DIRECTION OUTPUT ;
    USE SIGNAL ;
    PORT
      LAYER M4 ;
        RECT  194.316 45.408 194.4 45.432 ;
    END
  END pi_line[28]
  PIN pi_line[290]
    DIRECTION OUTPUT ;
    USE SIGNAL ;
    PORT
      LAYER M4 ;
        RECT  194.316 70.56 194.4 70.584 ;
    END
  END pi_line[290]
  PIN pi_line[291]
    DIRECTION OUTPUT ;
    USE SIGNAL ;
    PORT
      LAYER M4 ;
        RECT  194.316 70.656 194.4 70.68 ;
    END
  END pi_line[291]
  PIN pi_line[292]
    DIRECTION OUTPUT ;
    USE SIGNAL ;
    PORT
      LAYER M4 ;
        RECT  194.316 70.752 194.4 70.776 ;
    END
  END pi_line[292]
  PIN pi_line[293]
    DIRECTION OUTPUT ;
    USE SIGNAL ;
    PORT
      LAYER M4 ;
        RECT  194.316 70.848 194.4 70.872 ;
    END
  END pi_line[293]
  PIN pi_line[294]
    DIRECTION OUTPUT ;
    USE SIGNAL ;
    PORT
      LAYER M4 ;
        RECT  194.316 70.944 194.4 70.968 ;
    END
  END pi_line[294]
  PIN pi_line[295]
    DIRECTION OUTPUT ;
    USE SIGNAL ;
    PORT
      LAYER M4 ;
        RECT  194.316 71.04 194.4 71.064 ;
    END
  END pi_line[295]
  PIN pi_line[296]
    DIRECTION OUTPUT ;
    USE SIGNAL ;
    PORT
      LAYER M4 ;
        RECT  194.316 71.136 194.4 71.16 ;
    END
  END pi_line[296]
  PIN pi_line[297]
    DIRECTION OUTPUT ;
    USE SIGNAL ;
    PORT
      LAYER M4 ;
        RECT  194.316 71.232 194.4 71.256 ;
    END
  END pi_line[297]
  PIN pi_line[298]
    DIRECTION OUTPUT ;
    USE SIGNAL ;
    PORT
      LAYER M4 ;
        RECT  194.316 71.328 194.4 71.352 ;
    END
  END pi_line[298]
  PIN pi_line[299]
    DIRECTION OUTPUT ;
    USE SIGNAL ;
    PORT
      LAYER M4 ;
        RECT  194.316 71.424 194.4 71.448 ;
    END
  END pi_line[299]
  PIN pi_line[29]
    DIRECTION OUTPUT ;
    USE SIGNAL ;
    PORT
      LAYER M4 ;
        RECT  194.316 45.504 194.4 45.528 ;
    END
  END pi_line[29]
  PIN pi_line[2]
    DIRECTION OUTPUT ;
    USE SIGNAL ;
    PORT
      LAYER M4 ;
        RECT  194.316 42.912 194.4 42.936 ;
    END
  END pi_line[2]
  PIN pi_line[300]
    DIRECTION OUTPUT ;
    USE SIGNAL ;
    PORT
      LAYER M4 ;
        RECT  194.316 71.52 194.4 71.544 ;
    END
  END pi_line[300]
  PIN pi_line[301]
    DIRECTION OUTPUT ;
    USE SIGNAL ;
    PORT
      LAYER M4 ;
        RECT  194.316 71.616 194.4 71.64 ;
    END
  END pi_line[301]
  PIN pi_line[302]
    DIRECTION OUTPUT ;
    USE SIGNAL ;
    PORT
      LAYER M4 ;
        RECT  194.316 71.712 194.4 71.736 ;
    END
  END pi_line[302]
  PIN pi_line[303]
    DIRECTION OUTPUT ;
    USE SIGNAL ;
    PORT
      LAYER M4 ;
        RECT  194.316 71.808 194.4 71.832 ;
    END
  END pi_line[303]
  PIN pi_line[304]
    DIRECTION OUTPUT ;
    USE SIGNAL ;
    PORT
      LAYER M4 ;
        RECT  194.316 71.904 194.4 71.928 ;
    END
  END pi_line[304]
  PIN pi_line[305]
    DIRECTION OUTPUT ;
    USE SIGNAL ;
    PORT
      LAYER M4 ;
        RECT  194.316 72 194.4 72.024 ;
    END
  END pi_line[305]
  PIN pi_line[306]
    DIRECTION OUTPUT ;
    USE SIGNAL ;
    PORT
      LAYER M4 ;
        RECT  194.316 72.096 194.4 72.12 ;
    END
  END pi_line[306]
  PIN pi_line[307]
    DIRECTION OUTPUT ;
    USE SIGNAL ;
    PORT
      LAYER M4 ;
        RECT  194.316 72.192 194.4 72.216 ;
    END
  END pi_line[307]
  PIN pi_line[308]
    DIRECTION OUTPUT ;
    USE SIGNAL ;
    PORT
      LAYER M4 ;
        RECT  194.316 72.288 194.4 72.312 ;
    END
  END pi_line[308]
  PIN pi_line[309]
    DIRECTION OUTPUT ;
    USE SIGNAL ;
    PORT
      LAYER M4 ;
        RECT  194.316 72.384 194.4 72.408 ;
    END
  END pi_line[309]
  PIN pi_line[30]
    DIRECTION OUTPUT ;
    USE SIGNAL ;
    PORT
      LAYER M4 ;
        RECT  194.316 45.6 194.4 45.624 ;
    END
  END pi_line[30]
  PIN pi_line[310]
    DIRECTION OUTPUT ;
    USE SIGNAL ;
    PORT
      LAYER M4 ;
        RECT  194.316 72.48 194.4 72.504 ;
    END
  END pi_line[310]
  PIN pi_line[311]
    DIRECTION OUTPUT ;
    USE SIGNAL ;
    PORT
      LAYER M4 ;
        RECT  194.316 72.576 194.4 72.6 ;
    END
  END pi_line[311]
  PIN pi_line[312]
    DIRECTION OUTPUT ;
    USE SIGNAL ;
    PORT
      LAYER M4 ;
        RECT  194.316 72.672 194.4 72.696 ;
    END
  END pi_line[312]
  PIN pi_line[313]
    DIRECTION OUTPUT ;
    USE SIGNAL ;
    PORT
      LAYER M4 ;
        RECT  194.316 72.768 194.4 72.792 ;
    END
  END pi_line[313]
  PIN pi_line[314]
    DIRECTION OUTPUT ;
    USE SIGNAL ;
    PORT
      LAYER M4 ;
        RECT  194.316 72.864 194.4 72.888 ;
    END
  END pi_line[314]
  PIN pi_line[315]
    DIRECTION OUTPUT ;
    USE SIGNAL ;
    PORT
      LAYER M4 ;
        RECT  194.316 72.96 194.4 72.984 ;
    END
  END pi_line[315]
  PIN pi_line[316]
    DIRECTION OUTPUT ;
    USE SIGNAL ;
    PORT
      LAYER M4 ;
        RECT  194.316 73.056 194.4 73.08 ;
    END
  END pi_line[316]
  PIN pi_line[317]
    DIRECTION OUTPUT ;
    USE SIGNAL ;
    PORT
      LAYER M4 ;
        RECT  194.316 73.152 194.4 73.176 ;
    END
  END pi_line[317]
  PIN pi_line[318]
    DIRECTION OUTPUT ;
    USE SIGNAL ;
    PORT
      LAYER M4 ;
        RECT  194.316 73.248 194.4 73.272 ;
    END
  END pi_line[318]
  PIN pi_line[319]
    DIRECTION OUTPUT ;
    USE SIGNAL ;
    PORT
      LAYER M4 ;
        RECT  194.316 73.344 194.4 73.368 ;
    END
  END pi_line[319]
  PIN pi_line[31]
    DIRECTION OUTPUT ;
    USE SIGNAL ;
    PORT
      LAYER M4 ;
        RECT  194.316 45.696 194.4 45.72 ;
    END
  END pi_line[31]
  PIN pi_line[320]
    DIRECTION OUTPUT ;
    USE SIGNAL ;
    PORT
      LAYER M4 ;
        RECT  194.316 73.44 194.4 73.464 ;
    END
  END pi_line[320]
  PIN pi_line[321]
    DIRECTION OUTPUT ;
    USE SIGNAL ;
    PORT
      LAYER M4 ;
        RECT  194.316 73.536 194.4 73.56 ;
    END
  END pi_line[321]
  PIN pi_line[322]
    DIRECTION OUTPUT ;
    USE SIGNAL ;
    PORT
      LAYER M4 ;
        RECT  194.316 73.632 194.4 73.656 ;
    END
  END pi_line[322]
  PIN pi_line[323]
    DIRECTION OUTPUT ;
    USE SIGNAL ;
    PORT
      LAYER M4 ;
        RECT  194.316 73.728 194.4 73.752 ;
    END
  END pi_line[323]
  PIN pi_line[324]
    DIRECTION OUTPUT ;
    USE SIGNAL ;
    PORT
      LAYER M4 ;
        RECT  194.316 73.824 194.4 73.848 ;
    END
  END pi_line[324]
  PIN pi_line[325]
    DIRECTION OUTPUT ;
    USE SIGNAL ;
    PORT
      LAYER M4 ;
        RECT  194.316 73.92 194.4 73.944 ;
    END
  END pi_line[325]
  PIN pi_line[326]
    DIRECTION OUTPUT ;
    USE SIGNAL ;
    PORT
      LAYER M4 ;
        RECT  194.316 74.016 194.4 74.04 ;
    END
  END pi_line[326]
  PIN pi_line[327]
    DIRECTION OUTPUT ;
    USE SIGNAL ;
    PORT
      LAYER M4 ;
        RECT  194.316 74.112 194.4 74.136 ;
    END
  END pi_line[327]
  PIN pi_line[328]
    DIRECTION OUTPUT ;
    USE SIGNAL ;
    PORT
      LAYER M4 ;
        RECT  194.316 74.208 194.4 74.232 ;
    END
  END pi_line[328]
  PIN pi_line[329]
    DIRECTION OUTPUT ;
    USE SIGNAL ;
    PORT
      LAYER M4 ;
        RECT  194.316 74.304 194.4 74.328 ;
    END
  END pi_line[329]
  PIN pi_line[32]
    DIRECTION OUTPUT ;
    USE SIGNAL ;
    PORT
      LAYER M4 ;
        RECT  194.316 45.792 194.4 45.816 ;
    END
  END pi_line[32]
  PIN pi_line[330]
    DIRECTION OUTPUT ;
    USE SIGNAL ;
    PORT
      LAYER M4 ;
        RECT  194.316 74.4 194.4 74.424 ;
    END
  END pi_line[330]
  PIN pi_line[331]
    DIRECTION OUTPUT ;
    USE SIGNAL ;
    PORT
      LAYER M4 ;
        RECT  194.316 74.496 194.4 74.52 ;
    END
  END pi_line[331]
  PIN pi_line[332]
    DIRECTION OUTPUT ;
    USE SIGNAL ;
    PORT
      LAYER M4 ;
        RECT  194.316 74.592 194.4 74.616 ;
    END
  END pi_line[332]
  PIN pi_line[333]
    DIRECTION OUTPUT ;
    USE SIGNAL ;
    PORT
      LAYER M4 ;
        RECT  194.316 74.688 194.4 74.712 ;
    END
  END pi_line[333]
  PIN pi_line[334]
    DIRECTION OUTPUT ;
    USE SIGNAL ;
    PORT
      LAYER M4 ;
        RECT  194.316 74.784 194.4 74.808 ;
    END
  END pi_line[334]
  PIN pi_line[335]
    DIRECTION OUTPUT ;
    USE SIGNAL ;
    PORT
      LAYER M4 ;
        RECT  194.316 74.88 194.4 74.904 ;
    END
  END pi_line[335]
  PIN pi_line[336]
    DIRECTION OUTPUT ;
    USE SIGNAL ;
    PORT
      LAYER M4 ;
        RECT  194.316 74.976 194.4 75 ;
    END
  END pi_line[336]
  PIN pi_line[337]
    DIRECTION OUTPUT ;
    USE SIGNAL ;
    PORT
      LAYER M4 ;
        RECT  194.316 75.072 194.4 75.096 ;
    END
  END pi_line[337]
  PIN pi_line[338]
    DIRECTION OUTPUT ;
    USE SIGNAL ;
    PORT
      LAYER M4 ;
        RECT  194.316 75.168 194.4 75.192 ;
    END
  END pi_line[338]
  PIN pi_line[339]
    DIRECTION OUTPUT ;
    USE SIGNAL ;
    PORT
      LAYER M4 ;
        RECT  194.316 75.264 194.4 75.288 ;
    END
  END pi_line[339]
  PIN pi_line[33]
    DIRECTION OUTPUT ;
    USE SIGNAL ;
    PORT
      LAYER M4 ;
        RECT  194.316 45.888 194.4 45.912 ;
    END
  END pi_line[33]
  PIN pi_line[340]
    DIRECTION OUTPUT ;
    USE SIGNAL ;
    PORT
      LAYER M4 ;
        RECT  194.316 75.36 194.4 75.384 ;
    END
  END pi_line[340]
  PIN pi_line[341]
    DIRECTION OUTPUT ;
    USE SIGNAL ;
    PORT
      LAYER M4 ;
        RECT  194.316 75.456 194.4 75.48 ;
    END
  END pi_line[341]
  PIN pi_line[342]
    DIRECTION OUTPUT ;
    USE SIGNAL ;
    PORT
      LAYER M4 ;
        RECT  194.316 75.552 194.4 75.576 ;
    END
  END pi_line[342]
  PIN pi_line[343]
    DIRECTION OUTPUT ;
    USE SIGNAL ;
    PORT
      LAYER M4 ;
        RECT  194.316 75.648 194.4 75.672 ;
    END
  END pi_line[343]
  PIN pi_line[344]
    DIRECTION OUTPUT ;
    USE SIGNAL ;
    PORT
      LAYER M4 ;
        RECT  194.316 75.744 194.4 75.768 ;
    END
  END pi_line[344]
  PIN pi_line[345]
    DIRECTION OUTPUT ;
    USE SIGNAL ;
    PORT
      LAYER M4 ;
        RECT  194.316 75.84 194.4 75.864 ;
    END
  END pi_line[345]
  PIN pi_line[346]
    DIRECTION OUTPUT ;
    USE SIGNAL ;
    PORT
      LAYER M4 ;
        RECT  194.316 75.936 194.4 75.96 ;
    END
  END pi_line[346]
  PIN pi_line[347]
    DIRECTION OUTPUT ;
    USE SIGNAL ;
    PORT
      LAYER M4 ;
        RECT  194.316 76.032 194.4 76.056 ;
    END
  END pi_line[347]
  PIN pi_line[348]
    DIRECTION OUTPUT ;
    USE SIGNAL ;
    PORT
      LAYER M4 ;
        RECT  194.316 76.128 194.4 76.152 ;
    END
  END pi_line[348]
  PIN pi_line[349]
    DIRECTION OUTPUT ;
    USE SIGNAL ;
    PORT
      LAYER M4 ;
        RECT  194.316 76.224 194.4 76.248 ;
    END
  END pi_line[349]
  PIN pi_line[34]
    DIRECTION OUTPUT ;
    USE SIGNAL ;
    PORT
      LAYER M4 ;
        RECT  194.316 45.984 194.4 46.008 ;
    END
  END pi_line[34]
  PIN pi_line[350]
    DIRECTION OUTPUT ;
    USE SIGNAL ;
    PORT
      LAYER M4 ;
        RECT  194.316 76.32 194.4 76.344 ;
    END
  END pi_line[350]
  PIN pi_line[351]
    DIRECTION OUTPUT ;
    USE SIGNAL ;
    PORT
      LAYER M4 ;
        RECT  194.316 76.416 194.4 76.44 ;
    END
  END pi_line[351]
  PIN pi_line[352]
    DIRECTION OUTPUT ;
    USE SIGNAL ;
    PORT
      LAYER M4 ;
        RECT  194.316 76.512 194.4 76.536 ;
    END
  END pi_line[352]
  PIN pi_line[353]
    DIRECTION OUTPUT ;
    USE SIGNAL ;
    PORT
      LAYER M4 ;
        RECT  194.316 76.608 194.4 76.632 ;
    END
  END pi_line[353]
  PIN pi_line[354]
    DIRECTION OUTPUT ;
    USE SIGNAL ;
    PORT
      LAYER M4 ;
        RECT  194.316 76.704 194.4 76.728 ;
    END
  END pi_line[354]
  PIN pi_line[355]
    DIRECTION OUTPUT ;
    USE SIGNAL ;
    PORT
      LAYER M4 ;
        RECT  194.316 76.8 194.4 76.824 ;
    END
  END pi_line[355]
  PIN pi_line[356]
    DIRECTION OUTPUT ;
    USE SIGNAL ;
    PORT
      LAYER M4 ;
        RECT  194.316 76.896 194.4 76.92 ;
    END
  END pi_line[356]
  PIN pi_line[357]
    DIRECTION OUTPUT ;
    USE SIGNAL ;
    PORT
      LAYER M4 ;
        RECT  194.316 76.992 194.4 77.016 ;
    END
  END pi_line[357]
  PIN pi_line[358]
    DIRECTION OUTPUT ;
    USE SIGNAL ;
    PORT
      LAYER M4 ;
        RECT  194.316 77.088 194.4 77.112 ;
    END
  END pi_line[358]
  PIN pi_line[359]
    DIRECTION OUTPUT ;
    USE SIGNAL ;
    PORT
      LAYER M4 ;
        RECT  194.316 77.184 194.4 77.208 ;
    END
  END pi_line[359]
  PIN pi_line[35]
    DIRECTION OUTPUT ;
    USE SIGNAL ;
    PORT
      LAYER M4 ;
        RECT  194.316 46.08 194.4 46.104 ;
    END
  END pi_line[35]
  PIN pi_line[360]
    DIRECTION OUTPUT ;
    USE SIGNAL ;
    PORT
      LAYER M4 ;
        RECT  194.316 77.28 194.4 77.304 ;
    END
  END pi_line[360]
  PIN pi_line[361]
    DIRECTION OUTPUT ;
    USE SIGNAL ;
    PORT
      LAYER M4 ;
        RECT  194.316 77.376 194.4 77.4 ;
    END
  END pi_line[361]
  PIN pi_line[362]
    DIRECTION OUTPUT ;
    USE SIGNAL ;
    PORT
      LAYER M4 ;
        RECT  194.316 77.472 194.4 77.496 ;
    END
  END pi_line[362]
  PIN pi_line[363]
    DIRECTION OUTPUT ;
    USE SIGNAL ;
    PORT
      LAYER M4 ;
        RECT  194.316 77.568 194.4 77.592 ;
    END
  END pi_line[363]
  PIN pi_line[364]
    DIRECTION OUTPUT ;
    USE SIGNAL ;
    PORT
      LAYER M4 ;
        RECT  194.316 77.664 194.4 77.688 ;
    END
  END pi_line[364]
  PIN pi_line[365]
    DIRECTION OUTPUT ;
    USE SIGNAL ;
    PORT
      LAYER M4 ;
        RECT  194.316 77.76 194.4 77.784 ;
    END
  END pi_line[365]
  PIN pi_line[366]
    DIRECTION OUTPUT ;
    USE SIGNAL ;
    PORT
      LAYER M4 ;
        RECT  194.316 77.856 194.4 77.88 ;
    END
  END pi_line[366]
  PIN pi_line[367]
    DIRECTION OUTPUT ;
    USE SIGNAL ;
    PORT
      LAYER M4 ;
        RECT  194.316 77.952 194.4 77.976 ;
    END
  END pi_line[367]
  PIN pi_line[368]
    DIRECTION OUTPUT ;
    USE SIGNAL ;
    PORT
      LAYER M4 ;
        RECT  194.316 78.048 194.4 78.072 ;
    END
  END pi_line[368]
  PIN pi_line[369]
    DIRECTION OUTPUT ;
    USE SIGNAL ;
    PORT
      LAYER M4 ;
        RECT  194.316 78.144 194.4 78.168 ;
    END
  END pi_line[369]
  PIN pi_line[36]
    DIRECTION OUTPUT ;
    USE SIGNAL ;
    PORT
      LAYER M4 ;
        RECT  194.316 46.176 194.4 46.2 ;
    END
  END pi_line[36]
  PIN pi_line[370]
    DIRECTION OUTPUT ;
    USE SIGNAL ;
    PORT
      LAYER M4 ;
        RECT  194.316 78.24 194.4 78.264 ;
    END
  END pi_line[370]
  PIN pi_line[371]
    DIRECTION OUTPUT ;
    USE SIGNAL ;
    PORT
      LAYER M4 ;
        RECT  194.316 78.336 194.4 78.36 ;
    END
  END pi_line[371]
  PIN pi_line[372]
    DIRECTION OUTPUT ;
    USE SIGNAL ;
    PORT
      LAYER M4 ;
        RECT  194.316 78.432 194.4 78.456 ;
    END
  END pi_line[372]
  PIN pi_line[373]
    DIRECTION OUTPUT ;
    USE SIGNAL ;
    PORT
      LAYER M4 ;
        RECT  194.316 78.528 194.4 78.552 ;
    END
  END pi_line[373]
  PIN pi_line[374]
    DIRECTION OUTPUT ;
    USE SIGNAL ;
    PORT
      LAYER M4 ;
        RECT  194.316 78.624 194.4 78.648 ;
    END
  END pi_line[374]
  PIN pi_line[375]
    DIRECTION OUTPUT ;
    USE SIGNAL ;
    PORT
      LAYER M4 ;
        RECT  194.316 78.72 194.4 78.744 ;
    END
  END pi_line[375]
  PIN pi_line[376]
    DIRECTION OUTPUT ;
    USE SIGNAL ;
    PORT
      LAYER M4 ;
        RECT  194.316 78.816 194.4 78.84 ;
    END
  END pi_line[376]
  PIN pi_line[377]
    DIRECTION OUTPUT ;
    USE SIGNAL ;
    PORT
      LAYER M4 ;
        RECT  194.316 78.912 194.4 78.936 ;
    END
  END pi_line[377]
  PIN pi_line[378]
    DIRECTION OUTPUT ;
    USE SIGNAL ;
    PORT
      LAYER M4 ;
        RECT  194.316 79.008 194.4 79.032 ;
    END
  END pi_line[378]
  PIN pi_line[379]
    DIRECTION OUTPUT ;
    USE SIGNAL ;
    PORT
      LAYER M4 ;
        RECT  194.316 79.104 194.4 79.128 ;
    END
  END pi_line[379]
  PIN pi_line[37]
    DIRECTION OUTPUT ;
    USE SIGNAL ;
    PORT
      LAYER M4 ;
        RECT  194.316 46.272 194.4 46.296 ;
    END
  END pi_line[37]
  PIN pi_line[380]
    DIRECTION OUTPUT ;
    USE SIGNAL ;
    PORT
      LAYER M4 ;
        RECT  194.316 79.2 194.4 79.224 ;
    END
  END pi_line[380]
  PIN pi_line[381]
    DIRECTION OUTPUT ;
    USE SIGNAL ;
    PORT
      LAYER M4 ;
        RECT  194.316 79.296 194.4 79.32 ;
    END
  END pi_line[381]
  PIN pi_line[382]
    DIRECTION OUTPUT ;
    USE SIGNAL ;
    PORT
      LAYER M4 ;
        RECT  194.316 79.392 194.4 79.416 ;
    END
  END pi_line[382]
  PIN pi_line[383]
    DIRECTION OUTPUT ;
    USE SIGNAL ;
    PORT
      LAYER M4 ;
        RECT  194.316 79.488 194.4 79.512 ;
    END
  END pi_line[383]
  PIN pi_line[384]
    DIRECTION OUTPUT ;
    USE SIGNAL ;
    PORT
      LAYER M4 ;
        RECT  194.316 79.584 194.4 79.608 ;
    END
  END pi_line[384]
  PIN pi_line[385]
    DIRECTION OUTPUT ;
    USE SIGNAL ;
    PORT
      LAYER M4 ;
        RECT  194.316 79.68 194.4 79.704 ;
    END
  END pi_line[385]
  PIN pi_line[386]
    DIRECTION OUTPUT ;
    USE SIGNAL ;
    PORT
      LAYER M4 ;
        RECT  194.316 79.776 194.4 79.8 ;
    END
  END pi_line[386]
  PIN pi_line[387]
    DIRECTION OUTPUT ;
    USE SIGNAL ;
    PORT
      LAYER M4 ;
        RECT  194.316 79.872 194.4 79.896 ;
    END
  END pi_line[387]
  PIN pi_line[388]
    DIRECTION OUTPUT ;
    USE SIGNAL ;
    PORT
      LAYER M4 ;
        RECT  194.316 79.968 194.4 79.992 ;
    END
  END pi_line[388]
  PIN pi_line[389]
    DIRECTION OUTPUT ;
    USE SIGNAL ;
    PORT
      LAYER M4 ;
        RECT  194.316 80.064 194.4 80.088 ;
    END
  END pi_line[389]
  PIN pi_line[38]
    DIRECTION OUTPUT ;
    USE SIGNAL ;
    PORT
      LAYER M4 ;
        RECT  194.316 46.368 194.4 46.392 ;
    END
  END pi_line[38]
  PIN pi_line[390]
    DIRECTION OUTPUT ;
    USE SIGNAL ;
    PORT
      LAYER M4 ;
        RECT  194.316 80.16 194.4 80.184 ;
    END
  END pi_line[390]
  PIN pi_line[391]
    DIRECTION OUTPUT ;
    USE SIGNAL ;
    PORT
      LAYER M4 ;
        RECT  194.316 80.256 194.4 80.28 ;
    END
  END pi_line[391]
  PIN pi_line[392]
    DIRECTION OUTPUT ;
    USE SIGNAL ;
    PORT
      LAYER M4 ;
        RECT  194.316 80.352 194.4 80.376 ;
    END
  END pi_line[392]
  PIN pi_line[393]
    DIRECTION OUTPUT ;
    USE SIGNAL ;
    PORT
      LAYER M4 ;
        RECT  194.316 80.448 194.4 80.472 ;
    END
  END pi_line[393]
  PIN pi_line[394]
    DIRECTION OUTPUT ;
    USE SIGNAL ;
    PORT
      LAYER M4 ;
        RECT  194.316 80.544 194.4 80.568 ;
    END
  END pi_line[394]
  PIN pi_line[395]
    DIRECTION OUTPUT ;
    USE SIGNAL ;
    PORT
      LAYER M4 ;
        RECT  194.316 80.64 194.4 80.664 ;
    END
  END pi_line[395]
  PIN pi_line[396]
    DIRECTION OUTPUT ;
    USE SIGNAL ;
    PORT
      LAYER M4 ;
        RECT  194.316 80.736 194.4 80.76 ;
    END
  END pi_line[396]
  PIN pi_line[397]
    DIRECTION OUTPUT ;
    USE SIGNAL ;
    PORT
      LAYER M4 ;
        RECT  194.316 80.832 194.4 80.856 ;
    END
  END pi_line[397]
  PIN pi_line[398]
    DIRECTION OUTPUT ;
    USE SIGNAL ;
    PORT
      LAYER M4 ;
        RECT  194.316 80.928 194.4 80.952 ;
    END
  END pi_line[398]
  PIN pi_line[399]
    DIRECTION OUTPUT ;
    USE SIGNAL ;
    PORT
      LAYER M4 ;
        RECT  194.316 81.024 194.4 81.048 ;
    END
  END pi_line[399]
  PIN pi_line[39]
    DIRECTION OUTPUT ;
    USE SIGNAL ;
    PORT
      LAYER M4 ;
        RECT  194.316 46.464 194.4 46.488 ;
    END
  END pi_line[39]
  PIN pi_line[3]
    DIRECTION OUTPUT ;
    USE SIGNAL ;
    PORT
      LAYER M4 ;
        RECT  194.316 43.008 194.4 43.032 ;
    END
  END pi_line[3]
  PIN pi_line[400]
    DIRECTION OUTPUT ;
    USE SIGNAL ;
    PORT
      LAYER M4 ;
        RECT  194.316 81.12 194.4 81.144 ;
    END
  END pi_line[400]
  PIN pi_line[401]
    DIRECTION OUTPUT ;
    USE SIGNAL ;
    PORT
      LAYER M4 ;
        RECT  194.316 81.216 194.4 81.24 ;
    END
  END pi_line[401]
  PIN pi_line[402]
    DIRECTION OUTPUT ;
    USE SIGNAL ;
    PORT
      LAYER M4 ;
        RECT  194.316 81.312 194.4 81.336 ;
    END
  END pi_line[402]
  PIN pi_line[403]
    DIRECTION OUTPUT ;
    USE SIGNAL ;
    PORT
      LAYER M4 ;
        RECT  194.316 81.408 194.4 81.432 ;
    END
  END pi_line[403]
  PIN pi_line[404]
    DIRECTION OUTPUT ;
    USE SIGNAL ;
    PORT
      LAYER M4 ;
        RECT  194.316 81.504 194.4 81.528 ;
    END
  END pi_line[404]
  PIN pi_line[405]
    DIRECTION OUTPUT ;
    USE SIGNAL ;
    PORT
      LAYER M4 ;
        RECT  194.316 81.6 194.4 81.624 ;
    END
  END pi_line[405]
  PIN pi_line[406]
    DIRECTION OUTPUT ;
    USE SIGNAL ;
    PORT
      LAYER M4 ;
        RECT  194.316 81.696 194.4 81.72 ;
    END
  END pi_line[406]
  PIN pi_line[407]
    DIRECTION OUTPUT ;
    USE SIGNAL ;
    PORT
      LAYER M4 ;
        RECT  194.316 81.792 194.4 81.816 ;
    END
  END pi_line[407]
  PIN pi_line[408]
    DIRECTION OUTPUT ;
    USE SIGNAL ;
    PORT
      LAYER M4 ;
        RECT  194.316 81.888 194.4 81.912 ;
    END
  END pi_line[408]
  PIN pi_line[409]
    DIRECTION OUTPUT ;
    USE SIGNAL ;
    PORT
      LAYER M4 ;
        RECT  194.316 81.984 194.4 82.008 ;
    END
  END pi_line[409]
  PIN pi_line[40]
    DIRECTION OUTPUT ;
    USE SIGNAL ;
    PORT
      LAYER M4 ;
        RECT  194.316 46.56 194.4 46.584 ;
    END
  END pi_line[40]
  PIN pi_line[410]
    DIRECTION OUTPUT ;
    USE SIGNAL ;
    PORT
      LAYER M4 ;
        RECT  194.316 82.08 194.4 82.104 ;
    END
  END pi_line[410]
  PIN pi_line[411]
    DIRECTION OUTPUT ;
    USE SIGNAL ;
    PORT
      LAYER M4 ;
        RECT  194.316 82.176 194.4 82.2 ;
    END
  END pi_line[411]
  PIN pi_line[412]
    DIRECTION OUTPUT ;
    USE SIGNAL ;
    PORT
      LAYER M4 ;
        RECT  194.316 82.272 194.4 82.296 ;
    END
  END pi_line[412]
  PIN pi_line[413]
    DIRECTION OUTPUT ;
    USE SIGNAL ;
    PORT
      LAYER M4 ;
        RECT  194.316 82.368 194.4 82.392 ;
    END
  END pi_line[413]
  PIN pi_line[414]
    DIRECTION OUTPUT ;
    USE SIGNAL ;
    PORT
      LAYER M4 ;
        RECT  194.316 82.464 194.4 82.488 ;
    END
  END pi_line[414]
  PIN pi_line[415]
    DIRECTION OUTPUT ;
    USE SIGNAL ;
    PORT
      LAYER M4 ;
        RECT  194.316 82.56 194.4 82.584 ;
    END
  END pi_line[415]
  PIN pi_line[416]
    DIRECTION OUTPUT ;
    USE SIGNAL ;
    PORT
      LAYER M4 ;
        RECT  194.316 82.656 194.4 82.68 ;
    END
  END pi_line[416]
  PIN pi_line[417]
    DIRECTION OUTPUT ;
    USE SIGNAL ;
    PORT
      LAYER M4 ;
        RECT  194.316 82.752 194.4 82.776 ;
    END
  END pi_line[417]
  PIN pi_line[418]
    DIRECTION OUTPUT ;
    USE SIGNAL ;
    PORT
      LAYER M4 ;
        RECT  194.316 82.848 194.4 82.872 ;
    END
  END pi_line[418]
  PIN pi_line[419]
    DIRECTION OUTPUT ;
    USE SIGNAL ;
    PORT
      LAYER M4 ;
        RECT  194.316 82.944 194.4 82.968 ;
    END
  END pi_line[419]
  PIN pi_line[41]
    DIRECTION OUTPUT ;
    USE SIGNAL ;
    PORT
      LAYER M4 ;
        RECT  194.316 46.656 194.4 46.68 ;
    END
  END pi_line[41]
  PIN pi_line[420]
    DIRECTION OUTPUT ;
    USE SIGNAL ;
    PORT
      LAYER M4 ;
        RECT  194.316 83.04 194.4 83.064 ;
    END
  END pi_line[420]
  PIN pi_line[421]
    DIRECTION OUTPUT ;
    USE SIGNAL ;
    PORT
      LAYER M4 ;
        RECT  194.316 83.136 194.4 83.16 ;
    END
  END pi_line[421]
  PIN pi_line[422]
    DIRECTION OUTPUT ;
    USE SIGNAL ;
    PORT
      LAYER M4 ;
        RECT  194.316 83.232 194.4 83.256 ;
    END
  END pi_line[422]
  PIN pi_line[423]
    DIRECTION OUTPUT ;
    USE SIGNAL ;
    PORT
      LAYER M4 ;
        RECT  194.316 83.328 194.4 83.352 ;
    END
  END pi_line[423]
  PIN pi_line[424]
    DIRECTION OUTPUT ;
    USE SIGNAL ;
    PORT
      LAYER M4 ;
        RECT  194.316 83.424 194.4 83.448 ;
    END
  END pi_line[424]
  PIN pi_line[425]
    DIRECTION OUTPUT ;
    USE SIGNAL ;
    PORT
      LAYER M4 ;
        RECT  194.316 83.52 194.4 83.544 ;
    END
  END pi_line[425]
  PIN pi_line[426]
    DIRECTION OUTPUT ;
    USE SIGNAL ;
    PORT
      LAYER M4 ;
        RECT  194.316 83.616 194.4 83.64 ;
    END
  END pi_line[426]
  PIN pi_line[427]
    DIRECTION OUTPUT ;
    USE SIGNAL ;
    PORT
      LAYER M4 ;
        RECT  194.316 83.712 194.4 83.736 ;
    END
  END pi_line[427]
  PIN pi_line[428]
    DIRECTION OUTPUT ;
    USE SIGNAL ;
    PORT
      LAYER M4 ;
        RECT  194.316 83.808 194.4 83.832 ;
    END
  END pi_line[428]
  PIN pi_line[429]
    DIRECTION OUTPUT ;
    USE SIGNAL ;
    PORT
      LAYER M4 ;
        RECT  194.316 83.904 194.4 83.928 ;
    END
  END pi_line[429]
  PIN pi_line[42]
    DIRECTION OUTPUT ;
    USE SIGNAL ;
    PORT
      LAYER M4 ;
        RECT  194.316 46.752 194.4 46.776 ;
    END
  END pi_line[42]
  PIN pi_line[430]
    DIRECTION OUTPUT ;
    USE SIGNAL ;
    PORT
      LAYER M4 ;
        RECT  194.316 84 194.4 84.024 ;
    END
  END pi_line[430]
  PIN pi_line[431]
    DIRECTION OUTPUT ;
    USE SIGNAL ;
    PORT
      LAYER M4 ;
        RECT  194.316 84.096 194.4 84.12 ;
    END
  END pi_line[431]
  PIN pi_line[432]
    DIRECTION OUTPUT ;
    USE SIGNAL ;
    PORT
      LAYER M4 ;
        RECT  194.316 84.192 194.4 84.216 ;
    END
  END pi_line[432]
  PIN pi_line[433]
    DIRECTION OUTPUT ;
    USE SIGNAL ;
    PORT
      LAYER M4 ;
        RECT  194.316 84.288 194.4 84.312 ;
    END
  END pi_line[433]
  PIN pi_line[434]
    DIRECTION OUTPUT ;
    USE SIGNAL ;
    PORT
      LAYER M4 ;
        RECT  194.316 84.384 194.4 84.408 ;
    END
  END pi_line[434]
  PIN pi_line[435]
    DIRECTION OUTPUT ;
    USE SIGNAL ;
    PORT
      LAYER M4 ;
        RECT  194.316 84.48 194.4 84.504 ;
    END
  END pi_line[435]
  PIN pi_line[436]
    DIRECTION OUTPUT ;
    USE SIGNAL ;
    PORT
      LAYER M4 ;
        RECT  194.316 84.576 194.4 84.6 ;
    END
  END pi_line[436]
  PIN pi_line[437]
    DIRECTION OUTPUT ;
    USE SIGNAL ;
    PORT
      LAYER M4 ;
        RECT  194.316 84.672 194.4 84.696 ;
    END
  END pi_line[437]
  PIN pi_line[438]
    DIRECTION OUTPUT ;
    USE SIGNAL ;
    PORT
      LAYER M4 ;
        RECT  194.316 84.768 194.4 84.792 ;
    END
  END pi_line[438]
  PIN pi_line[439]
    DIRECTION OUTPUT ;
    USE SIGNAL ;
    PORT
      LAYER M4 ;
        RECT  194.316 84.864 194.4 84.888 ;
    END
  END pi_line[439]
  PIN pi_line[43]
    DIRECTION OUTPUT ;
    USE SIGNAL ;
    PORT
      LAYER M4 ;
        RECT  194.316 46.848 194.4 46.872 ;
    END
  END pi_line[43]
  PIN pi_line[440]
    DIRECTION OUTPUT ;
    USE SIGNAL ;
    PORT
      LAYER M4 ;
        RECT  194.316 84.96 194.4 84.984 ;
    END
  END pi_line[440]
  PIN pi_line[441]
    DIRECTION OUTPUT ;
    USE SIGNAL ;
    PORT
      LAYER M4 ;
        RECT  194.316 85.056 194.4 85.08 ;
    END
  END pi_line[441]
  PIN pi_line[442]
    DIRECTION OUTPUT ;
    USE SIGNAL ;
    PORT
      LAYER M4 ;
        RECT  194.316 85.152 194.4 85.176 ;
    END
  END pi_line[442]
  PIN pi_line[443]
    DIRECTION OUTPUT ;
    USE SIGNAL ;
    PORT
      LAYER M4 ;
        RECT  194.316 85.248 194.4 85.272 ;
    END
  END pi_line[443]
  PIN pi_line[444]
    DIRECTION OUTPUT ;
    USE SIGNAL ;
    PORT
      LAYER M4 ;
        RECT  194.316 85.344 194.4 85.368 ;
    END
  END pi_line[444]
  PIN pi_line[445]
    DIRECTION OUTPUT ;
    USE SIGNAL ;
    PORT
      LAYER M4 ;
        RECT  194.316 85.44 194.4 85.464 ;
    END
  END pi_line[445]
  PIN pi_line[446]
    DIRECTION OUTPUT ;
    USE SIGNAL ;
    PORT
      LAYER M4 ;
        RECT  194.316 85.536 194.4 85.56 ;
    END
  END pi_line[446]
  PIN pi_line[447]
    DIRECTION OUTPUT ;
    USE SIGNAL ;
    PORT
      LAYER M4 ;
        RECT  194.316 85.632 194.4 85.656 ;
    END
  END pi_line[447]
  PIN pi_line[448]
    DIRECTION OUTPUT ;
    USE SIGNAL ;
    PORT
      LAYER M4 ;
        RECT  194.316 85.728 194.4 85.752 ;
    END
  END pi_line[448]
  PIN pi_line[449]
    DIRECTION OUTPUT ;
    USE SIGNAL ;
    PORT
      LAYER M4 ;
        RECT  194.316 85.824 194.4 85.848 ;
    END
  END pi_line[449]
  PIN pi_line[44]
    DIRECTION OUTPUT ;
    USE SIGNAL ;
    PORT
      LAYER M4 ;
        RECT  194.316 46.944 194.4 46.968 ;
    END
  END pi_line[44]
  PIN pi_line[450]
    DIRECTION OUTPUT ;
    USE SIGNAL ;
    PORT
      LAYER M4 ;
        RECT  194.316 85.92 194.4 85.944 ;
    END
  END pi_line[450]
  PIN pi_line[451]
    DIRECTION OUTPUT ;
    USE SIGNAL ;
    PORT
      LAYER M4 ;
        RECT  194.316 86.016 194.4 86.04 ;
    END
  END pi_line[451]
  PIN pi_line[452]
    DIRECTION OUTPUT ;
    USE SIGNAL ;
    PORT
      LAYER M4 ;
        RECT  194.316 86.112 194.4 86.136 ;
    END
  END pi_line[452]
  PIN pi_line[453]
    DIRECTION OUTPUT ;
    USE SIGNAL ;
    PORT
      LAYER M4 ;
        RECT  194.316 86.208 194.4 86.232 ;
    END
  END pi_line[453]
  PIN pi_line[454]
    DIRECTION OUTPUT ;
    USE SIGNAL ;
    PORT
      LAYER M4 ;
        RECT  194.316 86.304 194.4 86.328 ;
    END
  END pi_line[454]
  PIN pi_line[455]
    DIRECTION OUTPUT ;
    USE SIGNAL ;
    PORT
      LAYER M4 ;
        RECT  194.316 86.4 194.4 86.424 ;
    END
  END pi_line[455]
  PIN pi_line[456]
    DIRECTION OUTPUT ;
    USE SIGNAL ;
    PORT
      LAYER M4 ;
        RECT  194.316 86.496 194.4 86.52 ;
    END
  END pi_line[456]
  PIN pi_line[457]
    DIRECTION OUTPUT ;
    USE SIGNAL ;
    PORT
      LAYER M4 ;
        RECT  194.316 86.592 194.4 86.616 ;
    END
  END pi_line[457]
  PIN pi_line[458]
    DIRECTION OUTPUT ;
    USE SIGNAL ;
    PORT
      LAYER M4 ;
        RECT  194.316 86.688 194.4 86.712 ;
    END
  END pi_line[458]
  PIN pi_line[459]
    DIRECTION OUTPUT ;
    USE SIGNAL ;
    PORT
      LAYER M4 ;
        RECT  194.316 86.784 194.4 86.808 ;
    END
  END pi_line[459]
  PIN pi_line[45]
    DIRECTION OUTPUT ;
    USE SIGNAL ;
    PORT
      LAYER M4 ;
        RECT  194.316 47.04 194.4 47.064 ;
    END
  END pi_line[45]
  PIN pi_line[460]
    DIRECTION OUTPUT ;
    USE SIGNAL ;
    PORT
      LAYER M4 ;
        RECT  194.316 86.88 194.4 86.904 ;
    END
  END pi_line[460]
  PIN pi_line[461]
    DIRECTION OUTPUT ;
    USE SIGNAL ;
    PORT
      LAYER M4 ;
        RECT  194.316 86.976 194.4 87 ;
    END
  END pi_line[461]
  PIN pi_line[462]
    DIRECTION OUTPUT ;
    USE SIGNAL ;
    PORT
      LAYER M4 ;
        RECT  194.316 87.072 194.4 87.096 ;
    END
  END pi_line[462]
  PIN pi_line[463]
    DIRECTION OUTPUT ;
    USE SIGNAL ;
    PORT
      LAYER M4 ;
        RECT  194.316 87.168 194.4 87.192 ;
    END
  END pi_line[463]
  PIN pi_line[464]
    DIRECTION OUTPUT ;
    USE SIGNAL ;
    PORT
      LAYER M4 ;
        RECT  194.316 87.264 194.4 87.288 ;
    END
  END pi_line[464]
  PIN pi_line[465]
    DIRECTION OUTPUT ;
    USE SIGNAL ;
    PORT
      LAYER M4 ;
        RECT  194.316 87.36 194.4 87.384 ;
    END
  END pi_line[465]
  PIN pi_line[466]
    DIRECTION OUTPUT ;
    USE SIGNAL ;
    PORT
      LAYER M4 ;
        RECT  194.316 87.456 194.4 87.48 ;
    END
  END pi_line[466]
  PIN pi_line[467]
    DIRECTION OUTPUT ;
    USE SIGNAL ;
    PORT
      LAYER M4 ;
        RECT  194.316 87.552 194.4 87.576 ;
    END
  END pi_line[467]
  PIN pi_line[468]
    DIRECTION OUTPUT ;
    USE SIGNAL ;
    PORT
      LAYER M4 ;
        RECT  194.316 87.648 194.4 87.672 ;
    END
  END pi_line[468]
  PIN pi_line[469]
    DIRECTION OUTPUT ;
    USE SIGNAL ;
    PORT
      LAYER M4 ;
        RECT  194.316 87.744 194.4 87.768 ;
    END
  END pi_line[469]
  PIN pi_line[46]
    DIRECTION OUTPUT ;
    USE SIGNAL ;
    PORT
      LAYER M4 ;
        RECT  194.316 47.136 194.4 47.16 ;
    END
  END pi_line[46]
  PIN pi_line[470]
    DIRECTION OUTPUT ;
    USE SIGNAL ;
    PORT
      LAYER M4 ;
        RECT  194.316 87.84 194.4 87.864 ;
    END
  END pi_line[470]
  PIN pi_line[471]
    DIRECTION OUTPUT ;
    USE SIGNAL ;
    PORT
      LAYER M4 ;
        RECT  194.316 87.936 194.4 87.96 ;
    END
  END pi_line[471]
  PIN pi_line[472]
    DIRECTION OUTPUT ;
    USE SIGNAL ;
    PORT
      LAYER M4 ;
        RECT  194.316 88.032 194.4 88.056 ;
    END
  END pi_line[472]
  PIN pi_line[473]
    DIRECTION OUTPUT ;
    USE SIGNAL ;
    PORT
      LAYER M4 ;
        RECT  194.316 88.128 194.4 88.152 ;
    END
  END pi_line[473]
  PIN pi_line[474]
    DIRECTION OUTPUT ;
    USE SIGNAL ;
    PORT
      LAYER M4 ;
        RECT  194.316 88.224 194.4 88.248 ;
    END
  END pi_line[474]
  PIN pi_line[475]
    DIRECTION OUTPUT ;
    USE SIGNAL ;
    PORT
      LAYER M4 ;
        RECT  194.316 88.32 194.4 88.344 ;
    END
  END pi_line[475]
  PIN pi_line[476]
    DIRECTION OUTPUT ;
    USE SIGNAL ;
    PORT
      LAYER M4 ;
        RECT  194.316 88.416 194.4 88.44 ;
    END
  END pi_line[476]
  PIN pi_line[477]
    DIRECTION OUTPUT ;
    USE SIGNAL ;
    PORT
      LAYER M4 ;
        RECT  194.316 88.512 194.4 88.536 ;
    END
  END pi_line[477]
  PIN pi_line[478]
    DIRECTION OUTPUT ;
    USE SIGNAL ;
    PORT
      LAYER M4 ;
        RECT  194.316 88.608 194.4 88.632 ;
    END
  END pi_line[478]
  PIN pi_line[479]
    DIRECTION OUTPUT ;
    USE SIGNAL ;
    PORT
      LAYER M4 ;
        RECT  194.316 88.704 194.4 88.728 ;
    END
  END pi_line[479]
  PIN pi_line[47]
    DIRECTION OUTPUT ;
    USE SIGNAL ;
    PORT
      LAYER M4 ;
        RECT  194.316 47.232 194.4 47.256 ;
    END
  END pi_line[47]
  PIN pi_line[480]
    DIRECTION OUTPUT ;
    USE SIGNAL ;
    PORT
      LAYER M4 ;
        RECT  194.316 88.8 194.4 88.824 ;
    END
  END pi_line[480]
  PIN pi_line[481]
    DIRECTION OUTPUT ;
    USE SIGNAL ;
    PORT
      LAYER M4 ;
        RECT  194.316 88.896 194.4 88.92 ;
    END
  END pi_line[481]
  PIN pi_line[482]
    DIRECTION OUTPUT ;
    USE SIGNAL ;
    PORT
      LAYER M4 ;
        RECT  194.316 88.992 194.4 89.016 ;
    END
  END pi_line[482]
  PIN pi_line[483]
    DIRECTION OUTPUT ;
    USE SIGNAL ;
    PORT
      LAYER M4 ;
        RECT  194.316 89.088 194.4 89.112 ;
    END
  END pi_line[483]
  PIN pi_line[484]
    DIRECTION OUTPUT ;
    USE SIGNAL ;
    PORT
      LAYER M4 ;
        RECT  194.316 89.184 194.4 89.208 ;
    END
  END pi_line[484]
  PIN pi_line[485]
    DIRECTION OUTPUT ;
    USE SIGNAL ;
    PORT
      LAYER M4 ;
        RECT  194.316 89.28 194.4 89.304 ;
    END
  END pi_line[485]
  PIN pi_line[486]
    DIRECTION OUTPUT ;
    USE SIGNAL ;
    PORT
      LAYER M4 ;
        RECT  194.316 89.376 194.4 89.4 ;
    END
  END pi_line[486]
  PIN pi_line[487]
    DIRECTION OUTPUT ;
    USE SIGNAL ;
    PORT
      LAYER M4 ;
        RECT  194.316 89.472 194.4 89.496 ;
    END
  END pi_line[487]
  PIN pi_line[488]
    DIRECTION OUTPUT ;
    USE SIGNAL ;
    PORT
      LAYER M4 ;
        RECT  194.316 89.568 194.4 89.592 ;
    END
  END pi_line[488]
  PIN pi_line[489]
    DIRECTION OUTPUT ;
    USE SIGNAL ;
    PORT
      LAYER M4 ;
        RECT  194.316 89.664 194.4 89.688 ;
    END
  END pi_line[489]
  PIN pi_line[48]
    DIRECTION OUTPUT ;
    USE SIGNAL ;
    PORT
      LAYER M4 ;
        RECT  194.316 47.328 194.4 47.352 ;
    END
  END pi_line[48]
  PIN pi_line[490]
    DIRECTION OUTPUT ;
    USE SIGNAL ;
    PORT
      LAYER M4 ;
        RECT  194.316 89.76 194.4 89.784 ;
    END
  END pi_line[490]
  PIN pi_line[491]
    DIRECTION OUTPUT ;
    USE SIGNAL ;
    PORT
      LAYER M4 ;
        RECT  194.316 89.856 194.4 89.88 ;
    END
  END pi_line[491]
  PIN pi_line[492]
    DIRECTION OUTPUT ;
    USE SIGNAL ;
    PORT
      LAYER M4 ;
        RECT  194.316 89.952 194.4 89.976 ;
    END
  END pi_line[492]
  PIN pi_line[493]
    DIRECTION OUTPUT ;
    USE SIGNAL ;
    PORT
      LAYER M4 ;
        RECT  194.316 90.048 194.4 90.072 ;
    END
  END pi_line[493]
  PIN pi_line[494]
    DIRECTION OUTPUT ;
    USE SIGNAL ;
    PORT
      LAYER M4 ;
        RECT  194.316 90.144 194.4 90.168 ;
    END
  END pi_line[494]
  PIN pi_line[495]
    DIRECTION OUTPUT ;
    USE SIGNAL ;
    PORT
      LAYER M4 ;
        RECT  194.316 90.24 194.4 90.264 ;
    END
  END pi_line[495]
  PIN pi_line[496]
    DIRECTION OUTPUT ;
    USE SIGNAL ;
    PORT
      LAYER M4 ;
        RECT  194.316 90.336 194.4 90.36 ;
    END
  END pi_line[496]
  PIN pi_line[497]
    DIRECTION OUTPUT ;
    USE SIGNAL ;
    PORT
      LAYER M4 ;
        RECT  194.316 90.432 194.4 90.456 ;
    END
  END pi_line[497]
  PIN pi_line[498]
    DIRECTION OUTPUT ;
    USE SIGNAL ;
    PORT
      LAYER M4 ;
        RECT  194.316 90.528 194.4 90.552 ;
    END
  END pi_line[498]
  PIN pi_line[499]
    DIRECTION OUTPUT ;
    USE SIGNAL ;
    PORT
      LAYER M4 ;
        RECT  194.316 90.624 194.4 90.648 ;
    END
  END pi_line[499]
  PIN pi_line[49]
    DIRECTION OUTPUT ;
    USE SIGNAL ;
    PORT
      LAYER M4 ;
        RECT  194.316 47.424 194.4 47.448 ;
    END
  END pi_line[49]
  PIN pi_line[4]
    DIRECTION OUTPUT ;
    USE SIGNAL ;
    PORT
      LAYER M4 ;
        RECT  194.316 43.104 194.4 43.128 ;
    END
  END pi_line[4]
  PIN pi_line[500]
    DIRECTION OUTPUT ;
    USE SIGNAL ;
    PORT
      LAYER M4 ;
        RECT  194.316 90.72 194.4 90.744 ;
    END
  END pi_line[500]
  PIN pi_line[501]
    DIRECTION OUTPUT ;
    USE SIGNAL ;
    PORT
      LAYER M4 ;
        RECT  194.316 90.816 194.4 90.84 ;
    END
  END pi_line[501]
  PIN pi_line[502]
    DIRECTION OUTPUT ;
    USE SIGNAL ;
    PORT
      LAYER M4 ;
        RECT  194.316 90.912 194.4 90.936 ;
    END
  END pi_line[502]
  PIN pi_line[503]
    DIRECTION OUTPUT ;
    USE SIGNAL ;
    PORT
      LAYER M4 ;
        RECT  194.316 91.008 194.4 91.032 ;
    END
  END pi_line[503]
  PIN pi_line[504]
    DIRECTION OUTPUT ;
    USE SIGNAL ;
    PORT
      LAYER M4 ;
        RECT  194.316 91.104 194.4 91.128 ;
    END
  END pi_line[504]
  PIN pi_line[505]
    DIRECTION OUTPUT ;
    USE SIGNAL ;
    PORT
      LAYER M4 ;
        RECT  194.316 91.2 194.4 91.224 ;
    END
  END pi_line[505]
  PIN pi_line[506]
    DIRECTION OUTPUT ;
    USE SIGNAL ;
    PORT
      LAYER M4 ;
        RECT  194.316 91.296 194.4 91.32 ;
    END
  END pi_line[506]
  PIN pi_line[507]
    DIRECTION OUTPUT ;
    USE SIGNAL ;
    PORT
      LAYER M4 ;
        RECT  194.316 91.392 194.4 91.416 ;
    END
  END pi_line[507]
  PIN pi_line[508]
    DIRECTION OUTPUT ;
    USE SIGNAL ;
    PORT
      LAYER M4 ;
        RECT  194.316 91.488 194.4 91.512 ;
    END
  END pi_line[508]
  PIN pi_line[509]
    DIRECTION OUTPUT ;
    USE SIGNAL ;
    PORT
      LAYER M4 ;
        RECT  194.316 91.584 194.4 91.608 ;
    END
  END pi_line[509]
  PIN pi_line[50]
    DIRECTION OUTPUT ;
    USE SIGNAL ;
    PORT
      LAYER M4 ;
        RECT  194.316 47.52 194.4 47.544 ;
    END
  END pi_line[50]
  PIN pi_line[510]
    DIRECTION OUTPUT ;
    USE SIGNAL ;
    PORT
      LAYER M4 ;
        RECT  194.316 91.68 194.4 91.704 ;
    END
  END pi_line[510]
  PIN pi_line[511]
    DIRECTION OUTPUT ;
    USE SIGNAL ;
    PORT
      LAYER M4 ;
        RECT  194.316 91.776 194.4 91.8 ;
    END
  END pi_line[511]
  PIN pi_line[512]
    DIRECTION OUTPUT ;
    USE SIGNAL ;
    PORT
      LAYER M4 ;
        RECT  194.316 91.872 194.4 91.896 ;
    END
  END pi_line[512]
  PIN pi_line[513]
    DIRECTION OUTPUT ;
    USE SIGNAL ;
    PORT
      LAYER M4 ;
        RECT  194.316 91.968 194.4 91.992 ;
    END
  END pi_line[513]
  PIN pi_line[514]
    DIRECTION OUTPUT ;
    USE SIGNAL ;
    PORT
      LAYER M4 ;
        RECT  194.316 92.064 194.4 92.088 ;
    END
  END pi_line[514]
  PIN pi_line[515]
    DIRECTION OUTPUT ;
    USE SIGNAL ;
    PORT
      LAYER M4 ;
        RECT  194.316 92.16 194.4 92.184 ;
    END
  END pi_line[515]
  PIN pi_line[516]
    DIRECTION OUTPUT ;
    USE SIGNAL ;
    PORT
      LAYER M4 ;
        RECT  194.316 92.256 194.4 92.28 ;
    END
  END pi_line[516]
  PIN pi_line[517]
    DIRECTION OUTPUT ;
    USE SIGNAL ;
    PORT
      LAYER M4 ;
        RECT  194.316 92.352 194.4 92.376 ;
    END
  END pi_line[517]
  PIN pi_line[518]
    DIRECTION OUTPUT ;
    USE SIGNAL ;
    PORT
      LAYER M4 ;
        RECT  194.316 92.448 194.4 92.472 ;
    END
  END pi_line[518]
  PIN pi_line[519]
    DIRECTION OUTPUT ;
    USE SIGNAL ;
    PORT
      LAYER M4 ;
        RECT  194.316 92.544 194.4 92.568 ;
    END
  END pi_line[519]
  PIN pi_line[51]
    DIRECTION OUTPUT ;
    USE SIGNAL ;
    PORT
      LAYER M4 ;
        RECT  194.316 47.616 194.4 47.64 ;
    END
  END pi_line[51]
  PIN pi_line[520]
    DIRECTION OUTPUT ;
    USE SIGNAL ;
    PORT
      LAYER M4 ;
        RECT  194.316 92.64 194.4 92.664 ;
    END
  END pi_line[520]
  PIN pi_line[521]
    DIRECTION OUTPUT ;
    USE SIGNAL ;
    PORT
      LAYER M4 ;
        RECT  194.316 92.736 194.4 92.76 ;
    END
  END pi_line[521]
  PIN pi_line[522]
    DIRECTION OUTPUT ;
    USE SIGNAL ;
    PORT
      LAYER M4 ;
        RECT  194.316 92.832 194.4 92.856 ;
    END
  END pi_line[522]
  PIN pi_line[523]
    DIRECTION OUTPUT ;
    USE SIGNAL ;
    PORT
      LAYER M4 ;
        RECT  194.316 92.928 194.4 92.952 ;
    END
  END pi_line[523]
  PIN pi_line[524]
    DIRECTION OUTPUT ;
    USE SIGNAL ;
    PORT
      LAYER M4 ;
        RECT  194.316 93.024 194.4 93.048 ;
    END
  END pi_line[524]
  PIN pi_line[525]
    DIRECTION OUTPUT ;
    USE SIGNAL ;
    PORT
      LAYER M4 ;
        RECT  194.316 93.12 194.4 93.144 ;
    END
  END pi_line[525]
  PIN pi_line[526]
    DIRECTION OUTPUT ;
    USE SIGNAL ;
    PORT
      LAYER M4 ;
        RECT  194.316 93.216 194.4 93.24 ;
    END
  END pi_line[526]
  PIN pi_line[527]
    DIRECTION OUTPUT ;
    USE SIGNAL ;
    PORT
      LAYER M4 ;
        RECT  194.316 93.312 194.4 93.336 ;
    END
  END pi_line[527]
  PIN pi_line[528]
    DIRECTION OUTPUT ;
    USE SIGNAL ;
    PORT
      LAYER M4 ;
        RECT  194.316 93.408 194.4 93.432 ;
    END
  END pi_line[528]
  PIN pi_line[529]
    DIRECTION OUTPUT ;
    USE SIGNAL ;
    PORT
      LAYER M4 ;
        RECT  194.316 93.504 194.4 93.528 ;
    END
  END pi_line[529]
  PIN pi_line[52]
    DIRECTION OUTPUT ;
    USE SIGNAL ;
    PORT
      LAYER M4 ;
        RECT  194.316 47.712 194.4 47.736 ;
    END
  END pi_line[52]
  PIN pi_line[530]
    DIRECTION OUTPUT ;
    USE SIGNAL ;
    PORT
      LAYER M4 ;
        RECT  194.316 93.6 194.4 93.624 ;
    END
  END pi_line[530]
  PIN pi_line[531]
    DIRECTION OUTPUT ;
    USE SIGNAL ;
    PORT
      LAYER M4 ;
        RECT  194.316 93.696 194.4 93.72 ;
    END
  END pi_line[531]
  PIN pi_line[532]
    DIRECTION OUTPUT ;
    USE SIGNAL ;
    PORT
      LAYER M4 ;
        RECT  194.316 93.792 194.4 93.816 ;
    END
  END pi_line[532]
  PIN pi_line[533]
    DIRECTION OUTPUT ;
    USE SIGNAL ;
    PORT
      LAYER M4 ;
        RECT  194.316 93.888 194.4 93.912 ;
    END
  END pi_line[533]
  PIN pi_line[534]
    DIRECTION OUTPUT ;
    USE SIGNAL ;
    PORT
      LAYER M4 ;
        RECT  194.316 93.984 194.4 94.008 ;
    END
  END pi_line[534]
  PIN pi_line[535]
    DIRECTION OUTPUT ;
    USE SIGNAL ;
    PORT
      LAYER M4 ;
        RECT  194.316 94.08 194.4 94.104 ;
    END
  END pi_line[535]
  PIN pi_line[536]
    DIRECTION OUTPUT ;
    USE SIGNAL ;
    PORT
      LAYER M4 ;
        RECT  194.316 94.176 194.4 94.2 ;
    END
  END pi_line[536]
  PIN pi_line[537]
    DIRECTION OUTPUT ;
    USE SIGNAL ;
    PORT
      LAYER M4 ;
        RECT  194.316 94.272 194.4 94.296 ;
    END
  END pi_line[537]
  PIN pi_line[538]
    DIRECTION OUTPUT ;
    USE SIGNAL ;
    PORT
      LAYER M4 ;
        RECT  194.316 94.368 194.4 94.392 ;
    END
  END pi_line[538]
  PIN pi_line[539]
    DIRECTION OUTPUT ;
    USE SIGNAL ;
    PORT
      LAYER M4 ;
        RECT  194.316 94.464 194.4 94.488 ;
    END
  END pi_line[539]
  PIN pi_line[53]
    DIRECTION OUTPUT ;
    USE SIGNAL ;
    PORT
      LAYER M4 ;
        RECT  194.316 47.808 194.4 47.832 ;
    END
  END pi_line[53]
  PIN pi_line[540]
    DIRECTION OUTPUT ;
    USE SIGNAL ;
    PORT
      LAYER M4 ;
        RECT  194.316 94.56 194.4 94.584 ;
    END
  END pi_line[540]
  PIN pi_line[541]
    DIRECTION OUTPUT ;
    USE SIGNAL ;
    PORT
      LAYER M4 ;
        RECT  194.316 94.656 194.4 94.68 ;
    END
  END pi_line[541]
  PIN pi_line[542]
    DIRECTION OUTPUT ;
    USE SIGNAL ;
    PORT
      LAYER M4 ;
        RECT  194.316 94.752 194.4 94.776 ;
    END
  END pi_line[542]
  PIN pi_line[543]
    DIRECTION OUTPUT ;
    USE SIGNAL ;
    PORT
      LAYER M4 ;
        RECT  194.316 94.848 194.4 94.872 ;
    END
  END pi_line[543]
  PIN pi_line[544]
    DIRECTION OUTPUT ;
    USE SIGNAL ;
    PORT
      LAYER M4 ;
        RECT  194.316 94.944 194.4 94.968 ;
    END
  END pi_line[544]
  PIN pi_line[545]
    DIRECTION OUTPUT ;
    USE SIGNAL ;
    PORT
      LAYER M4 ;
        RECT  194.316 95.04 194.4 95.064 ;
    END
  END pi_line[545]
  PIN pi_line[546]
    DIRECTION OUTPUT ;
    USE SIGNAL ;
    PORT
      LAYER M4 ;
        RECT  194.316 95.136 194.4 95.16 ;
    END
  END pi_line[546]
  PIN pi_line[547]
    DIRECTION OUTPUT ;
    USE SIGNAL ;
    PORT
      LAYER M4 ;
        RECT  194.316 95.232 194.4 95.256 ;
    END
  END pi_line[547]
  PIN pi_line[548]
    DIRECTION OUTPUT ;
    USE SIGNAL ;
    PORT
      LAYER M4 ;
        RECT  194.316 95.328 194.4 95.352 ;
    END
  END pi_line[548]
  PIN pi_line[549]
    DIRECTION OUTPUT ;
    USE SIGNAL ;
    PORT
      LAYER M4 ;
        RECT  194.316 95.424 194.4 95.448 ;
    END
  END pi_line[549]
  PIN pi_line[54]
    DIRECTION OUTPUT ;
    USE SIGNAL ;
    PORT
      LAYER M4 ;
        RECT  194.316 47.904 194.4 47.928 ;
    END
  END pi_line[54]
  PIN pi_line[550]
    DIRECTION OUTPUT ;
    USE SIGNAL ;
    PORT
      LAYER M4 ;
        RECT  194.316 95.52 194.4 95.544 ;
    END
  END pi_line[550]
  PIN pi_line[551]
    DIRECTION OUTPUT ;
    USE SIGNAL ;
    PORT
      LAYER M4 ;
        RECT  194.316 95.616 194.4 95.64 ;
    END
  END pi_line[551]
  PIN pi_line[552]
    DIRECTION OUTPUT ;
    USE SIGNAL ;
    PORT
      LAYER M4 ;
        RECT  194.316 95.712 194.4 95.736 ;
    END
  END pi_line[552]
  PIN pi_line[553]
    DIRECTION OUTPUT ;
    USE SIGNAL ;
    PORT
      LAYER M4 ;
        RECT  194.316 95.808 194.4 95.832 ;
    END
  END pi_line[553]
  PIN pi_line[554]
    DIRECTION OUTPUT ;
    USE SIGNAL ;
    PORT
      LAYER M4 ;
        RECT  194.316 95.904 194.4 95.928 ;
    END
  END pi_line[554]
  PIN pi_line[555]
    DIRECTION OUTPUT ;
    USE SIGNAL ;
    PORT
      LAYER M4 ;
        RECT  194.316 96 194.4 96.024 ;
    END
  END pi_line[555]
  PIN pi_line[556]
    DIRECTION OUTPUT ;
    USE SIGNAL ;
    PORT
      LAYER M4 ;
        RECT  194.316 96.096 194.4 96.12 ;
    END
  END pi_line[556]
  PIN pi_line[557]
    DIRECTION OUTPUT ;
    USE SIGNAL ;
    PORT
      LAYER M4 ;
        RECT  194.316 96.192 194.4 96.216 ;
    END
  END pi_line[557]
  PIN pi_line[558]
    DIRECTION OUTPUT ;
    USE SIGNAL ;
    PORT
      LAYER M4 ;
        RECT  194.316 96.288 194.4 96.312 ;
    END
  END pi_line[558]
  PIN pi_line[559]
    DIRECTION OUTPUT ;
    USE SIGNAL ;
    PORT
      LAYER M4 ;
        RECT  194.316 96.384 194.4 96.408 ;
    END
  END pi_line[559]
  PIN pi_line[55]
    DIRECTION OUTPUT ;
    USE SIGNAL ;
    PORT
      LAYER M4 ;
        RECT  194.316 48 194.4 48.024 ;
    END
  END pi_line[55]
  PIN pi_line[560]
    DIRECTION OUTPUT ;
    USE SIGNAL ;
    PORT
      LAYER M4 ;
        RECT  194.316 96.48 194.4 96.504 ;
    END
  END pi_line[560]
  PIN pi_line[561]
    DIRECTION OUTPUT ;
    USE SIGNAL ;
    PORT
      LAYER M4 ;
        RECT  194.316 96.576 194.4 96.6 ;
    END
  END pi_line[561]
  PIN pi_line[562]
    DIRECTION OUTPUT ;
    USE SIGNAL ;
    PORT
      LAYER M4 ;
        RECT  194.316 96.672 194.4 96.696 ;
    END
  END pi_line[562]
  PIN pi_line[563]
    DIRECTION OUTPUT ;
    USE SIGNAL ;
    PORT
      LAYER M4 ;
        RECT  194.316 96.768 194.4 96.792 ;
    END
  END pi_line[563]
  PIN pi_line[564]
    DIRECTION OUTPUT ;
    USE SIGNAL ;
    PORT
      LAYER M4 ;
        RECT  194.316 96.864 194.4 96.888 ;
    END
  END pi_line[564]
  PIN pi_line[565]
    DIRECTION OUTPUT ;
    USE SIGNAL ;
    PORT
      LAYER M4 ;
        RECT  194.316 96.96 194.4 96.984 ;
    END
  END pi_line[565]
  PIN pi_line[566]
    DIRECTION OUTPUT ;
    USE SIGNAL ;
    PORT
      LAYER M4 ;
        RECT  194.316 97.056 194.4 97.08 ;
    END
  END pi_line[566]
  PIN pi_line[567]
    DIRECTION OUTPUT ;
    USE SIGNAL ;
    PORT
      LAYER M4 ;
        RECT  194.316 97.152 194.4 97.176 ;
    END
  END pi_line[567]
  PIN pi_line[568]
    DIRECTION OUTPUT ;
    USE SIGNAL ;
    PORT
      LAYER M4 ;
        RECT  194.316 97.248 194.4 97.272 ;
    END
  END pi_line[568]
  PIN pi_line[569]
    DIRECTION OUTPUT ;
    USE SIGNAL ;
    PORT
      LAYER M4 ;
        RECT  194.316 97.344 194.4 97.368 ;
    END
  END pi_line[569]
  PIN pi_line[56]
    DIRECTION OUTPUT ;
    USE SIGNAL ;
    PORT
      LAYER M4 ;
        RECT  194.316 48.096 194.4 48.12 ;
    END
  END pi_line[56]
  PIN pi_line[570]
    DIRECTION OUTPUT ;
    USE SIGNAL ;
    PORT
      LAYER M4 ;
        RECT  194.316 97.44 194.4 97.464 ;
    END
  END pi_line[570]
  PIN pi_line[571]
    DIRECTION OUTPUT ;
    USE SIGNAL ;
    PORT
      LAYER M4 ;
        RECT  194.316 97.536 194.4 97.56 ;
    END
  END pi_line[571]
  PIN pi_line[572]
    DIRECTION OUTPUT ;
    USE SIGNAL ;
    PORT
      LAYER M4 ;
        RECT  194.316 97.632 194.4 97.656 ;
    END
  END pi_line[572]
  PIN pi_line[573]
    DIRECTION OUTPUT ;
    USE SIGNAL ;
    PORT
      LAYER M4 ;
        RECT  194.316 97.728 194.4 97.752 ;
    END
  END pi_line[573]
  PIN pi_line[574]
    DIRECTION OUTPUT ;
    USE SIGNAL ;
    PORT
      LAYER M4 ;
        RECT  194.316 97.824 194.4 97.848 ;
    END
  END pi_line[574]
  PIN pi_line[575]
    DIRECTION OUTPUT ;
    USE SIGNAL ;
    PORT
      LAYER M4 ;
        RECT  194.316 97.92 194.4 97.944 ;
    END
  END pi_line[575]
  PIN pi_line[576]
    DIRECTION OUTPUT ;
    USE SIGNAL ;
    PORT
      LAYER M4 ;
        RECT  194.316 98.016 194.4 98.04 ;
    END
  END pi_line[576]
  PIN pi_line[577]
    DIRECTION OUTPUT ;
    USE SIGNAL ;
    PORT
      LAYER M4 ;
        RECT  194.316 98.112 194.4 98.136 ;
    END
  END pi_line[577]
  PIN pi_line[578]
    DIRECTION OUTPUT ;
    USE SIGNAL ;
    PORT
      LAYER M4 ;
        RECT  194.316 98.208 194.4 98.232 ;
    END
  END pi_line[578]
  PIN pi_line[579]
    DIRECTION OUTPUT ;
    USE SIGNAL ;
    PORT
      LAYER M4 ;
        RECT  194.316 98.304 194.4 98.328 ;
    END
  END pi_line[579]
  PIN pi_line[57]
    DIRECTION OUTPUT ;
    USE SIGNAL ;
    PORT
      LAYER M4 ;
        RECT  194.316 48.192 194.4 48.216 ;
    END
  END pi_line[57]
  PIN pi_line[580]
    DIRECTION OUTPUT ;
    USE SIGNAL ;
    PORT
      LAYER M4 ;
        RECT  194.316 98.4 194.4 98.424 ;
    END
  END pi_line[580]
  PIN pi_line[581]
    DIRECTION OUTPUT ;
    USE SIGNAL ;
    PORT
      LAYER M4 ;
        RECT  194.316 98.496 194.4 98.52 ;
    END
  END pi_line[581]
  PIN pi_line[582]
    DIRECTION OUTPUT ;
    USE SIGNAL ;
    PORT
      LAYER M4 ;
        RECT  194.316 98.592 194.4 98.616 ;
    END
  END pi_line[582]
  PIN pi_line[583]
    DIRECTION OUTPUT ;
    USE SIGNAL ;
    PORT
      LAYER M4 ;
        RECT  194.316 98.688 194.4 98.712 ;
    END
  END pi_line[583]
  PIN pi_line[584]
    DIRECTION OUTPUT ;
    USE SIGNAL ;
    PORT
      LAYER M4 ;
        RECT  194.316 98.784 194.4 98.808 ;
    END
  END pi_line[584]
  PIN pi_line[585]
    DIRECTION OUTPUT ;
    USE SIGNAL ;
    PORT
      LAYER M4 ;
        RECT  194.316 98.88 194.4 98.904 ;
    END
  END pi_line[585]
  PIN pi_line[586]
    DIRECTION OUTPUT ;
    USE SIGNAL ;
    PORT
      LAYER M4 ;
        RECT  194.316 98.976 194.4 99 ;
    END
  END pi_line[586]
  PIN pi_line[587]
    DIRECTION OUTPUT ;
    USE SIGNAL ;
    PORT
      LAYER M4 ;
        RECT  194.316 99.072 194.4 99.096 ;
    END
  END pi_line[587]
  PIN pi_line[588]
    DIRECTION OUTPUT ;
    USE SIGNAL ;
    PORT
      LAYER M4 ;
        RECT  194.316 99.168 194.4 99.192 ;
    END
  END pi_line[588]
  PIN pi_line[589]
    DIRECTION OUTPUT ;
    USE SIGNAL ;
    PORT
      LAYER M4 ;
        RECT  194.316 99.264 194.4 99.288 ;
    END
  END pi_line[589]
  PIN pi_line[58]
    DIRECTION OUTPUT ;
    USE SIGNAL ;
    PORT
      LAYER M4 ;
        RECT  194.316 48.288 194.4 48.312 ;
    END
  END pi_line[58]
  PIN pi_line[590]
    DIRECTION OUTPUT ;
    USE SIGNAL ;
    PORT
      LAYER M4 ;
        RECT  194.316 99.36 194.4 99.384 ;
    END
  END pi_line[590]
  PIN pi_line[591]
    DIRECTION OUTPUT ;
    USE SIGNAL ;
    PORT
      LAYER M4 ;
        RECT  194.316 99.456 194.4 99.48 ;
    END
  END pi_line[591]
  PIN pi_line[59]
    DIRECTION OUTPUT ;
    USE SIGNAL ;
    PORT
      LAYER M4 ;
        RECT  194.316 48.384 194.4 48.408 ;
    END
  END pi_line[59]
  PIN pi_line[5]
    DIRECTION OUTPUT ;
    USE SIGNAL ;
    PORT
      LAYER M4 ;
        RECT  194.316 43.2 194.4 43.224 ;
    END
  END pi_line[5]
  PIN pi_line[60]
    DIRECTION OUTPUT ;
    USE SIGNAL ;
    PORT
      LAYER M4 ;
        RECT  194.316 48.48 194.4 48.504 ;
    END
  END pi_line[60]
  PIN pi_line[61]
    DIRECTION OUTPUT ;
    USE SIGNAL ;
    PORT
      LAYER M4 ;
        RECT  194.316 48.576 194.4 48.6 ;
    END
  END pi_line[61]
  PIN pi_line[62]
    DIRECTION OUTPUT ;
    USE SIGNAL ;
    PORT
      LAYER M4 ;
        RECT  194.316 48.672 194.4 48.696 ;
    END
  END pi_line[62]
  PIN pi_line[63]
    DIRECTION OUTPUT ;
    USE SIGNAL ;
    PORT
      LAYER M4 ;
        RECT  194.316 48.768 194.4 48.792 ;
    END
  END pi_line[63]
  PIN pi_line[64]
    DIRECTION OUTPUT ;
    USE SIGNAL ;
    PORT
      LAYER M4 ;
        RECT  194.316 48.864 194.4 48.888 ;
    END
  END pi_line[64]
  PIN pi_line[65]
    DIRECTION OUTPUT ;
    USE SIGNAL ;
    PORT
      LAYER M4 ;
        RECT  194.316 48.96 194.4 48.984 ;
    END
  END pi_line[65]
  PIN pi_line[66]
    DIRECTION OUTPUT ;
    USE SIGNAL ;
    PORT
      LAYER M4 ;
        RECT  194.316 49.056 194.4 49.08 ;
    END
  END pi_line[66]
  PIN pi_line[67]
    DIRECTION OUTPUT ;
    USE SIGNAL ;
    PORT
      LAYER M4 ;
        RECT  194.316 49.152 194.4 49.176 ;
    END
  END pi_line[67]
  PIN pi_line[68]
    DIRECTION OUTPUT ;
    USE SIGNAL ;
    PORT
      LAYER M4 ;
        RECT  194.316 49.248 194.4 49.272 ;
    END
  END pi_line[68]
  PIN pi_line[69]
    DIRECTION OUTPUT ;
    USE SIGNAL ;
    PORT
      LAYER M4 ;
        RECT  194.316 49.344 194.4 49.368 ;
    END
  END pi_line[69]
  PIN pi_line[6]
    DIRECTION OUTPUT ;
    USE SIGNAL ;
    PORT
      LAYER M4 ;
        RECT  194.316 43.296 194.4 43.32 ;
    END
  END pi_line[6]
  PIN pi_line[70]
    DIRECTION OUTPUT ;
    USE SIGNAL ;
    PORT
      LAYER M4 ;
        RECT  194.316 49.44 194.4 49.464 ;
    END
  END pi_line[70]
  PIN pi_line[71]
    DIRECTION OUTPUT ;
    USE SIGNAL ;
    PORT
      LAYER M4 ;
        RECT  194.316 49.536 194.4 49.56 ;
    END
  END pi_line[71]
  PIN pi_line[72]
    DIRECTION OUTPUT ;
    USE SIGNAL ;
    PORT
      LAYER M4 ;
        RECT  194.316 49.632 194.4 49.656 ;
    END
  END pi_line[72]
  PIN pi_line[73]
    DIRECTION OUTPUT ;
    USE SIGNAL ;
    PORT
      LAYER M4 ;
        RECT  194.316 49.728 194.4 49.752 ;
    END
  END pi_line[73]
  PIN pi_line[74]
    DIRECTION OUTPUT ;
    USE SIGNAL ;
    PORT
      LAYER M4 ;
        RECT  194.316 49.824 194.4 49.848 ;
    END
  END pi_line[74]
  PIN pi_line[75]
    DIRECTION OUTPUT ;
    USE SIGNAL ;
    PORT
      LAYER M4 ;
        RECT  194.316 49.92 194.4 49.944 ;
    END
  END pi_line[75]
  PIN pi_line[76]
    DIRECTION OUTPUT ;
    USE SIGNAL ;
    PORT
      LAYER M4 ;
        RECT  194.316 50.016 194.4 50.04 ;
    END
  END pi_line[76]
  PIN pi_line[77]
    DIRECTION OUTPUT ;
    USE SIGNAL ;
    PORT
      LAYER M4 ;
        RECT  194.316 50.112 194.4 50.136 ;
    END
  END pi_line[77]
  PIN pi_line[78]
    DIRECTION OUTPUT ;
    USE SIGNAL ;
    PORT
      LAYER M4 ;
        RECT  194.316 50.208 194.4 50.232 ;
    END
  END pi_line[78]
  PIN pi_line[79]
    DIRECTION OUTPUT ;
    USE SIGNAL ;
    PORT
      LAYER M4 ;
        RECT  194.316 50.304 194.4 50.328 ;
    END
  END pi_line[79]
  PIN pi_line[7]
    DIRECTION OUTPUT ;
    USE SIGNAL ;
    PORT
      LAYER M4 ;
        RECT  194.316 43.392 194.4 43.416 ;
    END
  END pi_line[7]
  PIN pi_line[80]
    DIRECTION OUTPUT ;
    USE SIGNAL ;
    PORT
      LAYER M4 ;
        RECT  194.316 50.4 194.4 50.424 ;
    END
  END pi_line[80]
  PIN pi_line[81]
    DIRECTION OUTPUT ;
    USE SIGNAL ;
    PORT
      LAYER M4 ;
        RECT  194.316 50.496 194.4 50.52 ;
    END
  END pi_line[81]
  PIN pi_line[82]
    DIRECTION OUTPUT ;
    USE SIGNAL ;
    PORT
      LAYER M4 ;
        RECT  194.316 50.592 194.4 50.616 ;
    END
  END pi_line[82]
  PIN pi_line[83]
    DIRECTION OUTPUT ;
    USE SIGNAL ;
    PORT
      LAYER M4 ;
        RECT  194.316 50.688 194.4 50.712 ;
    END
  END pi_line[83]
  PIN pi_line[84]
    DIRECTION OUTPUT ;
    USE SIGNAL ;
    PORT
      LAYER M4 ;
        RECT  194.316 50.784 194.4 50.808 ;
    END
  END pi_line[84]
  PIN pi_line[85]
    DIRECTION OUTPUT ;
    USE SIGNAL ;
    PORT
      LAYER M4 ;
        RECT  194.316 50.88 194.4 50.904 ;
    END
  END pi_line[85]
  PIN pi_line[86]
    DIRECTION OUTPUT ;
    USE SIGNAL ;
    PORT
      LAYER M4 ;
        RECT  194.316 50.976 194.4 51 ;
    END
  END pi_line[86]
  PIN pi_line[87]
    DIRECTION OUTPUT ;
    USE SIGNAL ;
    PORT
      LAYER M4 ;
        RECT  194.316 51.072 194.4 51.096 ;
    END
  END pi_line[87]
  PIN pi_line[88]
    DIRECTION OUTPUT ;
    USE SIGNAL ;
    PORT
      LAYER M4 ;
        RECT  194.316 51.168 194.4 51.192 ;
    END
  END pi_line[88]
  PIN pi_line[89]
    DIRECTION OUTPUT ;
    USE SIGNAL ;
    PORT
      LAYER M4 ;
        RECT  194.316 51.264 194.4 51.288 ;
    END
  END pi_line[89]
  PIN pi_line[8]
    DIRECTION OUTPUT ;
    USE SIGNAL ;
    PORT
      LAYER M4 ;
        RECT  194.316 43.488 194.4 43.512 ;
    END
  END pi_line[8]
  PIN pi_line[90]
    DIRECTION OUTPUT ;
    USE SIGNAL ;
    PORT
      LAYER M4 ;
        RECT  194.316 51.36 194.4 51.384 ;
    END
  END pi_line[90]
  PIN pi_line[91]
    DIRECTION OUTPUT ;
    USE SIGNAL ;
    PORT
      LAYER M4 ;
        RECT  194.316 51.456 194.4 51.48 ;
    END
  END pi_line[91]
  PIN pi_line[92]
    DIRECTION OUTPUT ;
    USE SIGNAL ;
    PORT
      LAYER M4 ;
        RECT  194.316 51.552 194.4 51.576 ;
    END
  END pi_line[92]
  PIN pi_line[93]
    DIRECTION OUTPUT ;
    USE SIGNAL ;
    PORT
      LAYER M4 ;
        RECT  194.316 51.648 194.4 51.672 ;
    END
  END pi_line[93]
  PIN pi_line[94]
    DIRECTION OUTPUT ;
    USE SIGNAL ;
    PORT
      LAYER M4 ;
        RECT  194.316 51.744 194.4 51.768 ;
    END
  END pi_line[94]
  PIN pi_line[95]
    DIRECTION OUTPUT ;
    USE SIGNAL ;
    PORT
      LAYER M4 ;
        RECT  194.316 51.84 194.4 51.864 ;
    END
  END pi_line[95]
  PIN pi_line[96]
    DIRECTION OUTPUT ;
    USE SIGNAL ;
    PORT
      LAYER M4 ;
        RECT  194.316 51.936 194.4 51.96 ;
    END
  END pi_line[96]
  PIN pi_line[97]
    DIRECTION OUTPUT ;
    USE SIGNAL ;
    PORT
      LAYER M4 ;
        RECT  194.316 52.032 194.4 52.056 ;
    END
  END pi_line[97]
  PIN pi_line[98]
    DIRECTION OUTPUT ;
    USE SIGNAL ;
    PORT
      LAYER M4 ;
        RECT  194.316 52.128 194.4 52.152 ;
    END
  END pi_line[98]
  PIN pi_line[99]
    DIRECTION OUTPUT ;
    USE SIGNAL ;
    PORT
      LAYER M4 ;
        RECT  194.316 52.224 194.4 52.248 ;
    END
  END pi_line[99]
  PIN pi_line[9]
    DIRECTION OUTPUT ;
    USE SIGNAL ;
    PORT
      LAYER M4 ;
        RECT  194.316 43.584 194.4 43.608 ;
    END
  END pi_line[9]
  PIN pi_lv[0]
    DIRECTION OUTPUT ;
    USE SIGNAL ;
    PORT
      LAYER M4 ;
        RECT  194.316 38.88 194.4 38.904 ;
    END
  END pi_lv[0]
  PIN pi_lv[10]
    DIRECTION OUTPUT ;
    USE SIGNAL ;
    PORT
      LAYER M4 ;
        RECT  194.316 39.84 194.4 39.864 ;
    END
  END pi_lv[10]
  PIN pi_lv[11]
    DIRECTION OUTPUT ;
    USE SIGNAL ;
    PORT
      LAYER M4 ;
        RECT  194.316 39.936 194.4 39.96 ;
    END
  END pi_lv[11]
  PIN pi_lv[12]
    DIRECTION OUTPUT ;
    USE SIGNAL ;
    PORT
      LAYER M4 ;
        RECT  194.316 40.032 194.4 40.056 ;
    END
  END pi_lv[12]
  PIN pi_lv[13]
    DIRECTION OUTPUT ;
    USE SIGNAL ;
    PORT
      LAYER M4 ;
        RECT  194.316 40.128 194.4 40.152 ;
    END
  END pi_lv[13]
  PIN pi_lv[14]
    DIRECTION OUTPUT ;
    USE SIGNAL ;
    PORT
      LAYER M4 ;
        RECT  194.316 40.224 194.4 40.248 ;
    END
  END pi_lv[14]
  PIN pi_lv[15]
    DIRECTION OUTPUT ;
    USE SIGNAL ;
    PORT
      LAYER M4 ;
        RECT  194.316 40.32 194.4 40.344 ;
    END
  END pi_lv[15]
  PIN pi_lv[1]
    DIRECTION OUTPUT ;
    USE SIGNAL ;
    PORT
      LAYER M4 ;
        RECT  194.316 38.976 194.4 39 ;
    END
  END pi_lv[1]
  PIN pi_lv[2]
    DIRECTION OUTPUT ;
    USE SIGNAL ;
    PORT
      LAYER M4 ;
        RECT  194.316 39.072 194.4 39.096 ;
    END
  END pi_lv[2]
  PIN pi_lv[3]
    DIRECTION OUTPUT ;
    USE SIGNAL ;
    PORT
      LAYER M4 ;
        RECT  194.316 39.168 194.4 39.192 ;
    END
  END pi_lv[3]
  PIN pi_lv[4]
    DIRECTION OUTPUT ;
    USE SIGNAL ;
    PORT
      LAYER M4 ;
        RECT  194.316 39.264 194.4 39.288 ;
    END
  END pi_lv[4]
  PIN pi_lv[5]
    DIRECTION OUTPUT ;
    USE SIGNAL ;
    PORT
      LAYER M4 ;
        RECT  194.316 39.36 194.4 39.384 ;
    END
  END pi_lv[5]
  PIN pi_lv[6]
    DIRECTION OUTPUT ;
    USE SIGNAL ;
    PORT
      LAYER M4 ;
        RECT  194.316 39.456 194.4 39.48 ;
    END
  END pi_lv[6]
  PIN pi_lv[7]
    DIRECTION OUTPUT ;
    USE SIGNAL ;
    PORT
      LAYER M4 ;
        RECT  194.316 39.552 194.4 39.576 ;
    END
  END pi_lv[7]
  PIN pi_lv[8]
    DIRECTION OUTPUT ;
    USE SIGNAL ;
    PORT
      LAYER M4 ;
        RECT  194.316 39.648 194.4 39.672 ;
    END
  END pi_lv[8]
  PIN pi_lv[9]
    DIRECTION OUTPUT ;
    USE SIGNAL ;
    PORT
      LAYER M4 ;
        RECT  194.316 39.744 194.4 39.768 ;
    END
  END pi_lv[9]
  PIN pi_vp[0]
    DIRECTION OUTPUT ;
    USE SIGNAL ;
    PORT
      LAYER M4 ;
        RECT  194.316 38.112 194.4 38.136 ;
    END
  END pi_vp[0]
  PIN pi_vp[1]
    DIRECTION OUTPUT ;
    USE SIGNAL ;
    PORT
      LAYER M4 ;
        RECT  194.316 38.208 194.4 38.232 ;
    END
  END pi_vp[1]
  PIN pi_vp[2]
    DIRECTION OUTPUT ;
    USE SIGNAL ;
    PORT
      LAYER M4 ;
        RECT  194.316 38.304 194.4 38.328 ;
    END
  END pi_vp[2]
  PIN pi_vp[3]
    DIRECTION OUTPUT ;
    USE SIGNAL ;
    PORT
      LAYER M4 ;
        RECT  194.316 38.4 194.4 38.424 ;
    END
  END pi_vp[3]
  PIN pi_vp[4]
    DIRECTION OUTPUT ;
    USE SIGNAL ;
    PORT
      LAYER M4 ;
        RECT  194.316 38.496 194.4 38.52 ;
    END
  END pi_vp[4]
  PIN pi_vp[5]
    DIRECTION OUTPUT ;
    USE SIGNAL ;
    PORT
      LAYER M4 ;
        RECT  194.316 38.592 194.4 38.616 ;
    END
  END pi_vp[5]
  PIN ps_bv
    DIRECTION OUTPUT ;
    USE SIGNAL ;
    PORT
      LAYER M4 ;
        RECT  194.316 41.088 194.4 41.112 ;
    END
  END ps_bv
  PIN ps_fl
    DIRECTION OUTPUT ;
    USE SIGNAL ;
    PORT
      LAYER M4 ;
        RECT  194.316 40.992 194.4 41.016 ;
    END
  END ps_fl
  PIN ps_line[0]
    DIRECTION OUTPUT ;
    USE SIGNAL ;
    PORT
      LAYER M4 ;
        RECT  194.316 99.552 194.4 99.576 ;
    END
  END ps_line[0]
  PIN ps_line[100]
    DIRECTION OUTPUT ;
    USE SIGNAL ;
    PORT
      LAYER M4 ;
        RECT  194.316 109.152 194.4 109.176 ;
    END
  END ps_line[100]
  PIN ps_line[101]
    DIRECTION OUTPUT ;
    USE SIGNAL ;
    PORT
      LAYER M4 ;
        RECT  194.316 109.248 194.4 109.272 ;
    END
  END ps_line[101]
  PIN ps_line[102]
    DIRECTION OUTPUT ;
    USE SIGNAL ;
    PORT
      LAYER M4 ;
        RECT  194.316 109.344 194.4 109.368 ;
    END
  END ps_line[102]
  PIN ps_line[103]
    DIRECTION OUTPUT ;
    USE SIGNAL ;
    PORT
      LAYER M4 ;
        RECT  194.316 109.44 194.4 109.464 ;
    END
  END ps_line[103]
  PIN ps_line[104]
    DIRECTION OUTPUT ;
    USE SIGNAL ;
    PORT
      LAYER M4 ;
        RECT  194.316 109.536 194.4 109.56 ;
    END
  END ps_line[104]
  PIN ps_line[105]
    DIRECTION OUTPUT ;
    USE SIGNAL ;
    PORT
      LAYER M4 ;
        RECT  194.316 109.632 194.4 109.656 ;
    END
  END ps_line[105]
  PIN ps_line[106]
    DIRECTION OUTPUT ;
    USE SIGNAL ;
    PORT
      LAYER M4 ;
        RECT  194.316 109.728 194.4 109.752 ;
    END
  END ps_line[106]
  PIN ps_line[107]
    DIRECTION OUTPUT ;
    USE SIGNAL ;
    PORT
      LAYER M4 ;
        RECT  194.316 109.824 194.4 109.848 ;
    END
  END ps_line[107]
  PIN ps_line[108]
    DIRECTION OUTPUT ;
    USE SIGNAL ;
    PORT
      LAYER M4 ;
        RECT  194.316 109.92 194.4 109.944 ;
    END
  END ps_line[108]
  PIN ps_line[109]
    DIRECTION OUTPUT ;
    USE SIGNAL ;
    PORT
      LAYER M4 ;
        RECT  194.316 110.016 194.4 110.04 ;
    END
  END ps_line[109]
  PIN ps_line[10]
    DIRECTION OUTPUT ;
    USE SIGNAL ;
    PORT
      LAYER M4 ;
        RECT  194.316 100.512 194.4 100.536 ;
    END
  END ps_line[10]
  PIN ps_line[110]
    DIRECTION OUTPUT ;
    USE SIGNAL ;
    PORT
      LAYER M4 ;
        RECT  194.316 110.112 194.4 110.136 ;
    END
  END ps_line[110]
  PIN ps_line[111]
    DIRECTION OUTPUT ;
    USE SIGNAL ;
    PORT
      LAYER M4 ;
        RECT  194.316 110.208 194.4 110.232 ;
    END
  END ps_line[111]
  PIN ps_line[112]
    DIRECTION OUTPUT ;
    USE SIGNAL ;
    PORT
      LAYER M4 ;
        RECT  194.316 110.304 194.4 110.328 ;
    END
  END ps_line[112]
  PIN ps_line[113]
    DIRECTION OUTPUT ;
    USE SIGNAL ;
    PORT
      LAYER M4 ;
        RECT  194.316 110.4 194.4 110.424 ;
    END
  END ps_line[113]
  PIN ps_line[114]
    DIRECTION OUTPUT ;
    USE SIGNAL ;
    PORT
      LAYER M4 ;
        RECT  194.316 110.496 194.4 110.52 ;
    END
  END ps_line[114]
  PIN ps_line[115]
    DIRECTION OUTPUT ;
    USE SIGNAL ;
    PORT
      LAYER M4 ;
        RECT  194.316 110.592 194.4 110.616 ;
    END
  END ps_line[115]
  PIN ps_line[116]
    DIRECTION OUTPUT ;
    USE SIGNAL ;
    PORT
      LAYER M4 ;
        RECT  194.316 110.688 194.4 110.712 ;
    END
  END ps_line[116]
  PIN ps_line[117]
    DIRECTION OUTPUT ;
    USE SIGNAL ;
    PORT
      LAYER M4 ;
        RECT  194.316 110.784 194.4 110.808 ;
    END
  END ps_line[117]
  PIN ps_line[118]
    DIRECTION OUTPUT ;
    USE SIGNAL ;
    PORT
      LAYER M4 ;
        RECT  194.316 110.88 194.4 110.904 ;
    END
  END ps_line[118]
  PIN ps_line[119]
    DIRECTION OUTPUT ;
    USE SIGNAL ;
    PORT
      LAYER M4 ;
        RECT  194.316 110.976 194.4 111 ;
    END
  END ps_line[119]
  PIN ps_line[11]
    DIRECTION OUTPUT ;
    USE SIGNAL ;
    PORT
      LAYER M4 ;
        RECT  194.316 100.608 194.4 100.632 ;
    END
  END ps_line[11]
  PIN ps_line[120]
    DIRECTION OUTPUT ;
    USE SIGNAL ;
    PORT
      LAYER M4 ;
        RECT  194.316 111.072 194.4 111.096 ;
    END
  END ps_line[120]
  PIN ps_line[121]
    DIRECTION OUTPUT ;
    USE SIGNAL ;
    PORT
      LAYER M4 ;
        RECT  194.316 111.168 194.4 111.192 ;
    END
  END ps_line[121]
  PIN ps_line[122]
    DIRECTION OUTPUT ;
    USE SIGNAL ;
    PORT
      LAYER M4 ;
        RECT  194.316 111.264 194.4 111.288 ;
    END
  END ps_line[122]
  PIN ps_line[123]
    DIRECTION OUTPUT ;
    USE SIGNAL ;
    PORT
      LAYER M4 ;
        RECT  194.316 111.36 194.4 111.384 ;
    END
  END ps_line[123]
  PIN ps_line[124]
    DIRECTION OUTPUT ;
    USE SIGNAL ;
    PORT
      LAYER M4 ;
        RECT  194.316 111.456 194.4 111.48 ;
    END
  END ps_line[124]
  PIN ps_line[125]
    DIRECTION OUTPUT ;
    USE SIGNAL ;
    PORT
      LAYER M4 ;
        RECT  194.316 111.552 194.4 111.576 ;
    END
  END ps_line[125]
  PIN ps_line[126]
    DIRECTION OUTPUT ;
    USE SIGNAL ;
    PORT
      LAYER M4 ;
        RECT  194.316 111.648 194.4 111.672 ;
    END
  END ps_line[126]
  PIN ps_line[127]
    DIRECTION OUTPUT ;
    USE SIGNAL ;
    PORT
      LAYER M4 ;
        RECT  194.316 111.744 194.4 111.768 ;
    END
  END ps_line[127]
  PIN ps_line[128]
    DIRECTION OUTPUT ;
    USE SIGNAL ;
    PORT
      LAYER M4 ;
        RECT  194.316 111.84 194.4 111.864 ;
    END
  END ps_line[128]
  PIN ps_line[129]
    DIRECTION OUTPUT ;
    USE SIGNAL ;
    PORT
      LAYER M4 ;
        RECT  194.316 111.936 194.4 111.96 ;
    END
  END ps_line[129]
  PIN ps_line[12]
    DIRECTION OUTPUT ;
    USE SIGNAL ;
    PORT
      LAYER M4 ;
        RECT  194.316 100.704 194.4 100.728 ;
    END
  END ps_line[12]
  PIN ps_line[130]
    DIRECTION OUTPUT ;
    USE SIGNAL ;
    PORT
      LAYER M4 ;
        RECT  194.316 112.032 194.4 112.056 ;
    END
  END ps_line[130]
  PIN ps_line[131]
    DIRECTION OUTPUT ;
    USE SIGNAL ;
    PORT
      LAYER M4 ;
        RECT  194.316 112.128 194.4 112.152 ;
    END
  END ps_line[131]
  PIN ps_line[132]
    DIRECTION OUTPUT ;
    USE SIGNAL ;
    PORT
      LAYER M4 ;
        RECT  194.316 112.224 194.4 112.248 ;
    END
  END ps_line[132]
  PIN ps_line[133]
    DIRECTION OUTPUT ;
    USE SIGNAL ;
    PORT
      LAYER M4 ;
        RECT  194.316 112.32 194.4 112.344 ;
    END
  END ps_line[133]
  PIN ps_line[134]
    DIRECTION OUTPUT ;
    USE SIGNAL ;
    PORT
      LAYER M4 ;
        RECT  194.316 112.416 194.4 112.44 ;
    END
  END ps_line[134]
  PIN ps_line[135]
    DIRECTION OUTPUT ;
    USE SIGNAL ;
    PORT
      LAYER M4 ;
        RECT  194.316 112.512 194.4 112.536 ;
    END
  END ps_line[135]
  PIN ps_line[136]
    DIRECTION OUTPUT ;
    USE SIGNAL ;
    PORT
      LAYER M4 ;
        RECT  194.316 112.608 194.4 112.632 ;
    END
  END ps_line[136]
  PIN ps_line[137]
    DIRECTION OUTPUT ;
    USE SIGNAL ;
    PORT
      LAYER M4 ;
        RECT  194.316 112.704 194.4 112.728 ;
    END
  END ps_line[137]
  PIN ps_line[138]
    DIRECTION OUTPUT ;
    USE SIGNAL ;
    PORT
      LAYER M4 ;
        RECT  194.316 112.8 194.4 112.824 ;
    END
  END ps_line[138]
  PIN ps_line[139]
    DIRECTION OUTPUT ;
    USE SIGNAL ;
    PORT
      LAYER M4 ;
        RECT  194.316 112.896 194.4 112.92 ;
    END
  END ps_line[139]
  PIN ps_line[13]
    DIRECTION OUTPUT ;
    USE SIGNAL ;
    PORT
      LAYER M4 ;
        RECT  194.316 100.8 194.4 100.824 ;
    END
  END ps_line[13]
  PIN ps_line[140]
    DIRECTION OUTPUT ;
    USE SIGNAL ;
    PORT
      LAYER M4 ;
        RECT  194.316 112.992 194.4 113.016 ;
    END
  END ps_line[140]
  PIN ps_line[141]
    DIRECTION OUTPUT ;
    USE SIGNAL ;
    PORT
      LAYER M4 ;
        RECT  194.316 113.088 194.4 113.112 ;
    END
  END ps_line[141]
  PIN ps_line[142]
    DIRECTION OUTPUT ;
    USE SIGNAL ;
    PORT
      LAYER M4 ;
        RECT  194.316 113.184 194.4 113.208 ;
    END
  END ps_line[142]
  PIN ps_line[143]
    DIRECTION OUTPUT ;
    USE SIGNAL ;
    PORT
      LAYER M4 ;
        RECT  194.316 113.28 194.4 113.304 ;
    END
  END ps_line[143]
  PIN ps_line[144]
    DIRECTION OUTPUT ;
    USE SIGNAL ;
    PORT
      LAYER M4 ;
        RECT  194.316 113.376 194.4 113.4 ;
    END
  END ps_line[144]
  PIN ps_line[145]
    DIRECTION OUTPUT ;
    USE SIGNAL ;
    PORT
      LAYER M4 ;
        RECT  194.316 113.472 194.4 113.496 ;
    END
  END ps_line[145]
  PIN ps_line[146]
    DIRECTION OUTPUT ;
    USE SIGNAL ;
    PORT
      LAYER M4 ;
        RECT  194.316 113.568 194.4 113.592 ;
    END
  END ps_line[146]
  PIN ps_line[147]
    DIRECTION OUTPUT ;
    USE SIGNAL ;
    PORT
      LAYER M4 ;
        RECT  194.316 113.664 194.4 113.688 ;
    END
  END ps_line[147]
  PIN ps_line[148]
    DIRECTION OUTPUT ;
    USE SIGNAL ;
    PORT
      LAYER M4 ;
        RECT  194.316 113.76 194.4 113.784 ;
    END
  END ps_line[148]
  PIN ps_line[149]
    DIRECTION OUTPUT ;
    USE SIGNAL ;
    PORT
      LAYER M4 ;
        RECT  194.316 113.856 194.4 113.88 ;
    END
  END ps_line[149]
  PIN ps_line[14]
    DIRECTION OUTPUT ;
    USE SIGNAL ;
    PORT
      LAYER M4 ;
        RECT  194.316 100.896 194.4 100.92 ;
    END
  END ps_line[14]
  PIN ps_line[150]
    DIRECTION OUTPUT ;
    USE SIGNAL ;
    PORT
      LAYER M4 ;
        RECT  194.316 113.952 194.4 113.976 ;
    END
  END ps_line[150]
  PIN ps_line[151]
    DIRECTION OUTPUT ;
    USE SIGNAL ;
    PORT
      LAYER M4 ;
        RECT  194.316 114.048 194.4 114.072 ;
    END
  END ps_line[151]
  PIN ps_line[152]
    DIRECTION OUTPUT ;
    USE SIGNAL ;
    PORT
      LAYER M4 ;
        RECT  194.316 114.144 194.4 114.168 ;
    END
  END ps_line[152]
  PIN ps_line[153]
    DIRECTION OUTPUT ;
    USE SIGNAL ;
    PORT
      LAYER M4 ;
        RECT  194.316 114.24 194.4 114.264 ;
    END
  END ps_line[153]
  PIN ps_line[154]
    DIRECTION OUTPUT ;
    USE SIGNAL ;
    PORT
      LAYER M4 ;
        RECT  194.316 114.336 194.4 114.36 ;
    END
  END ps_line[154]
  PIN ps_line[155]
    DIRECTION OUTPUT ;
    USE SIGNAL ;
    PORT
      LAYER M4 ;
        RECT  194.316 114.432 194.4 114.456 ;
    END
  END ps_line[155]
  PIN ps_line[156]
    DIRECTION OUTPUT ;
    USE SIGNAL ;
    PORT
      LAYER M4 ;
        RECT  194.316 114.528 194.4 114.552 ;
    END
  END ps_line[156]
  PIN ps_line[157]
    DIRECTION OUTPUT ;
    USE SIGNAL ;
    PORT
      LAYER M4 ;
        RECT  194.316 114.624 194.4 114.648 ;
    END
  END ps_line[157]
  PIN ps_line[158]
    DIRECTION OUTPUT ;
    USE SIGNAL ;
    PORT
      LAYER M4 ;
        RECT  194.316 114.72 194.4 114.744 ;
    END
  END ps_line[158]
  PIN ps_line[159]
    DIRECTION OUTPUT ;
    USE SIGNAL ;
    PORT
      LAYER M4 ;
        RECT  194.316 114.816 194.4 114.84 ;
    END
  END ps_line[159]
  PIN ps_line[15]
    DIRECTION OUTPUT ;
    USE SIGNAL ;
    PORT
      LAYER M4 ;
        RECT  194.316 100.992 194.4 101.016 ;
    END
  END ps_line[15]
  PIN ps_line[160]
    DIRECTION OUTPUT ;
    USE SIGNAL ;
    PORT
      LAYER M4 ;
        RECT  194.316 114.912 194.4 114.936 ;
    END
  END ps_line[160]
  PIN ps_line[161]
    DIRECTION OUTPUT ;
    USE SIGNAL ;
    PORT
      LAYER M4 ;
        RECT  194.316 115.008 194.4 115.032 ;
    END
  END ps_line[161]
  PIN ps_line[162]
    DIRECTION OUTPUT ;
    USE SIGNAL ;
    PORT
      LAYER M4 ;
        RECT  194.316 115.104 194.4 115.128 ;
    END
  END ps_line[162]
  PIN ps_line[163]
    DIRECTION OUTPUT ;
    USE SIGNAL ;
    PORT
      LAYER M4 ;
        RECT  194.316 115.2 194.4 115.224 ;
    END
  END ps_line[163]
  PIN ps_line[164]
    DIRECTION OUTPUT ;
    USE SIGNAL ;
    PORT
      LAYER M4 ;
        RECT  194.316 115.296 194.4 115.32 ;
    END
  END ps_line[164]
  PIN ps_line[165]
    DIRECTION OUTPUT ;
    USE SIGNAL ;
    PORT
      LAYER M4 ;
        RECT  194.316 115.392 194.4 115.416 ;
    END
  END ps_line[165]
  PIN ps_line[166]
    DIRECTION OUTPUT ;
    USE SIGNAL ;
    PORT
      LAYER M4 ;
        RECT  194.316 115.488 194.4 115.512 ;
    END
  END ps_line[166]
  PIN ps_line[167]
    DIRECTION OUTPUT ;
    USE SIGNAL ;
    PORT
      LAYER M4 ;
        RECT  194.316 115.584 194.4 115.608 ;
    END
  END ps_line[167]
  PIN ps_line[168]
    DIRECTION OUTPUT ;
    USE SIGNAL ;
    PORT
      LAYER M4 ;
        RECT  194.316 115.68 194.4 115.704 ;
    END
  END ps_line[168]
  PIN ps_line[169]
    DIRECTION OUTPUT ;
    USE SIGNAL ;
    PORT
      LAYER M4 ;
        RECT  194.316 115.776 194.4 115.8 ;
    END
  END ps_line[169]
  PIN ps_line[16]
    DIRECTION OUTPUT ;
    USE SIGNAL ;
    PORT
      LAYER M4 ;
        RECT  194.316 101.088 194.4 101.112 ;
    END
  END ps_line[16]
  PIN ps_line[170]
    DIRECTION OUTPUT ;
    USE SIGNAL ;
    PORT
      LAYER M4 ;
        RECT  194.316 115.872 194.4 115.896 ;
    END
  END ps_line[170]
  PIN ps_line[171]
    DIRECTION OUTPUT ;
    USE SIGNAL ;
    PORT
      LAYER M4 ;
        RECT  194.316 115.968 194.4 115.992 ;
    END
  END ps_line[171]
  PIN ps_line[172]
    DIRECTION OUTPUT ;
    USE SIGNAL ;
    PORT
      LAYER M4 ;
        RECT  194.316 116.064 194.4 116.088 ;
    END
  END ps_line[172]
  PIN ps_line[173]
    DIRECTION OUTPUT ;
    USE SIGNAL ;
    PORT
      LAYER M4 ;
        RECT  194.316 116.16 194.4 116.184 ;
    END
  END ps_line[173]
  PIN ps_line[174]
    DIRECTION OUTPUT ;
    USE SIGNAL ;
    PORT
      LAYER M4 ;
        RECT  194.316 116.256 194.4 116.28 ;
    END
  END ps_line[174]
  PIN ps_line[175]
    DIRECTION OUTPUT ;
    USE SIGNAL ;
    PORT
      LAYER M4 ;
        RECT  194.316 116.352 194.4 116.376 ;
    END
  END ps_line[175]
  PIN ps_line[176]
    DIRECTION OUTPUT ;
    USE SIGNAL ;
    PORT
      LAYER M4 ;
        RECT  194.316 116.448 194.4 116.472 ;
    END
  END ps_line[176]
  PIN ps_line[177]
    DIRECTION OUTPUT ;
    USE SIGNAL ;
    PORT
      LAYER M4 ;
        RECT  194.316 116.544 194.4 116.568 ;
    END
  END ps_line[177]
  PIN ps_line[178]
    DIRECTION OUTPUT ;
    USE SIGNAL ;
    PORT
      LAYER M4 ;
        RECT  194.316 116.64 194.4 116.664 ;
    END
  END ps_line[178]
  PIN ps_line[179]
    DIRECTION OUTPUT ;
    USE SIGNAL ;
    PORT
      LAYER M4 ;
        RECT  194.316 116.736 194.4 116.76 ;
    END
  END ps_line[179]
  PIN ps_line[17]
    DIRECTION OUTPUT ;
    USE SIGNAL ;
    PORT
      LAYER M4 ;
        RECT  194.316 101.184 194.4 101.208 ;
    END
  END ps_line[17]
  PIN ps_line[180]
    DIRECTION OUTPUT ;
    USE SIGNAL ;
    PORT
      LAYER M4 ;
        RECT  194.316 116.832 194.4 116.856 ;
    END
  END ps_line[180]
  PIN ps_line[181]
    DIRECTION OUTPUT ;
    USE SIGNAL ;
    PORT
      LAYER M4 ;
        RECT  194.316 116.928 194.4 116.952 ;
    END
  END ps_line[181]
  PIN ps_line[182]
    DIRECTION OUTPUT ;
    USE SIGNAL ;
    PORT
      LAYER M4 ;
        RECT  194.316 117.024 194.4 117.048 ;
    END
  END ps_line[182]
  PIN ps_line[183]
    DIRECTION OUTPUT ;
    USE SIGNAL ;
    PORT
      LAYER M4 ;
        RECT  194.316 117.12 194.4 117.144 ;
    END
  END ps_line[183]
  PIN ps_line[184]
    DIRECTION OUTPUT ;
    USE SIGNAL ;
    PORT
      LAYER M4 ;
        RECT  194.316 117.216 194.4 117.24 ;
    END
  END ps_line[184]
  PIN ps_line[185]
    DIRECTION OUTPUT ;
    USE SIGNAL ;
    PORT
      LAYER M4 ;
        RECT  194.316 117.312 194.4 117.336 ;
    END
  END ps_line[185]
  PIN ps_line[186]
    DIRECTION OUTPUT ;
    USE SIGNAL ;
    PORT
      LAYER M4 ;
        RECT  194.316 117.408 194.4 117.432 ;
    END
  END ps_line[186]
  PIN ps_line[187]
    DIRECTION OUTPUT ;
    USE SIGNAL ;
    PORT
      LAYER M4 ;
        RECT  194.316 117.504 194.4 117.528 ;
    END
  END ps_line[187]
  PIN ps_line[188]
    DIRECTION OUTPUT ;
    USE SIGNAL ;
    PORT
      LAYER M4 ;
        RECT  194.316 117.6 194.4 117.624 ;
    END
  END ps_line[188]
  PIN ps_line[189]
    DIRECTION OUTPUT ;
    USE SIGNAL ;
    PORT
      LAYER M4 ;
        RECT  194.316 117.696 194.4 117.72 ;
    END
  END ps_line[189]
  PIN ps_line[18]
    DIRECTION OUTPUT ;
    USE SIGNAL ;
    PORT
      LAYER M4 ;
        RECT  194.316 101.28 194.4 101.304 ;
    END
  END ps_line[18]
  PIN ps_line[190]
    DIRECTION OUTPUT ;
    USE SIGNAL ;
    PORT
      LAYER M4 ;
        RECT  194.316 117.792 194.4 117.816 ;
    END
  END ps_line[190]
  PIN ps_line[191]
    DIRECTION OUTPUT ;
    USE SIGNAL ;
    PORT
      LAYER M4 ;
        RECT  194.316 117.888 194.4 117.912 ;
    END
  END ps_line[191]
  PIN ps_line[192]
    DIRECTION OUTPUT ;
    USE SIGNAL ;
    PORT
      LAYER M4 ;
        RECT  194.316 117.984 194.4 118.008 ;
    END
  END ps_line[192]
  PIN ps_line[193]
    DIRECTION OUTPUT ;
    USE SIGNAL ;
    PORT
      LAYER M4 ;
        RECT  194.316 118.08 194.4 118.104 ;
    END
  END ps_line[193]
  PIN ps_line[194]
    DIRECTION OUTPUT ;
    USE SIGNAL ;
    PORT
      LAYER M4 ;
        RECT  194.316 118.176 194.4 118.2 ;
    END
  END ps_line[194]
  PIN ps_line[195]
    DIRECTION OUTPUT ;
    USE SIGNAL ;
    PORT
      LAYER M4 ;
        RECT  194.316 118.272 194.4 118.296 ;
    END
  END ps_line[195]
  PIN ps_line[196]
    DIRECTION OUTPUT ;
    USE SIGNAL ;
    PORT
      LAYER M4 ;
        RECT  194.316 118.368 194.4 118.392 ;
    END
  END ps_line[196]
  PIN ps_line[197]
    DIRECTION OUTPUT ;
    USE SIGNAL ;
    PORT
      LAYER M4 ;
        RECT  194.316 118.464 194.4 118.488 ;
    END
  END ps_line[197]
  PIN ps_line[198]
    DIRECTION OUTPUT ;
    USE SIGNAL ;
    PORT
      LAYER M4 ;
        RECT  194.316 118.56 194.4 118.584 ;
    END
  END ps_line[198]
  PIN ps_line[199]
    DIRECTION OUTPUT ;
    USE SIGNAL ;
    PORT
      LAYER M4 ;
        RECT  194.316 118.656 194.4 118.68 ;
    END
  END ps_line[199]
  PIN ps_line[19]
    DIRECTION OUTPUT ;
    USE SIGNAL ;
    PORT
      LAYER M4 ;
        RECT  194.316 101.376 194.4 101.4 ;
    END
  END ps_line[19]
  PIN ps_line[1]
    DIRECTION OUTPUT ;
    USE SIGNAL ;
    PORT
      LAYER M4 ;
        RECT  194.316 99.648 194.4 99.672 ;
    END
  END ps_line[1]
  PIN ps_line[200]
    DIRECTION OUTPUT ;
    USE SIGNAL ;
    PORT
      LAYER M4 ;
        RECT  194.316 118.752 194.4 118.776 ;
    END
  END ps_line[200]
  PIN ps_line[201]
    DIRECTION OUTPUT ;
    USE SIGNAL ;
    PORT
      LAYER M4 ;
        RECT  194.316 118.848 194.4 118.872 ;
    END
  END ps_line[201]
  PIN ps_line[202]
    DIRECTION OUTPUT ;
    USE SIGNAL ;
    PORT
      LAYER M4 ;
        RECT  194.316 118.944 194.4 118.968 ;
    END
  END ps_line[202]
  PIN ps_line[203]
    DIRECTION OUTPUT ;
    USE SIGNAL ;
    PORT
      LAYER M4 ;
        RECT  194.316 119.04 194.4 119.064 ;
    END
  END ps_line[203]
  PIN ps_line[204]
    DIRECTION OUTPUT ;
    USE SIGNAL ;
    PORT
      LAYER M4 ;
        RECT  194.316 119.136 194.4 119.16 ;
    END
  END ps_line[204]
  PIN ps_line[205]
    DIRECTION OUTPUT ;
    USE SIGNAL ;
    PORT
      LAYER M4 ;
        RECT  194.316 119.232 194.4 119.256 ;
    END
  END ps_line[205]
  PIN ps_line[206]
    DIRECTION OUTPUT ;
    USE SIGNAL ;
    PORT
      LAYER M4 ;
        RECT  194.316 119.328 194.4 119.352 ;
    END
  END ps_line[206]
  PIN ps_line[207]
    DIRECTION OUTPUT ;
    USE SIGNAL ;
    PORT
      LAYER M4 ;
        RECT  194.316 119.424 194.4 119.448 ;
    END
  END ps_line[207]
  PIN ps_line[208]
    DIRECTION OUTPUT ;
    USE SIGNAL ;
    PORT
      LAYER M4 ;
        RECT  194.316 119.52 194.4 119.544 ;
    END
  END ps_line[208]
  PIN ps_line[209]
    DIRECTION OUTPUT ;
    USE SIGNAL ;
    PORT
      LAYER M4 ;
        RECT  194.316 119.616 194.4 119.64 ;
    END
  END ps_line[209]
  PIN ps_line[20]
    DIRECTION OUTPUT ;
    USE SIGNAL ;
    PORT
      LAYER M4 ;
        RECT  194.316 101.472 194.4 101.496 ;
    END
  END ps_line[20]
  PIN ps_line[210]
    DIRECTION OUTPUT ;
    USE SIGNAL ;
    PORT
      LAYER M4 ;
        RECT  194.316 119.712 194.4 119.736 ;
    END
  END ps_line[210]
  PIN ps_line[211]
    DIRECTION OUTPUT ;
    USE SIGNAL ;
    PORT
      LAYER M4 ;
        RECT  194.316 119.808 194.4 119.832 ;
    END
  END ps_line[211]
  PIN ps_line[212]
    DIRECTION OUTPUT ;
    USE SIGNAL ;
    PORT
      LAYER M4 ;
        RECT  194.316 119.904 194.4 119.928 ;
    END
  END ps_line[212]
  PIN ps_line[213]
    DIRECTION OUTPUT ;
    USE SIGNAL ;
    PORT
      LAYER M4 ;
        RECT  194.316 120 194.4 120.024 ;
    END
  END ps_line[213]
  PIN ps_line[214]
    DIRECTION OUTPUT ;
    USE SIGNAL ;
    PORT
      LAYER M4 ;
        RECT  194.316 120.096 194.4 120.12 ;
    END
  END ps_line[214]
  PIN ps_line[215]
    DIRECTION OUTPUT ;
    USE SIGNAL ;
    PORT
      LAYER M4 ;
        RECT  194.316 120.192 194.4 120.216 ;
    END
  END ps_line[215]
  PIN ps_line[216]
    DIRECTION OUTPUT ;
    USE SIGNAL ;
    PORT
      LAYER M4 ;
        RECT  194.316 120.288 194.4 120.312 ;
    END
  END ps_line[216]
  PIN ps_line[217]
    DIRECTION OUTPUT ;
    USE SIGNAL ;
    PORT
      LAYER M4 ;
        RECT  194.316 120.384 194.4 120.408 ;
    END
  END ps_line[217]
  PIN ps_line[218]
    DIRECTION OUTPUT ;
    USE SIGNAL ;
    PORT
      LAYER M4 ;
        RECT  194.316 120.48 194.4 120.504 ;
    END
  END ps_line[218]
  PIN ps_line[219]
    DIRECTION OUTPUT ;
    USE SIGNAL ;
    PORT
      LAYER M4 ;
        RECT  194.316 120.576 194.4 120.6 ;
    END
  END ps_line[219]
  PIN ps_line[21]
    DIRECTION OUTPUT ;
    USE SIGNAL ;
    PORT
      LAYER M4 ;
        RECT  194.316 101.568 194.4 101.592 ;
    END
  END ps_line[21]
  PIN ps_line[220]
    DIRECTION OUTPUT ;
    USE SIGNAL ;
    PORT
      LAYER M4 ;
        RECT  194.316 120.672 194.4 120.696 ;
    END
  END ps_line[220]
  PIN ps_line[221]
    DIRECTION OUTPUT ;
    USE SIGNAL ;
    PORT
      LAYER M4 ;
        RECT  194.316 120.768 194.4 120.792 ;
    END
  END ps_line[221]
  PIN ps_line[222]
    DIRECTION OUTPUT ;
    USE SIGNAL ;
    PORT
      LAYER M4 ;
        RECT  194.316 120.864 194.4 120.888 ;
    END
  END ps_line[222]
  PIN ps_line[223]
    DIRECTION OUTPUT ;
    USE SIGNAL ;
    PORT
      LAYER M4 ;
        RECT  194.316 120.96 194.4 120.984 ;
    END
  END ps_line[223]
  PIN ps_line[224]
    DIRECTION OUTPUT ;
    USE SIGNAL ;
    PORT
      LAYER M4 ;
        RECT  194.316 121.056 194.4 121.08 ;
    END
  END ps_line[224]
  PIN ps_line[225]
    DIRECTION OUTPUT ;
    USE SIGNAL ;
    PORT
      LAYER M4 ;
        RECT  194.316 121.152 194.4 121.176 ;
    END
  END ps_line[225]
  PIN ps_line[226]
    DIRECTION OUTPUT ;
    USE SIGNAL ;
    PORT
      LAYER M4 ;
        RECT  194.316 121.248 194.4 121.272 ;
    END
  END ps_line[226]
  PIN ps_line[227]
    DIRECTION OUTPUT ;
    USE SIGNAL ;
    PORT
      LAYER M4 ;
        RECT  194.316 121.344 194.4 121.368 ;
    END
  END ps_line[227]
  PIN ps_line[228]
    DIRECTION OUTPUT ;
    USE SIGNAL ;
    PORT
      LAYER M4 ;
        RECT  194.316 121.44 194.4 121.464 ;
    END
  END ps_line[228]
  PIN ps_line[229]
    DIRECTION OUTPUT ;
    USE SIGNAL ;
    PORT
      LAYER M4 ;
        RECT  194.316 121.536 194.4 121.56 ;
    END
  END ps_line[229]
  PIN ps_line[22]
    DIRECTION OUTPUT ;
    USE SIGNAL ;
    PORT
      LAYER M4 ;
        RECT  194.316 101.664 194.4 101.688 ;
    END
  END ps_line[22]
  PIN ps_line[230]
    DIRECTION OUTPUT ;
    USE SIGNAL ;
    PORT
      LAYER M4 ;
        RECT  194.316 121.632 194.4 121.656 ;
    END
  END ps_line[230]
  PIN ps_line[231]
    DIRECTION OUTPUT ;
    USE SIGNAL ;
    PORT
      LAYER M4 ;
        RECT  194.316 121.728 194.4 121.752 ;
    END
  END ps_line[231]
  PIN ps_line[232]
    DIRECTION OUTPUT ;
    USE SIGNAL ;
    PORT
      LAYER M4 ;
        RECT  194.316 121.824 194.4 121.848 ;
    END
  END ps_line[232]
  PIN ps_line[233]
    DIRECTION OUTPUT ;
    USE SIGNAL ;
    PORT
      LAYER M4 ;
        RECT  194.316 121.92 194.4 121.944 ;
    END
  END ps_line[233]
  PIN ps_line[234]
    DIRECTION OUTPUT ;
    USE SIGNAL ;
    PORT
      LAYER M4 ;
        RECT  194.316 122.016 194.4 122.04 ;
    END
  END ps_line[234]
  PIN ps_line[235]
    DIRECTION OUTPUT ;
    USE SIGNAL ;
    PORT
      LAYER M4 ;
        RECT  194.316 122.112 194.4 122.136 ;
    END
  END ps_line[235]
  PIN ps_line[236]
    DIRECTION OUTPUT ;
    USE SIGNAL ;
    PORT
      LAYER M4 ;
        RECT  194.316 122.208 194.4 122.232 ;
    END
  END ps_line[236]
  PIN ps_line[237]
    DIRECTION OUTPUT ;
    USE SIGNAL ;
    PORT
      LAYER M4 ;
        RECT  194.316 122.304 194.4 122.328 ;
    END
  END ps_line[237]
  PIN ps_line[238]
    DIRECTION OUTPUT ;
    USE SIGNAL ;
    PORT
      LAYER M4 ;
        RECT  194.316 122.4 194.4 122.424 ;
    END
  END ps_line[238]
  PIN ps_line[239]
    DIRECTION OUTPUT ;
    USE SIGNAL ;
    PORT
      LAYER M4 ;
        RECT  194.316 122.496 194.4 122.52 ;
    END
  END ps_line[239]
  PIN ps_line[23]
    DIRECTION OUTPUT ;
    USE SIGNAL ;
    PORT
      LAYER M4 ;
        RECT  194.316 101.76 194.4 101.784 ;
    END
  END ps_line[23]
  PIN ps_line[240]
    DIRECTION OUTPUT ;
    USE SIGNAL ;
    PORT
      LAYER M4 ;
        RECT  194.316 122.592 194.4 122.616 ;
    END
  END ps_line[240]
  PIN ps_line[241]
    DIRECTION OUTPUT ;
    USE SIGNAL ;
    PORT
      LAYER M4 ;
        RECT  194.316 122.688 194.4 122.712 ;
    END
  END ps_line[241]
  PIN ps_line[242]
    DIRECTION OUTPUT ;
    USE SIGNAL ;
    PORT
      LAYER M4 ;
        RECT  194.316 122.784 194.4 122.808 ;
    END
  END ps_line[242]
  PIN ps_line[243]
    DIRECTION OUTPUT ;
    USE SIGNAL ;
    PORT
      LAYER M4 ;
        RECT  194.316 122.88 194.4 122.904 ;
    END
  END ps_line[243]
  PIN ps_line[244]
    DIRECTION OUTPUT ;
    USE SIGNAL ;
    PORT
      LAYER M4 ;
        RECT  194.316 122.976 194.4 123 ;
    END
  END ps_line[244]
  PIN ps_line[245]
    DIRECTION OUTPUT ;
    USE SIGNAL ;
    PORT
      LAYER M4 ;
        RECT  194.316 123.072 194.4 123.096 ;
    END
  END ps_line[245]
  PIN ps_line[246]
    DIRECTION OUTPUT ;
    USE SIGNAL ;
    PORT
      LAYER M4 ;
        RECT  194.316 123.168 194.4 123.192 ;
    END
  END ps_line[246]
  PIN ps_line[247]
    DIRECTION OUTPUT ;
    USE SIGNAL ;
    PORT
      LAYER M4 ;
        RECT  194.316 123.264 194.4 123.288 ;
    END
  END ps_line[247]
  PIN ps_line[248]
    DIRECTION OUTPUT ;
    USE SIGNAL ;
    PORT
      LAYER M4 ;
        RECT  194.316 123.36 194.4 123.384 ;
    END
  END ps_line[248]
  PIN ps_line[249]
    DIRECTION OUTPUT ;
    USE SIGNAL ;
    PORT
      LAYER M4 ;
        RECT  194.316 123.456 194.4 123.48 ;
    END
  END ps_line[249]
  PIN ps_line[24]
    DIRECTION OUTPUT ;
    USE SIGNAL ;
    PORT
      LAYER M4 ;
        RECT  194.316 101.856 194.4 101.88 ;
    END
  END ps_line[24]
  PIN ps_line[250]
    DIRECTION OUTPUT ;
    USE SIGNAL ;
    PORT
      LAYER M4 ;
        RECT  194.316 123.552 194.4 123.576 ;
    END
  END ps_line[250]
  PIN ps_line[251]
    DIRECTION OUTPUT ;
    USE SIGNAL ;
    PORT
      LAYER M4 ;
        RECT  194.316 123.648 194.4 123.672 ;
    END
  END ps_line[251]
  PIN ps_line[252]
    DIRECTION OUTPUT ;
    USE SIGNAL ;
    PORT
      LAYER M4 ;
        RECT  194.316 123.744 194.4 123.768 ;
    END
  END ps_line[252]
  PIN ps_line[253]
    DIRECTION OUTPUT ;
    USE SIGNAL ;
    PORT
      LAYER M4 ;
        RECT  194.316 123.84 194.4 123.864 ;
    END
  END ps_line[253]
  PIN ps_line[254]
    DIRECTION OUTPUT ;
    USE SIGNAL ;
    PORT
      LAYER M4 ;
        RECT  194.316 123.936 194.4 123.96 ;
    END
  END ps_line[254]
  PIN ps_line[255]
    DIRECTION OUTPUT ;
    USE SIGNAL ;
    PORT
      LAYER M4 ;
        RECT  194.316 124.032 194.4 124.056 ;
    END
  END ps_line[255]
  PIN ps_line[256]
    DIRECTION OUTPUT ;
    USE SIGNAL ;
    PORT
      LAYER M4 ;
        RECT  194.316 124.128 194.4 124.152 ;
    END
  END ps_line[256]
  PIN ps_line[257]
    DIRECTION OUTPUT ;
    USE SIGNAL ;
    PORT
      LAYER M4 ;
        RECT  194.316 124.224 194.4 124.248 ;
    END
  END ps_line[257]
  PIN ps_line[258]
    DIRECTION OUTPUT ;
    USE SIGNAL ;
    PORT
      LAYER M4 ;
        RECT  194.316 124.32 194.4 124.344 ;
    END
  END ps_line[258]
  PIN ps_line[259]
    DIRECTION OUTPUT ;
    USE SIGNAL ;
    PORT
      LAYER M4 ;
        RECT  194.316 124.416 194.4 124.44 ;
    END
  END ps_line[259]
  PIN ps_line[25]
    DIRECTION OUTPUT ;
    USE SIGNAL ;
    PORT
      LAYER M4 ;
        RECT  194.316 101.952 194.4 101.976 ;
    END
  END ps_line[25]
  PIN ps_line[260]
    DIRECTION OUTPUT ;
    USE SIGNAL ;
    PORT
      LAYER M4 ;
        RECT  194.316 124.512 194.4 124.536 ;
    END
  END ps_line[260]
  PIN ps_line[261]
    DIRECTION OUTPUT ;
    USE SIGNAL ;
    PORT
      LAYER M4 ;
        RECT  194.316 124.608 194.4 124.632 ;
    END
  END ps_line[261]
  PIN ps_line[262]
    DIRECTION OUTPUT ;
    USE SIGNAL ;
    PORT
      LAYER M4 ;
        RECT  194.316 124.704 194.4 124.728 ;
    END
  END ps_line[262]
  PIN ps_line[263]
    DIRECTION OUTPUT ;
    USE SIGNAL ;
    PORT
      LAYER M4 ;
        RECT  194.316 124.8 194.4 124.824 ;
    END
  END ps_line[263]
  PIN ps_line[264]
    DIRECTION OUTPUT ;
    USE SIGNAL ;
    PORT
      LAYER M4 ;
        RECT  194.316 124.896 194.4 124.92 ;
    END
  END ps_line[264]
  PIN ps_line[265]
    DIRECTION OUTPUT ;
    USE SIGNAL ;
    PORT
      LAYER M4 ;
        RECT  194.316 124.992 194.4 125.016 ;
    END
  END ps_line[265]
  PIN ps_line[266]
    DIRECTION OUTPUT ;
    USE SIGNAL ;
    PORT
      LAYER M4 ;
        RECT  194.316 125.088 194.4 125.112 ;
    END
  END ps_line[266]
  PIN ps_line[267]
    DIRECTION OUTPUT ;
    USE SIGNAL ;
    PORT
      LAYER M4 ;
        RECT  194.316 125.184 194.4 125.208 ;
    END
  END ps_line[267]
  PIN ps_line[268]
    DIRECTION OUTPUT ;
    USE SIGNAL ;
    PORT
      LAYER M4 ;
        RECT  194.316 125.28 194.4 125.304 ;
    END
  END ps_line[268]
  PIN ps_line[269]
    DIRECTION OUTPUT ;
    USE SIGNAL ;
    PORT
      LAYER M4 ;
        RECT  194.316 125.376 194.4 125.4 ;
    END
  END ps_line[269]
  PIN ps_line[26]
    DIRECTION OUTPUT ;
    USE SIGNAL ;
    PORT
      LAYER M4 ;
        RECT  194.316 102.048 194.4 102.072 ;
    END
  END ps_line[26]
  PIN ps_line[270]
    DIRECTION OUTPUT ;
    USE SIGNAL ;
    PORT
      LAYER M4 ;
        RECT  194.316 125.472 194.4 125.496 ;
    END
  END ps_line[270]
  PIN ps_line[271]
    DIRECTION OUTPUT ;
    USE SIGNAL ;
    PORT
      LAYER M4 ;
        RECT  194.316 125.568 194.4 125.592 ;
    END
  END ps_line[271]
  PIN ps_line[272]
    DIRECTION OUTPUT ;
    USE SIGNAL ;
    PORT
      LAYER M4 ;
        RECT  194.316 125.664 194.4 125.688 ;
    END
  END ps_line[272]
  PIN ps_line[273]
    DIRECTION OUTPUT ;
    USE SIGNAL ;
    PORT
      LAYER M4 ;
        RECT  194.316 125.76 194.4 125.784 ;
    END
  END ps_line[273]
  PIN ps_line[274]
    DIRECTION OUTPUT ;
    USE SIGNAL ;
    PORT
      LAYER M4 ;
        RECT  194.316 125.856 194.4 125.88 ;
    END
  END ps_line[274]
  PIN ps_line[275]
    DIRECTION OUTPUT ;
    USE SIGNAL ;
    PORT
      LAYER M4 ;
        RECT  194.316 125.952 194.4 125.976 ;
    END
  END ps_line[275]
  PIN ps_line[276]
    DIRECTION OUTPUT ;
    USE SIGNAL ;
    PORT
      LAYER M4 ;
        RECT  194.316 126.048 194.4 126.072 ;
    END
  END ps_line[276]
  PIN ps_line[277]
    DIRECTION OUTPUT ;
    USE SIGNAL ;
    PORT
      LAYER M4 ;
        RECT  194.316 126.144 194.4 126.168 ;
    END
  END ps_line[277]
  PIN ps_line[278]
    DIRECTION OUTPUT ;
    USE SIGNAL ;
    PORT
      LAYER M4 ;
        RECT  194.316 126.24 194.4 126.264 ;
    END
  END ps_line[278]
  PIN ps_line[279]
    DIRECTION OUTPUT ;
    USE SIGNAL ;
    PORT
      LAYER M4 ;
        RECT  194.316 126.336 194.4 126.36 ;
    END
  END ps_line[279]
  PIN ps_line[27]
    DIRECTION OUTPUT ;
    USE SIGNAL ;
    PORT
      LAYER M4 ;
        RECT  194.316 102.144 194.4 102.168 ;
    END
  END ps_line[27]
  PIN ps_line[280]
    DIRECTION OUTPUT ;
    USE SIGNAL ;
    PORT
      LAYER M4 ;
        RECT  194.316 126.432 194.4 126.456 ;
    END
  END ps_line[280]
  PIN ps_line[281]
    DIRECTION OUTPUT ;
    USE SIGNAL ;
    PORT
      LAYER M4 ;
        RECT  194.316 126.528 194.4 126.552 ;
    END
  END ps_line[281]
  PIN ps_line[282]
    DIRECTION OUTPUT ;
    USE SIGNAL ;
    PORT
      LAYER M4 ;
        RECT  194.316 126.624 194.4 126.648 ;
    END
  END ps_line[282]
  PIN ps_line[283]
    DIRECTION OUTPUT ;
    USE SIGNAL ;
    PORT
      LAYER M4 ;
        RECT  194.316 126.72 194.4 126.744 ;
    END
  END ps_line[283]
  PIN ps_line[284]
    DIRECTION OUTPUT ;
    USE SIGNAL ;
    PORT
      LAYER M4 ;
        RECT  194.316 126.816 194.4 126.84 ;
    END
  END ps_line[284]
  PIN ps_line[285]
    DIRECTION OUTPUT ;
    USE SIGNAL ;
    PORT
      LAYER M4 ;
        RECT  194.316 126.912 194.4 126.936 ;
    END
  END ps_line[285]
  PIN ps_line[286]
    DIRECTION OUTPUT ;
    USE SIGNAL ;
    PORT
      LAYER M4 ;
        RECT  194.316 127.008 194.4 127.032 ;
    END
  END ps_line[286]
  PIN ps_line[287]
    DIRECTION OUTPUT ;
    USE SIGNAL ;
    PORT
      LAYER M4 ;
        RECT  194.316 127.104 194.4 127.128 ;
    END
  END ps_line[287]
  PIN ps_line[288]
    DIRECTION OUTPUT ;
    USE SIGNAL ;
    PORT
      LAYER M4 ;
        RECT  194.316 127.2 194.4 127.224 ;
    END
  END ps_line[288]
  PIN ps_line[289]
    DIRECTION OUTPUT ;
    USE SIGNAL ;
    PORT
      LAYER M4 ;
        RECT  194.316 127.296 194.4 127.32 ;
    END
  END ps_line[289]
  PIN ps_line[28]
    DIRECTION OUTPUT ;
    USE SIGNAL ;
    PORT
      LAYER M4 ;
        RECT  194.316 102.24 194.4 102.264 ;
    END
  END ps_line[28]
  PIN ps_line[290]
    DIRECTION OUTPUT ;
    USE SIGNAL ;
    PORT
      LAYER M4 ;
        RECT  194.316 127.392 194.4 127.416 ;
    END
  END ps_line[290]
  PIN ps_line[291]
    DIRECTION OUTPUT ;
    USE SIGNAL ;
    PORT
      LAYER M4 ;
        RECT  194.316 127.488 194.4 127.512 ;
    END
  END ps_line[291]
  PIN ps_line[292]
    DIRECTION OUTPUT ;
    USE SIGNAL ;
    PORT
      LAYER M4 ;
        RECT  194.316 127.584 194.4 127.608 ;
    END
  END ps_line[292]
  PIN ps_line[293]
    DIRECTION OUTPUT ;
    USE SIGNAL ;
    PORT
      LAYER M4 ;
        RECT  194.316 127.68 194.4 127.704 ;
    END
  END ps_line[293]
  PIN ps_line[294]
    DIRECTION OUTPUT ;
    USE SIGNAL ;
    PORT
      LAYER M4 ;
        RECT  194.316 127.776 194.4 127.8 ;
    END
  END ps_line[294]
  PIN ps_line[295]
    DIRECTION OUTPUT ;
    USE SIGNAL ;
    PORT
      LAYER M4 ;
        RECT  194.316 127.872 194.4 127.896 ;
    END
  END ps_line[295]
  PIN ps_line[296]
    DIRECTION OUTPUT ;
    USE SIGNAL ;
    PORT
      LAYER M4 ;
        RECT  194.316 127.968 194.4 127.992 ;
    END
  END ps_line[296]
  PIN ps_line[297]
    DIRECTION OUTPUT ;
    USE SIGNAL ;
    PORT
      LAYER M4 ;
        RECT  194.316 128.064 194.4 128.088 ;
    END
  END ps_line[297]
  PIN ps_line[298]
    DIRECTION OUTPUT ;
    USE SIGNAL ;
    PORT
      LAYER M4 ;
        RECT  194.316 128.16 194.4 128.184 ;
    END
  END ps_line[298]
  PIN ps_line[299]
    DIRECTION OUTPUT ;
    USE SIGNAL ;
    PORT
      LAYER M4 ;
        RECT  194.316 128.256 194.4 128.28 ;
    END
  END ps_line[299]
  PIN ps_line[29]
    DIRECTION OUTPUT ;
    USE SIGNAL ;
    PORT
      LAYER M4 ;
        RECT  194.316 102.336 194.4 102.36 ;
    END
  END ps_line[29]
  PIN ps_line[2]
    DIRECTION OUTPUT ;
    USE SIGNAL ;
    PORT
      LAYER M4 ;
        RECT  194.316 99.744 194.4 99.768 ;
    END
  END ps_line[2]
  PIN ps_line[300]
    DIRECTION OUTPUT ;
    USE SIGNAL ;
    PORT
      LAYER M4 ;
        RECT  194.316 128.352 194.4 128.376 ;
    END
  END ps_line[300]
  PIN ps_line[301]
    DIRECTION OUTPUT ;
    USE SIGNAL ;
    PORT
      LAYER M4 ;
        RECT  194.316 128.448 194.4 128.472 ;
    END
  END ps_line[301]
  PIN ps_line[302]
    DIRECTION OUTPUT ;
    USE SIGNAL ;
    PORT
      LAYER M4 ;
        RECT  194.316 128.544 194.4 128.568 ;
    END
  END ps_line[302]
  PIN ps_line[303]
    DIRECTION OUTPUT ;
    USE SIGNAL ;
    PORT
      LAYER M4 ;
        RECT  194.316 128.64 194.4 128.664 ;
    END
  END ps_line[303]
  PIN ps_line[304]
    DIRECTION OUTPUT ;
    USE SIGNAL ;
    PORT
      LAYER M4 ;
        RECT  194.316 128.736 194.4 128.76 ;
    END
  END ps_line[304]
  PIN ps_line[305]
    DIRECTION OUTPUT ;
    USE SIGNAL ;
    PORT
      LAYER M4 ;
        RECT  194.316 128.832 194.4 128.856 ;
    END
  END ps_line[305]
  PIN ps_line[306]
    DIRECTION OUTPUT ;
    USE SIGNAL ;
    PORT
      LAYER M4 ;
        RECT  194.316 128.928 194.4 128.952 ;
    END
  END ps_line[306]
  PIN ps_line[307]
    DIRECTION OUTPUT ;
    USE SIGNAL ;
    PORT
      LAYER M4 ;
        RECT  194.316 129.024 194.4 129.048 ;
    END
  END ps_line[307]
  PIN ps_line[308]
    DIRECTION OUTPUT ;
    USE SIGNAL ;
    PORT
      LAYER M4 ;
        RECT  194.316 129.12 194.4 129.144 ;
    END
  END ps_line[308]
  PIN ps_line[309]
    DIRECTION OUTPUT ;
    USE SIGNAL ;
    PORT
      LAYER M4 ;
        RECT  194.316 129.216 194.4 129.24 ;
    END
  END ps_line[309]
  PIN ps_line[30]
    DIRECTION OUTPUT ;
    USE SIGNAL ;
    PORT
      LAYER M4 ;
        RECT  194.316 102.432 194.4 102.456 ;
    END
  END ps_line[30]
  PIN ps_line[310]
    DIRECTION OUTPUT ;
    USE SIGNAL ;
    PORT
      LAYER M4 ;
        RECT  194.316 129.312 194.4 129.336 ;
    END
  END ps_line[310]
  PIN ps_line[311]
    DIRECTION OUTPUT ;
    USE SIGNAL ;
    PORT
      LAYER M4 ;
        RECT  194.316 129.408 194.4 129.432 ;
    END
  END ps_line[311]
  PIN ps_line[312]
    DIRECTION OUTPUT ;
    USE SIGNAL ;
    PORT
      LAYER M4 ;
        RECT  194.316 129.504 194.4 129.528 ;
    END
  END ps_line[312]
  PIN ps_line[313]
    DIRECTION OUTPUT ;
    USE SIGNAL ;
    PORT
      LAYER M4 ;
        RECT  194.316 129.6 194.4 129.624 ;
    END
  END ps_line[313]
  PIN ps_line[314]
    DIRECTION OUTPUT ;
    USE SIGNAL ;
    PORT
      LAYER M4 ;
        RECT  194.316 129.696 194.4 129.72 ;
    END
  END ps_line[314]
  PIN ps_line[315]
    DIRECTION OUTPUT ;
    USE SIGNAL ;
    PORT
      LAYER M4 ;
        RECT  194.316 129.792 194.4 129.816 ;
    END
  END ps_line[315]
  PIN ps_line[316]
    DIRECTION OUTPUT ;
    USE SIGNAL ;
    PORT
      LAYER M4 ;
        RECT  194.316 129.888 194.4 129.912 ;
    END
  END ps_line[316]
  PIN ps_line[317]
    DIRECTION OUTPUT ;
    USE SIGNAL ;
    PORT
      LAYER M4 ;
        RECT  194.316 129.984 194.4 130.008 ;
    END
  END ps_line[317]
  PIN ps_line[318]
    DIRECTION OUTPUT ;
    USE SIGNAL ;
    PORT
      LAYER M4 ;
        RECT  194.316 130.08 194.4 130.104 ;
    END
  END ps_line[318]
  PIN ps_line[319]
    DIRECTION OUTPUT ;
    USE SIGNAL ;
    PORT
      LAYER M4 ;
        RECT  194.316 130.176 194.4 130.2 ;
    END
  END ps_line[319]
  PIN ps_line[31]
    DIRECTION OUTPUT ;
    USE SIGNAL ;
    PORT
      LAYER M4 ;
        RECT  194.316 102.528 194.4 102.552 ;
    END
  END ps_line[31]
  PIN ps_line[320]
    DIRECTION OUTPUT ;
    USE SIGNAL ;
    PORT
      LAYER M4 ;
        RECT  194.316 130.272 194.4 130.296 ;
    END
  END ps_line[320]
  PIN ps_line[321]
    DIRECTION OUTPUT ;
    USE SIGNAL ;
    PORT
      LAYER M4 ;
        RECT  194.316 130.368 194.4 130.392 ;
    END
  END ps_line[321]
  PIN ps_line[322]
    DIRECTION OUTPUT ;
    USE SIGNAL ;
    PORT
      LAYER M4 ;
        RECT  194.316 130.464 194.4 130.488 ;
    END
  END ps_line[322]
  PIN ps_line[323]
    DIRECTION OUTPUT ;
    USE SIGNAL ;
    PORT
      LAYER M4 ;
        RECT  194.316 130.56 194.4 130.584 ;
    END
  END ps_line[323]
  PIN ps_line[324]
    DIRECTION OUTPUT ;
    USE SIGNAL ;
    PORT
      LAYER M4 ;
        RECT  194.316 130.656 194.4 130.68 ;
    END
  END ps_line[324]
  PIN ps_line[325]
    DIRECTION OUTPUT ;
    USE SIGNAL ;
    PORT
      LAYER M4 ;
        RECT  194.316 130.752 194.4 130.776 ;
    END
  END ps_line[325]
  PIN ps_line[326]
    DIRECTION OUTPUT ;
    USE SIGNAL ;
    PORT
      LAYER M4 ;
        RECT  194.316 130.848 194.4 130.872 ;
    END
  END ps_line[326]
  PIN ps_line[327]
    DIRECTION OUTPUT ;
    USE SIGNAL ;
    PORT
      LAYER M4 ;
        RECT  194.316 130.944 194.4 130.968 ;
    END
  END ps_line[327]
  PIN ps_line[328]
    DIRECTION OUTPUT ;
    USE SIGNAL ;
    PORT
      LAYER M4 ;
        RECT  194.316 131.04 194.4 131.064 ;
    END
  END ps_line[328]
  PIN ps_line[329]
    DIRECTION OUTPUT ;
    USE SIGNAL ;
    PORT
      LAYER M4 ;
        RECT  194.316 131.136 194.4 131.16 ;
    END
  END ps_line[329]
  PIN ps_line[32]
    DIRECTION OUTPUT ;
    USE SIGNAL ;
    PORT
      LAYER M4 ;
        RECT  194.316 102.624 194.4 102.648 ;
    END
  END ps_line[32]
  PIN ps_line[330]
    DIRECTION OUTPUT ;
    USE SIGNAL ;
    PORT
      LAYER M4 ;
        RECT  194.316 131.232 194.4 131.256 ;
    END
  END ps_line[330]
  PIN ps_line[331]
    DIRECTION OUTPUT ;
    USE SIGNAL ;
    PORT
      LAYER M4 ;
        RECT  194.316 131.328 194.4 131.352 ;
    END
  END ps_line[331]
  PIN ps_line[332]
    DIRECTION OUTPUT ;
    USE SIGNAL ;
    PORT
      LAYER M4 ;
        RECT  194.316 131.424 194.4 131.448 ;
    END
  END ps_line[332]
  PIN ps_line[333]
    DIRECTION OUTPUT ;
    USE SIGNAL ;
    PORT
      LAYER M4 ;
        RECT  194.316 131.52 194.4 131.544 ;
    END
  END ps_line[333]
  PIN ps_line[334]
    DIRECTION OUTPUT ;
    USE SIGNAL ;
    PORT
      LAYER M4 ;
        RECT  194.316 131.616 194.4 131.64 ;
    END
  END ps_line[334]
  PIN ps_line[335]
    DIRECTION OUTPUT ;
    USE SIGNAL ;
    PORT
      LAYER M4 ;
        RECT  194.316 131.712 194.4 131.736 ;
    END
  END ps_line[335]
  PIN ps_line[336]
    DIRECTION OUTPUT ;
    USE SIGNAL ;
    PORT
      LAYER M4 ;
        RECT  194.316 131.808 194.4 131.832 ;
    END
  END ps_line[336]
  PIN ps_line[337]
    DIRECTION OUTPUT ;
    USE SIGNAL ;
    PORT
      LAYER M4 ;
        RECT  194.316 131.904 194.4 131.928 ;
    END
  END ps_line[337]
  PIN ps_line[338]
    DIRECTION OUTPUT ;
    USE SIGNAL ;
    PORT
      LAYER M4 ;
        RECT  194.316 132 194.4 132.024 ;
    END
  END ps_line[338]
  PIN ps_line[339]
    DIRECTION OUTPUT ;
    USE SIGNAL ;
    PORT
      LAYER M4 ;
        RECT  194.316 132.096 194.4 132.12 ;
    END
  END ps_line[339]
  PIN ps_line[33]
    DIRECTION OUTPUT ;
    USE SIGNAL ;
    PORT
      LAYER M4 ;
        RECT  194.316 102.72 194.4 102.744 ;
    END
  END ps_line[33]
  PIN ps_line[340]
    DIRECTION OUTPUT ;
    USE SIGNAL ;
    PORT
      LAYER M4 ;
        RECT  194.316 132.192 194.4 132.216 ;
    END
  END ps_line[340]
  PIN ps_line[341]
    DIRECTION OUTPUT ;
    USE SIGNAL ;
    PORT
      LAYER M4 ;
        RECT  194.316 132.288 194.4 132.312 ;
    END
  END ps_line[341]
  PIN ps_line[342]
    DIRECTION OUTPUT ;
    USE SIGNAL ;
    PORT
      LAYER M4 ;
        RECT  194.316 132.384 194.4 132.408 ;
    END
  END ps_line[342]
  PIN ps_line[343]
    DIRECTION OUTPUT ;
    USE SIGNAL ;
    PORT
      LAYER M4 ;
        RECT  194.316 132.48 194.4 132.504 ;
    END
  END ps_line[343]
  PIN ps_line[344]
    DIRECTION OUTPUT ;
    USE SIGNAL ;
    PORT
      LAYER M4 ;
        RECT  194.316 132.576 194.4 132.6 ;
    END
  END ps_line[344]
  PIN ps_line[345]
    DIRECTION OUTPUT ;
    USE SIGNAL ;
    PORT
      LAYER M4 ;
        RECT  194.316 132.672 194.4 132.696 ;
    END
  END ps_line[345]
  PIN ps_line[346]
    DIRECTION OUTPUT ;
    USE SIGNAL ;
    PORT
      LAYER M4 ;
        RECT  194.316 132.768 194.4 132.792 ;
    END
  END ps_line[346]
  PIN ps_line[347]
    DIRECTION OUTPUT ;
    USE SIGNAL ;
    PORT
      LAYER M4 ;
        RECT  194.316 132.864 194.4 132.888 ;
    END
  END ps_line[347]
  PIN ps_line[348]
    DIRECTION OUTPUT ;
    USE SIGNAL ;
    PORT
      LAYER M4 ;
        RECT  194.316 132.96 194.4 132.984 ;
    END
  END ps_line[348]
  PIN ps_line[349]
    DIRECTION OUTPUT ;
    USE SIGNAL ;
    PORT
      LAYER M4 ;
        RECT  194.316 133.056 194.4 133.08 ;
    END
  END ps_line[349]
  PIN ps_line[34]
    DIRECTION OUTPUT ;
    USE SIGNAL ;
    PORT
      LAYER M4 ;
        RECT  194.316 102.816 194.4 102.84 ;
    END
  END ps_line[34]
  PIN ps_line[350]
    DIRECTION OUTPUT ;
    USE SIGNAL ;
    PORT
      LAYER M4 ;
        RECT  194.316 133.152 194.4 133.176 ;
    END
  END ps_line[350]
  PIN ps_line[351]
    DIRECTION OUTPUT ;
    USE SIGNAL ;
    PORT
      LAYER M4 ;
        RECT  194.316 133.248 194.4 133.272 ;
    END
  END ps_line[351]
  PIN ps_line[352]
    DIRECTION OUTPUT ;
    USE SIGNAL ;
    PORT
      LAYER M4 ;
        RECT  194.316 133.344 194.4 133.368 ;
    END
  END ps_line[352]
  PIN ps_line[353]
    DIRECTION OUTPUT ;
    USE SIGNAL ;
    PORT
      LAYER M4 ;
        RECT  194.316 133.44 194.4 133.464 ;
    END
  END ps_line[353]
  PIN ps_line[354]
    DIRECTION OUTPUT ;
    USE SIGNAL ;
    PORT
      LAYER M4 ;
        RECT  194.316 133.536 194.4 133.56 ;
    END
  END ps_line[354]
  PIN ps_line[355]
    DIRECTION OUTPUT ;
    USE SIGNAL ;
    PORT
      LAYER M4 ;
        RECT  194.316 133.632 194.4 133.656 ;
    END
  END ps_line[355]
  PIN ps_line[356]
    DIRECTION OUTPUT ;
    USE SIGNAL ;
    PORT
      LAYER M4 ;
        RECT  194.316 133.728 194.4 133.752 ;
    END
  END ps_line[356]
  PIN ps_line[357]
    DIRECTION OUTPUT ;
    USE SIGNAL ;
    PORT
      LAYER M4 ;
        RECT  194.316 133.824 194.4 133.848 ;
    END
  END ps_line[357]
  PIN ps_line[358]
    DIRECTION OUTPUT ;
    USE SIGNAL ;
    PORT
      LAYER M4 ;
        RECT  194.316 133.92 194.4 133.944 ;
    END
  END ps_line[358]
  PIN ps_line[359]
    DIRECTION OUTPUT ;
    USE SIGNAL ;
    PORT
      LAYER M4 ;
        RECT  194.316 134.016 194.4 134.04 ;
    END
  END ps_line[359]
  PIN ps_line[35]
    DIRECTION OUTPUT ;
    USE SIGNAL ;
    PORT
      LAYER M4 ;
        RECT  194.316 102.912 194.4 102.936 ;
    END
  END ps_line[35]
  PIN ps_line[360]
    DIRECTION OUTPUT ;
    USE SIGNAL ;
    PORT
      LAYER M4 ;
        RECT  194.316 134.112 194.4 134.136 ;
    END
  END ps_line[360]
  PIN ps_line[361]
    DIRECTION OUTPUT ;
    USE SIGNAL ;
    PORT
      LAYER M4 ;
        RECT  194.316 134.208 194.4 134.232 ;
    END
  END ps_line[361]
  PIN ps_line[362]
    DIRECTION OUTPUT ;
    USE SIGNAL ;
    PORT
      LAYER M4 ;
        RECT  194.316 134.304 194.4 134.328 ;
    END
  END ps_line[362]
  PIN ps_line[363]
    DIRECTION OUTPUT ;
    USE SIGNAL ;
    PORT
      LAYER M4 ;
        RECT  194.316 134.4 194.4 134.424 ;
    END
  END ps_line[363]
  PIN ps_line[364]
    DIRECTION OUTPUT ;
    USE SIGNAL ;
    PORT
      LAYER M4 ;
        RECT  194.316 134.496 194.4 134.52 ;
    END
  END ps_line[364]
  PIN ps_line[365]
    DIRECTION OUTPUT ;
    USE SIGNAL ;
    PORT
      LAYER M4 ;
        RECT  194.316 134.592 194.4 134.616 ;
    END
  END ps_line[365]
  PIN ps_line[366]
    DIRECTION OUTPUT ;
    USE SIGNAL ;
    PORT
      LAYER M4 ;
        RECT  194.316 134.688 194.4 134.712 ;
    END
  END ps_line[366]
  PIN ps_line[367]
    DIRECTION OUTPUT ;
    USE SIGNAL ;
    PORT
      LAYER M4 ;
        RECT  194.316 134.784 194.4 134.808 ;
    END
  END ps_line[367]
  PIN ps_line[368]
    DIRECTION OUTPUT ;
    USE SIGNAL ;
    PORT
      LAYER M4 ;
        RECT  194.316 134.88 194.4 134.904 ;
    END
  END ps_line[368]
  PIN ps_line[369]
    DIRECTION OUTPUT ;
    USE SIGNAL ;
    PORT
      LAYER M4 ;
        RECT  194.316 134.976 194.4 135 ;
    END
  END ps_line[369]
  PIN ps_line[36]
    DIRECTION OUTPUT ;
    USE SIGNAL ;
    PORT
      LAYER M4 ;
        RECT  194.316 103.008 194.4 103.032 ;
    END
  END ps_line[36]
  PIN ps_line[370]
    DIRECTION OUTPUT ;
    USE SIGNAL ;
    PORT
      LAYER M4 ;
        RECT  194.316 135.072 194.4 135.096 ;
    END
  END ps_line[370]
  PIN ps_line[371]
    DIRECTION OUTPUT ;
    USE SIGNAL ;
    PORT
      LAYER M4 ;
        RECT  194.316 135.168 194.4 135.192 ;
    END
  END ps_line[371]
  PIN ps_line[372]
    DIRECTION OUTPUT ;
    USE SIGNAL ;
    PORT
      LAYER M4 ;
        RECT  194.316 135.264 194.4 135.288 ;
    END
  END ps_line[372]
  PIN ps_line[373]
    DIRECTION OUTPUT ;
    USE SIGNAL ;
    PORT
      LAYER M4 ;
        RECT  194.316 135.36 194.4 135.384 ;
    END
  END ps_line[373]
  PIN ps_line[374]
    DIRECTION OUTPUT ;
    USE SIGNAL ;
    PORT
      LAYER M4 ;
        RECT  194.316 135.456 194.4 135.48 ;
    END
  END ps_line[374]
  PIN ps_line[375]
    DIRECTION OUTPUT ;
    USE SIGNAL ;
    PORT
      LAYER M4 ;
        RECT  194.316 135.552 194.4 135.576 ;
    END
  END ps_line[375]
  PIN ps_line[376]
    DIRECTION OUTPUT ;
    USE SIGNAL ;
    PORT
      LAYER M4 ;
        RECT  194.316 135.648 194.4 135.672 ;
    END
  END ps_line[376]
  PIN ps_line[377]
    DIRECTION OUTPUT ;
    USE SIGNAL ;
    PORT
      LAYER M4 ;
        RECT  194.316 135.744 194.4 135.768 ;
    END
  END ps_line[377]
  PIN ps_line[378]
    DIRECTION OUTPUT ;
    USE SIGNAL ;
    PORT
      LAYER M4 ;
        RECT  194.316 135.84 194.4 135.864 ;
    END
  END ps_line[378]
  PIN ps_line[379]
    DIRECTION OUTPUT ;
    USE SIGNAL ;
    PORT
      LAYER M4 ;
        RECT  194.316 135.936 194.4 135.96 ;
    END
  END ps_line[379]
  PIN ps_line[37]
    DIRECTION OUTPUT ;
    USE SIGNAL ;
    PORT
      LAYER M4 ;
        RECT  194.316 103.104 194.4 103.128 ;
    END
  END ps_line[37]
  PIN ps_line[380]
    DIRECTION OUTPUT ;
    USE SIGNAL ;
    PORT
      LAYER M4 ;
        RECT  194.316 136.032 194.4 136.056 ;
    END
  END ps_line[380]
  PIN ps_line[381]
    DIRECTION OUTPUT ;
    USE SIGNAL ;
    PORT
      LAYER M4 ;
        RECT  194.316 136.128 194.4 136.152 ;
    END
  END ps_line[381]
  PIN ps_line[382]
    DIRECTION OUTPUT ;
    USE SIGNAL ;
    PORT
      LAYER M4 ;
        RECT  194.316 136.224 194.4 136.248 ;
    END
  END ps_line[382]
  PIN ps_line[383]
    DIRECTION OUTPUT ;
    USE SIGNAL ;
    PORT
      LAYER M4 ;
        RECT  194.316 136.32 194.4 136.344 ;
    END
  END ps_line[383]
  PIN ps_line[384]
    DIRECTION OUTPUT ;
    USE SIGNAL ;
    PORT
      LAYER M4 ;
        RECT  194.316 136.416 194.4 136.44 ;
    END
  END ps_line[384]
  PIN ps_line[385]
    DIRECTION OUTPUT ;
    USE SIGNAL ;
    PORT
      LAYER M4 ;
        RECT  194.316 136.512 194.4 136.536 ;
    END
  END ps_line[385]
  PIN ps_line[386]
    DIRECTION OUTPUT ;
    USE SIGNAL ;
    PORT
      LAYER M4 ;
        RECT  194.316 136.608 194.4 136.632 ;
    END
  END ps_line[386]
  PIN ps_line[387]
    DIRECTION OUTPUT ;
    USE SIGNAL ;
    PORT
      LAYER M4 ;
        RECT  194.316 136.704 194.4 136.728 ;
    END
  END ps_line[387]
  PIN ps_line[388]
    DIRECTION OUTPUT ;
    USE SIGNAL ;
    PORT
      LAYER M4 ;
        RECT  194.316 136.8 194.4 136.824 ;
    END
  END ps_line[388]
  PIN ps_line[389]
    DIRECTION OUTPUT ;
    USE SIGNAL ;
    PORT
      LAYER M4 ;
        RECT  194.316 136.896 194.4 136.92 ;
    END
  END ps_line[389]
  PIN ps_line[38]
    DIRECTION OUTPUT ;
    USE SIGNAL ;
    PORT
      LAYER M4 ;
        RECT  194.316 103.2 194.4 103.224 ;
    END
  END ps_line[38]
  PIN ps_line[390]
    DIRECTION OUTPUT ;
    USE SIGNAL ;
    PORT
      LAYER M4 ;
        RECT  194.316 136.992 194.4 137.016 ;
    END
  END ps_line[390]
  PIN ps_line[391]
    DIRECTION OUTPUT ;
    USE SIGNAL ;
    PORT
      LAYER M4 ;
        RECT  194.316 137.088 194.4 137.112 ;
    END
  END ps_line[391]
  PIN ps_line[392]
    DIRECTION OUTPUT ;
    USE SIGNAL ;
    PORT
      LAYER M4 ;
        RECT  194.316 137.184 194.4 137.208 ;
    END
  END ps_line[392]
  PIN ps_line[393]
    DIRECTION OUTPUT ;
    USE SIGNAL ;
    PORT
      LAYER M4 ;
        RECT  194.316 137.28 194.4 137.304 ;
    END
  END ps_line[393]
  PIN ps_line[394]
    DIRECTION OUTPUT ;
    USE SIGNAL ;
    PORT
      LAYER M4 ;
        RECT  194.316 137.376 194.4 137.4 ;
    END
  END ps_line[394]
  PIN ps_line[395]
    DIRECTION OUTPUT ;
    USE SIGNAL ;
    PORT
      LAYER M4 ;
        RECT  194.316 137.472 194.4 137.496 ;
    END
  END ps_line[395]
  PIN ps_line[396]
    DIRECTION OUTPUT ;
    USE SIGNAL ;
    PORT
      LAYER M4 ;
        RECT  194.316 137.568 194.4 137.592 ;
    END
  END ps_line[396]
  PIN ps_line[397]
    DIRECTION OUTPUT ;
    USE SIGNAL ;
    PORT
      LAYER M4 ;
        RECT  194.316 137.664 194.4 137.688 ;
    END
  END ps_line[397]
  PIN ps_line[398]
    DIRECTION OUTPUT ;
    USE SIGNAL ;
    PORT
      LAYER M4 ;
        RECT  194.316 137.76 194.4 137.784 ;
    END
  END ps_line[398]
  PIN ps_line[399]
    DIRECTION OUTPUT ;
    USE SIGNAL ;
    PORT
      LAYER M4 ;
        RECT  194.316 137.856 194.4 137.88 ;
    END
  END ps_line[399]
  PIN ps_line[39]
    DIRECTION OUTPUT ;
    USE SIGNAL ;
    PORT
      LAYER M4 ;
        RECT  194.316 103.296 194.4 103.32 ;
    END
  END ps_line[39]
  PIN ps_line[3]
    DIRECTION OUTPUT ;
    USE SIGNAL ;
    PORT
      LAYER M4 ;
        RECT  194.316 99.84 194.4 99.864 ;
    END
  END ps_line[3]
  PIN ps_line[400]
    DIRECTION OUTPUT ;
    USE SIGNAL ;
    PORT
      LAYER M4 ;
        RECT  194.316 137.952 194.4 137.976 ;
    END
  END ps_line[400]
  PIN ps_line[401]
    DIRECTION OUTPUT ;
    USE SIGNAL ;
    PORT
      LAYER M4 ;
        RECT  194.316 138.048 194.4 138.072 ;
    END
  END ps_line[401]
  PIN ps_line[402]
    DIRECTION OUTPUT ;
    USE SIGNAL ;
    PORT
      LAYER M4 ;
        RECT  194.316 138.144 194.4 138.168 ;
    END
  END ps_line[402]
  PIN ps_line[403]
    DIRECTION OUTPUT ;
    USE SIGNAL ;
    PORT
      LAYER M4 ;
        RECT  194.316 138.24 194.4 138.264 ;
    END
  END ps_line[403]
  PIN ps_line[404]
    DIRECTION OUTPUT ;
    USE SIGNAL ;
    PORT
      LAYER M4 ;
        RECT  194.316 138.336 194.4 138.36 ;
    END
  END ps_line[404]
  PIN ps_line[405]
    DIRECTION OUTPUT ;
    USE SIGNAL ;
    PORT
      LAYER M4 ;
        RECT  194.316 138.432 194.4 138.456 ;
    END
  END ps_line[405]
  PIN ps_line[406]
    DIRECTION OUTPUT ;
    USE SIGNAL ;
    PORT
      LAYER M4 ;
        RECT  194.316 138.528 194.4 138.552 ;
    END
  END ps_line[406]
  PIN ps_line[407]
    DIRECTION OUTPUT ;
    USE SIGNAL ;
    PORT
      LAYER M4 ;
        RECT  194.316 138.624 194.4 138.648 ;
    END
  END ps_line[407]
  PIN ps_line[408]
    DIRECTION OUTPUT ;
    USE SIGNAL ;
    PORT
      LAYER M4 ;
        RECT  194.316 138.72 194.4 138.744 ;
    END
  END ps_line[408]
  PIN ps_line[409]
    DIRECTION OUTPUT ;
    USE SIGNAL ;
    PORT
      LAYER M4 ;
        RECT  194.316 138.816 194.4 138.84 ;
    END
  END ps_line[409]
  PIN ps_line[40]
    DIRECTION OUTPUT ;
    USE SIGNAL ;
    PORT
      LAYER M4 ;
        RECT  194.316 103.392 194.4 103.416 ;
    END
  END ps_line[40]
  PIN ps_line[410]
    DIRECTION OUTPUT ;
    USE SIGNAL ;
    PORT
      LAYER M4 ;
        RECT  194.316 138.912 194.4 138.936 ;
    END
  END ps_line[410]
  PIN ps_line[411]
    DIRECTION OUTPUT ;
    USE SIGNAL ;
    PORT
      LAYER M4 ;
        RECT  194.316 139.008 194.4 139.032 ;
    END
  END ps_line[411]
  PIN ps_line[412]
    DIRECTION OUTPUT ;
    USE SIGNAL ;
    PORT
      LAYER M4 ;
        RECT  194.316 139.104 194.4 139.128 ;
    END
  END ps_line[412]
  PIN ps_line[413]
    DIRECTION OUTPUT ;
    USE SIGNAL ;
    PORT
      LAYER M4 ;
        RECT  194.316 139.2 194.4 139.224 ;
    END
  END ps_line[413]
  PIN ps_line[414]
    DIRECTION OUTPUT ;
    USE SIGNAL ;
    PORT
      LAYER M4 ;
        RECT  194.316 139.296 194.4 139.32 ;
    END
  END ps_line[414]
  PIN ps_line[415]
    DIRECTION OUTPUT ;
    USE SIGNAL ;
    PORT
      LAYER M4 ;
        RECT  194.316 139.392 194.4 139.416 ;
    END
  END ps_line[415]
  PIN ps_line[416]
    DIRECTION OUTPUT ;
    USE SIGNAL ;
    PORT
      LAYER M4 ;
        RECT  194.316 139.488 194.4 139.512 ;
    END
  END ps_line[416]
  PIN ps_line[417]
    DIRECTION OUTPUT ;
    USE SIGNAL ;
    PORT
      LAYER M4 ;
        RECT  194.316 139.584 194.4 139.608 ;
    END
  END ps_line[417]
  PIN ps_line[418]
    DIRECTION OUTPUT ;
    USE SIGNAL ;
    PORT
      LAYER M4 ;
        RECT  194.316 139.68 194.4 139.704 ;
    END
  END ps_line[418]
  PIN ps_line[419]
    DIRECTION OUTPUT ;
    USE SIGNAL ;
    PORT
      LAYER M4 ;
        RECT  194.316 139.776 194.4 139.8 ;
    END
  END ps_line[419]
  PIN ps_line[41]
    DIRECTION OUTPUT ;
    USE SIGNAL ;
    PORT
      LAYER M4 ;
        RECT  194.316 103.488 194.4 103.512 ;
    END
  END ps_line[41]
  PIN ps_line[420]
    DIRECTION OUTPUT ;
    USE SIGNAL ;
    PORT
      LAYER M4 ;
        RECT  194.316 139.872 194.4 139.896 ;
    END
  END ps_line[420]
  PIN ps_line[421]
    DIRECTION OUTPUT ;
    USE SIGNAL ;
    PORT
      LAYER M4 ;
        RECT  194.316 139.968 194.4 139.992 ;
    END
  END ps_line[421]
  PIN ps_line[422]
    DIRECTION OUTPUT ;
    USE SIGNAL ;
    PORT
      LAYER M4 ;
        RECT  194.316 140.064 194.4 140.088 ;
    END
  END ps_line[422]
  PIN ps_line[423]
    DIRECTION OUTPUT ;
    USE SIGNAL ;
    PORT
      LAYER M4 ;
        RECT  194.316 140.16 194.4 140.184 ;
    END
  END ps_line[423]
  PIN ps_line[424]
    DIRECTION OUTPUT ;
    USE SIGNAL ;
    PORT
      LAYER M4 ;
        RECT  194.316 140.256 194.4 140.28 ;
    END
  END ps_line[424]
  PIN ps_line[425]
    DIRECTION OUTPUT ;
    USE SIGNAL ;
    PORT
      LAYER M4 ;
        RECT  194.316 140.352 194.4 140.376 ;
    END
  END ps_line[425]
  PIN ps_line[426]
    DIRECTION OUTPUT ;
    USE SIGNAL ;
    PORT
      LAYER M4 ;
        RECT  194.316 140.448 194.4 140.472 ;
    END
  END ps_line[426]
  PIN ps_line[427]
    DIRECTION OUTPUT ;
    USE SIGNAL ;
    PORT
      LAYER M4 ;
        RECT  194.316 140.544 194.4 140.568 ;
    END
  END ps_line[427]
  PIN ps_line[428]
    DIRECTION OUTPUT ;
    USE SIGNAL ;
    PORT
      LAYER M4 ;
        RECT  194.316 140.64 194.4 140.664 ;
    END
  END ps_line[428]
  PIN ps_line[429]
    DIRECTION OUTPUT ;
    USE SIGNAL ;
    PORT
      LAYER M4 ;
        RECT  194.316 140.736 194.4 140.76 ;
    END
  END ps_line[429]
  PIN ps_line[42]
    DIRECTION OUTPUT ;
    USE SIGNAL ;
    PORT
      LAYER M4 ;
        RECT  194.316 103.584 194.4 103.608 ;
    END
  END ps_line[42]
  PIN ps_line[430]
    DIRECTION OUTPUT ;
    USE SIGNAL ;
    PORT
      LAYER M4 ;
        RECT  194.316 140.832 194.4 140.856 ;
    END
  END ps_line[430]
  PIN ps_line[431]
    DIRECTION OUTPUT ;
    USE SIGNAL ;
    PORT
      LAYER M4 ;
        RECT  194.316 140.928 194.4 140.952 ;
    END
  END ps_line[431]
  PIN ps_line[432]
    DIRECTION OUTPUT ;
    USE SIGNAL ;
    PORT
      LAYER M4 ;
        RECT  194.316 141.024 194.4 141.048 ;
    END
  END ps_line[432]
  PIN ps_line[433]
    DIRECTION OUTPUT ;
    USE SIGNAL ;
    PORT
      LAYER M4 ;
        RECT  194.316 141.12 194.4 141.144 ;
    END
  END ps_line[433]
  PIN ps_line[434]
    DIRECTION OUTPUT ;
    USE SIGNAL ;
    PORT
      LAYER M4 ;
        RECT  194.316 141.216 194.4 141.24 ;
    END
  END ps_line[434]
  PIN ps_line[435]
    DIRECTION OUTPUT ;
    USE SIGNAL ;
    PORT
      LAYER M4 ;
        RECT  194.316 141.312 194.4 141.336 ;
    END
  END ps_line[435]
  PIN ps_line[436]
    DIRECTION OUTPUT ;
    USE SIGNAL ;
    PORT
      LAYER M4 ;
        RECT  194.316 141.408 194.4 141.432 ;
    END
  END ps_line[436]
  PIN ps_line[437]
    DIRECTION OUTPUT ;
    USE SIGNAL ;
    PORT
      LAYER M4 ;
        RECT  194.316 141.504 194.4 141.528 ;
    END
  END ps_line[437]
  PIN ps_line[438]
    DIRECTION OUTPUT ;
    USE SIGNAL ;
    PORT
      LAYER M4 ;
        RECT  194.316 141.6 194.4 141.624 ;
    END
  END ps_line[438]
  PIN ps_line[439]
    DIRECTION OUTPUT ;
    USE SIGNAL ;
    PORT
      LAYER M4 ;
        RECT  194.316 141.696 194.4 141.72 ;
    END
  END ps_line[439]
  PIN ps_line[43]
    DIRECTION OUTPUT ;
    USE SIGNAL ;
    PORT
      LAYER M4 ;
        RECT  194.316 103.68 194.4 103.704 ;
    END
  END ps_line[43]
  PIN ps_line[440]
    DIRECTION OUTPUT ;
    USE SIGNAL ;
    PORT
      LAYER M4 ;
        RECT  194.316 141.792 194.4 141.816 ;
    END
  END ps_line[440]
  PIN ps_line[441]
    DIRECTION OUTPUT ;
    USE SIGNAL ;
    PORT
      LAYER M4 ;
        RECT  194.316 141.888 194.4 141.912 ;
    END
  END ps_line[441]
  PIN ps_line[442]
    DIRECTION OUTPUT ;
    USE SIGNAL ;
    PORT
      LAYER M4 ;
        RECT  194.316 141.984 194.4 142.008 ;
    END
  END ps_line[442]
  PIN ps_line[443]
    DIRECTION OUTPUT ;
    USE SIGNAL ;
    PORT
      LAYER M4 ;
        RECT  194.316 142.08 194.4 142.104 ;
    END
  END ps_line[443]
  PIN ps_line[444]
    DIRECTION OUTPUT ;
    USE SIGNAL ;
    PORT
      LAYER M4 ;
        RECT  194.316 142.176 194.4 142.2 ;
    END
  END ps_line[444]
  PIN ps_line[445]
    DIRECTION OUTPUT ;
    USE SIGNAL ;
    PORT
      LAYER M4 ;
        RECT  194.316 142.272 194.4 142.296 ;
    END
  END ps_line[445]
  PIN ps_line[446]
    DIRECTION OUTPUT ;
    USE SIGNAL ;
    PORT
      LAYER M4 ;
        RECT  194.316 142.368 194.4 142.392 ;
    END
  END ps_line[446]
  PIN ps_line[447]
    DIRECTION OUTPUT ;
    USE SIGNAL ;
    PORT
      LAYER M4 ;
        RECT  194.316 142.464 194.4 142.488 ;
    END
  END ps_line[447]
  PIN ps_line[448]
    DIRECTION OUTPUT ;
    USE SIGNAL ;
    PORT
      LAYER M4 ;
        RECT  194.316 142.56 194.4 142.584 ;
    END
  END ps_line[448]
  PIN ps_line[449]
    DIRECTION OUTPUT ;
    USE SIGNAL ;
    PORT
      LAYER M4 ;
        RECT  194.316 142.656 194.4 142.68 ;
    END
  END ps_line[449]
  PIN ps_line[44]
    DIRECTION OUTPUT ;
    USE SIGNAL ;
    PORT
      LAYER M4 ;
        RECT  194.316 103.776 194.4 103.8 ;
    END
  END ps_line[44]
  PIN ps_line[450]
    DIRECTION OUTPUT ;
    USE SIGNAL ;
    PORT
      LAYER M4 ;
        RECT  194.316 142.752 194.4 142.776 ;
    END
  END ps_line[450]
  PIN ps_line[451]
    DIRECTION OUTPUT ;
    USE SIGNAL ;
    PORT
      LAYER M4 ;
        RECT  194.316 142.848 194.4 142.872 ;
    END
  END ps_line[451]
  PIN ps_line[452]
    DIRECTION OUTPUT ;
    USE SIGNAL ;
    PORT
      LAYER M4 ;
        RECT  194.316 142.944 194.4 142.968 ;
    END
  END ps_line[452]
  PIN ps_line[453]
    DIRECTION OUTPUT ;
    USE SIGNAL ;
    PORT
      LAYER M4 ;
        RECT  194.316 143.04 194.4 143.064 ;
    END
  END ps_line[453]
  PIN ps_line[454]
    DIRECTION OUTPUT ;
    USE SIGNAL ;
    PORT
      LAYER M4 ;
        RECT  194.316 143.136 194.4 143.16 ;
    END
  END ps_line[454]
  PIN ps_line[455]
    DIRECTION OUTPUT ;
    USE SIGNAL ;
    PORT
      LAYER M4 ;
        RECT  194.316 143.232 194.4 143.256 ;
    END
  END ps_line[455]
  PIN ps_line[456]
    DIRECTION OUTPUT ;
    USE SIGNAL ;
    PORT
      LAYER M4 ;
        RECT  194.316 143.328 194.4 143.352 ;
    END
  END ps_line[456]
  PIN ps_line[457]
    DIRECTION OUTPUT ;
    USE SIGNAL ;
    PORT
      LAYER M4 ;
        RECT  194.316 143.424 194.4 143.448 ;
    END
  END ps_line[457]
  PIN ps_line[458]
    DIRECTION OUTPUT ;
    USE SIGNAL ;
    PORT
      LAYER M4 ;
        RECT  194.316 143.52 194.4 143.544 ;
    END
  END ps_line[458]
  PIN ps_line[459]
    DIRECTION OUTPUT ;
    USE SIGNAL ;
    PORT
      LAYER M4 ;
        RECT  194.316 143.616 194.4 143.64 ;
    END
  END ps_line[459]
  PIN ps_line[45]
    DIRECTION OUTPUT ;
    USE SIGNAL ;
    PORT
      LAYER M4 ;
        RECT  194.316 103.872 194.4 103.896 ;
    END
  END ps_line[45]
  PIN ps_line[460]
    DIRECTION OUTPUT ;
    USE SIGNAL ;
    PORT
      LAYER M4 ;
        RECT  194.316 143.712 194.4 143.736 ;
    END
  END ps_line[460]
  PIN ps_line[461]
    DIRECTION OUTPUT ;
    USE SIGNAL ;
    PORT
      LAYER M4 ;
        RECT  194.316 143.808 194.4 143.832 ;
    END
  END ps_line[461]
  PIN ps_line[462]
    DIRECTION OUTPUT ;
    USE SIGNAL ;
    PORT
      LAYER M4 ;
        RECT  194.316 143.904 194.4 143.928 ;
    END
  END ps_line[462]
  PIN ps_line[463]
    DIRECTION OUTPUT ;
    USE SIGNAL ;
    PORT
      LAYER M4 ;
        RECT  194.316 144 194.4 144.024 ;
    END
  END ps_line[463]
  PIN ps_line[464]
    DIRECTION OUTPUT ;
    USE SIGNAL ;
    PORT
      LAYER M4 ;
        RECT  194.316 144.096 194.4 144.12 ;
    END
  END ps_line[464]
  PIN ps_line[465]
    DIRECTION OUTPUT ;
    USE SIGNAL ;
    PORT
      LAYER M4 ;
        RECT  194.316 144.192 194.4 144.216 ;
    END
  END ps_line[465]
  PIN ps_line[466]
    DIRECTION OUTPUT ;
    USE SIGNAL ;
    PORT
      LAYER M4 ;
        RECT  194.316 144.288 194.4 144.312 ;
    END
  END ps_line[466]
  PIN ps_line[467]
    DIRECTION OUTPUT ;
    USE SIGNAL ;
    PORT
      LAYER M4 ;
        RECT  194.316 144.384 194.4 144.408 ;
    END
  END ps_line[467]
  PIN ps_line[468]
    DIRECTION OUTPUT ;
    USE SIGNAL ;
    PORT
      LAYER M4 ;
        RECT  194.316 144.48 194.4 144.504 ;
    END
  END ps_line[468]
  PIN ps_line[469]
    DIRECTION OUTPUT ;
    USE SIGNAL ;
    PORT
      LAYER M4 ;
        RECT  194.316 144.576 194.4 144.6 ;
    END
  END ps_line[469]
  PIN ps_line[46]
    DIRECTION OUTPUT ;
    USE SIGNAL ;
    PORT
      LAYER M4 ;
        RECT  194.316 103.968 194.4 103.992 ;
    END
  END ps_line[46]
  PIN ps_line[470]
    DIRECTION OUTPUT ;
    USE SIGNAL ;
    PORT
      LAYER M4 ;
        RECT  194.316 144.672 194.4 144.696 ;
    END
  END ps_line[470]
  PIN ps_line[471]
    DIRECTION OUTPUT ;
    USE SIGNAL ;
    PORT
      LAYER M4 ;
        RECT  194.316 144.768 194.4 144.792 ;
    END
  END ps_line[471]
  PIN ps_line[472]
    DIRECTION OUTPUT ;
    USE SIGNAL ;
    PORT
      LAYER M4 ;
        RECT  194.316 144.864 194.4 144.888 ;
    END
  END ps_line[472]
  PIN ps_line[473]
    DIRECTION OUTPUT ;
    USE SIGNAL ;
    PORT
      LAYER M4 ;
        RECT  194.316 144.96 194.4 144.984 ;
    END
  END ps_line[473]
  PIN ps_line[474]
    DIRECTION OUTPUT ;
    USE SIGNAL ;
    PORT
      LAYER M4 ;
        RECT  194.316 145.056 194.4 145.08 ;
    END
  END ps_line[474]
  PIN ps_line[475]
    DIRECTION OUTPUT ;
    USE SIGNAL ;
    PORT
      LAYER M4 ;
        RECT  194.316 145.152 194.4 145.176 ;
    END
  END ps_line[475]
  PIN ps_line[476]
    DIRECTION OUTPUT ;
    USE SIGNAL ;
    PORT
      LAYER M4 ;
        RECT  194.316 145.248 194.4 145.272 ;
    END
  END ps_line[476]
  PIN ps_line[477]
    DIRECTION OUTPUT ;
    USE SIGNAL ;
    PORT
      LAYER M4 ;
        RECT  194.316 145.344 194.4 145.368 ;
    END
  END ps_line[477]
  PIN ps_line[478]
    DIRECTION OUTPUT ;
    USE SIGNAL ;
    PORT
      LAYER M4 ;
        RECT  194.316 145.44 194.4 145.464 ;
    END
  END ps_line[478]
  PIN ps_line[479]
    DIRECTION OUTPUT ;
    USE SIGNAL ;
    PORT
      LAYER M4 ;
        RECT  194.316 145.536 194.4 145.56 ;
    END
  END ps_line[479]
  PIN ps_line[47]
    DIRECTION OUTPUT ;
    USE SIGNAL ;
    PORT
      LAYER M4 ;
        RECT  194.316 104.064 194.4 104.088 ;
    END
  END ps_line[47]
  PIN ps_line[480]
    DIRECTION OUTPUT ;
    USE SIGNAL ;
    PORT
      LAYER M4 ;
        RECT  194.316 145.632 194.4 145.656 ;
    END
  END ps_line[480]
  PIN ps_line[481]
    DIRECTION OUTPUT ;
    USE SIGNAL ;
    PORT
      LAYER M4 ;
        RECT  194.316 145.728 194.4 145.752 ;
    END
  END ps_line[481]
  PIN ps_line[482]
    DIRECTION OUTPUT ;
    USE SIGNAL ;
    PORT
      LAYER M4 ;
        RECT  194.316 145.824 194.4 145.848 ;
    END
  END ps_line[482]
  PIN ps_line[483]
    DIRECTION OUTPUT ;
    USE SIGNAL ;
    PORT
      LAYER M4 ;
        RECT  194.316 145.92 194.4 145.944 ;
    END
  END ps_line[483]
  PIN ps_line[484]
    DIRECTION OUTPUT ;
    USE SIGNAL ;
    PORT
      LAYER M4 ;
        RECT  194.316 146.016 194.4 146.04 ;
    END
  END ps_line[484]
  PIN ps_line[485]
    DIRECTION OUTPUT ;
    USE SIGNAL ;
    PORT
      LAYER M4 ;
        RECT  194.316 146.112 194.4 146.136 ;
    END
  END ps_line[485]
  PIN ps_line[486]
    DIRECTION OUTPUT ;
    USE SIGNAL ;
    PORT
      LAYER M4 ;
        RECT  194.316 146.208 194.4 146.232 ;
    END
  END ps_line[486]
  PIN ps_line[487]
    DIRECTION OUTPUT ;
    USE SIGNAL ;
    PORT
      LAYER M4 ;
        RECT  194.316 146.304 194.4 146.328 ;
    END
  END ps_line[487]
  PIN ps_line[488]
    DIRECTION OUTPUT ;
    USE SIGNAL ;
    PORT
      LAYER M4 ;
        RECT  194.316 146.4 194.4 146.424 ;
    END
  END ps_line[488]
  PIN ps_line[489]
    DIRECTION OUTPUT ;
    USE SIGNAL ;
    PORT
      LAYER M4 ;
        RECT  194.316 146.496 194.4 146.52 ;
    END
  END ps_line[489]
  PIN ps_line[48]
    DIRECTION OUTPUT ;
    USE SIGNAL ;
    PORT
      LAYER M4 ;
        RECT  194.316 104.16 194.4 104.184 ;
    END
  END ps_line[48]
  PIN ps_line[490]
    DIRECTION OUTPUT ;
    USE SIGNAL ;
    PORT
      LAYER M4 ;
        RECT  194.316 146.592 194.4 146.616 ;
    END
  END ps_line[490]
  PIN ps_line[491]
    DIRECTION OUTPUT ;
    USE SIGNAL ;
    PORT
      LAYER M4 ;
        RECT  194.316 146.688 194.4 146.712 ;
    END
  END ps_line[491]
  PIN ps_line[492]
    DIRECTION OUTPUT ;
    USE SIGNAL ;
    PORT
      LAYER M4 ;
        RECT  194.316 146.784 194.4 146.808 ;
    END
  END ps_line[492]
  PIN ps_line[493]
    DIRECTION OUTPUT ;
    USE SIGNAL ;
    PORT
      LAYER M4 ;
        RECT  194.316 146.88 194.4 146.904 ;
    END
  END ps_line[493]
  PIN ps_line[494]
    DIRECTION OUTPUT ;
    USE SIGNAL ;
    PORT
      LAYER M4 ;
        RECT  194.316 146.976 194.4 147 ;
    END
  END ps_line[494]
  PIN ps_line[495]
    DIRECTION OUTPUT ;
    USE SIGNAL ;
    PORT
      LAYER M4 ;
        RECT  194.316 147.072 194.4 147.096 ;
    END
  END ps_line[495]
  PIN ps_line[496]
    DIRECTION OUTPUT ;
    USE SIGNAL ;
    PORT
      LAYER M4 ;
        RECT  194.316 147.168 194.4 147.192 ;
    END
  END ps_line[496]
  PIN ps_line[497]
    DIRECTION OUTPUT ;
    USE SIGNAL ;
    PORT
      LAYER M4 ;
        RECT  194.316 147.264 194.4 147.288 ;
    END
  END ps_line[497]
  PIN ps_line[498]
    DIRECTION OUTPUT ;
    USE SIGNAL ;
    PORT
      LAYER M4 ;
        RECT  194.316 147.36 194.4 147.384 ;
    END
  END ps_line[498]
  PIN ps_line[499]
    DIRECTION OUTPUT ;
    USE SIGNAL ;
    PORT
      LAYER M4 ;
        RECT  194.316 147.456 194.4 147.48 ;
    END
  END ps_line[499]
  PIN ps_line[49]
    DIRECTION OUTPUT ;
    USE SIGNAL ;
    PORT
      LAYER M4 ;
        RECT  194.316 104.256 194.4 104.28 ;
    END
  END ps_line[49]
  PIN ps_line[4]
    DIRECTION OUTPUT ;
    USE SIGNAL ;
    PORT
      LAYER M4 ;
        RECT  194.316 99.936 194.4 99.96 ;
    END
  END ps_line[4]
  PIN ps_line[500]
    DIRECTION OUTPUT ;
    USE SIGNAL ;
    PORT
      LAYER M4 ;
        RECT  194.316 147.552 194.4 147.576 ;
    END
  END ps_line[500]
  PIN ps_line[501]
    DIRECTION OUTPUT ;
    USE SIGNAL ;
    PORT
      LAYER M4 ;
        RECT  194.316 147.648 194.4 147.672 ;
    END
  END ps_line[501]
  PIN ps_line[502]
    DIRECTION OUTPUT ;
    USE SIGNAL ;
    PORT
      LAYER M4 ;
        RECT  194.316 147.744 194.4 147.768 ;
    END
  END ps_line[502]
  PIN ps_line[503]
    DIRECTION OUTPUT ;
    USE SIGNAL ;
    PORT
      LAYER M4 ;
        RECT  194.316 147.84 194.4 147.864 ;
    END
  END ps_line[503]
  PIN ps_line[504]
    DIRECTION OUTPUT ;
    USE SIGNAL ;
    PORT
      LAYER M4 ;
        RECT  194.316 147.936 194.4 147.96 ;
    END
  END ps_line[504]
  PIN ps_line[505]
    DIRECTION OUTPUT ;
    USE SIGNAL ;
    PORT
      LAYER M4 ;
        RECT  194.316 148.032 194.4 148.056 ;
    END
  END ps_line[505]
  PIN ps_line[506]
    DIRECTION OUTPUT ;
    USE SIGNAL ;
    PORT
      LAYER M4 ;
        RECT  194.316 148.128 194.4 148.152 ;
    END
  END ps_line[506]
  PIN ps_line[507]
    DIRECTION OUTPUT ;
    USE SIGNAL ;
    PORT
      LAYER M4 ;
        RECT  194.316 148.224 194.4 148.248 ;
    END
  END ps_line[507]
  PIN ps_line[508]
    DIRECTION OUTPUT ;
    USE SIGNAL ;
    PORT
      LAYER M4 ;
        RECT  194.316 148.32 194.4 148.344 ;
    END
  END ps_line[508]
  PIN ps_line[509]
    DIRECTION OUTPUT ;
    USE SIGNAL ;
    PORT
      LAYER M4 ;
        RECT  194.316 148.416 194.4 148.44 ;
    END
  END ps_line[509]
  PIN ps_line[50]
    DIRECTION OUTPUT ;
    USE SIGNAL ;
    PORT
      LAYER M4 ;
        RECT  194.316 104.352 194.4 104.376 ;
    END
  END ps_line[50]
  PIN ps_line[510]
    DIRECTION OUTPUT ;
    USE SIGNAL ;
    PORT
      LAYER M4 ;
        RECT  194.316 148.512 194.4 148.536 ;
    END
  END ps_line[510]
  PIN ps_line[511]
    DIRECTION OUTPUT ;
    USE SIGNAL ;
    PORT
      LAYER M4 ;
        RECT  194.316 148.608 194.4 148.632 ;
    END
  END ps_line[511]
  PIN ps_line[512]
    DIRECTION OUTPUT ;
    USE SIGNAL ;
    PORT
      LAYER M4 ;
        RECT  194.316 148.704 194.4 148.728 ;
    END
  END ps_line[512]
  PIN ps_line[513]
    DIRECTION OUTPUT ;
    USE SIGNAL ;
    PORT
      LAYER M4 ;
        RECT  194.316 148.8 194.4 148.824 ;
    END
  END ps_line[513]
  PIN ps_line[514]
    DIRECTION OUTPUT ;
    USE SIGNAL ;
    PORT
      LAYER M4 ;
        RECT  194.316 148.896 194.4 148.92 ;
    END
  END ps_line[514]
  PIN ps_line[515]
    DIRECTION OUTPUT ;
    USE SIGNAL ;
    PORT
      LAYER M4 ;
        RECT  194.316 148.992 194.4 149.016 ;
    END
  END ps_line[515]
  PIN ps_line[516]
    DIRECTION OUTPUT ;
    USE SIGNAL ;
    PORT
      LAYER M4 ;
        RECT  194.316 149.088 194.4 149.112 ;
    END
  END ps_line[516]
  PIN ps_line[517]
    DIRECTION OUTPUT ;
    USE SIGNAL ;
    PORT
      LAYER M4 ;
        RECT  194.316 149.184 194.4 149.208 ;
    END
  END ps_line[517]
  PIN ps_line[518]
    DIRECTION OUTPUT ;
    USE SIGNAL ;
    PORT
      LAYER M4 ;
        RECT  194.316 149.28 194.4 149.304 ;
    END
  END ps_line[518]
  PIN ps_line[519]
    DIRECTION OUTPUT ;
    USE SIGNAL ;
    PORT
      LAYER M4 ;
        RECT  194.316 149.376 194.4 149.4 ;
    END
  END ps_line[519]
  PIN ps_line[51]
    DIRECTION OUTPUT ;
    USE SIGNAL ;
    PORT
      LAYER M4 ;
        RECT  194.316 104.448 194.4 104.472 ;
    END
  END ps_line[51]
  PIN ps_line[520]
    DIRECTION OUTPUT ;
    USE SIGNAL ;
    PORT
      LAYER M4 ;
        RECT  194.316 149.472 194.4 149.496 ;
    END
  END ps_line[520]
  PIN ps_line[521]
    DIRECTION OUTPUT ;
    USE SIGNAL ;
    PORT
      LAYER M4 ;
        RECT  194.316 149.568 194.4 149.592 ;
    END
  END ps_line[521]
  PIN ps_line[522]
    DIRECTION OUTPUT ;
    USE SIGNAL ;
    PORT
      LAYER M4 ;
        RECT  194.316 149.664 194.4 149.688 ;
    END
  END ps_line[522]
  PIN ps_line[523]
    DIRECTION OUTPUT ;
    USE SIGNAL ;
    PORT
      LAYER M4 ;
        RECT  194.316 149.76 194.4 149.784 ;
    END
  END ps_line[523]
  PIN ps_line[524]
    DIRECTION OUTPUT ;
    USE SIGNAL ;
    PORT
      LAYER M4 ;
        RECT  194.316 149.856 194.4 149.88 ;
    END
  END ps_line[524]
  PIN ps_line[525]
    DIRECTION OUTPUT ;
    USE SIGNAL ;
    PORT
      LAYER M4 ;
        RECT  194.316 149.952 194.4 149.976 ;
    END
  END ps_line[525]
  PIN ps_line[526]
    DIRECTION OUTPUT ;
    USE SIGNAL ;
    PORT
      LAYER M4 ;
        RECT  194.316 150.048 194.4 150.072 ;
    END
  END ps_line[526]
  PIN ps_line[527]
    DIRECTION OUTPUT ;
    USE SIGNAL ;
    PORT
      LAYER M4 ;
        RECT  194.316 150.144 194.4 150.168 ;
    END
  END ps_line[527]
  PIN ps_line[528]
    DIRECTION OUTPUT ;
    USE SIGNAL ;
    PORT
      LAYER M4 ;
        RECT  194.316 150.24 194.4 150.264 ;
    END
  END ps_line[528]
  PIN ps_line[529]
    DIRECTION OUTPUT ;
    USE SIGNAL ;
    PORT
      LAYER M4 ;
        RECT  194.316 150.336 194.4 150.36 ;
    END
  END ps_line[529]
  PIN ps_line[52]
    DIRECTION OUTPUT ;
    USE SIGNAL ;
    PORT
      LAYER M4 ;
        RECT  194.316 104.544 194.4 104.568 ;
    END
  END ps_line[52]
  PIN ps_line[530]
    DIRECTION OUTPUT ;
    USE SIGNAL ;
    PORT
      LAYER M4 ;
        RECT  194.316 150.432 194.4 150.456 ;
    END
  END ps_line[530]
  PIN ps_line[531]
    DIRECTION OUTPUT ;
    USE SIGNAL ;
    PORT
      LAYER M4 ;
        RECT  194.316 150.528 194.4 150.552 ;
    END
  END ps_line[531]
  PIN ps_line[532]
    DIRECTION OUTPUT ;
    USE SIGNAL ;
    PORT
      LAYER M4 ;
        RECT  194.316 150.624 194.4 150.648 ;
    END
  END ps_line[532]
  PIN ps_line[533]
    DIRECTION OUTPUT ;
    USE SIGNAL ;
    PORT
      LAYER M4 ;
        RECT  194.316 150.72 194.4 150.744 ;
    END
  END ps_line[533]
  PIN ps_line[534]
    DIRECTION OUTPUT ;
    USE SIGNAL ;
    PORT
      LAYER M4 ;
        RECT  194.316 150.816 194.4 150.84 ;
    END
  END ps_line[534]
  PIN ps_line[535]
    DIRECTION OUTPUT ;
    USE SIGNAL ;
    PORT
      LAYER M4 ;
        RECT  194.316 150.912 194.4 150.936 ;
    END
  END ps_line[535]
  PIN ps_line[536]
    DIRECTION OUTPUT ;
    USE SIGNAL ;
    PORT
      LAYER M4 ;
        RECT  194.316 151.008 194.4 151.032 ;
    END
  END ps_line[536]
  PIN ps_line[537]
    DIRECTION OUTPUT ;
    USE SIGNAL ;
    PORT
      LAYER M4 ;
        RECT  194.316 151.104 194.4 151.128 ;
    END
  END ps_line[537]
  PIN ps_line[538]
    DIRECTION OUTPUT ;
    USE SIGNAL ;
    PORT
      LAYER M4 ;
        RECT  194.316 151.2 194.4 151.224 ;
    END
  END ps_line[538]
  PIN ps_line[539]
    DIRECTION OUTPUT ;
    USE SIGNAL ;
    PORT
      LAYER M4 ;
        RECT  194.316 151.296 194.4 151.32 ;
    END
  END ps_line[539]
  PIN ps_line[53]
    DIRECTION OUTPUT ;
    USE SIGNAL ;
    PORT
      LAYER M4 ;
        RECT  194.316 104.64 194.4 104.664 ;
    END
  END ps_line[53]
  PIN ps_line[540]
    DIRECTION OUTPUT ;
    USE SIGNAL ;
    PORT
      LAYER M4 ;
        RECT  194.316 151.392 194.4 151.416 ;
    END
  END ps_line[540]
  PIN ps_line[541]
    DIRECTION OUTPUT ;
    USE SIGNAL ;
    PORT
      LAYER M4 ;
        RECT  194.316 151.488 194.4 151.512 ;
    END
  END ps_line[541]
  PIN ps_line[542]
    DIRECTION OUTPUT ;
    USE SIGNAL ;
    PORT
      LAYER M4 ;
        RECT  194.316 151.584 194.4 151.608 ;
    END
  END ps_line[542]
  PIN ps_line[543]
    DIRECTION OUTPUT ;
    USE SIGNAL ;
    PORT
      LAYER M4 ;
        RECT  194.316 151.68 194.4 151.704 ;
    END
  END ps_line[543]
  PIN ps_line[544]
    DIRECTION OUTPUT ;
    USE SIGNAL ;
    PORT
      LAYER M4 ;
        RECT  194.316 151.776 194.4 151.8 ;
    END
  END ps_line[544]
  PIN ps_line[545]
    DIRECTION OUTPUT ;
    USE SIGNAL ;
    PORT
      LAYER M4 ;
        RECT  194.316 151.872 194.4 151.896 ;
    END
  END ps_line[545]
  PIN ps_line[546]
    DIRECTION OUTPUT ;
    USE SIGNAL ;
    PORT
      LAYER M4 ;
        RECT  194.316 151.968 194.4 151.992 ;
    END
  END ps_line[546]
  PIN ps_line[547]
    DIRECTION OUTPUT ;
    USE SIGNAL ;
    PORT
      LAYER M4 ;
        RECT  194.316 152.064 194.4 152.088 ;
    END
  END ps_line[547]
  PIN ps_line[548]
    DIRECTION OUTPUT ;
    USE SIGNAL ;
    PORT
      LAYER M4 ;
        RECT  194.316 152.16 194.4 152.184 ;
    END
  END ps_line[548]
  PIN ps_line[549]
    DIRECTION OUTPUT ;
    USE SIGNAL ;
    PORT
      LAYER M4 ;
        RECT  194.316 152.256 194.4 152.28 ;
    END
  END ps_line[549]
  PIN ps_line[54]
    DIRECTION OUTPUT ;
    USE SIGNAL ;
    PORT
      LAYER M4 ;
        RECT  194.316 104.736 194.4 104.76 ;
    END
  END ps_line[54]
  PIN ps_line[550]
    DIRECTION OUTPUT ;
    USE SIGNAL ;
    PORT
      LAYER M4 ;
        RECT  194.316 152.352 194.4 152.376 ;
    END
  END ps_line[550]
  PIN ps_line[551]
    DIRECTION OUTPUT ;
    USE SIGNAL ;
    PORT
      LAYER M4 ;
        RECT  194.316 152.448 194.4 152.472 ;
    END
  END ps_line[551]
  PIN ps_line[552]
    DIRECTION OUTPUT ;
    USE SIGNAL ;
    PORT
      LAYER M4 ;
        RECT  194.316 152.544 194.4 152.568 ;
    END
  END ps_line[552]
  PIN ps_line[553]
    DIRECTION OUTPUT ;
    USE SIGNAL ;
    PORT
      LAYER M4 ;
        RECT  194.316 152.64 194.4 152.664 ;
    END
  END ps_line[553]
  PIN ps_line[554]
    DIRECTION OUTPUT ;
    USE SIGNAL ;
    PORT
      LAYER M4 ;
        RECT  194.316 152.736 194.4 152.76 ;
    END
  END ps_line[554]
  PIN ps_line[555]
    DIRECTION OUTPUT ;
    USE SIGNAL ;
    PORT
      LAYER M4 ;
        RECT  194.316 152.832 194.4 152.856 ;
    END
  END ps_line[555]
  PIN ps_line[556]
    DIRECTION OUTPUT ;
    USE SIGNAL ;
    PORT
      LAYER M4 ;
        RECT  194.316 152.928 194.4 152.952 ;
    END
  END ps_line[556]
  PIN ps_line[557]
    DIRECTION OUTPUT ;
    USE SIGNAL ;
    PORT
      LAYER M4 ;
        RECT  194.316 153.024 194.4 153.048 ;
    END
  END ps_line[557]
  PIN ps_line[558]
    DIRECTION OUTPUT ;
    USE SIGNAL ;
    PORT
      LAYER M4 ;
        RECT  194.316 153.12 194.4 153.144 ;
    END
  END ps_line[558]
  PIN ps_line[559]
    DIRECTION OUTPUT ;
    USE SIGNAL ;
    PORT
      LAYER M4 ;
        RECT  194.316 153.216 194.4 153.24 ;
    END
  END ps_line[559]
  PIN ps_line[55]
    DIRECTION OUTPUT ;
    USE SIGNAL ;
    PORT
      LAYER M4 ;
        RECT  194.316 104.832 194.4 104.856 ;
    END
  END ps_line[55]
  PIN ps_line[560]
    DIRECTION OUTPUT ;
    USE SIGNAL ;
    PORT
      LAYER M4 ;
        RECT  194.316 153.312 194.4 153.336 ;
    END
  END ps_line[560]
  PIN ps_line[561]
    DIRECTION OUTPUT ;
    USE SIGNAL ;
    PORT
      LAYER M4 ;
        RECT  194.316 153.408 194.4 153.432 ;
    END
  END ps_line[561]
  PIN ps_line[562]
    DIRECTION OUTPUT ;
    USE SIGNAL ;
    PORT
      LAYER M4 ;
        RECT  194.316 153.504 194.4 153.528 ;
    END
  END ps_line[562]
  PIN ps_line[563]
    DIRECTION OUTPUT ;
    USE SIGNAL ;
    PORT
      LAYER M4 ;
        RECT  194.316 153.6 194.4 153.624 ;
    END
  END ps_line[563]
  PIN ps_line[564]
    DIRECTION OUTPUT ;
    USE SIGNAL ;
    PORT
      LAYER M4 ;
        RECT  194.316 153.696 194.4 153.72 ;
    END
  END ps_line[564]
  PIN ps_line[565]
    DIRECTION OUTPUT ;
    USE SIGNAL ;
    PORT
      LAYER M4 ;
        RECT  194.316 153.792 194.4 153.816 ;
    END
  END ps_line[565]
  PIN ps_line[566]
    DIRECTION OUTPUT ;
    USE SIGNAL ;
    PORT
      LAYER M4 ;
        RECT  194.316 153.888 194.4 153.912 ;
    END
  END ps_line[566]
  PIN ps_line[567]
    DIRECTION OUTPUT ;
    USE SIGNAL ;
    PORT
      LAYER M4 ;
        RECT  194.316 153.984 194.4 154.008 ;
    END
  END ps_line[567]
  PIN ps_line[568]
    DIRECTION OUTPUT ;
    USE SIGNAL ;
    PORT
      LAYER M4 ;
        RECT  194.316 154.08 194.4 154.104 ;
    END
  END ps_line[568]
  PIN ps_line[569]
    DIRECTION OUTPUT ;
    USE SIGNAL ;
    PORT
      LAYER M4 ;
        RECT  194.316 154.176 194.4 154.2 ;
    END
  END ps_line[569]
  PIN ps_line[56]
    DIRECTION OUTPUT ;
    USE SIGNAL ;
    PORT
      LAYER M4 ;
        RECT  194.316 104.928 194.4 104.952 ;
    END
  END ps_line[56]
  PIN ps_line[570]
    DIRECTION OUTPUT ;
    USE SIGNAL ;
    PORT
      LAYER M4 ;
        RECT  194.316 154.272 194.4 154.296 ;
    END
  END ps_line[570]
  PIN ps_line[571]
    DIRECTION OUTPUT ;
    USE SIGNAL ;
    PORT
      LAYER M4 ;
        RECT  194.316 154.368 194.4 154.392 ;
    END
  END ps_line[571]
  PIN ps_line[572]
    DIRECTION OUTPUT ;
    USE SIGNAL ;
    PORT
      LAYER M4 ;
        RECT  194.316 154.464 194.4 154.488 ;
    END
  END ps_line[572]
  PIN ps_line[573]
    DIRECTION OUTPUT ;
    USE SIGNAL ;
    PORT
      LAYER M4 ;
        RECT  194.316 154.56 194.4 154.584 ;
    END
  END ps_line[573]
  PIN ps_line[574]
    DIRECTION OUTPUT ;
    USE SIGNAL ;
    PORT
      LAYER M4 ;
        RECT  194.316 154.656 194.4 154.68 ;
    END
  END ps_line[574]
  PIN ps_line[575]
    DIRECTION OUTPUT ;
    USE SIGNAL ;
    PORT
      LAYER M4 ;
        RECT  194.316 154.752 194.4 154.776 ;
    END
  END ps_line[575]
  PIN ps_line[576]
    DIRECTION OUTPUT ;
    USE SIGNAL ;
    PORT
      LAYER M4 ;
        RECT  194.316 154.848 194.4 154.872 ;
    END
  END ps_line[576]
  PIN ps_line[577]
    DIRECTION OUTPUT ;
    USE SIGNAL ;
    PORT
      LAYER M4 ;
        RECT  194.316 154.944 194.4 154.968 ;
    END
  END ps_line[577]
  PIN ps_line[578]
    DIRECTION OUTPUT ;
    USE SIGNAL ;
    PORT
      LAYER M4 ;
        RECT  194.316 155.04 194.4 155.064 ;
    END
  END ps_line[578]
  PIN ps_line[579]
    DIRECTION OUTPUT ;
    USE SIGNAL ;
    PORT
      LAYER M4 ;
        RECT  194.316 155.136 194.4 155.16 ;
    END
  END ps_line[579]
  PIN ps_line[57]
    DIRECTION OUTPUT ;
    USE SIGNAL ;
    PORT
      LAYER M4 ;
        RECT  194.316 105.024 194.4 105.048 ;
    END
  END ps_line[57]
  PIN ps_line[580]
    DIRECTION OUTPUT ;
    USE SIGNAL ;
    PORT
      LAYER M4 ;
        RECT  194.316 155.232 194.4 155.256 ;
    END
  END ps_line[580]
  PIN ps_line[581]
    DIRECTION OUTPUT ;
    USE SIGNAL ;
    PORT
      LAYER M4 ;
        RECT  194.316 155.328 194.4 155.352 ;
    END
  END ps_line[581]
  PIN ps_line[582]
    DIRECTION OUTPUT ;
    USE SIGNAL ;
    PORT
      LAYER M4 ;
        RECT  194.316 155.424 194.4 155.448 ;
    END
  END ps_line[582]
  PIN ps_line[583]
    DIRECTION OUTPUT ;
    USE SIGNAL ;
    PORT
      LAYER M4 ;
        RECT  194.316 155.52 194.4 155.544 ;
    END
  END ps_line[583]
  PIN ps_line[584]
    DIRECTION OUTPUT ;
    USE SIGNAL ;
    PORT
      LAYER M4 ;
        RECT  194.316 155.616 194.4 155.64 ;
    END
  END ps_line[584]
  PIN ps_line[585]
    DIRECTION OUTPUT ;
    USE SIGNAL ;
    PORT
      LAYER M4 ;
        RECT  194.316 155.712 194.4 155.736 ;
    END
  END ps_line[585]
  PIN ps_line[586]
    DIRECTION OUTPUT ;
    USE SIGNAL ;
    PORT
      LAYER M4 ;
        RECT  194.316 155.808 194.4 155.832 ;
    END
  END ps_line[586]
  PIN ps_line[587]
    DIRECTION OUTPUT ;
    USE SIGNAL ;
    PORT
      LAYER M4 ;
        RECT  194.316 155.904 194.4 155.928 ;
    END
  END ps_line[587]
  PIN ps_line[588]
    DIRECTION OUTPUT ;
    USE SIGNAL ;
    PORT
      LAYER M4 ;
        RECT  194.316 156 194.4 156.024 ;
    END
  END ps_line[588]
  PIN ps_line[589]
    DIRECTION OUTPUT ;
    USE SIGNAL ;
    PORT
      LAYER M4 ;
        RECT  194.316 156.096 194.4 156.12 ;
    END
  END ps_line[589]
  PIN ps_line[58]
    DIRECTION OUTPUT ;
    USE SIGNAL ;
    PORT
      LAYER M4 ;
        RECT  194.316 105.12 194.4 105.144 ;
    END
  END ps_line[58]
  PIN ps_line[590]
    DIRECTION OUTPUT ;
    USE SIGNAL ;
    PORT
      LAYER M4 ;
        RECT  194.316 156.192 194.4 156.216 ;
    END
  END ps_line[590]
  PIN ps_line[591]
    DIRECTION OUTPUT ;
    USE SIGNAL ;
    PORT
      LAYER M4 ;
        RECT  194.316 156.288 194.4 156.312 ;
    END
  END ps_line[591]
  PIN ps_line[59]
    DIRECTION OUTPUT ;
    USE SIGNAL ;
    PORT
      LAYER M4 ;
        RECT  194.316 105.216 194.4 105.24 ;
    END
  END ps_line[59]
  PIN ps_line[5]
    DIRECTION OUTPUT ;
    USE SIGNAL ;
    PORT
      LAYER M4 ;
        RECT  194.316 100.032 194.4 100.056 ;
    END
  END ps_line[5]
  PIN ps_line[60]
    DIRECTION OUTPUT ;
    USE SIGNAL ;
    PORT
      LAYER M4 ;
        RECT  194.316 105.312 194.4 105.336 ;
    END
  END ps_line[60]
  PIN ps_line[61]
    DIRECTION OUTPUT ;
    USE SIGNAL ;
    PORT
      LAYER M4 ;
        RECT  194.316 105.408 194.4 105.432 ;
    END
  END ps_line[61]
  PIN ps_line[62]
    DIRECTION OUTPUT ;
    USE SIGNAL ;
    PORT
      LAYER M4 ;
        RECT  194.316 105.504 194.4 105.528 ;
    END
  END ps_line[62]
  PIN ps_line[63]
    DIRECTION OUTPUT ;
    USE SIGNAL ;
    PORT
      LAYER M4 ;
        RECT  194.316 105.6 194.4 105.624 ;
    END
  END ps_line[63]
  PIN ps_line[64]
    DIRECTION OUTPUT ;
    USE SIGNAL ;
    PORT
      LAYER M4 ;
        RECT  194.316 105.696 194.4 105.72 ;
    END
  END ps_line[64]
  PIN ps_line[65]
    DIRECTION OUTPUT ;
    USE SIGNAL ;
    PORT
      LAYER M4 ;
        RECT  194.316 105.792 194.4 105.816 ;
    END
  END ps_line[65]
  PIN ps_line[66]
    DIRECTION OUTPUT ;
    USE SIGNAL ;
    PORT
      LAYER M4 ;
        RECT  194.316 105.888 194.4 105.912 ;
    END
  END ps_line[66]
  PIN ps_line[67]
    DIRECTION OUTPUT ;
    USE SIGNAL ;
    PORT
      LAYER M4 ;
        RECT  194.316 105.984 194.4 106.008 ;
    END
  END ps_line[67]
  PIN ps_line[68]
    DIRECTION OUTPUT ;
    USE SIGNAL ;
    PORT
      LAYER M4 ;
        RECT  194.316 106.08 194.4 106.104 ;
    END
  END ps_line[68]
  PIN ps_line[69]
    DIRECTION OUTPUT ;
    USE SIGNAL ;
    PORT
      LAYER M4 ;
        RECT  194.316 106.176 194.4 106.2 ;
    END
  END ps_line[69]
  PIN ps_line[6]
    DIRECTION OUTPUT ;
    USE SIGNAL ;
    PORT
      LAYER M4 ;
        RECT  194.316 100.128 194.4 100.152 ;
    END
  END ps_line[6]
  PIN ps_line[70]
    DIRECTION OUTPUT ;
    USE SIGNAL ;
    PORT
      LAYER M4 ;
        RECT  194.316 106.272 194.4 106.296 ;
    END
  END ps_line[70]
  PIN ps_line[71]
    DIRECTION OUTPUT ;
    USE SIGNAL ;
    PORT
      LAYER M4 ;
        RECT  194.316 106.368 194.4 106.392 ;
    END
  END ps_line[71]
  PIN ps_line[72]
    DIRECTION OUTPUT ;
    USE SIGNAL ;
    PORT
      LAYER M4 ;
        RECT  194.316 106.464 194.4 106.488 ;
    END
  END ps_line[72]
  PIN ps_line[73]
    DIRECTION OUTPUT ;
    USE SIGNAL ;
    PORT
      LAYER M4 ;
        RECT  194.316 106.56 194.4 106.584 ;
    END
  END ps_line[73]
  PIN ps_line[74]
    DIRECTION OUTPUT ;
    USE SIGNAL ;
    PORT
      LAYER M4 ;
        RECT  194.316 106.656 194.4 106.68 ;
    END
  END ps_line[74]
  PIN ps_line[75]
    DIRECTION OUTPUT ;
    USE SIGNAL ;
    PORT
      LAYER M4 ;
        RECT  194.316 106.752 194.4 106.776 ;
    END
  END ps_line[75]
  PIN ps_line[76]
    DIRECTION OUTPUT ;
    USE SIGNAL ;
    PORT
      LAYER M4 ;
        RECT  194.316 106.848 194.4 106.872 ;
    END
  END ps_line[76]
  PIN ps_line[77]
    DIRECTION OUTPUT ;
    USE SIGNAL ;
    PORT
      LAYER M4 ;
        RECT  194.316 106.944 194.4 106.968 ;
    END
  END ps_line[77]
  PIN ps_line[78]
    DIRECTION OUTPUT ;
    USE SIGNAL ;
    PORT
      LAYER M4 ;
        RECT  194.316 107.04 194.4 107.064 ;
    END
  END ps_line[78]
  PIN ps_line[79]
    DIRECTION OUTPUT ;
    USE SIGNAL ;
    PORT
      LAYER M4 ;
        RECT  194.316 107.136 194.4 107.16 ;
    END
  END ps_line[79]
  PIN ps_line[7]
    DIRECTION OUTPUT ;
    USE SIGNAL ;
    PORT
      LAYER M4 ;
        RECT  194.316 100.224 194.4 100.248 ;
    END
  END ps_line[7]
  PIN ps_line[80]
    DIRECTION OUTPUT ;
    USE SIGNAL ;
    PORT
      LAYER M4 ;
        RECT  194.316 107.232 194.4 107.256 ;
    END
  END ps_line[80]
  PIN ps_line[81]
    DIRECTION OUTPUT ;
    USE SIGNAL ;
    PORT
      LAYER M4 ;
        RECT  194.316 107.328 194.4 107.352 ;
    END
  END ps_line[81]
  PIN ps_line[82]
    DIRECTION OUTPUT ;
    USE SIGNAL ;
    PORT
      LAYER M4 ;
        RECT  194.316 107.424 194.4 107.448 ;
    END
  END ps_line[82]
  PIN ps_line[83]
    DIRECTION OUTPUT ;
    USE SIGNAL ;
    PORT
      LAYER M4 ;
        RECT  194.316 107.52 194.4 107.544 ;
    END
  END ps_line[83]
  PIN ps_line[84]
    DIRECTION OUTPUT ;
    USE SIGNAL ;
    PORT
      LAYER M4 ;
        RECT  194.316 107.616 194.4 107.64 ;
    END
  END ps_line[84]
  PIN ps_line[85]
    DIRECTION OUTPUT ;
    USE SIGNAL ;
    PORT
      LAYER M4 ;
        RECT  194.316 107.712 194.4 107.736 ;
    END
  END ps_line[85]
  PIN ps_line[86]
    DIRECTION OUTPUT ;
    USE SIGNAL ;
    PORT
      LAYER M4 ;
        RECT  194.316 107.808 194.4 107.832 ;
    END
  END ps_line[86]
  PIN ps_line[87]
    DIRECTION OUTPUT ;
    USE SIGNAL ;
    PORT
      LAYER M4 ;
        RECT  194.316 107.904 194.4 107.928 ;
    END
  END ps_line[87]
  PIN ps_line[88]
    DIRECTION OUTPUT ;
    USE SIGNAL ;
    PORT
      LAYER M4 ;
        RECT  194.316 108 194.4 108.024 ;
    END
  END ps_line[88]
  PIN ps_line[89]
    DIRECTION OUTPUT ;
    USE SIGNAL ;
    PORT
      LAYER M4 ;
        RECT  194.316 108.096 194.4 108.12 ;
    END
  END ps_line[89]
  PIN ps_line[8]
    DIRECTION OUTPUT ;
    USE SIGNAL ;
    PORT
      LAYER M4 ;
        RECT  194.316 100.32 194.4 100.344 ;
    END
  END ps_line[8]
  PIN ps_line[90]
    DIRECTION OUTPUT ;
    USE SIGNAL ;
    PORT
      LAYER M4 ;
        RECT  194.316 108.192 194.4 108.216 ;
    END
  END ps_line[90]
  PIN ps_line[91]
    DIRECTION OUTPUT ;
    USE SIGNAL ;
    PORT
      LAYER M4 ;
        RECT  194.316 108.288 194.4 108.312 ;
    END
  END ps_line[91]
  PIN ps_line[92]
    DIRECTION OUTPUT ;
    USE SIGNAL ;
    PORT
      LAYER M4 ;
        RECT  194.316 108.384 194.4 108.408 ;
    END
  END ps_line[92]
  PIN ps_line[93]
    DIRECTION OUTPUT ;
    USE SIGNAL ;
    PORT
      LAYER M4 ;
        RECT  194.316 108.48 194.4 108.504 ;
    END
  END ps_line[93]
  PIN ps_line[94]
    DIRECTION OUTPUT ;
    USE SIGNAL ;
    PORT
      LAYER M4 ;
        RECT  194.316 108.576 194.4 108.6 ;
    END
  END ps_line[94]
  PIN ps_line[95]
    DIRECTION OUTPUT ;
    USE SIGNAL ;
    PORT
      LAYER M4 ;
        RECT  194.316 108.672 194.4 108.696 ;
    END
  END ps_line[95]
  PIN ps_line[96]
    DIRECTION OUTPUT ;
    USE SIGNAL ;
    PORT
      LAYER M4 ;
        RECT  194.316 108.768 194.4 108.792 ;
    END
  END ps_line[96]
  PIN ps_line[97]
    DIRECTION OUTPUT ;
    USE SIGNAL ;
    PORT
      LAYER M4 ;
        RECT  194.316 108.864 194.4 108.888 ;
    END
  END ps_line[97]
  PIN ps_line[98]
    DIRECTION OUTPUT ;
    USE SIGNAL ;
    PORT
      LAYER M4 ;
        RECT  194.316 108.96 194.4 108.984 ;
    END
  END ps_line[98]
  PIN ps_line[99]
    DIRECTION OUTPUT ;
    USE SIGNAL ;
    PORT
      LAYER M4 ;
        RECT  194.316 109.056 194.4 109.08 ;
    END
  END ps_line[99]
  PIN ps_line[9]
    DIRECTION OUTPUT ;
    USE SIGNAL ;
    PORT
      LAYER M4 ;
        RECT  194.316 100.416 194.4 100.44 ;
    END
  END ps_line[9]
  PIN ps_lv[0]
    DIRECTION OUTPUT ;
    USE SIGNAL ;
    PORT
      LAYER M4 ;
        RECT  194.316 41.184 194.4 41.208 ;
    END
  END ps_lv[0]
  PIN ps_lv[10]
    DIRECTION OUTPUT ;
    USE SIGNAL ;
    PORT
      LAYER M4 ;
        RECT  194.316 42.144 194.4 42.168 ;
    END
  END ps_lv[10]
  PIN ps_lv[11]
    DIRECTION OUTPUT ;
    USE SIGNAL ;
    PORT
      LAYER M4 ;
        RECT  194.316 42.24 194.4 42.264 ;
    END
  END ps_lv[11]
  PIN ps_lv[12]
    DIRECTION OUTPUT ;
    USE SIGNAL ;
    PORT
      LAYER M4 ;
        RECT  194.316 42.336 194.4 42.36 ;
    END
  END ps_lv[12]
  PIN ps_lv[13]
    DIRECTION OUTPUT ;
    USE SIGNAL ;
    PORT
      LAYER M4 ;
        RECT  194.316 42.432 194.4 42.456 ;
    END
  END ps_lv[13]
  PIN ps_lv[14]
    DIRECTION OUTPUT ;
    USE SIGNAL ;
    PORT
      LAYER M4 ;
        RECT  194.316 42.528 194.4 42.552 ;
    END
  END ps_lv[14]
  PIN ps_lv[15]
    DIRECTION OUTPUT ;
    USE SIGNAL ;
    PORT
      LAYER M4 ;
        RECT  194.316 42.624 194.4 42.648 ;
    END
  END ps_lv[15]
  PIN ps_lv[1]
    DIRECTION OUTPUT ;
    USE SIGNAL ;
    PORT
      LAYER M4 ;
        RECT  194.316 41.28 194.4 41.304 ;
    END
  END ps_lv[1]
  PIN ps_lv[2]
    DIRECTION OUTPUT ;
    USE SIGNAL ;
    PORT
      LAYER M4 ;
        RECT  194.316 41.376 194.4 41.4 ;
    END
  END ps_lv[2]
  PIN ps_lv[3]
    DIRECTION OUTPUT ;
    USE SIGNAL ;
    PORT
      LAYER M4 ;
        RECT  194.316 41.472 194.4 41.496 ;
    END
  END ps_lv[3]
  PIN ps_lv[4]
    DIRECTION OUTPUT ;
    USE SIGNAL ;
    PORT
      LAYER M4 ;
        RECT  194.316 41.568 194.4 41.592 ;
    END
  END ps_lv[4]
  PIN ps_lv[5]
    DIRECTION OUTPUT ;
    USE SIGNAL ;
    PORT
      LAYER M4 ;
        RECT  194.316 41.664 194.4 41.688 ;
    END
  END ps_lv[5]
  PIN ps_lv[6]
    DIRECTION OUTPUT ;
    USE SIGNAL ;
    PORT
      LAYER M4 ;
        RECT  194.316 41.76 194.4 41.784 ;
    END
  END ps_lv[6]
  PIN ps_lv[7]
    DIRECTION OUTPUT ;
    USE SIGNAL ;
    PORT
      LAYER M4 ;
        RECT  194.316 41.856 194.4 41.88 ;
    END
  END ps_lv[7]
  PIN ps_lv[8]
    DIRECTION OUTPUT ;
    USE SIGNAL ;
    PORT
      LAYER M4 ;
        RECT  194.316 41.952 194.4 41.976 ;
    END
  END ps_lv[8]
  PIN ps_lv[9]
    DIRECTION OUTPUT ;
    USE SIGNAL ;
    PORT
      LAYER M4 ;
        RECT  194.316 42.048 194.4 42.072 ;
    END
  END ps_lv[9]
  PIN ps_vp[0]
    DIRECTION OUTPUT ;
    USE SIGNAL ;
    PORT
      LAYER M4 ;
        RECT  194.316 40.416 194.4 40.44 ;
    END
  END ps_vp[0]
  PIN ps_vp[1]
    DIRECTION OUTPUT ;
    USE SIGNAL ;
    PORT
      LAYER M4 ;
        RECT  194.316 40.512 194.4 40.536 ;
    END
  END ps_vp[1]
  PIN ps_vp[2]
    DIRECTION OUTPUT ;
    USE SIGNAL ;
    PORT
      LAYER M4 ;
        RECT  194.316 40.608 194.4 40.632 ;
    END
  END ps_vp[2]
  PIN ps_vp[3]
    DIRECTION OUTPUT ;
    USE SIGNAL ;
    PORT
      LAYER M4 ;
        RECT  194.316 40.704 194.4 40.728 ;
    END
  END ps_vp[3]
  PIN ps_vp[4]
    DIRECTION OUTPUT ;
    USE SIGNAL ;
    PORT
      LAYER M4 ;
        RECT  194.316 40.8 194.4 40.824 ;
    END
  END ps_vp[4]
  PIN ps_vp[5]
    DIRECTION OUTPUT ;
    USE SIGNAL ;
    PORT
      LAYER M4 ;
        RECT  194.316 40.896 194.4 40.92 ;
    END
  END ps_vp[5]
  PIN rst_n
    DIRECTION INPUT ;
    USE SIGNAL ;
    PORT
      LAYER M4 ;
        RECT  0 38.688 0.084 38.712 ;
    END
  END rst_n
END ot_s81ph_hq_pk2

END LIBRARY
